VERSION 5.8 ;
BUSBITCHARS "[]" ;
DIVIDERCHAR "/" ;
UNITS
    DATABASE MICRONS 1000 ;
END UNITS

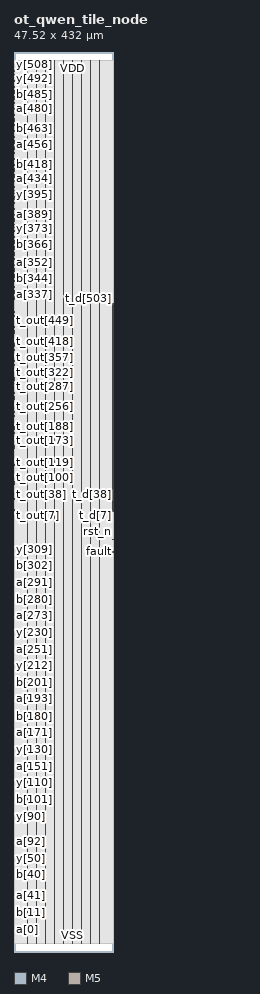
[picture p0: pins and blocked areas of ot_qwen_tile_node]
MACRO ot_qwen_tile_node
  FOREIGN ot_qwen_tile_node 0 0 ;
  CLASS BLOCK ;
  SIZE 47.52 BY 432 ;
  PIN a[0]
    DIRECTION INPUT ;
    USE SIGNAL ;
    PORT
      LAYER M4 ;
        RECT  0 10.896 0.084 10.92 ;
    END
  END a[0]
  PIN a[100]
    DIRECTION INPUT ;
    USE SIGNAL ;
    PORT
      LAYER M4 ;
        RECT  0 66.96 0.084 66.984 ;
    END
  END a[100]
  PIN a[101]
    DIRECTION INPUT ;
    USE SIGNAL ;
    PORT
      LAYER M4 ;
        RECT  0 67.152 0.084 67.176 ;
    END
  END a[101]
  PIN a[102]
    DIRECTION INPUT ;
    USE SIGNAL ;
    PORT
      LAYER M4 ;
        RECT  0 67.344 0.084 67.368 ;
    END
  END a[102]
  PIN a[103]
    DIRECTION INPUT ;
    USE SIGNAL ;
    PORT
      LAYER M4 ;
        RECT  0 67.536 0.084 67.56 ;
    END
  END a[103]
  PIN a[104]
    DIRECTION INPUT ;
    USE SIGNAL ;
    PORT
      LAYER M4 ;
        RECT  0 67.728 0.084 67.752 ;
    END
  END a[104]
  PIN a[105]
    DIRECTION INPUT ;
    USE SIGNAL ;
    PORT
      LAYER M4 ;
        RECT  0 67.92 0.084 67.944 ;
    END
  END a[105]
  PIN a[106]
    DIRECTION INPUT ;
    USE SIGNAL ;
    PORT
      LAYER M4 ;
        RECT  0 68.112 0.084 68.136 ;
    END
  END a[106]
  PIN a[107]
    DIRECTION INPUT ;
    USE SIGNAL ;
    PORT
      LAYER M4 ;
        RECT  0 68.304 0.084 68.328 ;
    END
  END a[107]
  PIN a[108]
    DIRECTION INPUT ;
    USE SIGNAL ;
    PORT
      LAYER M4 ;
        RECT  0 68.496 0.084 68.52 ;
    END
  END a[108]
  PIN a[109]
    DIRECTION INPUT ;
    USE SIGNAL ;
    PORT
      LAYER M4 ;
        RECT  0 68.688 0.084 68.712 ;
    END
  END a[109]
  PIN a[10]
    DIRECTION INPUT ;
    USE SIGNAL ;
    PORT
      LAYER M4 ;
        RECT  0 12.816 0.084 12.84 ;
    END
  END a[10]
  PIN a[110]
    DIRECTION INPUT ;
    USE SIGNAL ;
    PORT
      LAYER M4 ;
        RECT  0 68.88 0.084 68.904 ;
    END
  END a[110]
  PIN a[111]
    DIRECTION INPUT ;
    USE SIGNAL ;
    PORT
      LAYER M4 ;
        RECT  0 69.072 0.084 69.096 ;
    END
  END a[111]
  PIN a[112]
    DIRECTION INPUT ;
    USE SIGNAL ;
    PORT
      LAYER M4 ;
        RECT  0 69.264 0.084 69.288 ;
    END
  END a[112]
  PIN a[113]
    DIRECTION INPUT ;
    USE SIGNAL ;
    PORT
      LAYER M4 ;
        RECT  0 69.456 0.084 69.48 ;
    END
  END a[113]
  PIN a[114]
    DIRECTION INPUT ;
    USE SIGNAL ;
    PORT
      LAYER M4 ;
        RECT  0 69.648 0.084 69.672 ;
    END
  END a[114]
  PIN a[115]
    DIRECTION INPUT ;
    USE SIGNAL ;
    PORT
      LAYER M4 ;
        RECT  0 69.84 0.084 69.864 ;
    END
  END a[115]
  PIN a[116]
    DIRECTION INPUT ;
    USE SIGNAL ;
    PORT
      LAYER M4 ;
        RECT  0 70.032 0.084 70.056 ;
    END
  END a[116]
  PIN a[117]
    DIRECTION INPUT ;
    USE SIGNAL ;
    PORT
      LAYER M4 ;
        RECT  0 70.224 0.084 70.248 ;
    END
  END a[117]
  PIN a[118]
    DIRECTION INPUT ;
    USE SIGNAL ;
    PORT
      LAYER M4 ;
        RECT  0 70.416 0.084 70.44 ;
    END
  END a[118]
  PIN a[119]
    DIRECTION INPUT ;
    USE SIGNAL ;
    PORT
      LAYER M4 ;
        RECT  0 70.608 0.084 70.632 ;
    END
  END a[119]
  PIN a[11]
    DIRECTION INPUT ;
    USE SIGNAL ;
    PORT
      LAYER M4 ;
        RECT  0 13.008 0.084 13.032 ;
    END
  END a[11]
  PIN a[120]
    DIRECTION INPUT ;
    USE SIGNAL ;
    PORT
      LAYER M4 ;
        RECT  0 70.8 0.084 70.824 ;
    END
  END a[120]
  PIN a[121]
    DIRECTION INPUT ;
    USE SIGNAL ;
    PORT
      LAYER M4 ;
        RECT  0 70.992 0.084 71.016 ;
    END
  END a[121]
  PIN a[122]
    DIRECTION INPUT ;
    USE SIGNAL ;
    PORT
      LAYER M4 ;
        RECT  0 71.184 0.084 71.208 ;
    END
  END a[122]
  PIN a[123]
    DIRECTION INPUT ;
    USE SIGNAL ;
    PORT
      LAYER M4 ;
        RECT  0 71.376 0.084 71.4 ;
    END
  END a[123]
  PIN a[124]
    DIRECTION INPUT ;
    USE SIGNAL ;
    PORT
      LAYER M4 ;
        RECT  0 71.568 0.084 71.592 ;
    END
  END a[124]
  PIN a[125]
    DIRECTION INPUT ;
    USE SIGNAL ;
    PORT
      LAYER M4 ;
        RECT  0 71.76 0.084 71.784 ;
    END
  END a[125]
  PIN a[126]
    DIRECTION INPUT ;
    USE SIGNAL ;
    PORT
      LAYER M4 ;
        RECT  0 71.952 0.084 71.976 ;
    END
  END a[126]
  PIN a[127]
    DIRECTION INPUT ;
    USE SIGNAL ;
    PORT
      LAYER M4 ;
        RECT  0 72.144 0.084 72.168 ;
    END
  END a[127]
  PIN a[128]
    DIRECTION INPUT ;
    USE SIGNAL ;
    PORT
      LAYER M4 ;
        RECT  0 84.624 0.084 84.648 ;
    END
  END a[128]
  PIN a[129]
    DIRECTION INPUT ;
    USE SIGNAL ;
    PORT
      LAYER M4 ;
        RECT  0 84.816 0.084 84.84 ;
    END
  END a[129]
  PIN a[12]
    DIRECTION INPUT ;
    USE SIGNAL ;
    PORT
      LAYER M4 ;
        RECT  0 13.2 0.084 13.224 ;
    END
  END a[12]
  PIN a[130]
    DIRECTION INPUT ;
    USE SIGNAL ;
    PORT
      LAYER M4 ;
        RECT  0 85.008 0.084 85.032 ;
    END
  END a[130]
  PIN a[131]
    DIRECTION INPUT ;
    USE SIGNAL ;
    PORT
      LAYER M4 ;
        RECT  0 85.2 0.084 85.224 ;
    END
  END a[131]
  PIN a[132]
    DIRECTION INPUT ;
    USE SIGNAL ;
    PORT
      LAYER M4 ;
        RECT  0 85.392 0.084 85.416 ;
    END
  END a[132]
  PIN a[133]
    DIRECTION INPUT ;
    USE SIGNAL ;
    PORT
      LAYER M4 ;
        RECT  0 85.584 0.084 85.608 ;
    END
  END a[133]
  PIN a[134]
    DIRECTION INPUT ;
    USE SIGNAL ;
    PORT
      LAYER M4 ;
        RECT  0 85.776 0.084 85.8 ;
    END
  END a[134]
  PIN a[135]
    DIRECTION INPUT ;
    USE SIGNAL ;
    PORT
      LAYER M4 ;
        RECT  0 85.968 0.084 85.992 ;
    END
  END a[135]
  PIN a[136]
    DIRECTION INPUT ;
    USE SIGNAL ;
    PORT
      LAYER M4 ;
        RECT  0 86.16 0.084 86.184 ;
    END
  END a[136]
  PIN a[137]
    DIRECTION INPUT ;
    USE SIGNAL ;
    PORT
      LAYER M4 ;
        RECT  0 86.352 0.084 86.376 ;
    END
  END a[137]
  PIN a[138]
    DIRECTION INPUT ;
    USE SIGNAL ;
    PORT
      LAYER M4 ;
        RECT  0 86.544 0.084 86.568 ;
    END
  END a[138]
  PIN a[139]
    DIRECTION INPUT ;
    USE SIGNAL ;
    PORT
      LAYER M4 ;
        RECT  0 86.736 0.084 86.76 ;
    END
  END a[139]
  PIN a[13]
    DIRECTION INPUT ;
    USE SIGNAL ;
    PORT
      LAYER M4 ;
        RECT  0 13.392 0.084 13.416 ;
    END
  END a[13]
  PIN a[140]
    DIRECTION INPUT ;
    USE SIGNAL ;
    PORT
      LAYER M4 ;
        RECT  0 86.928 0.084 86.952 ;
    END
  END a[140]
  PIN a[141]
    DIRECTION INPUT ;
    USE SIGNAL ;
    PORT
      LAYER M4 ;
        RECT  0 87.12 0.084 87.144 ;
    END
  END a[141]
  PIN a[142]
    DIRECTION INPUT ;
    USE SIGNAL ;
    PORT
      LAYER M4 ;
        RECT  0 87.312 0.084 87.336 ;
    END
  END a[142]
  PIN a[143]
    DIRECTION INPUT ;
    USE SIGNAL ;
    PORT
      LAYER M4 ;
        RECT  0 87.504 0.084 87.528 ;
    END
  END a[143]
  PIN a[144]
    DIRECTION INPUT ;
    USE SIGNAL ;
    PORT
      LAYER M4 ;
        RECT  0 87.696 0.084 87.72 ;
    END
  END a[144]
  PIN a[145]
    DIRECTION INPUT ;
    USE SIGNAL ;
    PORT
      LAYER M4 ;
        RECT  0 87.888 0.084 87.912 ;
    END
  END a[145]
  PIN a[146]
    DIRECTION INPUT ;
    USE SIGNAL ;
    PORT
      LAYER M4 ;
        RECT  0 88.08 0.084 88.104 ;
    END
  END a[146]
  PIN a[147]
    DIRECTION INPUT ;
    USE SIGNAL ;
    PORT
      LAYER M4 ;
        RECT  0 88.272 0.084 88.296 ;
    END
  END a[147]
  PIN a[148]
    DIRECTION INPUT ;
    USE SIGNAL ;
    PORT
      LAYER M4 ;
        RECT  0 88.464 0.084 88.488 ;
    END
  END a[148]
  PIN a[149]
    DIRECTION INPUT ;
    USE SIGNAL ;
    PORT
      LAYER M4 ;
        RECT  0 88.656 0.084 88.68 ;
    END
  END a[149]
  PIN a[14]
    DIRECTION INPUT ;
    USE SIGNAL ;
    PORT
      LAYER M4 ;
        RECT  0 13.584 0.084 13.608 ;
    END
  END a[14]
  PIN a[150]
    DIRECTION INPUT ;
    USE SIGNAL ;
    PORT
      LAYER M4 ;
        RECT  0 88.848 0.084 88.872 ;
    END
  END a[150]
  PIN a[151]
    DIRECTION INPUT ;
    USE SIGNAL ;
    PORT
      LAYER M4 ;
        RECT  0 89.04 0.084 89.064 ;
    END
  END a[151]
  PIN a[152]
    DIRECTION INPUT ;
    USE SIGNAL ;
    PORT
      LAYER M4 ;
        RECT  0 89.232 0.084 89.256 ;
    END
  END a[152]
  PIN a[153]
    DIRECTION INPUT ;
    USE SIGNAL ;
    PORT
      LAYER M4 ;
        RECT  0 89.424 0.084 89.448 ;
    END
  END a[153]
  PIN a[154]
    DIRECTION INPUT ;
    USE SIGNAL ;
    PORT
      LAYER M4 ;
        RECT  0 89.616 0.084 89.64 ;
    END
  END a[154]
  PIN a[155]
    DIRECTION INPUT ;
    USE SIGNAL ;
    PORT
      LAYER M4 ;
        RECT  0 89.808 0.084 89.832 ;
    END
  END a[155]
  PIN a[156]
    DIRECTION INPUT ;
    USE SIGNAL ;
    PORT
      LAYER M4 ;
        RECT  0 90 0.084 90.024 ;
    END
  END a[156]
  PIN a[157]
    DIRECTION INPUT ;
    USE SIGNAL ;
    PORT
      LAYER M4 ;
        RECT  0 90.192 0.084 90.216 ;
    END
  END a[157]
  PIN a[158]
    DIRECTION INPUT ;
    USE SIGNAL ;
    PORT
      LAYER M4 ;
        RECT  0 90.384 0.084 90.408 ;
    END
  END a[158]
  PIN a[159]
    DIRECTION INPUT ;
    USE SIGNAL ;
    PORT
      LAYER M4 ;
        RECT  0 90.576 0.084 90.6 ;
    END
  END a[159]
  PIN a[15]
    DIRECTION INPUT ;
    USE SIGNAL ;
    PORT
      LAYER M4 ;
        RECT  0 13.776 0.084 13.8 ;
    END
  END a[15]
  PIN a[160]
    DIRECTION INPUT ;
    USE SIGNAL ;
    PORT
      LAYER M4 ;
        RECT  0 103.056 0.084 103.08 ;
    END
  END a[160]
  PIN a[161]
    DIRECTION INPUT ;
    USE SIGNAL ;
    PORT
      LAYER M4 ;
        RECT  0 103.248 0.084 103.272 ;
    END
  END a[161]
  PIN a[162]
    DIRECTION INPUT ;
    USE SIGNAL ;
    PORT
      LAYER M4 ;
        RECT  0 103.44 0.084 103.464 ;
    END
  END a[162]
  PIN a[163]
    DIRECTION INPUT ;
    USE SIGNAL ;
    PORT
      LAYER M4 ;
        RECT  0 103.632 0.084 103.656 ;
    END
  END a[163]
  PIN a[164]
    DIRECTION INPUT ;
    USE SIGNAL ;
    PORT
      LAYER M4 ;
        RECT  0 103.824 0.084 103.848 ;
    END
  END a[164]
  PIN a[165]
    DIRECTION INPUT ;
    USE SIGNAL ;
    PORT
      LAYER M4 ;
        RECT  0 104.016 0.084 104.04 ;
    END
  END a[165]
  PIN a[166]
    DIRECTION INPUT ;
    USE SIGNAL ;
    PORT
      LAYER M4 ;
        RECT  0 104.208 0.084 104.232 ;
    END
  END a[166]
  PIN a[167]
    DIRECTION INPUT ;
    USE SIGNAL ;
    PORT
      LAYER M4 ;
        RECT  0 104.4 0.084 104.424 ;
    END
  END a[167]
  PIN a[168]
    DIRECTION INPUT ;
    USE SIGNAL ;
    PORT
      LAYER M4 ;
        RECT  0 104.592 0.084 104.616 ;
    END
  END a[168]
  PIN a[169]
    DIRECTION INPUT ;
    USE SIGNAL ;
    PORT
      LAYER M4 ;
        RECT  0 104.784 0.084 104.808 ;
    END
  END a[169]
  PIN a[16]
    DIRECTION INPUT ;
    USE SIGNAL ;
    PORT
      LAYER M4 ;
        RECT  0 13.968 0.084 13.992 ;
    END
  END a[16]
  PIN a[170]
    DIRECTION INPUT ;
    USE SIGNAL ;
    PORT
      LAYER M4 ;
        RECT  0 104.976 0.084 105 ;
    END
  END a[170]
  PIN a[171]
    DIRECTION INPUT ;
    USE SIGNAL ;
    PORT
      LAYER M4 ;
        RECT  0 105.168 0.084 105.192 ;
    END
  END a[171]
  PIN a[172]
    DIRECTION INPUT ;
    USE SIGNAL ;
    PORT
      LAYER M4 ;
        RECT  0 105.36 0.084 105.384 ;
    END
  END a[172]
  PIN a[173]
    DIRECTION INPUT ;
    USE SIGNAL ;
    PORT
      LAYER M4 ;
        RECT  0 105.552 0.084 105.576 ;
    END
  END a[173]
  PIN a[174]
    DIRECTION INPUT ;
    USE SIGNAL ;
    PORT
      LAYER M4 ;
        RECT  0 105.744 0.084 105.768 ;
    END
  END a[174]
  PIN a[175]
    DIRECTION INPUT ;
    USE SIGNAL ;
    PORT
      LAYER M4 ;
        RECT  0 105.936 0.084 105.96 ;
    END
  END a[175]
  PIN a[176]
    DIRECTION INPUT ;
    USE SIGNAL ;
    PORT
      LAYER M4 ;
        RECT  0 106.128 0.084 106.152 ;
    END
  END a[176]
  PIN a[177]
    DIRECTION INPUT ;
    USE SIGNAL ;
    PORT
      LAYER M4 ;
        RECT  0 106.32 0.084 106.344 ;
    END
  END a[177]
  PIN a[178]
    DIRECTION INPUT ;
    USE SIGNAL ;
    PORT
      LAYER M4 ;
        RECT  0 106.512 0.084 106.536 ;
    END
  END a[178]
  PIN a[179]
    DIRECTION INPUT ;
    USE SIGNAL ;
    PORT
      LAYER M4 ;
        RECT  0 106.704 0.084 106.728 ;
    END
  END a[179]
  PIN a[17]
    DIRECTION INPUT ;
    USE SIGNAL ;
    PORT
      LAYER M4 ;
        RECT  0 14.16 0.084 14.184 ;
    END
  END a[17]
  PIN a[180]
    DIRECTION INPUT ;
    USE SIGNAL ;
    PORT
      LAYER M4 ;
        RECT  0 106.896 0.084 106.92 ;
    END
  END a[180]
  PIN a[181]
    DIRECTION INPUT ;
    USE SIGNAL ;
    PORT
      LAYER M4 ;
        RECT  0 107.088 0.084 107.112 ;
    END
  END a[181]
  PIN a[182]
    DIRECTION INPUT ;
    USE SIGNAL ;
    PORT
      LAYER M4 ;
        RECT  0 107.28 0.084 107.304 ;
    END
  END a[182]
  PIN a[183]
    DIRECTION INPUT ;
    USE SIGNAL ;
    PORT
      LAYER M4 ;
        RECT  0 107.472 0.084 107.496 ;
    END
  END a[183]
  PIN a[184]
    DIRECTION INPUT ;
    USE SIGNAL ;
    PORT
      LAYER M4 ;
        RECT  0 107.664 0.084 107.688 ;
    END
  END a[184]
  PIN a[185]
    DIRECTION INPUT ;
    USE SIGNAL ;
    PORT
      LAYER M4 ;
        RECT  0 107.856 0.084 107.88 ;
    END
  END a[185]
  PIN a[186]
    DIRECTION INPUT ;
    USE SIGNAL ;
    PORT
      LAYER M4 ;
        RECT  0 108.048 0.084 108.072 ;
    END
  END a[186]
  PIN a[187]
    DIRECTION INPUT ;
    USE SIGNAL ;
    PORT
      LAYER M4 ;
        RECT  0 108.24 0.084 108.264 ;
    END
  END a[187]
  PIN a[188]
    DIRECTION INPUT ;
    USE SIGNAL ;
    PORT
      LAYER M4 ;
        RECT  0 108.432 0.084 108.456 ;
    END
  END a[188]
  PIN a[189]
    DIRECTION INPUT ;
    USE SIGNAL ;
    PORT
      LAYER M4 ;
        RECT  0 108.624 0.084 108.648 ;
    END
  END a[189]
  PIN a[18]
    DIRECTION INPUT ;
    USE SIGNAL ;
    PORT
      LAYER M4 ;
        RECT  0 14.352 0.084 14.376 ;
    END
  END a[18]
  PIN a[190]
    DIRECTION INPUT ;
    USE SIGNAL ;
    PORT
      LAYER M4 ;
        RECT  0 108.816 0.084 108.84 ;
    END
  END a[190]
  PIN a[191]
    DIRECTION INPUT ;
    USE SIGNAL ;
    PORT
      LAYER M4 ;
        RECT  0 109.008 0.084 109.032 ;
    END
  END a[191]
  PIN a[192]
    DIRECTION INPUT ;
    USE SIGNAL ;
    PORT
      LAYER M4 ;
        RECT  0 121.488 0.084 121.512 ;
    END
  END a[192]
  PIN a[193]
    DIRECTION INPUT ;
    USE SIGNAL ;
    PORT
      LAYER M4 ;
        RECT  0 121.68 0.084 121.704 ;
    END
  END a[193]
  PIN a[194]
    DIRECTION INPUT ;
    USE SIGNAL ;
    PORT
      LAYER M4 ;
        RECT  0 121.872 0.084 121.896 ;
    END
  END a[194]
  PIN a[195]
    DIRECTION INPUT ;
    USE SIGNAL ;
    PORT
      LAYER M4 ;
        RECT  0 122.064 0.084 122.088 ;
    END
  END a[195]
  PIN a[196]
    DIRECTION INPUT ;
    USE SIGNAL ;
    PORT
      LAYER M4 ;
        RECT  0 122.256 0.084 122.28 ;
    END
  END a[196]
  PIN a[197]
    DIRECTION INPUT ;
    USE SIGNAL ;
    PORT
      LAYER M4 ;
        RECT  0 122.448 0.084 122.472 ;
    END
  END a[197]
  PIN a[198]
    DIRECTION INPUT ;
    USE SIGNAL ;
    PORT
      LAYER M4 ;
        RECT  0 122.64 0.084 122.664 ;
    END
  END a[198]
  PIN a[199]
    DIRECTION INPUT ;
    USE SIGNAL ;
    PORT
      LAYER M4 ;
        RECT  0 122.832 0.084 122.856 ;
    END
  END a[199]
  PIN a[19]
    DIRECTION INPUT ;
    USE SIGNAL ;
    PORT
      LAYER M4 ;
        RECT  0 14.544 0.084 14.568 ;
    END
  END a[19]
  PIN a[1]
    DIRECTION INPUT ;
    USE SIGNAL ;
    PORT
      LAYER M4 ;
        RECT  0 11.088 0.084 11.112 ;
    END
  END a[1]
  PIN a[200]
    DIRECTION INPUT ;
    USE SIGNAL ;
    PORT
      LAYER M4 ;
        RECT  0 123.024 0.084 123.048 ;
    END
  END a[200]
  PIN a[201]
    DIRECTION INPUT ;
    USE SIGNAL ;
    PORT
      LAYER M4 ;
        RECT  0 123.216 0.084 123.24 ;
    END
  END a[201]
  PIN a[202]
    DIRECTION INPUT ;
    USE SIGNAL ;
    PORT
      LAYER M4 ;
        RECT  0 123.408 0.084 123.432 ;
    END
  END a[202]
  PIN a[203]
    DIRECTION INPUT ;
    USE SIGNAL ;
    PORT
      LAYER M4 ;
        RECT  0 123.6 0.084 123.624 ;
    END
  END a[203]
  PIN a[204]
    DIRECTION INPUT ;
    USE SIGNAL ;
    PORT
      LAYER M4 ;
        RECT  0 123.792 0.084 123.816 ;
    END
  END a[204]
  PIN a[205]
    DIRECTION INPUT ;
    USE SIGNAL ;
    PORT
      LAYER M4 ;
        RECT  0 123.984 0.084 124.008 ;
    END
  END a[205]
  PIN a[206]
    DIRECTION INPUT ;
    USE SIGNAL ;
    PORT
      LAYER M4 ;
        RECT  0 124.176 0.084 124.2 ;
    END
  END a[206]
  PIN a[207]
    DIRECTION INPUT ;
    USE SIGNAL ;
    PORT
      LAYER M4 ;
        RECT  0 124.368 0.084 124.392 ;
    END
  END a[207]
  PIN a[208]
    DIRECTION INPUT ;
    USE SIGNAL ;
    PORT
      LAYER M4 ;
        RECT  0 124.56 0.084 124.584 ;
    END
  END a[208]
  PIN a[209]
    DIRECTION INPUT ;
    USE SIGNAL ;
    PORT
      LAYER M4 ;
        RECT  0 124.752 0.084 124.776 ;
    END
  END a[209]
  PIN a[20]
    DIRECTION INPUT ;
    USE SIGNAL ;
    PORT
      LAYER M4 ;
        RECT  0 14.736 0.084 14.76 ;
    END
  END a[20]
  PIN a[210]
    DIRECTION INPUT ;
    USE SIGNAL ;
    PORT
      LAYER M4 ;
        RECT  0 124.944 0.084 124.968 ;
    END
  END a[210]
  PIN a[211]
    DIRECTION INPUT ;
    USE SIGNAL ;
    PORT
      LAYER M4 ;
        RECT  0 125.136 0.084 125.16 ;
    END
  END a[211]
  PIN a[212]
    DIRECTION INPUT ;
    USE SIGNAL ;
    PORT
      LAYER M4 ;
        RECT  0 125.328 0.084 125.352 ;
    END
  END a[212]
  PIN a[213]
    DIRECTION INPUT ;
    USE SIGNAL ;
    PORT
      LAYER M4 ;
        RECT  0 125.52 0.084 125.544 ;
    END
  END a[213]
  PIN a[214]
    DIRECTION INPUT ;
    USE SIGNAL ;
    PORT
      LAYER M4 ;
        RECT  0 125.712 0.084 125.736 ;
    END
  END a[214]
  PIN a[215]
    DIRECTION INPUT ;
    USE SIGNAL ;
    PORT
      LAYER M4 ;
        RECT  0 125.904 0.084 125.928 ;
    END
  END a[215]
  PIN a[216]
    DIRECTION INPUT ;
    USE SIGNAL ;
    PORT
      LAYER M4 ;
        RECT  0 126.096 0.084 126.12 ;
    END
  END a[216]
  PIN a[217]
    DIRECTION INPUT ;
    USE SIGNAL ;
    PORT
      LAYER M4 ;
        RECT  0 126.288 0.084 126.312 ;
    END
  END a[217]
  PIN a[218]
    DIRECTION INPUT ;
    USE SIGNAL ;
    PORT
      LAYER M4 ;
        RECT  0 126.48 0.084 126.504 ;
    END
  END a[218]
  PIN a[219]
    DIRECTION INPUT ;
    USE SIGNAL ;
    PORT
      LAYER M4 ;
        RECT  0 126.672 0.084 126.696 ;
    END
  END a[219]
  PIN a[21]
    DIRECTION INPUT ;
    USE SIGNAL ;
    PORT
      LAYER M4 ;
        RECT  0 14.928 0.084 14.952 ;
    END
  END a[21]
  PIN a[220]
    DIRECTION INPUT ;
    USE SIGNAL ;
    PORT
      LAYER M4 ;
        RECT  0 126.864 0.084 126.888 ;
    END
  END a[220]
  PIN a[221]
    DIRECTION INPUT ;
    USE SIGNAL ;
    PORT
      LAYER M4 ;
        RECT  0 127.056 0.084 127.08 ;
    END
  END a[221]
  PIN a[222]
    DIRECTION INPUT ;
    USE SIGNAL ;
    PORT
      LAYER M4 ;
        RECT  0 127.248 0.084 127.272 ;
    END
  END a[222]
  PIN a[223]
    DIRECTION INPUT ;
    USE SIGNAL ;
    PORT
      LAYER M4 ;
        RECT  0 127.44 0.084 127.464 ;
    END
  END a[223]
  PIN a[224]
    DIRECTION INPUT ;
    USE SIGNAL ;
    PORT
      LAYER M4 ;
        RECT  0 139.92 0.084 139.944 ;
    END
  END a[224]
  PIN a[225]
    DIRECTION INPUT ;
    USE SIGNAL ;
    PORT
      LAYER M4 ;
        RECT  0 140.112 0.084 140.136 ;
    END
  END a[225]
  PIN a[226]
    DIRECTION INPUT ;
    USE SIGNAL ;
    PORT
      LAYER M4 ;
        RECT  0 140.304 0.084 140.328 ;
    END
  END a[226]
  PIN a[227]
    DIRECTION INPUT ;
    USE SIGNAL ;
    PORT
      LAYER M4 ;
        RECT  0 140.496 0.084 140.52 ;
    END
  END a[227]
  PIN a[228]
    DIRECTION INPUT ;
    USE SIGNAL ;
    PORT
      LAYER M4 ;
        RECT  0 140.688 0.084 140.712 ;
    END
  END a[228]
  PIN a[229]
    DIRECTION INPUT ;
    USE SIGNAL ;
    PORT
      LAYER M4 ;
        RECT  0 140.88 0.084 140.904 ;
    END
  END a[229]
  PIN a[22]
    DIRECTION INPUT ;
    USE SIGNAL ;
    PORT
      LAYER M4 ;
        RECT  0 15.12 0.084 15.144 ;
    END
  END a[22]
  PIN a[230]
    DIRECTION INPUT ;
    USE SIGNAL ;
    PORT
      LAYER M4 ;
        RECT  0 141.072 0.084 141.096 ;
    END
  END a[230]
  PIN a[231]
    DIRECTION INPUT ;
    USE SIGNAL ;
    PORT
      LAYER M4 ;
        RECT  0 141.264 0.084 141.288 ;
    END
  END a[231]
  PIN a[232]
    DIRECTION INPUT ;
    USE SIGNAL ;
    PORT
      LAYER M4 ;
        RECT  0 141.456 0.084 141.48 ;
    END
  END a[232]
  PIN a[233]
    DIRECTION INPUT ;
    USE SIGNAL ;
    PORT
      LAYER M4 ;
        RECT  0 141.648 0.084 141.672 ;
    END
  END a[233]
  PIN a[234]
    DIRECTION INPUT ;
    USE SIGNAL ;
    PORT
      LAYER M4 ;
        RECT  0 141.84 0.084 141.864 ;
    END
  END a[234]
  PIN a[235]
    DIRECTION INPUT ;
    USE SIGNAL ;
    PORT
      LAYER M4 ;
        RECT  0 142.032 0.084 142.056 ;
    END
  END a[235]
  PIN a[236]
    DIRECTION INPUT ;
    USE SIGNAL ;
    PORT
      LAYER M4 ;
        RECT  0 142.224 0.084 142.248 ;
    END
  END a[236]
  PIN a[237]
    DIRECTION INPUT ;
    USE SIGNAL ;
    PORT
      LAYER M4 ;
        RECT  0 142.416 0.084 142.44 ;
    END
  END a[237]
  PIN a[238]
    DIRECTION INPUT ;
    USE SIGNAL ;
    PORT
      LAYER M4 ;
        RECT  0 142.608 0.084 142.632 ;
    END
  END a[238]
  PIN a[239]
    DIRECTION INPUT ;
    USE SIGNAL ;
    PORT
      LAYER M4 ;
        RECT  0 142.8 0.084 142.824 ;
    END
  END a[239]
  PIN a[23]
    DIRECTION INPUT ;
    USE SIGNAL ;
    PORT
      LAYER M4 ;
        RECT  0 15.312 0.084 15.336 ;
    END
  END a[23]
  PIN a[240]
    DIRECTION INPUT ;
    USE SIGNAL ;
    PORT
      LAYER M4 ;
        RECT  0 142.992 0.084 143.016 ;
    END
  END a[240]
  PIN a[241]
    DIRECTION INPUT ;
    USE SIGNAL ;
    PORT
      LAYER M4 ;
        RECT  0 143.184 0.084 143.208 ;
    END
  END a[241]
  PIN a[242]
    DIRECTION INPUT ;
    USE SIGNAL ;
    PORT
      LAYER M4 ;
        RECT  0 143.376 0.084 143.4 ;
    END
  END a[242]
  PIN a[243]
    DIRECTION INPUT ;
    USE SIGNAL ;
    PORT
      LAYER M4 ;
        RECT  0 143.568 0.084 143.592 ;
    END
  END a[243]
  PIN a[244]
    DIRECTION INPUT ;
    USE SIGNAL ;
    PORT
      LAYER M4 ;
        RECT  0 143.76 0.084 143.784 ;
    END
  END a[244]
  PIN a[245]
    DIRECTION INPUT ;
    USE SIGNAL ;
    PORT
      LAYER M4 ;
        RECT  0 143.952 0.084 143.976 ;
    END
  END a[245]
  PIN a[246]
    DIRECTION INPUT ;
    USE SIGNAL ;
    PORT
      LAYER M4 ;
        RECT  0 144.144 0.084 144.168 ;
    END
  END a[246]
  PIN a[247]
    DIRECTION INPUT ;
    USE SIGNAL ;
    PORT
      LAYER M4 ;
        RECT  0 144.336 0.084 144.36 ;
    END
  END a[247]
  PIN a[248]
    DIRECTION INPUT ;
    USE SIGNAL ;
    PORT
      LAYER M4 ;
        RECT  0 144.528 0.084 144.552 ;
    END
  END a[248]
  PIN a[249]
    DIRECTION INPUT ;
    USE SIGNAL ;
    PORT
      LAYER M4 ;
        RECT  0 144.72 0.084 144.744 ;
    END
  END a[249]
  PIN a[24]
    DIRECTION INPUT ;
    USE SIGNAL ;
    PORT
      LAYER M4 ;
        RECT  0 15.504 0.084 15.528 ;
    END
  END a[24]
  PIN a[250]
    DIRECTION INPUT ;
    USE SIGNAL ;
    PORT
      LAYER M4 ;
        RECT  0 144.912 0.084 144.936 ;
    END
  END a[250]
  PIN a[251]
    DIRECTION INPUT ;
    USE SIGNAL ;
    PORT
      LAYER M4 ;
        RECT  0 145.104 0.084 145.128 ;
    END
  END a[251]
  PIN a[252]
    DIRECTION INPUT ;
    USE SIGNAL ;
    PORT
      LAYER M4 ;
        RECT  0 145.296 0.084 145.32 ;
    END
  END a[252]
  PIN a[253]
    DIRECTION INPUT ;
    USE SIGNAL ;
    PORT
      LAYER M4 ;
        RECT  0 145.488 0.084 145.512 ;
    END
  END a[253]
  PIN a[254]
    DIRECTION INPUT ;
    USE SIGNAL ;
    PORT
      LAYER M4 ;
        RECT  0 145.68 0.084 145.704 ;
    END
  END a[254]
  PIN a[255]
    DIRECTION INPUT ;
    USE SIGNAL ;
    PORT
      LAYER M4 ;
        RECT  0 145.872 0.084 145.896 ;
    END
  END a[255]
  PIN a[256]
    DIRECTION INPUT ;
    USE SIGNAL ;
    PORT
      LAYER M4 ;
        RECT  0 158.352 0.084 158.376 ;
    END
  END a[256]
  PIN a[257]
    DIRECTION INPUT ;
    USE SIGNAL ;
    PORT
      LAYER M4 ;
        RECT  0 158.544 0.084 158.568 ;
    END
  END a[257]
  PIN a[258]
    DIRECTION INPUT ;
    USE SIGNAL ;
    PORT
      LAYER M4 ;
        RECT  0 158.736 0.084 158.76 ;
    END
  END a[258]
  PIN a[259]
    DIRECTION INPUT ;
    USE SIGNAL ;
    PORT
      LAYER M4 ;
        RECT  0 158.928 0.084 158.952 ;
    END
  END a[259]
  PIN a[25]
    DIRECTION INPUT ;
    USE SIGNAL ;
    PORT
      LAYER M4 ;
        RECT  0 15.696 0.084 15.72 ;
    END
  END a[25]
  PIN a[260]
    DIRECTION INPUT ;
    USE SIGNAL ;
    PORT
      LAYER M4 ;
        RECT  0 159.12 0.084 159.144 ;
    END
  END a[260]
  PIN a[261]
    DIRECTION INPUT ;
    USE SIGNAL ;
    PORT
      LAYER M4 ;
        RECT  0 159.312 0.084 159.336 ;
    END
  END a[261]
  PIN a[262]
    DIRECTION INPUT ;
    USE SIGNAL ;
    PORT
      LAYER M4 ;
        RECT  0 159.504 0.084 159.528 ;
    END
  END a[262]
  PIN a[263]
    DIRECTION INPUT ;
    USE SIGNAL ;
    PORT
      LAYER M4 ;
        RECT  0 159.696 0.084 159.72 ;
    END
  END a[263]
  PIN a[264]
    DIRECTION INPUT ;
    USE SIGNAL ;
    PORT
      LAYER M4 ;
        RECT  0 159.888 0.084 159.912 ;
    END
  END a[264]
  PIN a[265]
    DIRECTION INPUT ;
    USE SIGNAL ;
    PORT
      LAYER M4 ;
        RECT  0 160.08 0.084 160.104 ;
    END
  END a[265]
  PIN a[266]
    DIRECTION INPUT ;
    USE SIGNAL ;
    PORT
      LAYER M4 ;
        RECT  0 160.272 0.084 160.296 ;
    END
  END a[266]
  PIN a[267]
    DIRECTION INPUT ;
    USE SIGNAL ;
    PORT
      LAYER M4 ;
        RECT  0 160.464 0.084 160.488 ;
    END
  END a[267]
  PIN a[268]
    DIRECTION INPUT ;
    USE SIGNAL ;
    PORT
      LAYER M4 ;
        RECT  0 160.656 0.084 160.68 ;
    END
  END a[268]
  PIN a[269]
    DIRECTION INPUT ;
    USE SIGNAL ;
    PORT
      LAYER M4 ;
        RECT  0 160.848 0.084 160.872 ;
    END
  END a[269]
  PIN a[26]
    DIRECTION INPUT ;
    USE SIGNAL ;
    PORT
      LAYER M4 ;
        RECT  0 15.888 0.084 15.912 ;
    END
  END a[26]
  PIN a[270]
    DIRECTION INPUT ;
    USE SIGNAL ;
    PORT
      LAYER M4 ;
        RECT  0 161.04 0.084 161.064 ;
    END
  END a[270]
  PIN a[271]
    DIRECTION INPUT ;
    USE SIGNAL ;
    PORT
      LAYER M4 ;
        RECT  0 161.232 0.084 161.256 ;
    END
  END a[271]
  PIN a[272]
    DIRECTION INPUT ;
    USE SIGNAL ;
    PORT
      LAYER M4 ;
        RECT  0 161.424 0.084 161.448 ;
    END
  END a[272]
  PIN a[273]
    DIRECTION INPUT ;
    USE SIGNAL ;
    PORT
      LAYER M4 ;
        RECT  0 161.616 0.084 161.64 ;
    END
  END a[273]
  PIN a[274]
    DIRECTION INPUT ;
    USE SIGNAL ;
    PORT
      LAYER M4 ;
        RECT  0 161.808 0.084 161.832 ;
    END
  END a[274]
  PIN a[275]
    DIRECTION INPUT ;
    USE SIGNAL ;
    PORT
      LAYER M4 ;
        RECT  0 162 0.084 162.024 ;
    END
  END a[275]
  PIN a[276]
    DIRECTION INPUT ;
    USE SIGNAL ;
    PORT
      LAYER M4 ;
        RECT  0 162.192 0.084 162.216 ;
    END
  END a[276]
  PIN a[277]
    DIRECTION INPUT ;
    USE SIGNAL ;
    PORT
      LAYER M4 ;
        RECT  0 162.384 0.084 162.408 ;
    END
  END a[277]
  PIN a[278]
    DIRECTION INPUT ;
    USE SIGNAL ;
    PORT
      LAYER M4 ;
        RECT  0 162.576 0.084 162.6 ;
    END
  END a[278]
  PIN a[279]
    DIRECTION INPUT ;
    USE SIGNAL ;
    PORT
      LAYER M4 ;
        RECT  0 162.768 0.084 162.792 ;
    END
  END a[279]
  PIN a[27]
    DIRECTION INPUT ;
    USE SIGNAL ;
    PORT
      LAYER M4 ;
        RECT  0 16.08 0.084 16.104 ;
    END
  END a[27]
  PIN a[280]
    DIRECTION INPUT ;
    USE SIGNAL ;
    PORT
      LAYER M4 ;
        RECT  0 162.96 0.084 162.984 ;
    END
  END a[280]
  PIN a[281]
    DIRECTION INPUT ;
    USE SIGNAL ;
    PORT
      LAYER M4 ;
        RECT  0 163.152 0.084 163.176 ;
    END
  END a[281]
  PIN a[282]
    DIRECTION INPUT ;
    USE SIGNAL ;
    PORT
      LAYER M4 ;
        RECT  0 163.344 0.084 163.368 ;
    END
  END a[282]
  PIN a[283]
    DIRECTION INPUT ;
    USE SIGNAL ;
    PORT
      LAYER M4 ;
        RECT  0 163.536 0.084 163.56 ;
    END
  END a[283]
  PIN a[284]
    DIRECTION INPUT ;
    USE SIGNAL ;
    PORT
      LAYER M4 ;
        RECT  0 163.728 0.084 163.752 ;
    END
  END a[284]
  PIN a[285]
    DIRECTION INPUT ;
    USE SIGNAL ;
    PORT
      LAYER M4 ;
        RECT  0 163.92 0.084 163.944 ;
    END
  END a[285]
  PIN a[286]
    DIRECTION INPUT ;
    USE SIGNAL ;
    PORT
      LAYER M4 ;
        RECT  0 164.112 0.084 164.136 ;
    END
  END a[286]
  PIN a[287]
    DIRECTION INPUT ;
    USE SIGNAL ;
    PORT
      LAYER M4 ;
        RECT  0 164.304 0.084 164.328 ;
    END
  END a[287]
  PIN a[288]
    DIRECTION INPUT ;
    USE SIGNAL ;
    PORT
      LAYER M4 ;
        RECT  0 176.784 0.084 176.808 ;
    END
  END a[288]
  PIN a[289]
    DIRECTION INPUT ;
    USE SIGNAL ;
    PORT
      LAYER M4 ;
        RECT  0 176.976 0.084 177 ;
    END
  END a[289]
  PIN a[28]
    DIRECTION INPUT ;
    USE SIGNAL ;
    PORT
      LAYER M4 ;
        RECT  0 16.272 0.084 16.296 ;
    END
  END a[28]
  PIN a[290]
    DIRECTION INPUT ;
    USE SIGNAL ;
    PORT
      LAYER M4 ;
        RECT  0 177.168 0.084 177.192 ;
    END
  END a[290]
  PIN a[291]
    DIRECTION INPUT ;
    USE SIGNAL ;
    PORT
      LAYER M4 ;
        RECT  0 177.36 0.084 177.384 ;
    END
  END a[291]
  PIN a[292]
    DIRECTION INPUT ;
    USE SIGNAL ;
    PORT
      LAYER M4 ;
        RECT  0 177.552 0.084 177.576 ;
    END
  END a[292]
  PIN a[293]
    DIRECTION INPUT ;
    USE SIGNAL ;
    PORT
      LAYER M4 ;
        RECT  0 177.744 0.084 177.768 ;
    END
  END a[293]
  PIN a[294]
    DIRECTION INPUT ;
    USE SIGNAL ;
    PORT
      LAYER M4 ;
        RECT  0 177.936 0.084 177.96 ;
    END
  END a[294]
  PIN a[295]
    DIRECTION INPUT ;
    USE SIGNAL ;
    PORT
      LAYER M4 ;
        RECT  0 178.128 0.084 178.152 ;
    END
  END a[295]
  PIN a[296]
    DIRECTION INPUT ;
    USE SIGNAL ;
    PORT
      LAYER M4 ;
        RECT  0 178.32 0.084 178.344 ;
    END
  END a[296]
  PIN a[297]
    DIRECTION INPUT ;
    USE SIGNAL ;
    PORT
      LAYER M4 ;
        RECT  0 178.512 0.084 178.536 ;
    END
  END a[297]
  PIN a[298]
    DIRECTION INPUT ;
    USE SIGNAL ;
    PORT
      LAYER M4 ;
        RECT  0 178.704 0.084 178.728 ;
    END
  END a[298]
  PIN a[299]
    DIRECTION INPUT ;
    USE SIGNAL ;
    PORT
      LAYER M4 ;
        RECT  0 178.896 0.084 178.92 ;
    END
  END a[299]
  PIN a[29]
    DIRECTION INPUT ;
    USE SIGNAL ;
    PORT
      LAYER M4 ;
        RECT  0 16.464 0.084 16.488 ;
    END
  END a[29]
  PIN a[2]
    DIRECTION INPUT ;
    USE SIGNAL ;
    PORT
      LAYER M4 ;
        RECT  0 11.28 0.084 11.304 ;
    END
  END a[2]
  PIN a[300]
    DIRECTION INPUT ;
    USE SIGNAL ;
    PORT
      LAYER M4 ;
        RECT  0 179.088 0.084 179.112 ;
    END
  END a[300]
  PIN a[301]
    DIRECTION INPUT ;
    USE SIGNAL ;
    PORT
      LAYER M4 ;
        RECT  0 179.28 0.084 179.304 ;
    END
  END a[301]
  PIN a[302]
    DIRECTION INPUT ;
    USE SIGNAL ;
    PORT
      LAYER M4 ;
        RECT  0 179.472 0.084 179.496 ;
    END
  END a[302]
  PIN a[303]
    DIRECTION INPUT ;
    USE SIGNAL ;
    PORT
      LAYER M4 ;
        RECT  0 179.664 0.084 179.688 ;
    END
  END a[303]
  PIN a[304]
    DIRECTION INPUT ;
    USE SIGNAL ;
    PORT
      LAYER M4 ;
        RECT  0 179.856 0.084 179.88 ;
    END
  END a[304]
  PIN a[305]
    DIRECTION INPUT ;
    USE SIGNAL ;
    PORT
      LAYER M4 ;
        RECT  0 180.048 0.084 180.072 ;
    END
  END a[305]
  PIN a[306]
    DIRECTION INPUT ;
    USE SIGNAL ;
    PORT
      LAYER M4 ;
        RECT  0 180.24 0.084 180.264 ;
    END
  END a[306]
  PIN a[307]
    DIRECTION INPUT ;
    USE SIGNAL ;
    PORT
      LAYER M4 ;
        RECT  0 180.432 0.084 180.456 ;
    END
  END a[307]
  PIN a[308]
    DIRECTION INPUT ;
    USE SIGNAL ;
    PORT
      LAYER M4 ;
        RECT  0 180.624 0.084 180.648 ;
    END
  END a[308]
  PIN a[309]
    DIRECTION INPUT ;
    USE SIGNAL ;
    PORT
      LAYER M4 ;
        RECT  0 180.816 0.084 180.84 ;
    END
  END a[309]
  PIN a[30]
    DIRECTION INPUT ;
    USE SIGNAL ;
    PORT
      LAYER M4 ;
        RECT  0 16.656 0.084 16.68 ;
    END
  END a[30]
  PIN a[310]
    DIRECTION INPUT ;
    USE SIGNAL ;
    PORT
      LAYER M4 ;
        RECT  0 181.008 0.084 181.032 ;
    END
  END a[310]
  PIN a[311]
    DIRECTION INPUT ;
    USE SIGNAL ;
    PORT
      LAYER M4 ;
        RECT  0 181.2 0.084 181.224 ;
    END
  END a[311]
  PIN a[312]
    DIRECTION INPUT ;
    USE SIGNAL ;
    PORT
      LAYER M4 ;
        RECT  0 181.392 0.084 181.416 ;
    END
  END a[312]
  PIN a[313]
    DIRECTION INPUT ;
    USE SIGNAL ;
    PORT
      LAYER M4 ;
        RECT  0 181.584 0.084 181.608 ;
    END
  END a[313]
  PIN a[314]
    DIRECTION INPUT ;
    USE SIGNAL ;
    PORT
      LAYER M4 ;
        RECT  0 181.776 0.084 181.8 ;
    END
  END a[314]
  PIN a[315]
    DIRECTION INPUT ;
    USE SIGNAL ;
    PORT
      LAYER M4 ;
        RECT  0 181.968 0.084 181.992 ;
    END
  END a[315]
  PIN a[316]
    DIRECTION INPUT ;
    USE SIGNAL ;
    PORT
      LAYER M4 ;
        RECT  0 182.16 0.084 182.184 ;
    END
  END a[316]
  PIN a[317]
    DIRECTION INPUT ;
    USE SIGNAL ;
    PORT
      LAYER M4 ;
        RECT  0 182.352 0.084 182.376 ;
    END
  END a[317]
  PIN a[318]
    DIRECTION INPUT ;
    USE SIGNAL ;
    PORT
      LAYER M4 ;
        RECT  0 182.544 0.084 182.568 ;
    END
  END a[318]
  PIN a[319]
    DIRECTION INPUT ;
    USE SIGNAL ;
    PORT
      LAYER M4 ;
        RECT  0 182.736 0.084 182.76 ;
    END
  END a[319]
  PIN a[31]
    DIRECTION INPUT ;
    USE SIGNAL ;
    PORT
      LAYER M4 ;
        RECT  0 16.848 0.084 16.872 ;
    END
  END a[31]
  PIN a[320]
    DIRECTION INPUT ;
    USE SIGNAL ;
    PORT
      LAYER M4 ;
        RECT  0 312.48 0.084 312.504 ;
    END
  END a[320]
  PIN a[321]
    DIRECTION INPUT ;
    USE SIGNAL ;
    PORT
      LAYER M4 ;
        RECT  0 312.672 0.084 312.696 ;
    END
  END a[321]
  PIN a[322]
    DIRECTION INPUT ;
    USE SIGNAL ;
    PORT
      LAYER M4 ;
        RECT  0 312.864 0.084 312.888 ;
    END
  END a[322]
  PIN a[323]
    DIRECTION INPUT ;
    USE SIGNAL ;
    PORT
      LAYER M4 ;
        RECT  0 313.056 0.084 313.08 ;
    END
  END a[323]
  PIN a[324]
    DIRECTION INPUT ;
    USE SIGNAL ;
    PORT
      LAYER M4 ;
        RECT  0 313.248 0.084 313.272 ;
    END
  END a[324]
  PIN a[325]
    DIRECTION INPUT ;
    USE SIGNAL ;
    PORT
      LAYER M4 ;
        RECT  0 313.44 0.084 313.464 ;
    END
  END a[325]
  PIN a[326]
    DIRECTION INPUT ;
    USE SIGNAL ;
    PORT
      LAYER M4 ;
        RECT  0 313.632 0.084 313.656 ;
    END
  END a[326]
  PIN a[327]
    DIRECTION INPUT ;
    USE SIGNAL ;
    PORT
      LAYER M4 ;
        RECT  0 313.824 0.084 313.848 ;
    END
  END a[327]
  PIN a[328]
    DIRECTION INPUT ;
    USE SIGNAL ;
    PORT
      LAYER M4 ;
        RECT  0 314.016 0.084 314.04 ;
    END
  END a[328]
  PIN a[329]
    DIRECTION INPUT ;
    USE SIGNAL ;
    PORT
      LAYER M4 ;
        RECT  0 314.208 0.084 314.232 ;
    END
  END a[329]
  PIN a[32]
    DIRECTION INPUT ;
    USE SIGNAL ;
    PORT
      LAYER M4 ;
        RECT  0 29.328 0.084 29.352 ;
    END
  END a[32]
  PIN a[330]
    DIRECTION INPUT ;
    USE SIGNAL ;
    PORT
      LAYER M4 ;
        RECT  0 314.4 0.084 314.424 ;
    END
  END a[330]
  PIN a[331]
    DIRECTION INPUT ;
    USE SIGNAL ;
    PORT
      LAYER M4 ;
        RECT  0 314.592 0.084 314.616 ;
    END
  END a[331]
  PIN a[332]
    DIRECTION INPUT ;
    USE SIGNAL ;
    PORT
      LAYER M4 ;
        RECT  0 314.784 0.084 314.808 ;
    END
  END a[332]
  PIN a[333]
    DIRECTION INPUT ;
    USE SIGNAL ;
    PORT
      LAYER M4 ;
        RECT  0 314.976 0.084 315 ;
    END
  END a[333]
  PIN a[334]
    DIRECTION INPUT ;
    USE SIGNAL ;
    PORT
      LAYER M4 ;
        RECT  0 315.168 0.084 315.192 ;
    END
  END a[334]
  PIN a[335]
    DIRECTION INPUT ;
    USE SIGNAL ;
    PORT
      LAYER M4 ;
        RECT  0 315.36 0.084 315.384 ;
    END
  END a[335]
  PIN a[336]
    DIRECTION INPUT ;
    USE SIGNAL ;
    PORT
      LAYER M4 ;
        RECT  0 315.552 0.084 315.576 ;
    END
  END a[336]
  PIN a[337]
    DIRECTION INPUT ;
    USE SIGNAL ;
    PORT
      LAYER M4 ;
        RECT  0 315.744 0.084 315.768 ;
    END
  END a[337]
  PIN a[338]
    DIRECTION INPUT ;
    USE SIGNAL ;
    PORT
      LAYER M4 ;
        RECT  0 315.936 0.084 315.96 ;
    END
  END a[338]
  PIN a[339]
    DIRECTION INPUT ;
    USE SIGNAL ;
    PORT
      LAYER M4 ;
        RECT  0 316.128 0.084 316.152 ;
    END
  END a[339]
  PIN a[33]
    DIRECTION INPUT ;
    USE SIGNAL ;
    PORT
      LAYER M4 ;
        RECT  0 29.52 0.084 29.544 ;
    END
  END a[33]
  PIN a[340]
    DIRECTION INPUT ;
    USE SIGNAL ;
    PORT
      LAYER M4 ;
        RECT  0 316.32 0.084 316.344 ;
    END
  END a[340]
  PIN a[341]
    DIRECTION INPUT ;
    USE SIGNAL ;
    PORT
      LAYER M4 ;
        RECT  0 316.512 0.084 316.536 ;
    END
  END a[341]
  PIN a[342]
    DIRECTION INPUT ;
    USE SIGNAL ;
    PORT
      LAYER M4 ;
        RECT  0 316.704 0.084 316.728 ;
    END
  END a[342]
  PIN a[343]
    DIRECTION INPUT ;
    USE SIGNAL ;
    PORT
      LAYER M4 ;
        RECT  0 316.896 0.084 316.92 ;
    END
  END a[343]
  PIN a[344]
    DIRECTION INPUT ;
    USE SIGNAL ;
    PORT
      LAYER M4 ;
        RECT  0 317.088 0.084 317.112 ;
    END
  END a[344]
  PIN a[345]
    DIRECTION INPUT ;
    USE SIGNAL ;
    PORT
      LAYER M4 ;
        RECT  0 317.28 0.084 317.304 ;
    END
  END a[345]
  PIN a[346]
    DIRECTION INPUT ;
    USE SIGNAL ;
    PORT
      LAYER M4 ;
        RECT  0 317.472 0.084 317.496 ;
    END
  END a[346]
  PIN a[347]
    DIRECTION INPUT ;
    USE SIGNAL ;
    PORT
      LAYER M4 ;
        RECT  0 317.664 0.084 317.688 ;
    END
  END a[347]
  PIN a[348]
    DIRECTION INPUT ;
    USE SIGNAL ;
    PORT
      LAYER M4 ;
        RECT  0 317.856 0.084 317.88 ;
    END
  END a[348]
  PIN a[349]
    DIRECTION INPUT ;
    USE SIGNAL ;
    PORT
      LAYER M4 ;
        RECT  0 318.048 0.084 318.072 ;
    END
  END a[349]
  PIN a[34]
    DIRECTION INPUT ;
    USE SIGNAL ;
    PORT
      LAYER M4 ;
        RECT  0 29.712 0.084 29.736 ;
    END
  END a[34]
  PIN a[350]
    DIRECTION INPUT ;
    USE SIGNAL ;
    PORT
      LAYER M4 ;
        RECT  0 318.24 0.084 318.264 ;
    END
  END a[350]
  PIN a[351]
    DIRECTION INPUT ;
    USE SIGNAL ;
    PORT
      LAYER M4 ;
        RECT  0 318.432 0.084 318.456 ;
    END
  END a[351]
  PIN a[352]
    DIRECTION INPUT ;
    USE SIGNAL ;
    PORT
      LAYER M4 ;
        RECT  0 330.912 0.084 330.936 ;
    END
  END a[352]
  PIN a[353]
    DIRECTION INPUT ;
    USE SIGNAL ;
    PORT
      LAYER M4 ;
        RECT  0 331.104 0.084 331.128 ;
    END
  END a[353]
  PIN a[354]
    DIRECTION INPUT ;
    USE SIGNAL ;
    PORT
      LAYER M4 ;
        RECT  0 331.296 0.084 331.32 ;
    END
  END a[354]
  PIN a[355]
    DIRECTION INPUT ;
    USE SIGNAL ;
    PORT
      LAYER M4 ;
        RECT  0 331.488 0.084 331.512 ;
    END
  END a[355]
  PIN a[356]
    DIRECTION INPUT ;
    USE SIGNAL ;
    PORT
      LAYER M4 ;
        RECT  0 331.68 0.084 331.704 ;
    END
  END a[356]
  PIN a[357]
    DIRECTION INPUT ;
    USE SIGNAL ;
    PORT
      LAYER M4 ;
        RECT  0 331.872 0.084 331.896 ;
    END
  END a[357]
  PIN a[358]
    DIRECTION INPUT ;
    USE SIGNAL ;
    PORT
      LAYER M4 ;
        RECT  0 332.064 0.084 332.088 ;
    END
  END a[358]
  PIN a[359]
    DIRECTION INPUT ;
    USE SIGNAL ;
    PORT
      LAYER M4 ;
        RECT  0 332.256 0.084 332.28 ;
    END
  END a[359]
  PIN a[35]
    DIRECTION INPUT ;
    USE SIGNAL ;
    PORT
      LAYER M4 ;
        RECT  0 29.904 0.084 29.928 ;
    END
  END a[35]
  PIN a[360]
    DIRECTION INPUT ;
    USE SIGNAL ;
    PORT
      LAYER M4 ;
        RECT  0 332.448 0.084 332.472 ;
    END
  END a[360]
  PIN a[361]
    DIRECTION INPUT ;
    USE SIGNAL ;
    PORT
      LAYER M4 ;
        RECT  0 332.64 0.084 332.664 ;
    END
  END a[361]
  PIN a[362]
    DIRECTION INPUT ;
    USE SIGNAL ;
    PORT
      LAYER M4 ;
        RECT  0 332.832 0.084 332.856 ;
    END
  END a[362]
  PIN a[363]
    DIRECTION INPUT ;
    USE SIGNAL ;
    PORT
      LAYER M4 ;
        RECT  0 333.024 0.084 333.048 ;
    END
  END a[363]
  PIN a[364]
    DIRECTION INPUT ;
    USE SIGNAL ;
    PORT
      LAYER M4 ;
        RECT  0 333.216 0.084 333.24 ;
    END
  END a[364]
  PIN a[365]
    DIRECTION INPUT ;
    USE SIGNAL ;
    PORT
      LAYER M4 ;
        RECT  0 333.408 0.084 333.432 ;
    END
  END a[365]
  PIN a[366]
    DIRECTION INPUT ;
    USE SIGNAL ;
    PORT
      LAYER M4 ;
        RECT  0 333.6 0.084 333.624 ;
    END
  END a[366]
  PIN a[367]
    DIRECTION INPUT ;
    USE SIGNAL ;
    PORT
      LAYER M4 ;
        RECT  0 333.792 0.084 333.816 ;
    END
  END a[367]
  PIN a[368]
    DIRECTION INPUT ;
    USE SIGNAL ;
    PORT
      LAYER M4 ;
        RECT  0 333.984 0.084 334.008 ;
    END
  END a[368]
  PIN a[369]
    DIRECTION INPUT ;
    USE SIGNAL ;
    PORT
      LAYER M4 ;
        RECT  0 334.176 0.084 334.2 ;
    END
  END a[369]
  PIN a[36]
    DIRECTION INPUT ;
    USE SIGNAL ;
    PORT
      LAYER M4 ;
        RECT  0 30.096 0.084 30.12 ;
    END
  END a[36]
  PIN a[370]
    DIRECTION INPUT ;
    USE SIGNAL ;
    PORT
      LAYER M4 ;
        RECT  0 334.368 0.084 334.392 ;
    END
  END a[370]
  PIN a[371]
    DIRECTION INPUT ;
    USE SIGNAL ;
    PORT
      LAYER M4 ;
        RECT  0 334.56 0.084 334.584 ;
    END
  END a[371]
  PIN a[372]
    DIRECTION INPUT ;
    USE SIGNAL ;
    PORT
      LAYER M4 ;
        RECT  0 334.752 0.084 334.776 ;
    END
  END a[372]
  PIN a[373]
    DIRECTION INPUT ;
    USE SIGNAL ;
    PORT
      LAYER M4 ;
        RECT  0 334.944 0.084 334.968 ;
    END
  END a[373]
  PIN a[374]
    DIRECTION INPUT ;
    USE SIGNAL ;
    PORT
      LAYER M4 ;
        RECT  0 335.136 0.084 335.16 ;
    END
  END a[374]
  PIN a[375]
    DIRECTION INPUT ;
    USE SIGNAL ;
    PORT
      LAYER M4 ;
        RECT  0 335.328 0.084 335.352 ;
    END
  END a[375]
  PIN a[376]
    DIRECTION INPUT ;
    USE SIGNAL ;
    PORT
      LAYER M4 ;
        RECT  0 335.52 0.084 335.544 ;
    END
  END a[376]
  PIN a[377]
    DIRECTION INPUT ;
    USE SIGNAL ;
    PORT
      LAYER M4 ;
        RECT  0 335.712 0.084 335.736 ;
    END
  END a[377]
  PIN a[378]
    DIRECTION INPUT ;
    USE SIGNAL ;
    PORT
      LAYER M4 ;
        RECT  0 335.904 0.084 335.928 ;
    END
  END a[378]
  PIN a[379]
    DIRECTION INPUT ;
    USE SIGNAL ;
    PORT
      LAYER M4 ;
        RECT  0 336.096 0.084 336.12 ;
    END
  END a[379]
  PIN a[37]
    DIRECTION INPUT ;
    USE SIGNAL ;
    PORT
      LAYER M4 ;
        RECT  0 30.288 0.084 30.312 ;
    END
  END a[37]
  PIN a[380]
    DIRECTION INPUT ;
    USE SIGNAL ;
    PORT
      LAYER M4 ;
        RECT  0 336.288 0.084 336.312 ;
    END
  END a[380]
  PIN a[381]
    DIRECTION INPUT ;
    USE SIGNAL ;
    PORT
      LAYER M4 ;
        RECT  0 336.48 0.084 336.504 ;
    END
  END a[381]
  PIN a[382]
    DIRECTION INPUT ;
    USE SIGNAL ;
    PORT
      LAYER M4 ;
        RECT  0 336.672 0.084 336.696 ;
    END
  END a[382]
  PIN a[383]
    DIRECTION INPUT ;
    USE SIGNAL ;
    PORT
      LAYER M4 ;
        RECT  0 336.864 0.084 336.888 ;
    END
  END a[383]
  PIN a[384]
    DIRECTION INPUT ;
    USE SIGNAL ;
    PORT
      LAYER M4 ;
        RECT  0 349.344 0.084 349.368 ;
    END
  END a[384]
  PIN a[385]
    DIRECTION INPUT ;
    USE SIGNAL ;
    PORT
      LAYER M4 ;
        RECT  0 349.536 0.084 349.56 ;
    END
  END a[385]
  PIN a[386]
    DIRECTION INPUT ;
    USE SIGNAL ;
    PORT
      LAYER M4 ;
        RECT  0 349.728 0.084 349.752 ;
    END
  END a[386]
  PIN a[387]
    DIRECTION INPUT ;
    USE SIGNAL ;
    PORT
      LAYER M4 ;
        RECT  0 349.92 0.084 349.944 ;
    END
  END a[387]
  PIN a[388]
    DIRECTION INPUT ;
    USE SIGNAL ;
    PORT
      LAYER M4 ;
        RECT  0 350.112 0.084 350.136 ;
    END
  END a[388]
  PIN a[389]
    DIRECTION INPUT ;
    USE SIGNAL ;
    PORT
      LAYER M4 ;
        RECT  0 350.304 0.084 350.328 ;
    END
  END a[389]
  PIN a[38]
    DIRECTION INPUT ;
    USE SIGNAL ;
    PORT
      LAYER M4 ;
        RECT  0 30.48 0.084 30.504 ;
    END
  END a[38]
  PIN a[390]
    DIRECTION INPUT ;
    USE SIGNAL ;
    PORT
      LAYER M4 ;
        RECT  0 350.496 0.084 350.52 ;
    END
  END a[390]
  PIN a[391]
    DIRECTION INPUT ;
    USE SIGNAL ;
    PORT
      LAYER M4 ;
        RECT  0 350.688 0.084 350.712 ;
    END
  END a[391]
  PIN a[392]
    DIRECTION INPUT ;
    USE SIGNAL ;
    PORT
      LAYER M4 ;
        RECT  0 350.88 0.084 350.904 ;
    END
  END a[392]
  PIN a[393]
    DIRECTION INPUT ;
    USE SIGNAL ;
    PORT
      LAYER M4 ;
        RECT  0 351.072 0.084 351.096 ;
    END
  END a[393]
  PIN a[394]
    DIRECTION INPUT ;
    USE SIGNAL ;
    PORT
      LAYER M4 ;
        RECT  0 351.264 0.084 351.288 ;
    END
  END a[394]
  PIN a[395]
    DIRECTION INPUT ;
    USE SIGNAL ;
    PORT
      LAYER M4 ;
        RECT  0 351.456 0.084 351.48 ;
    END
  END a[395]
  PIN a[396]
    DIRECTION INPUT ;
    USE SIGNAL ;
    PORT
      LAYER M4 ;
        RECT  0 351.648 0.084 351.672 ;
    END
  END a[396]
  PIN a[397]
    DIRECTION INPUT ;
    USE SIGNAL ;
    PORT
      LAYER M4 ;
        RECT  0 351.84 0.084 351.864 ;
    END
  END a[397]
  PIN a[398]
    DIRECTION INPUT ;
    USE SIGNAL ;
    PORT
      LAYER M4 ;
        RECT  0 352.032 0.084 352.056 ;
    END
  END a[398]
  PIN a[399]
    DIRECTION INPUT ;
    USE SIGNAL ;
    PORT
      LAYER M4 ;
        RECT  0 352.224 0.084 352.248 ;
    END
  END a[399]
  PIN a[39]
    DIRECTION INPUT ;
    USE SIGNAL ;
    PORT
      LAYER M4 ;
        RECT  0 30.672 0.084 30.696 ;
    END
  END a[39]
  PIN a[3]
    DIRECTION INPUT ;
    USE SIGNAL ;
    PORT
      LAYER M4 ;
        RECT  0 11.472 0.084 11.496 ;
    END
  END a[3]
  PIN a[400]
    DIRECTION INPUT ;
    USE SIGNAL ;
    PORT
      LAYER M4 ;
        RECT  0 352.416 0.084 352.44 ;
    END
  END a[400]
  PIN a[401]
    DIRECTION INPUT ;
    USE SIGNAL ;
    PORT
      LAYER M4 ;
        RECT  0 352.608 0.084 352.632 ;
    END
  END a[401]
  PIN a[402]
    DIRECTION INPUT ;
    USE SIGNAL ;
    PORT
      LAYER M4 ;
        RECT  0 352.8 0.084 352.824 ;
    END
  END a[402]
  PIN a[403]
    DIRECTION INPUT ;
    USE SIGNAL ;
    PORT
      LAYER M4 ;
        RECT  0 352.992 0.084 353.016 ;
    END
  END a[403]
  PIN a[404]
    DIRECTION INPUT ;
    USE SIGNAL ;
    PORT
      LAYER M4 ;
        RECT  0 353.184 0.084 353.208 ;
    END
  END a[404]
  PIN a[405]
    DIRECTION INPUT ;
    USE SIGNAL ;
    PORT
      LAYER M4 ;
        RECT  0 353.376 0.084 353.4 ;
    END
  END a[405]
  PIN a[406]
    DIRECTION INPUT ;
    USE SIGNAL ;
    PORT
      LAYER M4 ;
        RECT  0 353.568 0.084 353.592 ;
    END
  END a[406]
  PIN a[407]
    DIRECTION INPUT ;
    USE SIGNAL ;
    PORT
      LAYER M4 ;
        RECT  0 353.76 0.084 353.784 ;
    END
  END a[407]
  PIN a[408]
    DIRECTION INPUT ;
    USE SIGNAL ;
    PORT
      LAYER M4 ;
        RECT  0 353.952 0.084 353.976 ;
    END
  END a[408]
  PIN a[409]
    DIRECTION INPUT ;
    USE SIGNAL ;
    PORT
      LAYER M4 ;
        RECT  0 354.144 0.084 354.168 ;
    END
  END a[409]
  PIN a[40]
    DIRECTION INPUT ;
    USE SIGNAL ;
    PORT
      LAYER M4 ;
        RECT  0 30.864 0.084 30.888 ;
    END
  END a[40]
  PIN a[410]
    DIRECTION INPUT ;
    USE SIGNAL ;
    PORT
      LAYER M4 ;
        RECT  0 354.336 0.084 354.36 ;
    END
  END a[410]
  PIN a[411]
    DIRECTION INPUT ;
    USE SIGNAL ;
    PORT
      LAYER M4 ;
        RECT  0 354.528 0.084 354.552 ;
    END
  END a[411]
  PIN a[412]
    DIRECTION INPUT ;
    USE SIGNAL ;
    PORT
      LAYER M4 ;
        RECT  0 354.72 0.084 354.744 ;
    END
  END a[412]
  PIN a[413]
    DIRECTION INPUT ;
    USE SIGNAL ;
    PORT
      LAYER M4 ;
        RECT  0 354.912 0.084 354.936 ;
    END
  END a[413]
  PIN a[414]
    DIRECTION INPUT ;
    USE SIGNAL ;
    PORT
      LAYER M4 ;
        RECT  0 355.104 0.084 355.128 ;
    END
  END a[414]
  PIN a[415]
    DIRECTION INPUT ;
    USE SIGNAL ;
    PORT
      LAYER M4 ;
        RECT  0 355.296 0.084 355.32 ;
    END
  END a[415]
  PIN a[416]
    DIRECTION INPUT ;
    USE SIGNAL ;
    PORT
      LAYER M4 ;
        RECT  0 367.776 0.084 367.8 ;
    END
  END a[416]
  PIN a[417]
    DIRECTION INPUT ;
    USE SIGNAL ;
    PORT
      LAYER M4 ;
        RECT  0 367.968 0.084 367.992 ;
    END
  END a[417]
  PIN a[418]
    DIRECTION INPUT ;
    USE SIGNAL ;
    PORT
      LAYER M4 ;
        RECT  0 368.16 0.084 368.184 ;
    END
  END a[418]
  PIN a[419]
    DIRECTION INPUT ;
    USE SIGNAL ;
    PORT
      LAYER M4 ;
        RECT  0 368.352 0.084 368.376 ;
    END
  END a[419]
  PIN a[41]
    DIRECTION INPUT ;
    USE SIGNAL ;
    PORT
      LAYER M4 ;
        RECT  0 31.056 0.084 31.08 ;
    END
  END a[41]
  PIN a[420]
    DIRECTION INPUT ;
    USE SIGNAL ;
    PORT
      LAYER M4 ;
        RECT  0 368.544 0.084 368.568 ;
    END
  END a[420]
  PIN a[421]
    DIRECTION INPUT ;
    USE SIGNAL ;
    PORT
      LAYER M4 ;
        RECT  0 368.736 0.084 368.76 ;
    END
  END a[421]
  PIN a[422]
    DIRECTION INPUT ;
    USE SIGNAL ;
    PORT
      LAYER M4 ;
        RECT  0 368.928 0.084 368.952 ;
    END
  END a[422]
  PIN a[423]
    DIRECTION INPUT ;
    USE SIGNAL ;
    PORT
      LAYER M4 ;
        RECT  0 369.12 0.084 369.144 ;
    END
  END a[423]
  PIN a[424]
    DIRECTION INPUT ;
    USE SIGNAL ;
    PORT
      LAYER M4 ;
        RECT  0 369.312 0.084 369.336 ;
    END
  END a[424]
  PIN a[425]
    DIRECTION INPUT ;
    USE SIGNAL ;
    PORT
      LAYER M4 ;
        RECT  0 369.504 0.084 369.528 ;
    END
  END a[425]
  PIN a[426]
    DIRECTION INPUT ;
    USE SIGNAL ;
    PORT
      LAYER M4 ;
        RECT  0 369.696 0.084 369.72 ;
    END
  END a[426]
  PIN a[427]
    DIRECTION INPUT ;
    USE SIGNAL ;
    PORT
      LAYER M4 ;
        RECT  0 369.888 0.084 369.912 ;
    END
  END a[427]
  PIN a[428]
    DIRECTION INPUT ;
    USE SIGNAL ;
    PORT
      LAYER M4 ;
        RECT  0 370.08 0.084 370.104 ;
    END
  END a[428]
  PIN a[429]
    DIRECTION INPUT ;
    USE SIGNAL ;
    PORT
      LAYER M4 ;
        RECT  0 370.272 0.084 370.296 ;
    END
  END a[429]
  PIN a[42]
    DIRECTION INPUT ;
    USE SIGNAL ;
    PORT
      LAYER M4 ;
        RECT  0 31.248 0.084 31.272 ;
    END
  END a[42]
  PIN a[430]
    DIRECTION INPUT ;
    USE SIGNAL ;
    PORT
      LAYER M4 ;
        RECT  0 370.464 0.084 370.488 ;
    END
  END a[430]
  PIN a[431]
    DIRECTION INPUT ;
    USE SIGNAL ;
    PORT
      LAYER M4 ;
        RECT  0 370.656 0.084 370.68 ;
    END
  END a[431]
  PIN a[432]
    DIRECTION INPUT ;
    USE SIGNAL ;
    PORT
      LAYER M4 ;
        RECT  0 370.848 0.084 370.872 ;
    END
  END a[432]
  PIN a[433]
    DIRECTION INPUT ;
    USE SIGNAL ;
    PORT
      LAYER M4 ;
        RECT  0 371.04 0.084 371.064 ;
    END
  END a[433]
  PIN a[434]
    DIRECTION INPUT ;
    USE SIGNAL ;
    PORT
      LAYER M4 ;
        RECT  0 371.232 0.084 371.256 ;
    END
  END a[434]
  PIN a[435]
    DIRECTION INPUT ;
    USE SIGNAL ;
    PORT
      LAYER M4 ;
        RECT  0 371.424 0.084 371.448 ;
    END
  END a[435]
  PIN a[436]
    DIRECTION INPUT ;
    USE SIGNAL ;
    PORT
      LAYER M4 ;
        RECT  0 371.616 0.084 371.64 ;
    END
  END a[436]
  PIN a[437]
    DIRECTION INPUT ;
    USE SIGNAL ;
    PORT
      LAYER M4 ;
        RECT  0 371.808 0.084 371.832 ;
    END
  END a[437]
  PIN a[438]
    DIRECTION INPUT ;
    USE SIGNAL ;
    PORT
      LAYER M4 ;
        RECT  0 372 0.084 372.024 ;
    END
  END a[438]
  PIN a[439]
    DIRECTION INPUT ;
    USE SIGNAL ;
    PORT
      LAYER M4 ;
        RECT  0 372.192 0.084 372.216 ;
    END
  END a[439]
  PIN a[43]
    DIRECTION INPUT ;
    USE SIGNAL ;
    PORT
      LAYER M4 ;
        RECT  0 31.44 0.084 31.464 ;
    END
  END a[43]
  PIN a[440]
    DIRECTION INPUT ;
    USE SIGNAL ;
    PORT
      LAYER M4 ;
        RECT  0 372.384 0.084 372.408 ;
    END
  END a[440]
  PIN a[441]
    DIRECTION INPUT ;
    USE SIGNAL ;
    PORT
      LAYER M4 ;
        RECT  0 372.576 0.084 372.6 ;
    END
  END a[441]
  PIN a[442]
    DIRECTION INPUT ;
    USE SIGNAL ;
    PORT
      LAYER M4 ;
        RECT  0 372.768 0.084 372.792 ;
    END
  END a[442]
  PIN a[443]
    DIRECTION INPUT ;
    USE SIGNAL ;
    PORT
      LAYER M4 ;
        RECT  0 372.96 0.084 372.984 ;
    END
  END a[443]
  PIN a[444]
    DIRECTION INPUT ;
    USE SIGNAL ;
    PORT
      LAYER M4 ;
        RECT  0 373.152 0.084 373.176 ;
    END
  END a[444]
  PIN a[445]
    DIRECTION INPUT ;
    USE SIGNAL ;
    PORT
      LAYER M4 ;
        RECT  0 373.344 0.084 373.368 ;
    END
  END a[445]
  PIN a[446]
    DIRECTION INPUT ;
    USE SIGNAL ;
    PORT
      LAYER M4 ;
        RECT  0 373.536 0.084 373.56 ;
    END
  END a[446]
  PIN a[447]
    DIRECTION INPUT ;
    USE SIGNAL ;
    PORT
      LAYER M4 ;
        RECT  0 373.728 0.084 373.752 ;
    END
  END a[447]
  PIN a[448]
    DIRECTION INPUT ;
    USE SIGNAL ;
    PORT
      LAYER M4 ;
        RECT  0 386.208 0.084 386.232 ;
    END
  END a[448]
  PIN a[449]
    DIRECTION INPUT ;
    USE SIGNAL ;
    PORT
      LAYER M4 ;
        RECT  0 386.4 0.084 386.424 ;
    END
  END a[449]
  PIN a[44]
    DIRECTION INPUT ;
    USE SIGNAL ;
    PORT
      LAYER M4 ;
        RECT  0 31.632 0.084 31.656 ;
    END
  END a[44]
  PIN a[450]
    DIRECTION INPUT ;
    USE SIGNAL ;
    PORT
      LAYER M4 ;
        RECT  0 386.592 0.084 386.616 ;
    END
  END a[450]
  PIN a[451]
    DIRECTION INPUT ;
    USE SIGNAL ;
    PORT
      LAYER M4 ;
        RECT  0 386.784 0.084 386.808 ;
    END
  END a[451]
  PIN a[452]
    DIRECTION INPUT ;
    USE SIGNAL ;
    PORT
      LAYER M4 ;
        RECT  0 386.976 0.084 387 ;
    END
  END a[452]
  PIN a[453]
    DIRECTION INPUT ;
    USE SIGNAL ;
    PORT
      LAYER M4 ;
        RECT  0 387.168 0.084 387.192 ;
    END
  END a[453]
  PIN a[454]
    DIRECTION INPUT ;
    USE SIGNAL ;
    PORT
      LAYER M4 ;
        RECT  0 387.36 0.084 387.384 ;
    END
  END a[454]
  PIN a[455]
    DIRECTION INPUT ;
    USE SIGNAL ;
    PORT
      LAYER M4 ;
        RECT  0 387.552 0.084 387.576 ;
    END
  END a[455]
  PIN a[456]
    DIRECTION INPUT ;
    USE SIGNAL ;
    PORT
      LAYER M4 ;
        RECT  0 387.744 0.084 387.768 ;
    END
  END a[456]
  PIN a[457]
    DIRECTION INPUT ;
    USE SIGNAL ;
    PORT
      LAYER M4 ;
        RECT  0 387.936 0.084 387.96 ;
    END
  END a[457]
  PIN a[458]
    DIRECTION INPUT ;
    USE SIGNAL ;
    PORT
      LAYER M4 ;
        RECT  0 388.128 0.084 388.152 ;
    END
  END a[458]
  PIN a[459]
    DIRECTION INPUT ;
    USE SIGNAL ;
    PORT
      LAYER M4 ;
        RECT  0 388.32 0.084 388.344 ;
    END
  END a[459]
  PIN a[45]
    DIRECTION INPUT ;
    USE SIGNAL ;
    PORT
      LAYER M4 ;
        RECT  0 31.824 0.084 31.848 ;
    END
  END a[45]
  PIN a[460]
    DIRECTION INPUT ;
    USE SIGNAL ;
    PORT
      LAYER M4 ;
        RECT  0 388.512 0.084 388.536 ;
    END
  END a[460]
  PIN a[461]
    DIRECTION INPUT ;
    USE SIGNAL ;
    PORT
      LAYER M4 ;
        RECT  0 388.704 0.084 388.728 ;
    END
  END a[461]
  PIN a[462]
    DIRECTION INPUT ;
    USE SIGNAL ;
    PORT
      LAYER M4 ;
        RECT  0 388.896 0.084 388.92 ;
    END
  END a[462]
  PIN a[463]
    DIRECTION INPUT ;
    USE SIGNAL ;
    PORT
      LAYER M4 ;
        RECT  0 389.088 0.084 389.112 ;
    END
  END a[463]
  PIN a[464]
    DIRECTION INPUT ;
    USE SIGNAL ;
    PORT
      LAYER M4 ;
        RECT  0 389.28 0.084 389.304 ;
    END
  END a[464]
  PIN a[465]
    DIRECTION INPUT ;
    USE SIGNAL ;
    PORT
      LAYER M4 ;
        RECT  0 389.472 0.084 389.496 ;
    END
  END a[465]
  PIN a[466]
    DIRECTION INPUT ;
    USE SIGNAL ;
    PORT
      LAYER M4 ;
        RECT  0 389.664 0.084 389.688 ;
    END
  END a[466]
  PIN a[467]
    DIRECTION INPUT ;
    USE SIGNAL ;
    PORT
      LAYER M4 ;
        RECT  0 389.856 0.084 389.88 ;
    END
  END a[467]
  PIN a[468]
    DIRECTION INPUT ;
    USE SIGNAL ;
    PORT
      LAYER M4 ;
        RECT  0 390.048 0.084 390.072 ;
    END
  END a[468]
  PIN a[469]
    DIRECTION INPUT ;
    USE SIGNAL ;
    PORT
      LAYER M4 ;
        RECT  0 390.24 0.084 390.264 ;
    END
  END a[469]
  PIN a[46]
    DIRECTION INPUT ;
    USE SIGNAL ;
    PORT
      LAYER M4 ;
        RECT  0 32.016 0.084 32.04 ;
    END
  END a[46]
  PIN a[470]
    DIRECTION INPUT ;
    USE SIGNAL ;
    PORT
      LAYER M4 ;
        RECT  0 390.432 0.084 390.456 ;
    END
  END a[470]
  PIN a[471]
    DIRECTION INPUT ;
    USE SIGNAL ;
    PORT
      LAYER M4 ;
        RECT  0 390.624 0.084 390.648 ;
    END
  END a[471]
  PIN a[472]
    DIRECTION INPUT ;
    USE SIGNAL ;
    PORT
      LAYER M4 ;
        RECT  0 390.816 0.084 390.84 ;
    END
  END a[472]
  PIN a[473]
    DIRECTION INPUT ;
    USE SIGNAL ;
    PORT
      LAYER M4 ;
        RECT  0 391.008 0.084 391.032 ;
    END
  END a[473]
  PIN a[474]
    DIRECTION INPUT ;
    USE SIGNAL ;
    PORT
      LAYER M4 ;
        RECT  0 391.2 0.084 391.224 ;
    END
  END a[474]
  PIN a[475]
    DIRECTION INPUT ;
    USE SIGNAL ;
    PORT
      LAYER M4 ;
        RECT  0 391.392 0.084 391.416 ;
    END
  END a[475]
  PIN a[476]
    DIRECTION INPUT ;
    USE SIGNAL ;
    PORT
      LAYER M4 ;
        RECT  0 391.584 0.084 391.608 ;
    END
  END a[476]
  PIN a[477]
    DIRECTION INPUT ;
    USE SIGNAL ;
    PORT
      LAYER M4 ;
        RECT  0 391.776 0.084 391.8 ;
    END
  END a[477]
  PIN a[478]
    DIRECTION INPUT ;
    USE SIGNAL ;
    PORT
      LAYER M4 ;
        RECT  0 391.968 0.084 391.992 ;
    END
  END a[478]
  PIN a[479]
    DIRECTION INPUT ;
    USE SIGNAL ;
    PORT
      LAYER M4 ;
        RECT  0 392.16 0.084 392.184 ;
    END
  END a[479]
  PIN a[47]
    DIRECTION INPUT ;
    USE SIGNAL ;
    PORT
      LAYER M4 ;
        RECT  0 32.208 0.084 32.232 ;
    END
  END a[47]
  PIN a[480]
    DIRECTION INPUT ;
    USE SIGNAL ;
    PORT
      LAYER M4 ;
        RECT  0 404.64 0.084 404.664 ;
    END
  END a[480]
  PIN a[481]
    DIRECTION INPUT ;
    USE SIGNAL ;
    PORT
      LAYER M4 ;
        RECT  0 404.832 0.084 404.856 ;
    END
  END a[481]
  PIN a[482]
    DIRECTION INPUT ;
    USE SIGNAL ;
    PORT
      LAYER M4 ;
        RECT  0 405.024 0.084 405.048 ;
    END
  END a[482]
  PIN a[483]
    DIRECTION INPUT ;
    USE SIGNAL ;
    PORT
      LAYER M4 ;
        RECT  0 405.216 0.084 405.24 ;
    END
  END a[483]
  PIN a[484]
    DIRECTION INPUT ;
    USE SIGNAL ;
    PORT
      LAYER M4 ;
        RECT  0 405.408 0.084 405.432 ;
    END
  END a[484]
  PIN a[485]
    DIRECTION INPUT ;
    USE SIGNAL ;
    PORT
      LAYER M4 ;
        RECT  0 405.6 0.084 405.624 ;
    END
  END a[485]
  PIN a[486]
    DIRECTION INPUT ;
    USE SIGNAL ;
    PORT
      LAYER M4 ;
        RECT  0 405.792 0.084 405.816 ;
    END
  END a[486]
  PIN a[487]
    DIRECTION INPUT ;
    USE SIGNAL ;
    PORT
      LAYER M4 ;
        RECT  0 405.984 0.084 406.008 ;
    END
  END a[487]
  PIN a[488]
    DIRECTION INPUT ;
    USE SIGNAL ;
    PORT
      LAYER M4 ;
        RECT  0 406.176 0.084 406.2 ;
    END
  END a[488]
  PIN a[489]
    DIRECTION INPUT ;
    USE SIGNAL ;
    PORT
      LAYER M4 ;
        RECT  0 406.368 0.084 406.392 ;
    END
  END a[489]
  PIN a[48]
    DIRECTION INPUT ;
    USE SIGNAL ;
    PORT
      LAYER M4 ;
        RECT  0 32.4 0.084 32.424 ;
    END
  END a[48]
  PIN a[490]
    DIRECTION INPUT ;
    USE SIGNAL ;
    PORT
      LAYER M4 ;
        RECT  0 406.56 0.084 406.584 ;
    END
  END a[490]
  PIN a[491]
    DIRECTION INPUT ;
    USE SIGNAL ;
    PORT
      LAYER M4 ;
        RECT  0 406.752 0.084 406.776 ;
    END
  END a[491]
  PIN a[492]
    DIRECTION INPUT ;
    USE SIGNAL ;
    PORT
      LAYER M4 ;
        RECT  0 406.944 0.084 406.968 ;
    END
  END a[492]
  PIN a[493]
    DIRECTION INPUT ;
    USE SIGNAL ;
    PORT
      LAYER M4 ;
        RECT  0 407.136 0.084 407.16 ;
    END
  END a[493]
  PIN a[494]
    DIRECTION INPUT ;
    USE SIGNAL ;
    PORT
      LAYER M4 ;
        RECT  0 407.328 0.084 407.352 ;
    END
  END a[494]
  PIN a[495]
    DIRECTION INPUT ;
    USE SIGNAL ;
    PORT
      LAYER M4 ;
        RECT  0 407.52 0.084 407.544 ;
    END
  END a[495]
  PIN a[496]
    DIRECTION INPUT ;
    USE SIGNAL ;
    PORT
      LAYER M4 ;
        RECT  0 407.712 0.084 407.736 ;
    END
  END a[496]
  PIN a[497]
    DIRECTION INPUT ;
    USE SIGNAL ;
    PORT
      LAYER M4 ;
        RECT  0 407.904 0.084 407.928 ;
    END
  END a[497]
  PIN a[498]
    DIRECTION INPUT ;
    USE SIGNAL ;
    PORT
      LAYER M4 ;
        RECT  0 408.096 0.084 408.12 ;
    END
  END a[498]
  PIN a[499]
    DIRECTION INPUT ;
    USE SIGNAL ;
    PORT
      LAYER M4 ;
        RECT  0 408.288 0.084 408.312 ;
    END
  END a[499]
  PIN a[49]
    DIRECTION INPUT ;
    USE SIGNAL ;
    PORT
      LAYER M4 ;
        RECT  0 32.592 0.084 32.616 ;
    END
  END a[49]
  PIN a[4]
    DIRECTION INPUT ;
    USE SIGNAL ;
    PORT
      LAYER M4 ;
        RECT  0 11.664 0.084 11.688 ;
    END
  END a[4]
  PIN a[500]
    DIRECTION INPUT ;
    USE SIGNAL ;
    PORT
      LAYER M4 ;
        RECT  0 408.48 0.084 408.504 ;
    END
  END a[500]
  PIN a[501]
    DIRECTION INPUT ;
    USE SIGNAL ;
    PORT
      LAYER M4 ;
        RECT  0 408.672 0.084 408.696 ;
    END
  END a[501]
  PIN a[502]
    DIRECTION INPUT ;
    USE SIGNAL ;
    PORT
      LAYER M4 ;
        RECT  0 408.864 0.084 408.888 ;
    END
  END a[502]
  PIN a[503]
    DIRECTION INPUT ;
    USE SIGNAL ;
    PORT
      LAYER M4 ;
        RECT  0 409.056 0.084 409.08 ;
    END
  END a[503]
  PIN a[504]
    DIRECTION INPUT ;
    USE SIGNAL ;
    PORT
      LAYER M4 ;
        RECT  0 409.248 0.084 409.272 ;
    END
  END a[504]
  PIN a[505]
    DIRECTION INPUT ;
    USE SIGNAL ;
    PORT
      LAYER M4 ;
        RECT  0 409.44 0.084 409.464 ;
    END
  END a[505]
  PIN a[506]
    DIRECTION INPUT ;
    USE SIGNAL ;
    PORT
      LAYER M4 ;
        RECT  0 409.632 0.084 409.656 ;
    END
  END a[506]
  PIN a[507]
    DIRECTION INPUT ;
    USE SIGNAL ;
    PORT
      LAYER M4 ;
        RECT  0 409.824 0.084 409.848 ;
    END
  END a[507]
  PIN a[508]
    DIRECTION INPUT ;
    USE SIGNAL ;
    PORT
      LAYER M4 ;
        RECT  0 410.016 0.084 410.04 ;
    END
  END a[508]
  PIN a[509]
    DIRECTION INPUT ;
    USE SIGNAL ;
    PORT
      LAYER M4 ;
        RECT  0 410.208 0.084 410.232 ;
    END
  END a[509]
  PIN a[50]
    DIRECTION INPUT ;
    USE SIGNAL ;
    PORT
      LAYER M4 ;
        RECT  0 32.784 0.084 32.808 ;
    END
  END a[50]
  PIN a[510]
    DIRECTION INPUT ;
    USE SIGNAL ;
    PORT
      LAYER M4 ;
        RECT  0 410.4 0.084 410.424 ;
    END
  END a[510]
  PIN a[511]
    DIRECTION INPUT ;
    USE SIGNAL ;
    PORT
      LAYER M4 ;
        RECT  0 410.592 0.084 410.616 ;
    END
  END a[511]
  PIN a[51]
    DIRECTION INPUT ;
    USE SIGNAL ;
    PORT
      LAYER M4 ;
        RECT  0 32.976 0.084 33 ;
    END
  END a[51]
  PIN a[52]
    DIRECTION INPUT ;
    USE SIGNAL ;
    PORT
      LAYER M4 ;
        RECT  0 33.168 0.084 33.192 ;
    END
  END a[52]
  PIN a[53]
    DIRECTION INPUT ;
    USE SIGNAL ;
    PORT
      LAYER M4 ;
        RECT  0 33.36 0.084 33.384 ;
    END
  END a[53]
  PIN a[54]
    DIRECTION INPUT ;
    USE SIGNAL ;
    PORT
      LAYER M4 ;
        RECT  0 33.552 0.084 33.576 ;
    END
  END a[54]
  PIN a[55]
    DIRECTION INPUT ;
    USE SIGNAL ;
    PORT
      LAYER M4 ;
        RECT  0 33.744 0.084 33.768 ;
    END
  END a[55]
  PIN a[56]
    DIRECTION INPUT ;
    USE SIGNAL ;
    PORT
      LAYER M4 ;
        RECT  0 33.936 0.084 33.96 ;
    END
  END a[56]
  PIN a[57]
    DIRECTION INPUT ;
    USE SIGNAL ;
    PORT
      LAYER M4 ;
        RECT  0 34.128 0.084 34.152 ;
    END
  END a[57]
  PIN a[58]
    DIRECTION INPUT ;
    USE SIGNAL ;
    PORT
      LAYER M4 ;
        RECT  0 34.32 0.084 34.344 ;
    END
  END a[58]
  PIN a[59]
    DIRECTION INPUT ;
    USE SIGNAL ;
    PORT
      LAYER M4 ;
        RECT  0 34.512 0.084 34.536 ;
    END
  END a[59]
  PIN a[5]
    DIRECTION INPUT ;
    USE SIGNAL ;
    PORT
      LAYER M4 ;
        RECT  0 11.856 0.084 11.88 ;
    END
  END a[5]
  PIN a[60]
    DIRECTION INPUT ;
    USE SIGNAL ;
    PORT
      LAYER M4 ;
        RECT  0 34.704 0.084 34.728 ;
    END
  END a[60]
  PIN a[61]
    DIRECTION INPUT ;
    USE SIGNAL ;
    PORT
      LAYER M4 ;
        RECT  0 34.896 0.084 34.92 ;
    END
  END a[61]
  PIN a[62]
    DIRECTION INPUT ;
    USE SIGNAL ;
    PORT
      LAYER M4 ;
        RECT  0 35.088 0.084 35.112 ;
    END
  END a[62]
  PIN a[63]
    DIRECTION INPUT ;
    USE SIGNAL ;
    PORT
      LAYER M4 ;
        RECT  0 35.28 0.084 35.304 ;
    END
  END a[63]
  PIN a[64]
    DIRECTION INPUT ;
    USE SIGNAL ;
    PORT
      LAYER M4 ;
        RECT  0 47.76 0.084 47.784 ;
    END
  END a[64]
  PIN a[65]
    DIRECTION INPUT ;
    USE SIGNAL ;
    PORT
      LAYER M4 ;
        RECT  0 47.952 0.084 47.976 ;
    END
  END a[65]
  PIN a[66]
    DIRECTION INPUT ;
    USE SIGNAL ;
    PORT
      LAYER M4 ;
        RECT  0 48.144 0.084 48.168 ;
    END
  END a[66]
  PIN a[67]
    DIRECTION INPUT ;
    USE SIGNAL ;
    PORT
      LAYER M4 ;
        RECT  0 48.336 0.084 48.36 ;
    END
  END a[67]
  PIN a[68]
    DIRECTION INPUT ;
    USE SIGNAL ;
    PORT
      LAYER M4 ;
        RECT  0 48.528 0.084 48.552 ;
    END
  END a[68]
  PIN a[69]
    DIRECTION INPUT ;
    USE SIGNAL ;
    PORT
      LAYER M4 ;
        RECT  0 48.72 0.084 48.744 ;
    END
  END a[69]
  PIN a[6]
    DIRECTION INPUT ;
    USE SIGNAL ;
    PORT
      LAYER M4 ;
        RECT  0 12.048 0.084 12.072 ;
    END
  END a[6]
  PIN a[70]
    DIRECTION INPUT ;
    USE SIGNAL ;
    PORT
      LAYER M4 ;
        RECT  0 48.912 0.084 48.936 ;
    END
  END a[70]
  PIN a[71]
    DIRECTION INPUT ;
    USE SIGNAL ;
    PORT
      LAYER M4 ;
        RECT  0 49.104 0.084 49.128 ;
    END
  END a[71]
  PIN a[72]
    DIRECTION INPUT ;
    USE SIGNAL ;
    PORT
      LAYER M4 ;
        RECT  0 49.296 0.084 49.32 ;
    END
  END a[72]
  PIN a[73]
    DIRECTION INPUT ;
    USE SIGNAL ;
    PORT
      LAYER M4 ;
        RECT  0 49.488 0.084 49.512 ;
    END
  END a[73]
  PIN a[74]
    DIRECTION INPUT ;
    USE SIGNAL ;
    PORT
      LAYER M4 ;
        RECT  0 49.68 0.084 49.704 ;
    END
  END a[74]
  PIN a[75]
    DIRECTION INPUT ;
    USE SIGNAL ;
    PORT
      LAYER M4 ;
        RECT  0 49.872 0.084 49.896 ;
    END
  END a[75]
  PIN a[76]
    DIRECTION INPUT ;
    USE SIGNAL ;
    PORT
      LAYER M4 ;
        RECT  0 50.064 0.084 50.088 ;
    END
  END a[76]
  PIN a[77]
    DIRECTION INPUT ;
    USE SIGNAL ;
    PORT
      LAYER M4 ;
        RECT  0 50.256 0.084 50.28 ;
    END
  END a[77]
  PIN a[78]
    DIRECTION INPUT ;
    USE SIGNAL ;
    PORT
      LAYER M4 ;
        RECT  0 50.448 0.084 50.472 ;
    END
  END a[78]
  PIN a[79]
    DIRECTION INPUT ;
    USE SIGNAL ;
    PORT
      LAYER M4 ;
        RECT  0 50.64 0.084 50.664 ;
    END
  END a[79]
  PIN a[7]
    DIRECTION INPUT ;
    USE SIGNAL ;
    PORT
      LAYER M4 ;
        RECT  0 12.24 0.084 12.264 ;
    END
  END a[7]
  PIN a[80]
    DIRECTION INPUT ;
    USE SIGNAL ;
    PORT
      LAYER M4 ;
        RECT  0 50.832 0.084 50.856 ;
    END
  END a[80]
  PIN a[81]
    DIRECTION INPUT ;
    USE SIGNAL ;
    PORT
      LAYER M4 ;
        RECT  0 51.024 0.084 51.048 ;
    END
  END a[81]
  PIN a[82]
    DIRECTION INPUT ;
    USE SIGNAL ;
    PORT
      LAYER M4 ;
        RECT  0 51.216 0.084 51.24 ;
    END
  END a[82]
  PIN a[83]
    DIRECTION INPUT ;
    USE SIGNAL ;
    PORT
      LAYER M4 ;
        RECT  0 51.408 0.084 51.432 ;
    END
  END a[83]
  PIN a[84]
    DIRECTION INPUT ;
    USE SIGNAL ;
    PORT
      LAYER M4 ;
        RECT  0 51.6 0.084 51.624 ;
    END
  END a[84]
  PIN a[85]
    DIRECTION INPUT ;
    USE SIGNAL ;
    PORT
      LAYER M4 ;
        RECT  0 51.792 0.084 51.816 ;
    END
  END a[85]
  PIN a[86]
    DIRECTION INPUT ;
    USE SIGNAL ;
    PORT
      LAYER M4 ;
        RECT  0 51.984 0.084 52.008 ;
    END
  END a[86]
  PIN a[87]
    DIRECTION INPUT ;
    USE SIGNAL ;
    PORT
      LAYER M4 ;
        RECT  0 52.176 0.084 52.2 ;
    END
  END a[87]
  PIN a[88]
    DIRECTION INPUT ;
    USE SIGNAL ;
    PORT
      LAYER M4 ;
        RECT  0 52.368 0.084 52.392 ;
    END
  END a[88]
  PIN a[89]
    DIRECTION INPUT ;
    USE SIGNAL ;
    PORT
      LAYER M4 ;
        RECT  0 52.56 0.084 52.584 ;
    END
  END a[89]
  PIN a[8]
    DIRECTION INPUT ;
    USE SIGNAL ;
    PORT
      LAYER M4 ;
        RECT  0 12.432 0.084 12.456 ;
    END
  END a[8]
  PIN a[90]
    DIRECTION INPUT ;
    USE SIGNAL ;
    PORT
      LAYER M4 ;
        RECT  0 52.752 0.084 52.776 ;
    END
  END a[90]
  PIN a[91]
    DIRECTION INPUT ;
    USE SIGNAL ;
    PORT
      LAYER M4 ;
        RECT  0 52.944 0.084 52.968 ;
    END
  END a[91]
  PIN a[92]
    DIRECTION INPUT ;
    USE SIGNAL ;
    PORT
      LAYER M4 ;
        RECT  0 53.136 0.084 53.16 ;
    END
  END a[92]
  PIN a[93]
    DIRECTION INPUT ;
    USE SIGNAL ;
    PORT
      LAYER M4 ;
        RECT  0 53.328 0.084 53.352 ;
    END
  END a[93]
  PIN a[94]
    DIRECTION INPUT ;
    USE SIGNAL ;
    PORT
      LAYER M4 ;
        RECT  0 53.52 0.084 53.544 ;
    END
  END a[94]
  PIN a[95]
    DIRECTION INPUT ;
    USE SIGNAL ;
    PORT
      LAYER M4 ;
        RECT  0 53.712 0.084 53.736 ;
    END
  END a[95]
  PIN a[96]
    DIRECTION INPUT ;
    USE SIGNAL ;
    PORT
      LAYER M4 ;
        RECT  0 66.192 0.084 66.216 ;
    END
  END a[96]
  PIN a[97]
    DIRECTION INPUT ;
    USE SIGNAL ;
    PORT
      LAYER M4 ;
        RECT  0 66.384 0.084 66.408 ;
    END
  END a[97]
  PIN a[98]
    DIRECTION INPUT ;
    USE SIGNAL ;
    PORT
      LAYER M4 ;
        RECT  0 66.576 0.084 66.6 ;
    END
  END a[98]
  PIN a[99]
    DIRECTION INPUT ;
    USE SIGNAL ;
    PORT
      LAYER M4 ;
        RECT  0 66.768 0.084 66.792 ;
    END
  END a[99]
  PIN a[9]
    DIRECTION INPUT ;
    USE SIGNAL ;
    PORT
      LAYER M4 ;
        RECT  0 12.624 0.084 12.648 ;
    END
  END a[9]
  PIN b[0]
    DIRECTION INPUT ;
    USE SIGNAL ;
    PORT
      LAYER M4 ;
        RECT  0 17.04 0.084 17.064 ;
    END
  END b[0]
  PIN b[100]
    DIRECTION INPUT ;
    USE SIGNAL ;
    PORT
      LAYER M4 ;
        RECT  0 73.104 0.084 73.128 ;
    END
  END b[100]
  PIN b[101]
    DIRECTION INPUT ;
    USE SIGNAL ;
    PORT
      LAYER M4 ;
        RECT  0 73.296 0.084 73.32 ;
    END
  END b[101]
  PIN b[102]
    DIRECTION INPUT ;
    USE SIGNAL ;
    PORT
      LAYER M4 ;
        RECT  0 73.488 0.084 73.512 ;
    END
  END b[102]
  PIN b[103]
    DIRECTION INPUT ;
    USE SIGNAL ;
    PORT
      LAYER M4 ;
        RECT  0 73.68 0.084 73.704 ;
    END
  END b[103]
  PIN b[104]
    DIRECTION INPUT ;
    USE SIGNAL ;
    PORT
      LAYER M4 ;
        RECT  0 73.872 0.084 73.896 ;
    END
  END b[104]
  PIN b[105]
    DIRECTION INPUT ;
    USE SIGNAL ;
    PORT
      LAYER M4 ;
        RECT  0 74.064 0.084 74.088 ;
    END
  END b[105]
  PIN b[106]
    DIRECTION INPUT ;
    USE SIGNAL ;
    PORT
      LAYER M4 ;
        RECT  0 74.256 0.084 74.28 ;
    END
  END b[106]
  PIN b[107]
    DIRECTION INPUT ;
    USE SIGNAL ;
    PORT
      LAYER M4 ;
        RECT  0 74.448 0.084 74.472 ;
    END
  END b[107]
  PIN b[108]
    DIRECTION INPUT ;
    USE SIGNAL ;
    PORT
      LAYER M4 ;
        RECT  0 74.64 0.084 74.664 ;
    END
  END b[108]
  PIN b[109]
    DIRECTION INPUT ;
    USE SIGNAL ;
    PORT
      LAYER M4 ;
        RECT  0 74.832 0.084 74.856 ;
    END
  END b[109]
  PIN b[10]
    DIRECTION INPUT ;
    USE SIGNAL ;
    PORT
      LAYER M4 ;
        RECT  0 18.96 0.084 18.984 ;
    END
  END b[10]
  PIN b[110]
    DIRECTION INPUT ;
    USE SIGNAL ;
    PORT
      LAYER M4 ;
        RECT  0 75.024 0.084 75.048 ;
    END
  END b[110]
  PIN b[111]
    DIRECTION INPUT ;
    USE SIGNAL ;
    PORT
      LAYER M4 ;
        RECT  0 75.216 0.084 75.24 ;
    END
  END b[111]
  PIN b[112]
    DIRECTION INPUT ;
    USE SIGNAL ;
    PORT
      LAYER M4 ;
        RECT  0 75.408 0.084 75.432 ;
    END
  END b[112]
  PIN b[113]
    DIRECTION INPUT ;
    USE SIGNAL ;
    PORT
      LAYER M4 ;
        RECT  0 75.6 0.084 75.624 ;
    END
  END b[113]
  PIN b[114]
    DIRECTION INPUT ;
    USE SIGNAL ;
    PORT
      LAYER M4 ;
        RECT  0 75.792 0.084 75.816 ;
    END
  END b[114]
  PIN b[115]
    DIRECTION INPUT ;
    USE SIGNAL ;
    PORT
      LAYER M4 ;
        RECT  0 75.984 0.084 76.008 ;
    END
  END b[115]
  PIN b[116]
    DIRECTION INPUT ;
    USE SIGNAL ;
    PORT
      LAYER M4 ;
        RECT  0 76.176 0.084 76.2 ;
    END
  END b[116]
  PIN b[117]
    DIRECTION INPUT ;
    USE SIGNAL ;
    PORT
      LAYER M4 ;
        RECT  0 76.368 0.084 76.392 ;
    END
  END b[117]
  PIN b[118]
    DIRECTION INPUT ;
    USE SIGNAL ;
    PORT
      LAYER M4 ;
        RECT  0 76.56 0.084 76.584 ;
    END
  END b[118]
  PIN b[119]
    DIRECTION INPUT ;
    USE SIGNAL ;
    PORT
      LAYER M4 ;
        RECT  0 76.752 0.084 76.776 ;
    END
  END b[119]
  PIN b[11]
    DIRECTION INPUT ;
    USE SIGNAL ;
    PORT
      LAYER M4 ;
        RECT  0 19.152 0.084 19.176 ;
    END
  END b[11]
  PIN b[120]
    DIRECTION INPUT ;
    USE SIGNAL ;
    PORT
      LAYER M4 ;
        RECT  0 76.944 0.084 76.968 ;
    END
  END b[120]
  PIN b[121]
    DIRECTION INPUT ;
    USE SIGNAL ;
    PORT
      LAYER M4 ;
        RECT  0 77.136 0.084 77.16 ;
    END
  END b[121]
  PIN b[122]
    DIRECTION INPUT ;
    USE SIGNAL ;
    PORT
      LAYER M4 ;
        RECT  0 77.328 0.084 77.352 ;
    END
  END b[122]
  PIN b[123]
    DIRECTION INPUT ;
    USE SIGNAL ;
    PORT
      LAYER M4 ;
        RECT  0 77.52 0.084 77.544 ;
    END
  END b[123]
  PIN b[124]
    DIRECTION INPUT ;
    USE SIGNAL ;
    PORT
      LAYER M4 ;
        RECT  0 77.712 0.084 77.736 ;
    END
  END b[124]
  PIN b[125]
    DIRECTION INPUT ;
    USE SIGNAL ;
    PORT
      LAYER M4 ;
        RECT  0 77.904 0.084 77.928 ;
    END
  END b[125]
  PIN b[126]
    DIRECTION INPUT ;
    USE SIGNAL ;
    PORT
      LAYER M4 ;
        RECT  0 78.096 0.084 78.12 ;
    END
  END b[126]
  PIN b[127]
    DIRECTION INPUT ;
    USE SIGNAL ;
    PORT
      LAYER M4 ;
        RECT  0 78.288 0.084 78.312 ;
    END
  END b[127]
  PIN b[128]
    DIRECTION INPUT ;
    USE SIGNAL ;
    PORT
      LAYER M4 ;
        RECT  0 90.768 0.084 90.792 ;
    END
  END b[128]
  PIN b[129]
    DIRECTION INPUT ;
    USE SIGNAL ;
    PORT
      LAYER M4 ;
        RECT  0 90.96 0.084 90.984 ;
    END
  END b[129]
  PIN b[12]
    DIRECTION INPUT ;
    USE SIGNAL ;
    PORT
      LAYER M4 ;
        RECT  0 19.344 0.084 19.368 ;
    END
  END b[12]
  PIN b[130]
    DIRECTION INPUT ;
    USE SIGNAL ;
    PORT
      LAYER M4 ;
        RECT  0 91.152 0.084 91.176 ;
    END
  END b[130]
  PIN b[131]
    DIRECTION INPUT ;
    USE SIGNAL ;
    PORT
      LAYER M4 ;
        RECT  0 91.344 0.084 91.368 ;
    END
  END b[131]
  PIN b[132]
    DIRECTION INPUT ;
    USE SIGNAL ;
    PORT
      LAYER M4 ;
        RECT  0 91.536 0.084 91.56 ;
    END
  END b[132]
  PIN b[133]
    DIRECTION INPUT ;
    USE SIGNAL ;
    PORT
      LAYER M4 ;
        RECT  0 91.728 0.084 91.752 ;
    END
  END b[133]
  PIN b[134]
    DIRECTION INPUT ;
    USE SIGNAL ;
    PORT
      LAYER M4 ;
        RECT  0 91.92 0.084 91.944 ;
    END
  END b[134]
  PIN b[135]
    DIRECTION INPUT ;
    USE SIGNAL ;
    PORT
      LAYER M4 ;
        RECT  0 92.112 0.084 92.136 ;
    END
  END b[135]
  PIN b[136]
    DIRECTION INPUT ;
    USE SIGNAL ;
    PORT
      LAYER M4 ;
        RECT  0 92.304 0.084 92.328 ;
    END
  END b[136]
  PIN b[137]
    DIRECTION INPUT ;
    USE SIGNAL ;
    PORT
      LAYER M4 ;
        RECT  0 92.496 0.084 92.52 ;
    END
  END b[137]
  PIN b[138]
    DIRECTION INPUT ;
    USE SIGNAL ;
    PORT
      LAYER M4 ;
        RECT  0 92.688 0.084 92.712 ;
    END
  END b[138]
  PIN b[139]
    DIRECTION INPUT ;
    USE SIGNAL ;
    PORT
      LAYER M4 ;
        RECT  0 92.88 0.084 92.904 ;
    END
  END b[139]
  PIN b[13]
    DIRECTION INPUT ;
    USE SIGNAL ;
    PORT
      LAYER M4 ;
        RECT  0 19.536 0.084 19.56 ;
    END
  END b[13]
  PIN b[140]
    DIRECTION INPUT ;
    USE SIGNAL ;
    PORT
      LAYER M4 ;
        RECT  0 93.072 0.084 93.096 ;
    END
  END b[140]
  PIN b[141]
    DIRECTION INPUT ;
    USE SIGNAL ;
    PORT
      LAYER M4 ;
        RECT  0 93.264 0.084 93.288 ;
    END
  END b[141]
  PIN b[142]
    DIRECTION INPUT ;
    USE SIGNAL ;
    PORT
      LAYER M4 ;
        RECT  0 93.456 0.084 93.48 ;
    END
  END b[142]
  PIN b[143]
    DIRECTION INPUT ;
    USE SIGNAL ;
    PORT
      LAYER M4 ;
        RECT  0 93.648 0.084 93.672 ;
    END
  END b[143]
  PIN b[144]
    DIRECTION INPUT ;
    USE SIGNAL ;
    PORT
      LAYER M4 ;
        RECT  0 93.84 0.084 93.864 ;
    END
  END b[144]
  PIN b[145]
    DIRECTION INPUT ;
    USE SIGNAL ;
    PORT
      LAYER M4 ;
        RECT  0 94.032 0.084 94.056 ;
    END
  END b[145]
  PIN b[146]
    DIRECTION INPUT ;
    USE SIGNAL ;
    PORT
      LAYER M4 ;
        RECT  0 94.224 0.084 94.248 ;
    END
  END b[146]
  PIN b[147]
    DIRECTION INPUT ;
    USE SIGNAL ;
    PORT
      LAYER M4 ;
        RECT  0 94.416 0.084 94.44 ;
    END
  END b[147]
  PIN b[148]
    DIRECTION INPUT ;
    USE SIGNAL ;
    PORT
      LAYER M4 ;
        RECT  0 94.608 0.084 94.632 ;
    END
  END b[148]
  PIN b[149]
    DIRECTION INPUT ;
    USE SIGNAL ;
    PORT
      LAYER M4 ;
        RECT  0 94.8 0.084 94.824 ;
    END
  END b[149]
  PIN b[14]
    DIRECTION INPUT ;
    USE SIGNAL ;
    PORT
      LAYER M4 ;
        RECT  0 19.728 0.084 19.752 ;
    END
  END b[14]
  PIN b[150]
    DIRECTION INPUT ;
    USE SIGNAL ;
    PORT
      LAYER M4 ;
        RECT  0 94.992 0.084 95.016 ;
    END
  END b[150]
  PIN b[151]
    DIRECTION INPUT ;
    USE SIGNAL ;
    PORT
      LAYER M4 ;
        RECT  0 95.184 0.084 95.208 ;
    END
  END b[151]
  PIN b[152]
    DIRECTION INPUT ;
    USE SIGNAL ;
    PORT
      LAYER M4 ;
        RECT  0 95.376 0.084 95.4 ;
    END
  END b[152]
  PIN b[153]
    DIRECTION INPUT ;
    USE SIGNAL ;
    PORT
      LAYER M4 ;
        RECT  0 95.568 0.084 95.592 ;
    END
  END b[153]
  PIN b[154]
    DIRECTION INPUT ;
    USE SIGNAL ;
    PORT
      LAYER M4 ;
        RECT  0 95.76 0.084 95.784 ;
    END
  END b[154]
  PIN b[155]
    DIRECTION INPUT ;
    USE SIGNAL ;
    PORT
      LAYER M4 ;
        RECT  0 95.952 0.084 95.976 ;
    END
  END b[155]
  PIN b[156]
    DIRECTION INPUT ;
    USE SIGNAL ;
    PORT
      LAYER M4 ;
        RECT  0 96.144 0.084 96.168 ;
    END
  END b[156]
  PIN b[157]
    DIRECTION INPUT ;
    USE SIGNAL ;
    PORT
      LAYER M4 ;
        RECT  0 96.336 0.084 96.36 ;
    END
  END b[157]
  PIN b[158]
    DIRECTION INPUT ;
    USE SIGNAL ;
    PORT
      LAYER M4 ;
        RECT  0 96.528 0.084 96.552 ;
    END
  END b[158]
  PIN b[159]
    DIRECTION INPUT ;
    USE SIGNAL ;
    PORT
      LAYER M4 ;
        RECT  0 96.72 0.084 96.744 ;
    END
  END b[159]
  PIN b[15]
    DIRECTION INPUT ;
    USE SIGNAL ;
    PORT
      LAYER M4 ;
        RECT  0 19.92 0.084 19.944 ;
    END
  END b[15]
  PIN b[160]
    DIRECTION INPUT ;
    USE SIGNAL ;
    PORT
      LAYER M4 ;
        RECT  0 109.2 0.084 109.224 ;
    END
  END b[160]
  PIN b[161]
    DIRECTION INPUT ;
    USE SIGNAL ;
    PORT
      LAYER M4 ;
        RECT  0 109.392 0.084 109.416 ;
    END
  END b[161]
  PIN b[162]
    DIRECTION INPUT ;
    USE SIGNAL ;
    PORT
      LAYER M4 ;
        RECT  0 109.584 0.084 109.608 ;
    END
  END b[162]
  PIN b[163]
    DIRECTION INPUT ;
    USE SIGNAL ;
    PORT
      LAYER M4 ;
        RECT  0 109.776 0.084 109.8 ;
    END
  END b[163]
  PIN b[164]
    DIRECTION INPUT ;
    USE SIGNAL ;
    PORT
      LAYER M4 ;
        RECT  0 109.968 0.084 109.992 ;
    END
  END b[164]
  PIN b[165]
    DIRECTION INPUT ;
    USE SIGNAL ;
    PORT
      LAYER M4 ;
        RECT  0 110.16 0.084 110.184 ;
    END
  END b[165]
  PIN b[166]
    DIRECTION INPUT ;
    USE SIGNAL ;
    PORT
      LAYER M4 ;
        RECT  0 110.352 0.084 110.376 ;
    END
  END b[166]
  PIN b[167]
    DIRECTION INPUT ;
    USE SIGNAL ;
    PORT
      LAYER M4 ;
        RECT  0 110.544 0.084 110.568 ;
    END
  END b[167]
  PIN b[168]
    DIRECTION INPUT ;
    USE SIGNAL ;
    PORT
      LAYER M4 ;
        RECT  0 110.736 0.084 110.76 ;
    END
  END b[168]
  PIN b[169]
    DIRECTION INPUT ;
    USE SIGNAL ;
    PORT
      LAYER M4 ;
        RECT  0 110.928 0.084 110.952 ;
    END
  END b[169]
  PIN b[16]
    DIRECTION INPUT ;
    USE SIGNAL ;
    PORT
      LAYER M4 ;
        RECT  0 20.112 0.084 20.136 ;
    END
  END b[16]
  PIN b[170]
    DIRECTION INPUT ;
    USE SIGNAL ;
    PORT
      LAYER M4 ;
        RECT  0 111.12 0.084 111.144 ;
    END
  END b[170]
  PIN b[171]
    DIRECTION INPUT ;
    USE SIGNAL ;
    PORT
      LAYER M4 ;
        RECT  0 111.312 0.084 111.336 ;
    END
  END b[171]
  PIN b[172]
    DIRECTION INPUT ;
    USE SIGNAL ;
    PORT
      LAYER M4 ;
        RECT  0 111.504 0.084 111.528 ;
    END
  END b[172]
  PIN b[173]
    DIRECTION INPUT ;
    USE SIGNAL ;
    PORT
      LAYER M4 ;
        RECT  0 111.696 0.084 111.72 ;
    END
  END b[173]
  PIN b[174]
    DIRECTION INPUT ;
    USE SIGNAL ;
    PORT
      LAYER M4 ;
        RECT  0 111.888 0.084 111.912 ;
    END
  END b[174]
  PIN b[175]
    DIRECTION INPUT ;
    USE SIGNAL ;
    PORT
      LAYER M4 ;
        RECT  0 112.08 0.084 112.104 ;
    END
  END b[175]
  PIN b[176]
    DIRECTION INPUT ;
    USE SIGNAL ;
    PORT
      LAYER M4 ;
        RECT  0 112.272 0.084 112.296 ;
    END
  END b[176]
  PIN b[177]
    DIRECTION INPUT ;
    USE SIGNAL ;
    PORT
      LAYER M4 ;
        RECT  0 112.464 0.084 112.488 ;
    END
  END b[177]
  PIN b[178]
    DIRECTION INPUT ;
    USE SIGNAL ;
    PORT
      LAYER M4 ;
        RECT  0 112.656 0.084 112.68 ;
    END
  END b[178]
  PIN b[179]
    DIRECTION INPUT ;
    USE SIGNAL ;
    PORT
      LAYER M4 ;
        RECT  0 112.848 0.084 112.872 ;
    END
  END b[179]
  PIN b[17]
    DIRECTION INPUT ;
    USE SIGNAL ;
    PORT
      LAYER M4 ;
        RECT  0 20.304 0.084 20.328 ;
    END
  END b[17]
  PIN b[180]
    DIRECTION INPUT ;
    USE SIGNAL ;
    PORT
      LAYER M4 ;
        RECT  0 113.04 0.084 113.064 ;
    END
  END b[180]
  PIN b[181]
    DIRECTION INPUT ;
    USE SIGNAL ;
    PORT
      LAYER M4 ;
        RECT  0 113.232 0.084 113.256 ;
    END
  END b[181]
  PIN b[182]
    DIRECTION INPUT ;
    USE SIGNAL ;
    PORT
      LAYER M4 ;
        RECT  0 113.424 0.084 113.448 ;
    END
  END b[182]
  PIN b[183]
    DIRECTION INPUT ;
    USE SIGNAL ;
    PORT
      LAYER M4 ;
        RECT  0 113.616 0.084 113.64 ;
    END
  END b[183]
  PIN b[184]
    DIRECTION INPUT ;
    USE SIGNAL ;
    PORT
      LAYER M4 ;
        RECT  0 113.808 0.084 113.832 ;
    END
  END b[184]
  PIN b[185]
    DIRECTION INPUT ;
    USE SIGNAL ;
    PORT
      LAYER M4 ;
        RECT  0 114 0.084 114.024 ;
    END
  END b[185]
  PIN b[186]
    DIRECTION INPUT ;
    USE SIGNAL ;
    PORT
      LAYER M4 ;
        RECT  0 114.192 0.084 114.216 ;
    END
  END b[186]
  PIN b[187]
    DIRECTION INPUT ;
    USE SIGNAL ;
    PORT
      LAYER M4 ;
        RECT  0 114.384 0.084 114.408 ;
    END
  END b[187]
  PIN b[188]
    DIRECTION INPUT ;
    USE SIGNAL ;
    PORT
      LAYER M4 ;
        RECT  0 114.576 0.084 114.6 ;
    END
  END b[188]
  PIN b[189]
    DIRECTION INPUT ;
    USE SIGNAL ;
    PORT
      LAYER M4 ;
        RECT  0 114.768 0.084 114.792 ;
    END
  END b[189]
  PIN b[18]
    DIRECTION INPUT ;
    USE SIGNAL ;
    PORT
      LAYER M4 ;
        RECT  0 20.496 0.084 20.52 ;
    END
  END b[18]
  PIN b[190]
    DIRECTION INPUT ;
    USE SIGNAL ;
    PORT
      LAYER M4 ;
        RECT  0 114.96 0.084 114.984 ;
    END
  END b[190]
  PIN b[191]
    DIRECTION INPUT ;
    USE SIGNAL ;
    PORT
      LAYER M4 ;
        RECT  0 115.152 0.084 115.176 ;
    END
  END b[191]
  PIN b[192]
    DIRECTION INPUT ;
    USE SIGNAL ;
    PORT
      LAYER M4 ;
        RECT  0 127.632 0.084 127.656 ;
    END
  END b[192]
  PIN b[193]
    DIRECTION INPUT ;
    USE SIGNAL ;
    PORT
      LAYER M4 ;
        RECT  0 127.824 0.084 127.848 ;
    END
  END b[193]
  PIN b[194]
    DIRECTION INPUT ;
    USE SIGNAL ;
    PORT
      LAYER M4 ;
        RECT  0 128.016 0.084 128.04 ;
    END
  END b[194]
  PIN b[195]
    DIRECTION INPUT ;
    USE SIGNAL ;
    PORT
      LAYER M4 ;
        RECT  0 128.208 0.084 128.232 ;
    END
  END b[195]
  PIN b[196]
    DIRECTION INPUT ;
    USE SIGNAL ;
    PORT
      LAYER M4 ;
        RECT  0 128.4 0.084 128.424 ;
    END
  END b[196]
  PIN b[197]
    DIRECTION INPUT ;
    USE SIGNAL ;
    PORT
      LAYER M4 ;
        RECT  0 128.592 0.084 128.616 ;
    END
  END b[197]
  PIN b[198]
    DIRECTION INPUT ;
    USE SIGNAL ;
    PORT
      LAYER M4 ;
        RECT  0 128.784 0.084 128.808 ;
    END
  END b[198]
  PIN b[199]
    DIRECTION INPUT ;
    USE SIGNAL ;
    PORT
      LAYER M4 ;
        RECT  0 128.976 0.084 129 ;
    END
  END b[199]
  PIN b[19]
    DIRECTION INPUT ;
    USE SIGNAL ;
    PORT
      LAYER M4 ;
        RECT  0 20.688 0.084 20.712 ;
    END
  END b[19]
  PIN b[1]
    DIRECTION INPUT ;
    USE SIGNAL ;
    PORT
      LAYER M4 ;
        RECT  0 17.232 0.084 17.256 ;
    END
  END b[1]
  PIN b[200]
    DIRECTION INPUT ;
    USE SIGNAL ;
    PORT
      LAYER M4 ;
        RECT  0 129.168 0.084 129.192 ;
    END
  END b[200]
  PIN b[201]
    DIRECTION INPUT ;
    USE SIGNAL ;
    PORT
      LAYER M4 ;
        RECT  0 129.36 0.084 129.384 ;
    END
  END b[201]
  PIN b[202]
    DIRECTION INPUT ;
    USE SIGNAL ;
    PORT
      LAYER M4 ;
        RECT  0 129.552 0.084 129.576 ;
    END
  END b[202]
  PIN b[203]
    DIRECTION INPUT ;
    USE SIGNAL ;
    PORT
      LAYER M4 ;
        RECT  0 129.744 0.084 129.768 ;
    END
  END b[203]
  PIN b[204]
    DIRECTION INPUT ;
    USE SIGNAL ;
    PORT
      LAYER M4 ;
        RECT  0 129.936 0.084 129.96 ;
    END
  END b[204]
  PIN b[205]
    DIRECTION INPUT ;
    USE SIGNAL ;
    PORT
      LAYER M4 ;
        RECT  0 130.128 0.084 130.152 ;
    END
  END b[205]
  PIN b[206]
    DIRECTION INPUT ;
    USE SIGNAL ;
    PORT
      LAYER M4 ;
        RECT  0 130.32 0.084 130.344 ;
    END
  END b[206]
  PIN b[207]
    DIRECTION INPUT ;
    USE SIGNAL ;
    PORT
      LAYER M4 ;
        RECT  0 130.512 0.084 130.536 ;
    END
  END b[207]
  PIN b[208]
    DIRECTION INPUT ;
    USE SIGNAL ;
    PORT
      LAYER M4 ;
        RECT  0 130.704 0.084 130.728 ;
    END
  END b[208]
  PIN b[209]
    DIRECTION INPUT ;
    USE SIGNAL ;
    PORT
      LAYER M4 ;
        RECT  0 130.896 0.084 130.92 ;
    END
  END b[209]
  PIN b[20]
    DIRECTION INPUT ;
    USE SIGNAL ;
    PORT
      LAYER M4 ;
        RECT  0 20.88 0.084 20.904 ;
    END
  END b[20]
  PIN b[210]
    DIRECTION INPUT ;
    USE SIGNAL ;
    PORT
      LAYER M4 ;
        RECT  0 131.088 0.084 131.112 ;
    END
  END b[210]
  PIN b[211]
    DIRECTION INPUT ;
    USE SIGNAL ;
    PORT
      LAYER M4 ;
        RECT  0 131.28 0.084 131.304 ;
    END
  END b[211]
  PIN b[212]
    DIRECTION INPUT ;
    USE SIGNAL ;
    PORT
      LAYER M4 ;
        RECT  0 131.472 0.084 131.496 ;
    END
  END b[212]
  PIN b[213]
    DIRECTION INPUT ;
    USE SIGNAL ;
    PORT
      LAYER M4 ;
        RECT  0 131.664 0.084 131.688 ;
    END
  END b[213]
  PIN b[214]
    DIRECTION INPUT ;
    USE SIGNAL ;
    PORT
      LAYER M4 ;
        RECT  0 131.856 0.084 131.88 ;
    END
  END b[214]
  PIN b[215]
    DIRECTION INPUT ;
    USE SIGNAL ;
    PORT
      LAYER M4 ;
        RECT  0 132.048 0.084 132.072 ;
    END
  END b[215]
  PIN b[216]
    DIRECTION INPUT ;
    USE SIGNAL ;
    PORT
      LAYER M4 ;
        RECT  0 132.24 0.084 132.264 ;
    END
  END b[216]
  PIN b[217]
    DIRECTION INPUT ;
    USE SIGNAL ;
    PORT
      LAYER M4 ;
        RECT  0 132.432 0.084 132.456 ;
    END
  END b[217]
  PIN b[218]
    DIRECTION INPUT ;
    USE SIGNAL ;
    PORT
      LAYER M4 ;
        RECT  0 132.624 0.084 132.648 ;
    END
  END b[218]
  PIN b[219]
    DIRECTION INPUT ;
    USE SIGNAL ;
    PORT
      LAYER M4 ;
        RECT  0 132.816 0.084 132.84 ;
    END
  END b[219]
  PIN b[21]
    DIRECTION INPUT ;
    USE SIGNAL ;
    PORT
      LAYER M4 ;
        RECT  0 21.072 0.084 21.096 ;
    END
  END b[21]
  PIN b[220]
    DIRECTION INPUT ;
    USE SIGNAL ;
    PORT
      LAYER M4 ;
        RECT  0 133.008 0.084 133.032 ;
    END
  END b[220]
  PIN b[221]
    DIRECTION INPUT ;
    USE SIGNAL ;
    PORT
      LAYER M4 ;
        RECT  0 133.2 0.084 133.224 ;
    END
  END b[221]
  PIN b[222]
    DIRECTION INPUT ;
    USE SIGNAL ;
    PORT
      LAYER M4 ;
        RECT  0 133.392 0.084 133.416 ;
    END
  END b[222]
  PIN b[223]
    DIRECTION INPUT ;
    USE SIGNAL ;
    PORT
      LAYER M4 ;
        RECT  0 133.584 0.084 133.608 ;
    END
  END b[223]
  PIN b[224]
    DIRECTION INPUT ;
    USE SIGNAL ;
    PORT
      LAYER M4 ;
        RECT  0 146.064 0.084 146.088 ;
    END
  END b[224]
  PIN b[225]
    DIRECTION INPUT ;
    USE SIGNAL ;
    PORT
      LAYER M4 ;
        RECT  0 146.256 0.084 146.28 ;
    END
  END b[225]
  PIN b[226]
    DIRECTION INPUT ;
    USE SIGNAL ;
    PORT
      LAYER M4 ;
        RECT  0 146.448 0.084 146.472 ;
    END
  END b[226]
  PIN b[227]
    DIRECTION INPUT ;
    USE SIGNAL ;
    PORT
      LAYER M4 ;
        RECT  0 146.64 0.084 146.664 ;
    END
  END b[227]
  PIN b[228]
    DIRECTION INPUT ;
    USE SIGNAL ;
    PORT
      LAYER M4 ;
        RECT  0 146.832 0.084 146.856 ;
    END
  END b[228]
  PIN b[229]
    DIRECTION INPUT ;
    USE SIGNAL ;
    PORT
      LAYER M4 ;
        RECT  0 147.024 0.084 147.048 ;
    END
  END b[229]
  PIN b[22]
    DIRECTION INPUT ;
    USE SIGNAL ;
    PORT
      LAYER M4 ;
        RECT  0 21.264 0.084 21.288 ;
    END
  END b[22]
  PIN b[230]
    DIRECTION INPUT ;
    USE SIGNAL ;
    PORT
      LAYER M4 ;
        RECT  0 147.216 0.084 147.24 ;
    END
  END b[230]
  PIN b[231]
    DIRECTION INPUT ;
    USE SIGNAL ;
    PORT
      LAYER M4 ;
        RECT  0 147.408 0.084 147.432 ;
    END
  END b[231]
  PIN b[232]
    DIRECTION INPUT ;
    USE SIGNAL ;
    PORT
      LAYER M4 ;
        RECT  0 147.6 0.084 147.624 ;
    END
  END b[232]
  PIN b[233]
    DIRECTION INPUT ;
    USE SIGNAL ;
    PORT
      LAYER M4 ;
        RECT  0 147.792 0.084 147.816 ;
    END
  END b[233]
  PIN b[234]
    DIRECTION INPUT ;
    USE SIGNAL ;
    PORT
      LAYER M4 ;
        RECT  0 147.984 0.084 148.008 ;
    END
  END b[234]
  PIN b[235]
    DIRECTION INPUT ;
    USE SIGNAL ;
    PORT
      LAYER M4 ;
        RECT  0 148.176 0.084 148.2 ;
    END
  END b[235]
  PIN b[236]
    DIRECTION INPUT ;
    USE SIGNAL ;
    PORT
      LAYER M4 ;
        RECT  0 148.368 0.084 148.392 ;
    END
  END b[236]
  PIN b[237]
    DIRECTION INPUT ;
    USE SIGNAL ;
    PORT
      LAYER M4 ;
        RECT  0 148.56 0.084 148.584 ;
    END
  END b[237]
  PIN b[238]
    DIRECTION INPUT ;
    USE SIGNAL ;
    PORT
      LAYER M4 ;
        RECT  0 148.752 0.084 148.776 ;
    END
  END b[238]
  PIN b[239]
    DIRECTION INPUT ;
    USE SIGNAL ;
    PORT
      LAYER M4 ;
        RECT  0 148.944 0.084 148.968 ;
    END
  END b[239]
  PIN b[23]
    DIRECTION INPUT ;
    USE SIGNAL ;
    PORT
      LAYER M4 ;
        RECT  0 21.456 0.084 21.48 ;
    END
  END b[23]
  PIN b[240]
    DIRECTION INPUT ;
    USE SIGNAL ;
    PORT
      LAYER M4 ;
        RECT  0 149.136 0.084 149.16 ;
    END
  END b[240]
  PIN b[241]
    DIRECTION INPUT ;
    USE SIGNAL ;
    PORT
      LAYER M4 ;
        RECT  0 149.328 0.084 149.352 ;
    END
  END b[241]
  PIN b[242]
    DIRECTION INPUT ;
    USE SIGNAL ;
    PORT
      LAYER M4 ;
        RECT  0 149.52 0.084 149.544 ;
    END
  END b[242]
  PIN b[243]
    DIRECTION INPUT ;
    USE SIGNAL ;
    PORT
      LAYER M4 ;
        RECT  0 149.712 0.084 149.736 ;
    END
  END b[243]
  PIN b[244]
    DIRECTION INPUT ;
    USE SIGNAL ;
    PORT
      LAYER M4 ;
        RECT  0 149.904 0.084 149.928 ;
    END
  END b[244]
  PIN b[245]
    DIRECTION INPUT ;
    USE SIGNAL ;
    PORT
      LAYER M4 ;
        RECT  0 150.096 0.084 150.12 ;
    END
  END b[245]
  PIN b[246]
    DIRECTION INPUT ;
    USE SIGNAL ;
    PORT
      LAYER M4 ;
        RECT  0 150.288 0.084 150.312 ;
    END
  END b[246]
  PIN b[247]
    DIRECTION INPUT ;
    USE SIGNAL ;
    PORT
      LAYER M4 ;
        RECT  0 150.48 0.084 150.504 ;
    END
  END b[247]
  PIN b[248]
    DIRECTION INPUT ;
    USE SIGNAL ;
    PORT
      LAYER M4 ;
        RECT  0 150.672 0.084 150.696 ;
    END
  END b[248]
  PIN b[249]
    DIRECTION INPUT ;
    USE SIGNAL ;
    PORT
      LAYER M4 ;
        RECT  0 150.864 0.084 150.888 ;
    END
  END b[249]
  PIN b[24]
    DIRECTION INPUT ;
    USE SIGNAL ;
    PORT
      LAYER M4 ;
        RECT  0 21.648 0.084 21.672 ;
    END
  END b[24]
  PIN b[250]
    DIRECTION INPUT ;
    USE SIGNAL ;
    PORT
      LAYER M4 ;
        RECT  0 151.056 0.084 151.08 ;
    END
  END b[250]
  PIN b[251]
    DIRECTION INPUT ;
    USE SIGNAL ;
    PORT
      LAYER M4 ;
        RECT  0 151.248 0.084 151.272 ;
    END
  END b[251]
  PIN b[252]
    DIRECTION INPUT ;
    USE SIGNAL ;
    PORT
      LAYER M4 ;
        RECT  0 151.44 0.084 151.464 ;
    END
  END b[252]
  PIN b[253]
    DIRECTION INPUT ;
    USE SIGNAL ;
    PORT
      LAYER M4 ;
        RECT  0 151.632 0.084 151.656 ;
    END
  END b[253]
  PIN b[254]
    DIRECTION INPUT ;
    USE SIGNAL ;
    PORT
      LAYER M4 ;
        RECT  0 151.824 0.084 151.848 ;
    END
  END b[254]
  PIN b[255]
    DIRECTION INPUT ;
    USE SIGNAL ;
    PORT
      LAYER M4 ;
        RECT  0 152.016 0.084 152.04 ;
    END
  END b[255]
  PIN b[256]
    DIRECTION INPUT ;
    USE SIGNAL ;
    PORT
      LAYER M4 ;
        RECT  0 164.496 0.084 164.52 ;
    END
  END b[256]
  PIN b[257]
    DIRECTION INPUT ;
    USE SIGNAL ;
    PORT
      LAYER M4 ;
        RECT  0 164.688 0.084 164.712 ;
    END
  END b[257]
  PIN b[258]
    DIRECTION INPUT ;
    USE SIGNAL ;
    PORT
      LAYER M4 ;
        RECT  0 164.88 0.084 164.904 ;
    END
  END b[258]
  PIN b[259]
    DIRECTION INPUT ;
    USE SIGNAL ;
    PORT
      LAYER M4 ;
        RECT  0 165.072 0.084 165.096 ;
    END
  END b[259]
  PIN b[25]
    DIRECTION INPUT ;
    USE SIGNAL ;
    PORT
      LAYER M4 ;
        RECT  0 21.84 0.084 21.864 ;
    END
  END b[25]
  PIN b[260]
    DIRECTION INPUT ;
    USE SIGNAL ;
    PORT
      LAYER M4 ;
        RECT  0 165.264 0.084 165.288 ;
    END
  END b[260]
  PIN b[261]
    DIRECTION INPUT ;
    USE SIGNAL ;
    PORT
      LAYER M4 ;
        RECT  0 165.456 0.084 165.48 ;
    END
  END b[261]
  PIN b[262]
    DIRECTION INPUT ;
    USE SIGNAL ;
    PORT
      LAYER M4 ;
        RECT  0 165.648 0.084 165.672 ;
    END
  END b[262]
  PIN b[263]
    DIRECTION INPUT ;
    USE SIGNAL ;
    PORT
      LAYER M4 ;
        RECT  0 165.84 0.084 165.864 ;
    END
  END b[263]
  PIN b[264]
    DIRECTION INPUT ;
    USE SIGNAL ;
    PORT
      LAYER M4 ;
        RECT  0 166.032 0.084 166.056 ;
    END
  END b[264]
  PIN b[265]
    DIRECTION INPUT ;
    USE SIGNAL ;
    PORT
      LAYER M4 ;
        RECT  0 166.224 0.084 166.248 ;
    END
  END b[265]
  PIN b[266]
    DIRECTION INPUT ;
    USE SIGNAL ;
    PORT
      LAYER M4 ;
        RECT  0 166.416 0.084 166.44 ;
    END
  END b[266]
  PIN b[267]
    DIRECTION INPUT ;
    USE SIGNAL ;
    PORT
      LAYER M4 ;
        RECT  0 166.608 0.084 166.632 ;
    END
  END b[267]
  PIN b[268]
    DIRECTION INPUT ;
    USE SIGNAL ;
    PORT
      LAYER M4 ;
        RECT  0 166.8 0.084 166.824 ;
    END
  END b[268]
  PIN b[269]
    DIRECTION INPUT ;
    USE SIGNAL ;
    PORT
      LAYER M4 ;
        RECT  0 166.992 0.084 167.016 ;
    END
  END b[269]
  PIN b[26]
    DIRECTION INPUT ;
    USE SIGNAL ;
    PORT
      LAYER M4 ;
        RECT  0 22.032 0.084 22.056 ;
    END
  END b[26]
  PIN b[270]
    DIRECTION INPUT ;
    USE SIGNAL ;
    PORT
      LAYER M4 ;
        RECT  0 167.184 0.084 167.208 ;
    END
  END b[270]
  PIN b[271]
    DIRECTION INPUT ;
    USE SIGNAL ;
    PORT
      LAYER M4 ;
        RECT  0 167.376 0.084 167.4 ;
    END
  END b[271]
  PIN b[272]
    DIRECTION INPUT ;
    USE SIGNAL ;
    PORT
      LAYER M4 ;
        RECT  0 167.568 0.084 167.592 ;
    END
  END b[272]
  PIN b[273]
    DIRECTION INPUT ;
    USE SIGNAL ;
    PORT
      LAYER M4 ;
        RECT  0 167.76 0.084 167.784 ;
    END
  END b[273]
  PIN b[274]
    DIRECTION INPUT ;
    USE SIGNAL ;
    PORT
      LAYER M4 ;
        RECT  0 167.952 0.084 167.976 ;
    END
  END b[274]
  PIN b[275]
    DIRECTION INPUT ;
    USE SIGNAL ;
    PORT
      LAYER M4 ;
        RECT  0 168.144 0.084 168.168 ;
    END
  END b[275]
  PIN b[276]
    DIRECTION INPUT ;
    USE SIGNAL ;
    PORT
      LAYER M4 ;
        RECT  0 168.336 0.084 168.36 ;
    END
  END b[276]
  PIN b[277]
    DIRECTION INPUT ;
    USE SIGNAL ;
    PORT
      LAYER M4 ;
        RECT  0 168.528 0.084 168.552 ;
    END
  END b[277]
  PIN b[278]
    DIRECTION INPUT ;
    USE SIGNAL ;
    PORT
      LAYER M4 ;
        RECT  0 168.72 0.084 168.744 ;
    END
  END b[278]
  PIN b[279]
    DIRECTION INPUT ;
    USE SIGNAL ;
    PORT
      LAYER M4 ;
        RECT  0 168.912 0.084 168.936 ;
    END
  END b[279]
  PIN b[27]
    DIRECTION INPUT ;
    USE SIGNAL ;
    PORT
      LAYER M4 ;
        RECT  0 22.224 0.084 22.248 ;
    END
  END b[27]
  PIN b[280]
    DIRECTION INPUT ;
    USE SIGNAL ;
    PORT
      LAYER M4 ;
        RECT  0 169.104 0.084 169.128 ;
    END
  END b[280]
  PIN b[281]
    DIRECTION INPUT ;
    USE SIGNAL ;
    PORT
      LAYER M4 ;
        RECT  0 169.296 0.084 169.32 ;
    END
  END b[281]
  PIN b[282]
    DIRECTION INPUT ;
    USE SIGNAL ;
    PORT
      LAYER M4 ;
        RECT  0 169.488 0.084 169.512 ;
    END
  END b[282]
  PIN b[283]
    DIRECTION INPUT ;
    USE SIGNAL ;
    PORT
      LAYER M4 ;
        RECT  0 169.68 0.084 169.704 ;
    END
  END b[283]
  PIN b[284]
    DIRECTION INPUT ;
    USE SIGNAL ;
    PORT
      LAYER M4 ;
        RECT  0 169.872 0.084 169.896 ;
    END
  END b[284]
  PIN b[285]
    DIRECTION INPUT ;
    USE SIGNAL ;
    PORT
      LAYER M4 ;
        RECT  0 170.064 0.084 170.088 ;
    END
  END b[285]
  PIN b[286]
    DIRECTION INPUT ;
    USE SIGNAL ;
    PORT
      LAYER M4 ;
        RECT  0 170.256 0.084 170.28 ;
    END
  END b[286]
  PIN b[287]
    DIRECTION INPUT ;
    USE SIGNAL ;
    PORT
      LAYER M4 ;
        RECT  0 170.448 0.084 170.472 ;
    END
  END b[287]
  PIN b[288]
    DIRECTION INPUT ;
    USE SIGNAL ;
    PORT
      LAYER M4 ;
        RECT  0 182.928 0.084 182.952 ;
    END
  END b[288]
  PIN b[289]
    DIRECTION INPUT ;
    USE SIGNAL ;
    PORT
      LAYER M4 ;
        RECT  0 183.12 0.084 183.144 ;
    END
  END b[289]
  PIN b[28]
    DIRECTION INPUT ;
    USE SIGNAL ;
    PORT
      LAYER M4 ;
        RECT  0 22.416 0.084 22.44 ;
    END
  END b[28]
  PIN b[290]
    DIRECTION INPUT ;
    USE SIGNAL ;
    PORT
      LAYER M4 ;
        RECT  0 183.312 0.084 183.336 ;
    END
  END b[290]
  PIN b[291]
    DIRECTION INPUT ;
    USE SIGNAL ;
    PORT
      LAYER M4 ;
        RECT  0 183.504 0.084 183.528 ;
    END
  END b[291]
  PIN b[292]
    DIRECTION INPUT ;
    USE SIGNAL ;
    PORT
      LAYER M4 ;
        RECT  0 183.696 0.084 183.72 ;
    END
  END b[292]
  PIN b[293]
    DIRECTION INPUT ;
    USE SIGNAL ;
    PORT
      LAYER M4 ;
        RECT  0 183.888 0.084 183.912 ;
    END
  END b[293]
  PIN b[294]
    DIRECTION INPUT ;
    USE SIGNAL ;
    PORT
      LAYER M4 ;
        RECT  0 184.08 0.084 184.104 ;
    END
  END b[294]
  PIN b[295]
    DIRECTION INPUT ;
    USE SIGNAL ;
    PORT
      LAYER M4 ;
        RECT  0 184.272 0.084 184.296 ;
    END
  END b[295]
  PIN b[296]
    DIRECTION INPUT ;
    USE SIGNAL ;
    PORT
      LAYER M4 ;
        RECT  0 184.464 0.084 184.488 ;
    END
  END b[296]
  PIN b[297]
    DIRECTION INPUT ;
    USE SIGNAL ;
    PORT
      LAYER M4 ;
        RECT  0 184.656 0.084 184.68 ;
    END
  END b[297]
  PIN b[298]
    DIRECTION INPUT ;
    USE SIGNAL ;
    PORT
      LAYER M4 ;
        RECT  0 184.848 0.084 184.872 ;
    END
  END b[298]
  PIN b[299]
    DIRECTION INPUT ;
    USE SIGNAL ;
    PORT
      LAYER M4 ;
        RECT  0 185.04 0.084 185.064 ;
    END
  END b[299]
  PIN b[29]
    DIRECTION INPUT ;
    USE SIGNAL ;
    PORT
      LAYER M4 ;
        RECT  0 22.608 0.084 22.632 ;
    END
  END b[29]
  PIN b[2]
    DIRECTION INPUT ;
    USE SIGNAL ;
    PORT
      LAYER M4 ;
        RECT  0 17.424 0.084 17.448 ;
    END
  END b[2]
  PIN b[300]
    DIRECTION INPUT ;
    USE SIGNAL ;
    PORT
      LAYER M4 ;
        RECT  0 185.232 0.084 185.256 ;
    END
  END b[300]
  PIN b[301]
    DIRECTION INPUT ;
    USE SIGNAL ;
    PORT
      LAYER M4 ;
        RECT  0 185.424 0.084 185.448 ;
    END
  END b[301]
  PIN b[302]
    DIRECTION INPUT ;
    USE SIGNAL ;
    PORT
      LAYER M4 ;
        RECT  0 185.616 0.084 185.64 ;
    END
  END b[302]
  PIN b[303]
    DIRECTION INPUT ;
    USE SIGNAL ;
    PORT
      LAYER M4 ;
        RECT  0 185.808 0.084 185.832 ;
    END
  END b[303]
  PIN b[304]
    DIRECTION INPUT ;
    USE SIGNAL ;
    PORT
      LAYER M4 ;
        RECT  0 186 0.084 186.024 ;
    END
  END b[304]
  PIN b[305]
    DIRECTION INPUT ;
    USE SIGNAL ;
    PORT
      LAYER M4 ;
        RECT  0 186.192 0.084 186.216 ;
    END
  END b[305]
  PIN b[306]
    DIRECTION INPUT ;
    USE SIGNAL ;
    PORT
      LAYER M4 ;
        RECT  0 186.384 0.084 186.408 ;
    END
  END b[306]
  PIN b[307]
    DIRECTION INPUT ;
    USE SIGNAL ;
    PORT
      LAYER M4 ;
        RECT  0 186.576 0.084 186.6 ;
    END
  END b[307]
  PIN b[308]
    DIRECTION INPUT ;
    USE SIGNAL ;
    PORT
      LAYER M4 ;
        RECT  0 186.768 0.084 186.792 ;
    END
  END b[308]
  PIN b[309]
    DIRECTION INPUT ;
    USE SIGNAL ;
    PORT
      LAYER M4 ;
        RECT  0 186.96 0.084 186.984 ;
    END
  END b[309]
  PIN b[30]
    DIRECTION INPUT ;
    USE SIGNAL ;
    PORT
      LAYER M4 ;
        RECT  0 22.8 0.084 22.824 ;
    END
  END b[30]
  PIN b[310]
    DIRECTION INPUT ;
    USE SIGNAL ;
    PORT
      LAYER M4 ;
        RECT  0 187.152 0.084 187.176 ;
    END
  END b[310]
  PIN b[311]
    DIRECTION INPUT ;
    USE SIGNAL ;
    PORT
      LAYER M4 ;
        RECT  0 187.344 0.084 187.368 ;
    END
  END b[311]
  PIN b[312]
    DIRECTION INPUT ;
    USE SIGNAL ;
    PORT
      LAYER M4 ;
        RECT  0 187.536 0.084 187.56 ;
    END
  END b[312]
  PIN b[313]
    DIRECTION INPUT ;
    USE SIGNAL ;
    PORT
      LAYER M4 ;
        RECT  0 187.728 0.084 187.752 ;
    END
  END b[313]
  PIN b[314]
    DIRECTION INPUT ;
    USE SIGNAL ;
    PORT
      LAYER M4 ;
        RECT  0 187.92 0.084 187.944 ;
    END
  END b[314]
  PIN b[315]
    DIRECTION INPUT ;
    USE SIGNAL ;
    PORT
      LAYER M4 ;
        RECT  0 188.112 0.084 188.136 ;
    END
  END b[315]
  PIN b[316]
    DIRECTION INPUT ;
    USE SIGNAL ;
    PORT
      LAYER M4 ;
        RECT  0 188.304 0.084 188.328 ;
    END
  END b[316]
  PIN b[317]
    DIRECTION INPUT ;
    USE SIGNAL ;
    PORT
      LAYER M4 ;
        RECT  0 188.496 0.084 188.52 ;
    END
  END b[317]
  PIN b[318]
    DIRECTION INPUT ;
    USE SIGNAL ;
    PORT
      LAYER M4 ;
        RECT  0 188.688 0.084 188.712 ;
    END
  END b[318]
  PIN b[319]
    DIRECTION INPUT ;
    USE SIGNAL ;
    PORT
      LAYER M4 ;
        RECT  0 188.88 0.084 188.904 ;
    END
  END b[319]
  PIN b[31]
    DIRECTION INPUT ;
    USE SIGNAL ;
    PORT
      LAYER M4 ;
        RECT  0 22.992 0.084 23.016 ;
    END
  END b[31]
  PIN b[320]
    DIRECTION INPUT ;
    USE SIGNAL ;
    PORT
      LAYER M4 ;
        RECT  0 318.624 0.084 318.648 ;
    END
  END b[320]
  PIN b[321]
    DIRECTION INPUT ;
    USE SIGNAL ;
    PORT
      LAYER M4 ;
        RECT  0 318.816 0.084 318.84 ;
    END
  END b[321]
  PIN b[322]
    DIRECTION INPUT ;
    USE SIGNAL ;
    PORT
      LAYER M4 ;
        RECT  0 319.008 0.084 319.032 ;
    END
  END b[322]
  PIN b[323]
    DIRECTION INPUT ;
    USE SIGNAL ;
    PORT
      LAYER M4 ;
        RECT  0 319.2 0.084 319.224 ;
    END
  END b[323]
  PIN b[324]
    DIRECTION INPUT ;
    USE SIGNAL ;
    PORT
      LAYER M4 ;
        RECT  0 319.392 0.084 319.416 ;
    END
  END b[324]
  PIN b[325]
    DIRECTION INPUT ;
    USE SIGNAL ;
    PORT
      LAYER M4 ;
        RECT  0 319.584 0.084 319.608 ;
    END
  END b[325]
  PIN b[326]
    DIRECTION INPUT ;
    USE SIGNAL ;
    PORT
      LAYER M4 ;
        RECT  0 319.776 0.084 319.8 ;
    END
  END b[326]
  PIN b[327]
    DIRECTION INPUT ;
    USE SIGNAL ;
    PORT
      LAYER M4 ;
        RECT  0 319.968 0.084 319.992 ;
    END
  END b[327]
  PIN b[328]
    DIRECTION INPUT ;
    USE SIGNAL ;
    PORT
      LAYER M4 ;
        RECT  0 320.16 0.084 320.184 ;
    END
  END b[328]
  PIN b[329]
    DIRECTION INPUT ;
    USE SIGNAL ;
    PORT
      LAYER M4 ;
        RECT  0 320.352 0.084 320.376 ;
    END
  END b[329]
  PIN b[32]
    DIRECTION INPUT ;
    USE SIGNAL ;
    PORT
      LAYER M4 ;
        RECT  0 35.472 0.084 35.496 ;
    END
  END b[32]
  PIN b[330]
    DIRECTION INPUT ;
    USE SIGNAL ;
    PORT
      LAYER M4 ;
        RECT  0 320.544 0.084 320.568 ;
    END
  END b[330]
  PIN b[331]
    DIRECTION INPUT ;
    USE SIGNAL ;
    PORT
      LAYER M4 ;
        RECT  0 320.736 0.084 320.76 ;
    END
  END b[331]
  PIN b[332]
    DIRECTION INPUT ;
    USE SIGNAL ;
    PORT
      LAYER M4 ;
        RECT  0 320.928 0.084 320.952 ;
    END
  END b[332]
  PIN b[333]
    DIRECTION INPUT ;
    USE SIGNAL ;
    PORT
      LAYER M4 ;
        RECT  0 321.12 0.084 321.144 ;
    END
  END b[333]
  PIN b[334]
    DIRECTION INPUT ;
    USE SIGNAL ;
    PORT
      LAYER M4 ;
        RECT  0 321.312 0.084 321.336 ;
    END
  END b[334]
  PIN b[335]
    DIRECTION INPUT ;
    USE SIGNAL ;
    PORT
      LAYER M4 ;
        RECT  0 321.504 0.084 321.528 ;
    END
  END b[335]
  PIN b[336]
    DIRECTION INPUT ;
    USE SIGNAL ;
    PORT
      LAYER M4 ;
        RECT  0 321.696 0.084 321.72 ;
    END
  END b[336]
  PIN b[337]
    DIRECTION INPUT ;
    USE SIGNAL ;
    PORT
      LAYER M4 ;
        RECT  0 321.888 0.084 321.912 ;
    END
  END b[337]
  PIN b[338]
    DIRECTION INPUT ;
    USE SIGNAL ;
    PORT
      LAYER M4 ;
        RECT  0 322.08 0.084 322.104 ;
    END
  END b[338]
  PIN b[339]
    DIRECTION INPUT ;
    USE SIGNAL ;
    PORT
      LAYER M4 ;
        RECT  0 322.272 0.084 322.296 ;
    END
  END b[339]
  PIN b[33]
    DIRECTION INPUT ;
    USE SIGNAL ;
    PORT
      LAYER M4 ;
        RECT  0 35.664 0.084 35.688 ;
    END
  END b[33]
  PIN b[340]
    DIRECTION INPUT ;
    USE SIGNAL ;
    PORT
      LAYER M4 ;
        RECT  0 322.464 0.084 322.488 ;
    END
  END b[340]
  PIN b[341]
    DIRECTION INPUT ;
    USE SIGNAL ;
    PORT
      LAYER M4 ;
        RECT  0 322.656 0.084 322.68 ;
    END
  END b[341]
  PIN b[342]
    DIRECTION INPUT ;
    USE SIGNAL ;
    PORT
      LAYER M4 ;
        RECT  0 322.848 0.084 322.872 ;
    END
  END b[342]
  PIN b[343]
    DIRECTION INPUT ;
    USE SIGNAL ;
    PORT
      LAYER M4 ;
        RECT  0 323.04 0.084 323.064 ;
    END
  END b[343]
  PIN b[344]
    DIRECTION INPUT ;
    USE SIGNAL ;
    PORT
      LAYER M4 ;
        RECT  0 323.232 0.084 323.256 ;
    END
  END b[344]
  PIN b[345]
    DIRECTION INPUT ;
    USE SIGNAL ;
    PORT
      LAYER M4 ;
        RECT  0 323.424 0.084 323.448 ;
    END
  END b[345]
  PIN b[346]
    DIRECTION INPUT ;
    USE SIGNAL ;
    PORT
      LAYER M4 ;
        RECT  0 323.616 0.084 323.64 ;
    END
  END b[346]
  PIN b[347]
    DIRECTION INPUT ;
    USE SIGNAL ;
    PORT
      LAYER M4 ;
        RECT  0 323.808 0.084 323.832 ;
    END
  END b[347]
  PIN b[348]
    DIRECTION INPUT ;
    USE SIGNAL ;
    PORT
      LAYER M4 ;
        RECT  0 324 0.084 324.024 ;
    END
  END b[348]
  PIN b[349]
    DIRECTION INPUT ;
    USE SIGNAL ;
    PORT
      LAYER M4 ;
        RECT  0 324.192 0.084 324.216 ;
    END
  END b[349]
  PIN b[34]
    DIRECTION INPUT ;
    USE SIGNAL ;
    PORT
      LAYER M4 ;
        RECT  0 35.856 0.084 35.88 ;
    END
  END b[34]
  PIN b[350]
    DIRECTION INPUT ;
    USE SIGNAL ;
    PORT
      LAYER M4 ;
        RECT  0 324.384 0.084 324.408 ;
    END
  END b[350]
  PIN b[351]
    DIRECTION INPUT ;
    USE SIGNAL ;
    PORT
      LAYER M4 ;
        RECT  0 324.576 0.084 324.6 ;
    END
  END b[351]
  PIN b[352]
    DIRECTION INPUT ;
    USE SIGNAL ;
    PORT
      LAYER M4 ;
        RECT  0 337.056 0.084 337.08 ;
    END
  END b[352]
  PIN b[353]
    DIRECTION INPUT ;
    USE SIGNAL ;
    PORT
      LAYER M4 ;
        RECT  0 337.248 0.084 337.272 ;
    END
  END b[353]
  PIN b[354]
    DIRECTION INPUT ;
    USE SIGNAL ;
    PORT
      LAYER M4 ;
        RECT  0 337.44 0.084 337.464 ;
    END
  END b[354]
  PIN b[355]
    DIRECTION INPUT ;
    USE SIGNAL ;
    PORT
      LAYER M4 ;
        RECT  0 337.632 0.084 337.656 ;
    END
  END b[355]
  PIN b[356]
    DIRECTION INPUT ;
    USE SIGNAL ;
    PORT
      LAYER M4 ;
        RECT  0 337.824 0.084 337.848 ;
    END
  END b[356]
  PIN b[357]
    DIRECTION INPUT ;
    USE SIGNAL ;
    PORT
      LAYER M4 ;
        RECT  0 338.016 0.084 338.04 ;
    END
  END b[357]
  PIN b[358]
    DIRECTION INPUT ;
    USE SIGNAL ;
    PORT
      LAYER M4 ;
        RECT  0 338.208 0.084 338.232 ;
    END
  END b[358]
  PIN b[359]
    DIRECTION INPUT ;
    USE SIGNAL ;
    PORT
      LAYER M4 ;
        RECT  0 338.4 0.084 338.424 ;
    END
  END b[359]
  PIN b[35]
    DIRECTION INPUT ;
    USE SIGNAL ;
    PORT
      LAYER M4 ;
        RECT  0 36.048 0.084 36.072 ;
    END
  END b[35]
  PIN b[360]
    DIRECTION INPUT ;
    USE SIGNAL ;
    PORT
      LAYER M4 ;
        RECT  0 338.592 0.084 338.616 ;
    END
  END b[360]
  PIN b[361]
    DIRECTION INPUT ;
    USE SIGNAL ;
    PORT
      LAYER M4 ;
        RECT  0 338.784 0.084 338.808 ;
    END
  END b[361]
  PIN b[362]
    DIRECTION INPUT ;
    USE SIGNAL ;
    PORT
      LAYER M4 ;
        RECT  0 338.976 0.084 339 ;
    END
  END b[362]
  PIN b[363]
    DIRECTION INPUT ;
    USE SIGNAL ;
    PORT
      LAYER M4 ;
        RECT  0 339.168 0.084 339.192 ;
    END
  END b[363]
  PIN b[364]
    DIRECTION INPUT ;
    USE SIGNAL ;
    PORT
      LAYER M4 ;
        RECT  0 339.36 0.084 339.384 ;
    END
  END b[364]
  PIN b[365]
    DIRECTION INPUT ;
    USE SIGNAL ;
    PORT
      LAYER M4 ;
        RECT  0 339.552 0.084 339.576 ;
    END
  END b[365]
  PIN b[366]
    DIRECTION INPUT ;
    USE SIGNAL ;
    PORT
      LAYER M4 ;
        RECT  0 339.744 0.084 339.768 ;
    END
  END b[366]
  PIN b[367]
    DIRECTION INPUT ;
    USE SIGNAL ;
    PORT
      LAYER M4 ;
        RECT  0 339.936 0.084 339.96 ;
    END
  END b[367]
  PIN b[368]
    DIRECTION INPUT ;
    USE SIGNAL ;
    PORT
      LAYER M4 ;
        RECT  0 340.128 0.084 340.152 ;
    END
  END b[368]
  PIN b[369]
    DIRECTION INPUT ;
    USE SIGNAL ;
    PORT
      LAYER M4 ;
        RECT  0 340.32 0.084 340.344 ;
    END
  END b[369]
  PIN b[36]
    DIRECTION INPUT ;
    USE SIGNAL ;
    PORT
      LAYER M4 ;
        RECT  0 36.24 0.084 36.264 ;
    END
  END b[36]
  PIN b[370]
    DIRECTION INPUT ;
    USE SIGNAL ;
    PORT
      LAYER M4 ;
        RECT  0 340.512 0.084 340.536 ;
    END
  END b[370]
  PIN b[371]
    DIRECTION INPUT ;
    USE SIGNAL ;
    PORT
      LAYER M4 ;
        RECT  0 340.704 0.084 340.728 ;
    END
  END b[371]
  PIN b[372]
    DIRECTION INPUT ;
    USE SIGNAL ;
    PORT
      LAYER M4 ;
        RECT  0 340.896 0.084 340.92 ;
    END
  END b[372]
  PIN b[373]
    DIRECTION INPUT ;
    USE SIGNAL ;
    PORT
      LAYER M4 ;
        RECT  0 341.088 0.084 341.112 ;
    END
  END b[373]
  PIN b[374]
    DIRECTION INPUT ;
    USE SIGNAL ;
    PORT
      LAYER M4 ;
        RECT  0 341.28 0.084 341.304 ;
    END
  END b[374]
  PIN b[375]
    DIRECTION INPUT ;
    USE SIGNAL ;
    PORT
      LAYER M4 ;
        RECT  0 341.472 0.084 341.496 ;
    END
  END b[375]
  PIN b[376]
    DIRECTION INPUT ;
    USE SIGNAL ;
    PORT
      LAYER M4 ;
        RECT  0 341.664 0.084 341.688 ;
    END
  END b[376]
  PIN b[377]
    DIRECTION INPUT ;
    USE SIGNAL ;
    PORT
      LAYER M4 ;
        RECT  0 341.856 0.084 341.88 ;
    END
  END b[377]
  PIN b[378]
    DIRECTION INPUT ;
    USE SIGNAL ;
    PORT
      LAYER M4 ;
        RECT  0 342.048 0.084 342.072 ;
    END
  END b[378]
  PIN b[379]
    DIRECTION INPUT ;
    USE SIGNAL ;
    PORT
      LAYER M4 ;
        RECT  0 342.24 0.084 342.264 ;
    END
  END b[379]
  PIN b[37]
    DIRECTION INPUT ;
    USE SIGNAL ;
    PORT
      LAYER M4 ;
        RECT  0 36.432 0.084 36.456 ;
    END
  END b[37]
  PIN b[380]
    DIRECTION INPUT ;
    USE SIGNAL ;
    PORT
      LAYER M4 ;
        RECT  0 342.432 0.084 342.456 ;
    END
  END b[380]
  PIN b[381]
    DIRECTION INPUT ;
    USE SIGNAL ;
    PORT
      LAYER M4 ;
        RECT  0 342.624 0.084 342.648 ;
    END
  END b[381]
  PIN b[382]
    DIRECTION INPUT ;
    USE SIGNAL ;
    PORT
      LAYER M4 ;
        RECT  0 342.816 0.084 342.84 ;
    END
  END b[382]
  PIN b[383]
    DIRECTION INPUT ;
    USE SIGNAL ;
    PORT
      LAYER M4 ;
        RECT  0 343.008 0.084 343.032 ;
    END
  END b[383]
  PIN b[384]
    DIRECTION INPUT ;
    USE SIGNAL ;
    PORT
      LAYER M4 ;
        RECT  0 355.488 0.084 355.512 ;
    END
  END b[384]
  PIN b[385]
    DIRECTION INPUT ;
    USE SIGNAL ;
    PORT
      LAYER M4 ;
        RECT  0 355.68 0.084 355.704 ;
    END
  END b[385]
  PIN b[386]
    DIRECTION INPUT ;
    USE SIGNAL ;
    PORT
      LAYER M4 ;
        RECT  0 355.872 0.084 355.896 ;
    END
  END b[386]
  PIN b[387]
    DIRECTION INPUT ;
    USE SIGNAL ;
    PORT
      LAYER M4 ;
        RECT  0 356.064 0.084 356.088 ;
    END
  END b[387]
  PIN b[388]
    DIRECTION INPUT ;
    USE SIGNAL ;
    PORT
      LAYER M4 ;
        RECT  0 356.256 0.084 356.28 ;
    END
  END b[388]
  PIN b[389]
    DIRECTION INPUT ;
    USE SIGNAL ;
    PORT
      LAYER M4 ;
        RECT  0 356.448 0.084 356.472 ;
    END
  END b[389]
  PIN b[38]
    DIRECTION INPUT ;
    USE SIGNAL ;
    PORT
      LAYER M4 ;
        RECT  0 36.624 0.084 36.648 ;
    END
  END b[38]
  PIN b[390]
    DIRECTION INPUT ;
    USE SIGNAL ;
    PORT
      LAYER M4 ;
        RECT  0 356.64 0.084 356.664 ;
    END
  END b[390]
  PIN b[391]
    DIRECTION INPUT ;
    USE SIGNAL ;
    PORT
      LAYER M4 ;
        RECT  0 356.832 0.084 356.856 ;
    END
  END b[391]
  PIN b[392]
    DIRECTION INPUT ;
    USE SIGNAL ;
    PORT
      LAYER M4 ;
        RECT  0 357.024 0.084 357.048 ;
    END
  END b[392]
  PIN b[393]
    DIRECTION INPUT ;
    USE SIGNAL ;
    PORT
      LAYER M4 ;
        RECT  0 357.216 0.084 357.24 ;
    END
  END b[393]
  PIN b[394]
    DIRECTION INPUT ;
    USE SIGNAL ;
    PORT
      LAYER M4 ;
        RECT  0 357.408 0.084 357.432 ;
    END
  END b[394]
  PIN b[395]
    DIRECTION INPUT ;
    USE SIGNAL ;
    PORT
      LAYER M4 ;
        RECT  0 357.6 0.084 357.624 ;
    END
  END b[395]
  PIN b[396]
    DIRECTION INPUT ;
    USE SIGNAL ;
    PORT
      LAYER M4 ;
        RECT  0 357.792 0.084 357.816 ;
    END
  END b[396]
  PIN b[397]
    DIRECTION INPUT ;
    USE SIGNAL ;
    PORT
      LAYER M4 ;
        RECT  0 357.984 0.084 358.008 ;
    END
  END b[397]
  PIN b[398]
    DIRECTION INPUT ;
    USE SIGNAL ;
    PORT
      LAYER M4 ;
        RECT  0 358.176 0.084 358.2 ;
    END
  END b[398]
  PIN b[399]
    DIRECTION INPUT ;
    USE SIGNAL ;
    PORT
      LAYER M4 ;
        RECT  0 358.368 0.084 358.392 ;
    END
  END b[399]
  PIN b[39]
    DIRECTION INPUT ;
    USE SIGNAL ;
    PORT
      LAYER M4 ;
        RECT  0 36.816 0.084 36.84 ;
    END
  END b[39]
  PIN b[3]
    DIRECTION INPUT ;
    USE SIGNAL ;
    PORT
      LAYER M4 ;
        RECT  0 17.616 0.084 17.64 ;
    END
  END b[3]
  PIN b[400]
    DIRECTION INPUT ;
    USE SIGNAL ;
    PORT
      LAYER M4 ;
        RECT  0 358.56 0.084 358.584 ;
    END
  END b[400]
  PIN b[401]
    DIRECTION INPUT ;
    USE SIGNAL ;
    PORT
      LAYER M4 ;
        RECT  0 358.752 0.084 358.776 ;
    END
  END b[401]
  PIN b[402]
    DIRECTION INPUT ;
    USE SIGNAL ;
    PORT
      LAYER M4 ;
        RECT  0 358.944 0.084 358.968 ;
    END
  END b[402]
  PIN b[403]
    DIRECTION INPUT ;
    USE SIGNAL ;
    PORT
      LAYER M4 ;
        RECT  0 359.136 0.084 359.16 ;
    END
  END b[403]
  PIN b[404]
    DIRECTION INPUT ;
    USE SIGNAL ;
    PORT
      LAYER M4 ;
        RECT  0 359.328 0.084 359.352 ;
    END
  END b[404]
  PIN b[405]
    DIRECTION INPUT ;
    USE SIGNAL ;
    PORT
      LAYER M4 ;
        RECT  0 359.52 0.084 359.544 ;
    END
  END b[405]
  PIN b[406]
    DIRECTION INPUT ;
    USE SIGNAL ;
    PORT
      LAYER M4 ;
        RECT  0 359.712 0.084 359.736 ;
    END
  END b[406]
  PIN b[407]
    DIRECTION INPUT ;
    USE SIGNAL ;
    PORT
      LAYER M4 ;
        RECT  0 359.904 0.084 359.928 ;
    END
  END b[407]
  PIN b[408]
    DIRECTION INPUT ;
    USE SIGNAL ;
    PORT
      LAYER M4 ;
        RECT  0 360.096 0.084 360.12 ;
    END
  END b[408]
  PIN b[409]
    DIRECTION INPUT ;
    USE SIGNAL ;
    PORT
      LAYER M4 ;
        RECT  0 360.288 0.084 360.312 ;
    END
  END b[409]
  PIN b[40]
    DIRECTION INPUT ;
    USE SIGNAL ;
    PORT
      LAYER M4 ;
        RECT  0 37.008 0.084 37.032 ;
    END
  END b[40]
  PIN b[410]
    DIRECTION INPUT ;
    USE SIGNAL ;
    PORT
      LAYER M4 ;
        RECT  0 360.48 0.084 360.504 ;
    END
  END b[410]
  PIN b[411]
    DIRECTION INPUT ;
    USE SIGNAL ;
    PORT
      LAYER M4 ;
        RECT  0 360.672 0.084 360.696 ;
    END
  END b[411]
  PIN b[412]
    DIRECTION INPUT ;
    USE SIGNAL ;
    PORT
      LAYER M4 ;
        RECT  0 360.864 0.084 360.888 ;
    END
  END b[412]
  PIN b[413]
    DIRECTION INPUT ;
    USE SIGNAL ;
    PORT
      LAYER M4 ;
        RECT  0 361.056 0.084 361.08 ;
    END
  END b[413]
  PIN b[414]
    DIRECTION INPUT ;
    USE SIGNAL ;
    PORT
      LAYER M4 ;
        RECT  0 361.248 0.084 361.272 ;
    END
  END b[414]
  PIN b[415]
    DIRECTION INPUT ;
    USE SIGNAL ;
    PORT
      LAYER M4 ;
        RECT  0 361.44 0.084 361.464 ;
    END
  END b[415]
  PIN b[416]
    DIRECTION INPUT ;
    USE SIGNAL ;
    PORT
      LAYER M4 ;
        RECT  0 373.92 0.084 373.944 ;
    END
  END b[416]
  PIN b[417]
    DIRECTION INPUT ;
    USE SIGNAL ;
    PORT
      LAYER M4 ;
        RECT  0 374.112 0.084 374.136 ;
    END
  END b[417]
  PIN b[418]
    DIRECTION INPUT ;
    USE SIGNAL ;
    PORT
      LAYER M4 ;
        RECT  0 374.304 0.084 374.328 ;
    END
  END b[418]
  PIN b[419]
    DIRECTION INPUT ;
    USE SIGNAL ;
    PORT
      LAYER M4 ;
        RECT  0 374.496 0.084 374.52 ;
    END
  END b[419]
  PIN b[41]
    DIRECTION INPUT ;
    USE SIGNAL ;
    PORT
      LAYER M4 ;
        RECT  0 37.2 0.084 37.224 ;
    END
  END b[41]
  PIN b[420]
    DIRECTION INPUT ;
    USE SIGNAL ;
    PORT
      LAYER M4 ;
        RECT  0 374.688 0.084 374.712 ;
    END
  END b[420]
  PIN b[421]
    DIRECTION INPUT ;
    USE SIGNAL ;
    PORT
      LAYER M4 ;
        RECT  0 374.88 0.084 374.904 ;
    END
  END b[421]
  PIN b[422]
    DIRECTION INPUT ;
    USE SIGNAL ;
    PORT
      LAYER M4 ;
        RECT  0 375.072 0.084 375.096 ;
    END
  END b[422]
  PIN b[423]
    DIRECTION INPUT ;
    USE SIGNAL ;
    PORT
      LAYER M4 ;
        RECT  0 375.264 0.084 375.288 ;
    END
  END b[423]
  PIN b[424]
    DIRECTION INPUT ;
    USE SIGNAL ;
    PORT
      LAYER M4 ;
        RECT  0 375.456 0.084 375.48 ;
    END
  END b[424]
  PIN b[425]
    DIRECTION INPUT ;
    USE SIGNAL ;
    PORT
      LAYER M4 ;
        RECT  0 375.648 0.084 375.672 ;
    END
  END b[425]
  PIN b[426]
    DIRECTION INPUT ;
    USE SIGNAL ;
    PORT
      LAYER M4 ;
        RECT  0 375.84 0.084 375.864 ;
    END
  END b[426]
  PIN b[427]
    DIRECTION INPUT ;
    USE SIGNAL ;
    PORT
      LAYER M4 ;
        RECT  0 376.032 0.084 376.056 ;
    END
  END b[427]
  PIN b[428]
    DIRECTION INPUT ;
    USE SIGNAL ;
    PORT
      LAYER M4 ;
        RECT  0 376.224 0.084 376.248 ;
    END
  END b[428]
  PIN b[429]
    DIRECTION INPUT ;
    USE SIGNAL ;
    PORT
      LAYER M4 ;
        RECT  0 376.416 0.084 376.44 ;
    END
  END b[429]
  PIN b[42]
    DIRECTION INPUT ;
    USE SIGNAL ;
    PORT
      LAYER M4 ;
        RECT  0 37.392 0.084 37.416 ;
    END
  END b[42]
  PIN b[430]
    DIRECTION INPUT ;
    USE SIGNAL ;
    PORT
      LAYER M4 ;
        RECT  0 376.608 0.084 376.632 ;
    END
  END b[430]
  PIN b[431]
    DIRECTION INPUT ;
    USE SIGNAL ;
    PORT
      LAYER M4 ;
        RECT  0 376.8 0.084 376.824 ;
    END
  END b[431]
  PIN b[432]
    DIRECTION INPUT ;
    USE SIGNAL ;
    PORT
      LAYER M4 ;
        RECT  0 376.992 0.084 377.016 ;
    END
  END b[432]
  PIN b[433]
    DIRECTION INPUT ;
    USE SIGNAL ;
    PORT
      LAYER M4 ;
        RECT  0 377.184 0.084 377.208 ;
    END
  END b[433]
  PIN b[434]
    DIRECTION INPUT ;
    USE SIGNAL ;
    PORT
      LAYER M4 ;
        RECT  0 377.376 0.084 377.4 ;
    END
  END b[434]
  PIN b[435]
    DIRECTION INPUT ;
    USE SIGNAL ;
    PORT
      LAYER M4 ;
        RECT  0 377.568 0.084 377.592 ;
    END
  END b[435]
  PIN b[436]
    DIRECTION INPUT ;
    USE SIGNAL ;
    PORT
      LAYER M4 ;
        RECT  0 377.76 0.084 377.784 ;
    END
  END b[436]
  PIN b[437]
    DIRECTION INPUT ;
    USE SIGNAL ;
    PORT
      LAYER M4 ;
        RECT  0 377.952 0.084 377.976 ;
    END
  END b[437]
  PIN b[438]
    DIRECTION INPUT ;
    USE SIGNAL ;
    PORT
      LAYER M4 ;
        RECT  0 378.144 0.084 378.168 ;
    END
  END b[438]
  PIN b[439]
    DIRECTION INPUT ;
    USE SIGNAL ;
    PORT
      LAYER M4 ;
        RECT  0 378.336 0.084 378.36 ;
    END
  END b[439]
  PIN b[43]
    DIRECTION INPUT ;
    USE SIGNAL ;
    PORT
      LAYER M4 ;
        RECT  0 37.584 0.084 37.608 ;
    END
  END b[43]
  PIN b[440]
    DIRECTION INPUT ;
    USE SIGNAL ;
    PORT
      LAYER M4 ;
        RECT  0 378.528 0.084 378.552 ;
    END
  END b[440]
  PIN b[441]
    DIRECTION INPUT ;
    USE SIGNAL ;
    PORT
      LAYER M4 ;
        RECT  0 378.72 0.084 378.744 ;
    END
  END b[441]
  PIN b[442]
    DIRECTION INPUT ;
    USE SIGNAL ;
    PORT
      LAYER M4 ;
        RECT  0 378.912 0.084 378.936 ;
    END
  END b[442]
  PIN b[443]
    DIRECTION INPUT ;
    USE SIGNAL ;
    PORT
      LAYER M4 ;
        RECT  0 379.104 0.084 379.128 ;
    END
  END b[443]
  PIN b[444]
    DIRECTION INPUT ;
    USE SIGNAL ;
    PORT
      LAYER M4 ;
        RECT  0 379.296 0.084 379.32 ;
    END
  END b[444]
  PIN b[445]
    DIRECTION INPUT ;
    USE SIGNAL ;
    PORT
      LAYER M4 ;
        RECT  0 379.488 0.084 379.512 ;
    END
  END b[445]
  PIN b[446]
    DIRECTION INPUT ;
    USE SIGNAL ;
    PORT
      LAYER M4 ;
        RECT  0 379.68 0.084 379.704 ;
    END
  END b[446]
  PIN b[447]
    DIRECTION INPUT ;
    USE SIGNAL ;
    PORT
      LAYER M4 ;
        RECT  0 379.872 0.084 379.896 ;
    END
  END b[447]
  PIN b[448]
    DIRECTION INPUT ;
    USE SIGNAL ;
    PORT
      LAYER M4 ;
        RECT  0 392.352 0.084 392.376 ;
    END
  END b[448]
  PIN b[449]
    DIRECTION INPUT ;
    USE SIGNAL ;
    PORT
      LAYER M4 ;
        RECT  0 392.544 0.084 392.568 ;
    END
  END b[449]
  PIN b[44]
    DIRECTION INPUT ;
    USE SIGNAL ;
    PORT
      LAYER M4 ;
        RECT  0 37.776 0.084 37.8 ;
    END
  END b[44]
  PIN b[450]
    DIRECTION INPUT ;
    USE SIGNAL ;
    PORT
      LAYER M4 ;
        RECT  0 392.736 0.084 392.76 ;
    END
  END b[450]
  PIN b[451]
    DIRECTION INPUT ;
    USE SIGNAL ;
    PORT
      LAYER M4 ;
        RECT  0 392.928 0.084 392.952 ;
    END
  END b[451]
  PIN b[452]
    DIRECTION INPUT ;
    USE SIGNAL ;
    PORT
      LAYER M4 ;
        RECT  0 393.12 0.084 393.144 ;
    END
  END b[452]
  PIN b[453]
    DIRECTION INPUT ;
    USE SIGNAL ;
    PORT
      LAYER M4 ;
        RECT  0 393.312 0.084 393.336 ;
    END
  END b[453]
  PIN b[454]
    DIRECTION INPUT ;
    USE SIGNAL ;
    PORT
      LAYER M4 ;
        RECT  0 393.504 0.084 393.528 ;
    END
  END b[454]
  PIN b[455]
    DIRECTION INPUT ;
    USE SIGNAL ;
    PORT
      LAYER M4 ;
        RECT  0 393.696 0.084 393.72 ;
    END
  END b[455]
  PIN b[456]
    DIRECTION INPUT ;
    USE SIGNAL ;
    PORT
      LAYER M4 ;
        RECT  0 393.888 0.084 393.912 ;
    END
  END b[456]
  PIN b[457]
    DIRECTION INPUT ;
    USE SIGNAL ;
    PORT
      LAYER M4 ;
        RECT  0 394.08 0.084 394.104 ;
    END
  END b[457]
  PIN b[458]
    DIRECTION INPUT ;
    USE SIGNAL ;
    PORT
      LAYER M4 ;
        RECT  0 394.272 0.084 394.296 ;
    END
  END b[458]
  PIN b[459]
    DIRECTION INPUT ;
    USE SIGNAL ;
    PORT
      LAYER M4 ;
        RECT  0 394.464 0.084 394.488 ;
    END
  END b[459]
  PIN b[45]
    DIRECTION INPUT ;
    USE SIGNAL ;
    PORT
      LAYER M4 ;
        RECT  0 37.968 0.084 37.992 ;
    END
  END b[45]
  PIN b[460]
    DIRECTION INPUT ;
    USE SIGNAL ;
    PORT
      LAYER M4 ;
        RECT  0 394.656 0.084 394.68 ;
    END
  END b[460]
  PIN b[461]
    DIRECTION INPUT ;
    USE SIGNAL ;
    PORT
      LAYER M4 ;
        RECT  0 394.848 0.084 394.872 ;
    END
  END b[461]
  PIN b[462]
    DIRECTION INPUT ;
    USE SIGNAL ;
    PORT
      LAYER M4 ;
        RECT  0 395.04 0.084 395.064 ;
    END
  END b[462]
  PIN b[463]
    DIRECTION INPUT ;
    USE SIGNAL ;
    PORT
      LAYER M4 ;
        RECT  0 395.232 0.084 395.256 ;
    END
  END b[463]
  PIN b[464]
    DIRECTION INPUT ;
    USE SIGNAL ;
    PORT
      LAYER M4 ;
        RECT  0 395.424 0.084 395.448 ;
    END
  END b[464]
  PIN b[465]
    DIRECTION INPUT ;
    USE SIGNAL ;
    PORT
      LAYER M4 ;
        RECT  0 395.616 0.084 395.64 ;
    END
  END b[465]
  PIN b[466]
    DIRECTION INPUT ;
    USE SIGNAL ;
    PORT
      LAYER M4 ;
        RECT  0 395.808 0.084 395.832 ;
    END
  END b[466]
  PIN b[467]
    DIRECTION INPUT ;
    USE SIGNAL ;
    PORT
      LAYER M4 ;
        RECT  0 396 0.084 396.024 ;
    END
  END b[467]
  PIN b[468]
    DIRECTION INPUT ;
    USE SIGNAL ;
    PORT
      LAYER M4 ;
        RECT  0 396.192 0.084 396.216 ;
    END
  END b[468]
  PIN b[469]
    DIRECTION INPUT ;
    USE SIGNAL ;
    PORT
      LAYER M4 ;
        RECT  0 396.384 0.084 396.408 ;
    END
  END b[469]
  PIN b[46]
    DIRECTION INPUT ;
    USE SIGNAL ;
    PORT
      LAYER M4 ;
        RECT  0 38.16 0.084 38.184 ;
    END
  END b[46]
  PIN b[470]
    DIRECTION INPUT ;
    USE SIGNAL ;
    PORT
      LAYER M4 ;
        RECT  0 396.576 0.084 396.6 ;
    END
  END b[470]
  PIN b[471]
    DIRECTION INPUT ;
    USE SIGNAL ;
    PORT
      LAYER M4 ;
        RECT  0 396.768 0.084 396.792 ;
    END
  END b[471]
  PIN b[472]
    DIRECTION INPUT ;
    USE SIGNAL ;
    PORT
      LAYER M4 ;
        RECT  0 396.96 0.084 396.984 ;
    END
  END b[472]
  PIN b[473]
    DIRECTION INPUT ;
    USE SIGNAL ;
    PORT
      LAYER M4 ;
        RECT  0 397.152 0.084 397.176 ;
    END
  END b[473]
  PIN b[474]
    DIRECTION INPUT ;
    USE SIGNAL ;
    PORT
      LAYER M4 ;
        RECT  0 397.344 0.084 397.368 ;
    END
  END b[474]
  PIN b[475]
    DIRECTION INPUT ;
    USE SIGNAL ;
    PORT
      LAYER M4 ;
        RECT  0 397.536 0.084 397.56 ;
    END
  END b[475]
  PIN b[476]
    DIRECTION INPUT ;
    USE SIGNAL ;
    PORT
      LAYER M4 ;
        RECT  0 397.728 0.084 397.752 ;
    END
  END b[476]
  PIN b[477]
    DIRECTION INPUT ;
    USE SIGNAL ;
    PORT
      LAYER M4 ;
        RECT  0 397.92 0.084 397.944 ;
    END
  END b[477]
  PIN b[478]
    DIRECTION INPUT ;
    USE SIGNAL ;
    PORT
      LAYER M4 ;
        RECT  0 398.112 0.084 398.136 ;
    END
  END b[478]
  PIN b[479]
    DIRECTION INPUT ;
    USE SIGNAL ;
    PORT
      LAYER M4 ;
        RECT  0 398.304 0.084 398.328 ;
    END
  END b[479]
  PIN b[47]
    DIRECTION INPUT ;
    USE SIGNAL ;
    PORT
      LAYER M4 ;
        RECT  0 38.352 0.084 38.376 ;
    END
  END b[47]
  PIN b[480]
    DIRECTION INPUT ;
    USE SIGNAL ;
    PORT
      LAYER M4 ;
        RECT  0 410.784 0.084 410.808 ;
    END
  END b[480]
  PIN b[481]
    DIRECTION INPUT ;
    USE SIGNAL ;
    PORT
      LAYER M4 ;
        RECT  0 410.976 0.084 411 ;
    END
  END b[481]
  PIN b[482]
    DIRECTION INPUT ;
    USE SIGNAL ;
    PORT
      LAYER M4 ;
        RECT  0 411.168 0.084 411.192 ;
    END
  END b[482]
  PIN b[483]
    DIRECTION INPUT ;
    USE SIGNAL ;
    PORT
      LAYER M4 ;
        RECT  0 411.36 0.084 411.384 ;
    END
  END b[483]
  PIN b[484]
    DIRECTION INPUT ;
    USE SIGNAL ;
    PORT
      LAYER M4 ;
        RECT  0 411.552 0.084 411.576 ;
    END
  END b[484]
  PIN b[485]
    DIRECTION INPUT ;
    USE SIGNAL ;
    PORT
      LAYER M4 ;
        RECT  0 411.744 0.084 411.768 ;
    END
  END b[485]
  PIN b[486]
    DIRECTION INPUT ;
    USE SIGNAL ;
    PORT
      LAYER M4 ;
        RECT  0 411.936 0.084 411.96 ;
    END
  END b[486]
  PIN b[487]
    DIRECTION INPUT ;
    USE SIGNAL ;
    PORT
      LAYER M4 ;
        RECT  0 412.128 0.084 412.152 ;
    END
  END b[487]
  PIN b[488]
    DIRECTION INPUT ;
    USE SIGNAL ;
    PORT
      LAYER M4 ;
        RECT  0 412.32 0.084 412.344 ;
    END
  END b[488]
  PIN b[489]
    DIRECTION INPUT ;
    USE SIGNAL ;
    PORT
      LAYER M4 ;
        RECT  0 412.512 0.084 412.536 ;
    END
  END b[489]
  PIN b[48]
    DIRECTION INPUT ;
    USE SIGNAL ;
    PORT
      LAYER M4 ;
        RECT  0 38.544 0.084 38.568 ;
    END
  END b[48]
  PIN b[490]
    DIRECTION INPUT ;
    USE SIGNAL ;
    PORT
      LAYER M4 ;
        RECT  0 412.704 0.084 412.728 ;
    END
  END b[490]
  PIN b[491]
    DIRECTION INPUT ;
    USE SIGNAL ;
    PORT
      LAYER M4 ;
        RECT  0 412.896 0.084 412.92 ;
    END
  END b[491]
  PIN b[492]
    DIRECTION INPUT ;
    USE SIGNAL ;
    PORT
      LAYER M4 ;
        RECT  0 413.088 0.084 413.112 ;
    END
  END b[492]
  PIN b[493]
    DIRECTION INPUT ;
    USE SIGNAL ;
    PORT
      LAYER M4 ;
        RECT  0 413.28 0.084 413.304 ;
    END
  END b[493]
  PIN b[494]
    DIRECTION INPUT ;
    USE SIGNAL ;
    PORT
      LAYER M4 ;
        RECT  0 413.472 0.084 413.496 ;
    END
  END b[494]
  PIN b[495]
    DIRECTION INPUT ;
    USE SIGNAL ;
    PORT
      LAYER M4 ;
        RECT  0 413.664 0.084 413.688 ;
    END
  END b[495]
  PIN b[496]
    DIRECTION INPUT ;
    USE SIGNAL ;
    PORT
      LAYER M4 ;
        RECT  0 413.856 0.084 413.88 ;
    END
  END b[496]
  PIN b[497]
    DIRECTION INPUT ;
    USE SIGNAL ;
    PORT
      LAYER M4 ;
        RECT  0 414.048 0.084 414.072 ;
    END
  END b[497]
  PIN b[498]
    DIRECTION INPUT ;
    USE SIGNAL ;
    PORT
      LAYER M4 ;
        RECT  0 414.24 0.084 414.264 ;
    END
  END b[498]
  PIN b[499]
    DIRECTION INPUT ;
    USE SIGNAL ;
    PORT
      LAYER M4 ;
        RECT  0 414.432 0.084 414.456 ;
    END
  END b[499]
  PIN b[49]
    DIRECTION INPUT ;
    USE SIGNAL ;
    PORT
      LAYER M4 ;
        RECT  0 38.736 0.084 38.76 ;
    END
  END b[49]
  PIN b[4]
    DIRECTION INPUT ;
    USE SIGNAL ;
    PORT
      LAYER M4 ;
        RECT  0 17.808 0.084 17.832 ;
    END
  END b[4]
  PIN b[500]
    DIRECTION INPUT ;
    USE SIGNAL ;
    PORT
      LAYER M4 ;
        RECT  0 414.624 0.084 414.648 ;
    END
  END b[500]
  PIN b[501]
    DIRECTION INPUT ;
    USE SIGNAL ;
    PORT
      LAYER M4 ;
        RECT  0 414.816 0.084 414.84 ;
    END
  END b[501]
  PIN b[502]
    DIRECTION INPUT ;
    USE SIGNAL ;
    PORT
      LAYER M4 ;
        RECT  0 415.008 0.084 415.032 ;
    END
  END b[502]
  PIN b[503]
    DIRECTION INPUT ;
    USE SIGNAL ;
    PORT
      LAYER M4 ;
        RECT  0 415.2 0.084 415.224 ;
    END
  END b[503]
  PIN b[504]
    DIRECTION INPUT ;
    USE SIGNAL ;
    PORT
      LAYER M4 ;
        RECT  0 415.392 0.084 415.416 ;
    END
  END b[504]
  PIN b[505]
    DIRECTION INPUT ;
    USE SIGNAL ;
    PORT
      LAYER M4 ;
        RECT  0 415.584 0.084 415.608 ;
    END
  END b[505]
  PIN b[506]
    DIRECTION INPUT ;
    USE SIGNAL ;
    PORT
      LAYER M4 ;
        RECT  0 415.776 0.084 415.8 ;
    END
  END b[506]
  PIN b[507]
    DIRECTION INPUT ;
    USE SIGNAL ;
    PORT
      LAYER M4 ;
        RECT  0 415.968 0.084 415.992 ;
    END
  END b[507]
  PIN b[508]
    DIRECTION INPUT ;
    USE SIGNAL ;
    PORT
      LAYER M4 ;
        RECT  0 416.16 0.084 416.184 ;
    END
  END b[508]
  PIN b[509]
    DIRECTION INPUT ;
    USE SIGNAL ;
    PORT
      LAYER M4 ;
        RECT  0 416.352 0.084 416.376 ;
    END
  END b[509]
  PIN b[50]
    DIRECTION INPUT ;
    USE SIGNAL ;
    PORT
      LAYER M4 ;
        RECT  0 38.928 0.084 38.952 ;
    END
  END b[50]
  PIN b[510]
    DIRECTION INPUT ;
    USE SIGNAL ;
    PORT
      LAYER M4 ;
        RECT  0 416.544 0.084 416.568 ;
    END
  END b[510]
  PIN b[511]
    DIRECTION INPUT ;
    USE SIGNAL ;
    PORT
      LAYER M4 ;
        RECT  0 416.736 0.084 416.76 ;
    END
  END b[511]
  PIN b[51]
    DIRECTION INPUT ;
    USE SIGNAL ;
    PORT
      LAYER M4 ;
        RECT  0 39.12 0.084 39.144 ;
    END
  END b[51]
  PIN b[52]
    DIRECTION INPUT ;
    USE SIGNAL ;
    PORT
      LAYER M4 ;
        RECT  0 39.312 0.084 39.336 ;
    END
  END b[52]
  PIN b[53]
    DIRECTION INPUT ;
    USE SIGNAL ;
    PORT
      LAYER M4 ;
        RECT  0 39.504 0.084 39.528 ;
    END
  END b[53]
  PIN b[54]
    DIRECTION INPUT ;
    USE SIGNAL ;
    PORT
      LAYER M4 ;
        RECT  0 39.696 0.084 39.72 ;
    END
  END b[54]
  PIN b[55]
    DIRECTION INPUT ;
    USE SIGNAL ;
    PORT
      LAYER M4 ;
        RECT  0 39.888 0.084 39.912 ;
    END
  END b[55]
  PIN b[56]
    DIRECTION INPUT ;
    USE SIGNAL ;
    PORT
      LAYER M4 ;
        RECT  0 40.08 0.084 40.104 ;
    END
  END b[56]
  PIN b[57]
    DIRECTION INPUT ;
    USE SIGNAL ;
    PORT
      LAYER M4 ;
        RECT  0 40.272 0.084 40.296 ;
    END
  END b[57]
  PIN b[58]
    DIRECTION INPUT ;
    USE SIGNAL ;
    PORT
      LAYER M4 ;
        RECT  0 40.464 0.084 40.488 ;
    END
  END b[58]
  PIN b[59]
    DIRECTION INPUT ;
    USE SIGNAL ;
    PORT
      LAYER M4 ;
        RECT  0 40.656 0.084 40.68 ;
    END
  END b[59]
  PIN b[5]
    DIRECTION INPUT ;
    USE SIGNAL ;
    PORT
      LAYER M4 ;
        RECT  0 18 0.084 18.024 ;
    END
  END b[5]
  PIN b[60]
    DIRECTION INPUT ;
    USE SIGNAL ;
    PORT
      LAYER M4 ;
        RECT  0 40.848 0.084 40.872 ;
    END
  END b[60]
  PIN b[61]
    DIRECTION INPUT ;
    USE SIGNAL ;
    PORT
      LAYER M4 ;
        RECT  0 41.04 0.084 41.064 ;
    END
  END b[61]
  PIN b[62]
    DIRECTION INPUT ;
    USE SIGNAL ;
    PORT
      LAYER M4 ;
        RECT  0 41.232 0.084 41.256 ;
    END
  END b[62]
  PIN b[63]
    DIRECTION INPUT ;
    USE SIGNAL ;
    PORT
      LAYER M4 ;
        RECT  0 41.424 0.084 41.448 ;
    END
  END b[63]
  PIN b[64]
    DIRECTION INPUT ;
    USE SIGNAL ;
    PORT
      LAYER M4 ;
        RECT  0 53.904 0.084 53.928 ;
    END
  END b[64]
  PIN b[65]
    DIRECTION INPUT ;
    USE SIGNAL ;
    PORT
      LAYER M4 ;
        RECT  0 54.096 0.084 54.12 ;
    END
  END b[65]
  PIN b[66]
    DIRECTION INPUT ;
    USE SIGNAL ;
    PORT
      LAYER M4 ;
        RECT  0 54.288 0.084 54.312 ;
    END
  END b[66]
  PIN b[67]
    DIRECTION INPUT ;
    USE SIGNAL ;
    PORT
      LAYER M4 ;
        RECT  0 54.48 0.084 54.504 ;
    END
  END b[67]
  PIN b[68]
    DIRECTION INPUT ;
    USE SIGNAL ;
    PORT
      LAYER M4 ;
        RECT  0 54.672 0.084 54.696 ;
    END
  END b[68]
  PIN b[69]
    DIRECTION INPUT ;
    USE SIGNAL ;
    PORT
      LAYER M4 ;
        RECT  0 54.864 0.084 54.888 ;
    END
  END b[69]
  PIN b[6]
    DIRECTION INPUT ;
    USE SIGNAL ;
    PORT
      LAYER M4 ;
        RECT  0 18.192 0.084 18.216 ;
    END
  END b[6]
  PIN b[70]
    DIRECTION INPUT ;
    USE SIGNAL ;
    PORT
      LAYER M4 ;
        RECT  0 55.056 0.084 55.08 ;
    END
  END b[70]
  PIN b[71]
    DIRECTION INPUT ;
    USE SIGNAL ;
    PORT
      LAYER M4 ;
        RECT  0 55.248 0.084 55.272 ;
    END
  END b[71]
  PIN b[72]
    DIRECTION INPUT ;
    USE SIGNAL ;
    PORT
      LAYER M4 ;
        RECT  0 55.44 0.084 55.464 ;
    END
  END b[72]
  PIN b[73]
    DIRECTION INPUT ;
    USE SIGNAL ;
    PORT
      LAYER M4 ;
        RECT  0 55.632 0.084 55.656 ;
    END
  END b[73]
  PIN b[74]
    DIRECTION INPUT ;
    USE SIGNAL ;
    PORT
      LAYER M4 ;
        RECT  0 55.824 0.084 55.848 ;
    END
  END b[74]
  PIN b[75]
    DIRECTION INPUT ;
    USE SIGNAL ;
    PORT
      LAYER M4 ;
        RECT  0 56.016 0.084 56.04 ;
    END
  END b[75]
  PIN b[76]
    DIRECTION INPUT ;
    USE SIGNAL ;
    PORT
      LAYER M4 ;
        RECT  0 56.208 0.084 56.232 ;
    END
  END b[76]
  PIN b[77]
    DIRECTION INPUT ;
    USE SIGNAL ;
    PORT
      LAYER M4 ;
        RECT  0 56.4 0.084 56.424 ;
    END
  END b[77]
  PIN b[78]
    DIRECTION INPUT ;
    USE SIGNAL ;
    PORT
      LAYER M4 ;
        RECT  0 56.592 0.084 56.616 ;
    END
  END b[78]
  PIN b[79]
    DIRECTION INPUT ;
    USE SIGNAL ;
    PORT
      LAYER M4 ;
        RECT  0 56.784 0.084 56.808 ;
    END
  END b[79]
  PIN b[7]
    DIRECTION INPUT ;
    USE SIGNAL ;
    PORT
      LAYER M4 ;
        RECT  0 18.384 0.084 18.408 ;
    END
  END b[7]
  PIN b[80]
    DIRECTION INPUT ;
    USE SIGNAL ;
    PORT
      LAYER M4 ;
        RECT  0 56.976 0.084 57 ;
    END
  END b[80]
  PIN b[81]
    DIRECTION INPUT ;
    USE SIGNAL ;
    PORT
      LAYER M4 ;
        RECT  0 57.168 0.084 57.192 ;
    END
  END b[81]
  PIN b[82]
    DIRECTION INPUT ;
    USE SIGNAL ;
    PORT
      LAYER M4 ;
        RECT  0 57.36 0.084 57.384 ;
    END
  END b[82]
  PIN b[83]
    DIRECTION INPUT ;
    USE SIGNAL ;
    PORT
      LAYER M4 ;
        RECT  0 57.552 0.084 57.576 ;
    END
  END b[83]
  PIN b[84]
    DIRECTION INPUT ;
    USE SIGNAL ;
    PORT
      LAYER M4 ;
        RECT  0 57.744 0.084 57.768 ;
    END
  END b[84]
  PIN b[85]
    DIRECTION INPUT ;
    USE SIGNAL ;
    PORT
      LAYER M4 ;
        RECT  0 57.936 0.084 57.96 ;
    END
  END b[85]
  PIN b[86]
    DIRECTION INPUT ;
    USE SIGNAL ;
    PORT
      LAYER M4 ;
        RECT  0 58.128 0.084 58.152 ;
    END
  END b[86]
  PIN b[87]
    DIRECTION INPUT ;
    USE SIGNAL ;
    PORT
      LAYER M4 ;
        RECT  0 58.32 0.084 58.344 ;
    END
  END b[87]
  PIN b[88]
    DIRECTION INPUT ;
    USE SIGNAL ;
    PORT
      LAYER M4 ;
        RECT  0 58.512 0.084 58.536 ;
    END
  END b[88]
  PIN b[89]
    DIRECTION INPUT ;
    USE SIGNAL ;
    PORT
      LAYER M4 ;
        RECT  0 58.704 0.084 58.728 ;
    END
  END b[89]
  PIN b[8]
    DIRECTION INPUT ;
    USE SIGNAL ;
    PORT
      LAYER M4 ;
        RECT  0 18.576 0.084 18.6 ;
    END
  END b[8]
  PIN b[90]
    DIRECTION INPUT ;
    USE SIGNAL ;
    PORT
      LAYER M4 ;
        RECT  0 58.896 0.084 58.92 ;
    END
  END b[90]
  PIN b[91]
    DIRECTION INPUT ;
    USE SIGNAL ;
    PORT
      LAYER M4 ;
        RECT  0 59.088 0.084 59.112 ;
    END
  END b[91]
  PIN b[92]
    DIRECTION INPUT ;
    USE SIGNAL ;
    PORT
      LAYER M4 ;
        RECT  0 59.28 0.084 59.304 ;
    END
  END b[92]
  PIN b[93]
    DIRECTION INPUT ;
    USE SIGNAL ;
    PORT
      LAYER M4 ;
        RECT  0 59.472 0.084 59.496 ;
    END
  END b[93]
  PIN b[94]
    DIRECTION INPUT ;
    USE SIGNAL ;
    PORT
      LAYER M4 ;
        RECT  0 59.664 0.084 59.688 ;
    END
  END b[94]
  PIN b[95]
    DIRECTION INPUT ;
    USE SIGNAL ;
    PORT
      LAYER M4 ;
        RECT  0 59.856 0.084 59.88 ;
    END
  END b[95]
  PIN b[96]
    DIRECTION INPUT ;
    USE SIGNAL ;
    PORT
      LAYER M4 ;
        RECT  0 72.336 0.084 72.36 ;
    END
  END b[96]
  PIN b[97]
    DIRECTION INPUT ;
    USE SIGNAL ;
    PORT
      LAYER M4 ;
        RECT  0 72.528 0.084 72.552 ;
    END
  END b[97]
  PIN b[98]
    DIRECTION INPUT ;
    USE SIGNAL ;
    PORT
      LAYER M4 ;
        RECT  0 72.72 0.084 72.744 ;
    END
  END b[98]
  PIN b[99]
    DIRECTION INPUT ;
    USE SIGNAL ;
    PORT
      LAYER M4 ;
        RECT  0 72.912 0.084 72.936 ;
    END
  END b[99]
  PIN b[9]
    DIRECTION INPUT ;
    USE SIGNAL ;
    PORT
      LAYER M4 ;
        RECT  0 18.768 0.084 18.792 ;
    END
  END b[9]
  PIN clk
    DIRECTION INPUT ;
    USE SIGNAL ;
    PORT
      LAYER M5 ;
        RECT  23.748 215.76 23.796 216.24 ;
    END
  END clk
  PIN fault
    DIRECTION OUTPUT ;
    USE SIGNAL ;
    PORT
      LAYER M4 ;
        RECT  47.436 192 47.52 192.024 ;
    END
  END fault
  PIN rst_n
    DIRECTION INPUT ;
    USE SIGNAL ;
    PORT
      LAYER M4 ;
        RECT  47.436 198 47.52 198.024 ;
    END
  END rst_n
  PIN t_d[0]
    DIRECTION INPUT ;
    USE SIGNAL ;
    PORT
      LAYER M4 ;
        RECT  47.436 211.968 47.52 211.992 ;
    END
  END t_d[0]
  PIN t_d[100]
    DIRECTION INPUT ;
    USE SIGNAL ;
    PORT
      LAYER M4 ;
        RECT  47.436 231.408 47.52 231.432 ;
    END
  END t_d[100]
  PIN t_d[101]
    DIRECTION INPUT ;
    USE SIGNAL ;
    PORT
      LAYER M4 ;
        RECT  47.436 231.6 47.52 231.624 ;
    END
  END t_d[101]
  PIN t_d[102]
    DIRECTION INPUT ;
    USE SIGNAL ;
    PORT
      LAYER M4 ;
        RECT  47.436 231.792 47.52 231.816 ;
    END
  END t_d[102]
  PIN t_d[103]
    DIRECTION INPUT ;
    USE SIGNAL ;
    PORT
      LAYER M4 ;
        RECT  47.436 231.984 47.52 232.008 ;
    END
  END t_d[103]
  PIN t_d[104]
    DIRECTION INPUT ;
    USE SIGNAL ;
    PORT
      LAYER M4 ;
        RECT  47.436 232.176 47.52 232.2 ;
    END
  END t_d[104]
  PIN t_d[105]
    DIRECTION INPUT ;
    USE SIGNAL ;
    PORT
      LAYER M4 ;
        RECT  47.436 232.368 47.52 232.392 ;
    END
  END t_d[105]
  PIN t_d[106]
    DIRECTION INPUT ;
    USE SIGNAL ;
    PORT
      LAYER M4 ;
        RECT  47.436 232.608 47.52 232.632 ;
    END
  END t_d[106]
  PIN t_d[107]
    DIRECTION INPUT ;
    USE SIGNAL ;
    PORT
      LAYER M4 ;
        RECT  47.436 232.8 47.52 232.824 ;
    END
  END t_d[107]
  PIN t_d[108]
    DIRECTION INPUT ;
    USE SIGNAL ;
    PORT
      LAYER M4 ;
        RECT  47.436 232.992 47.52 233.016 ;
    END
  END t_d[108]
  PIN t_d[109]
    DIRECTION INPUT ;
    USE SIGNAL ;
    PORT
      LAYER M4 ;
        RECT  47.436 233.184 47.52 233.208 ;
    END
  END t_d[109]
  PIN t_d[10]
    DIRECTION INPUT ;
    USE SIGNAL ;
    PORT
      LAYER M4 ;
        RECT  47.436 213.936 47.52 213.96 ;
    END
  END t_d[10]
  PIN t_d[110]
    DIRECTION INPUT ;
    USE SIGNAL ;
    PORT
      LAYER M4 ;
        RECT  47.436 233.376 47.52 233.4 ;
    END
  END t_d[110]
  PIN t_d[111]
    DIRECTION INPUT ;
    USE SIGNAL ;
    PORT
      LAYER M4 ;
        RECT  47.436 233.568 47.52 233.592 ;
    END
  END t_d[111]
  PIN t_d[112]
    DIRECTION INPUT ;
    USE SIGNAL ;
    PORT
      LAYER M4 ;
        RECT  47.436 233.76 47.52 233.784 ;
    END
  END t_d[112]
  PIN t_d[113]
    DIRECTION INPUT ;
    USE SIGNAL ;
    PORT
      LAYER M4 ;
        RECT  47.436 233.952 47.52 233.976 ;
    END
  END t_d[113]
  PIN t_d[114]
    DIRECTION INPUT ;
    USE SIGNAL ;
    PORT
      LAYER M4 ;
        RECT  47.436 234.144 47.52 234.168 ;
    END
  END t_d[114]
  PIN t_d[115]
    DIRECTION INPUT ;
    USE SIGNAL ;
    PORT
      LAYER M4 ;
        RECT  47.436 234.336 47.52 234.36 ;
    END
  END t_d[115]
  PIN t_d[116]
    DIRECTION INPUT ;
    USE SIGNAL ;
    PORT
      LAYER M4 ;
        RECT  47.436 234.528 47.52 234.552 ;
    END
  END t_d[116]
  PIN t_d[117]
    DIRECTION INPUT ;
    USE SIGNAL ;
    PORT
      LAYER M4 ;
        RECT  47.436 234.72 47.52 234.744 ;
    END
  END t_d[117]
  PIN t_d[118]
    DIRECTION INPUT ;
    USE SIGNAL ;
    PORT
      LAYER M4 ;
        RECT  47.436 234.912 47.52 234.936 ;
    END
  END t_d[118]
  PIN t_d[119]
    DIRECTION INPUT ;
    USE SIGNAL ;
    PORT
      LAYER M4 ;
        RECT  47.436 235.104 47.52 235.128 ;
    END
  END t_d[119]
  PIN t_d[11]
    DIRECTION INPUT ;
    USE SIGNAL ;
    PORT
      LAYER M4 ;
        RECT  47.436 214.128 47.52 214.152 ;
    END
  END t_d[11]
  PIN t_d[120]
    DIRECTION INPUT ;
    USE SIGNAL ;
    PORT
      LAYER M4 ;
        RECT  47.436 235.296 47.52 235.32 ;
    END
  END t_d[120]
  PIN t_d[121]
    DIRECTION INPUT ;
    USE SIGNAL ;
    PORT
      LAYER M4 ;
        RECT  47.436 235.488 47.52 235.512 ;
    END
  END t_d[121]
  PIN t_d[122]
    DIRECTION INPUT ;
    USE SIGNAL ;
    PORT
      LAYER M4 ;
        RECT  47.436 235.68 47.52 235.704 ;
    END
  END t_d[122]
  PIN t_d[123]
    DIRECTION INPUT ;
    USE SIGNAL ;
    PORT
      LAYER M4 ;
        RECT  47.436 235.872 47.52 235.896 ;
    END
  END t_d[123]
  PIN t_d[124]
    DIRECTION INPUT ;
    USE SIGNAL ;
    PORT
      LAYER M4 ;
        RECT  47.436 236.064 47.52 236.088 ;
    END
  END t_d[124]
  PIN t_d[125]
    DIRECTION INPUT ;
    USE SIGNAL ;
    PORT
      LAYER M4 ;
        RECT  47.436 236.256 47.52 236.28 ;
    END
  END t_d[125]
  PIN t_d[126]
    DIRECTION INPUT ;
    USE SIGNAL ;
    PORT
      LAYER M4 ;
        RECT  47.436 236.448 47.52 236.472 ;
    END
  END t_d[126]
  PIN t_d[127]
    DIRECTION INPUT ;
    USE SIGNAL ;
    PORT
      LAYER M4 ;
        RECT  47.436 236.688 47.52 236.712 ;
    END
  END t_d[127]
  PIN t_d[128]
    DIRECTION INPUT ;
    USE SIGNAL ;
    PORT
      LAYER M4 ;
        RECT  47.436 236.88 47.52 236.904 ;
    END
  END t_d[128]
  PIN t_d[129]
    DIRECTION INPUT ;
    USE SIGNAL ;
    PORT
      LAYER M4 ;
        RECT  47.436 237.072 47.52 237.096 ;
    END
  END t_d[129]
  PIN t_d[12]
    DIRECTION INPUT ;
    USE SIGNAL ;
    PORT
      LAYER M4 ;
        RECT  47.436 214.32 47.52 214.344 ;
    END
  END t_d[12]
  PIN t_d[130]
    DIRECTION INPUT ;
    USE SIGNAL ;
    PORT
      LAYER M4 ;
        RECT  47.436 237.264 47.52 237.288 ;
    END
  END t_d[130]
  PIN t_d[131]
    DIRECTION INPUT ;
    USE SIGNAL ;
    PORT
      LAYER M4 ;
        RECT  47.436 237.456 47.52 237.48 ;
    END
  END t_d[131]
  PIN t_d[132]
    DIRECTION INPUT ;
    USE SIGNAL ;
    PORT
      LAYER M4 ;
        RECT  47.436 237.648 47.52 237.672 ;
    END
  END t_d[132]
  PIN t_d[133]
    DIRECTION INPUT ;
    USE SIGNAL ;
    PORT
      LAYER M4 ;
        RECT  47.436 237.84 47.52 237.864 ;
    END
  END t_d[133]
  PIN t_d[134]
    DIRECTION INPUT ;
    USE SIGNAL ;
    PORT
      LAYER M4 ;
        RECT  47.436 238.032 47.52 238.056 ;
    END
  END t_d[134]
  PIN t_d[135]
    DIRECTION INPUT ;
    USE SIGNAL ;
    PORT
      LAYER M4 ;
        RECT  47.436 238.224 47.52 238.248 ;
    END
  END t_d[135]
  PIN t_d[136]
    DIRECTION INPUT ;
    USE SIGNAL ;
    PORT
      LAYER M4 ;
        RECT  47.436 238.416 47.52 238.44 ;
    END
  END t_d[136]
  PIN t_d[137]
    DIRECTION INPUT ;
    USE SIGNAL ;
    PORT
      LAYER M4 ;
        RECT  47.436 238.608 47.52 238.632 ;
    END
  END t_d[137]
  PIN t_d[138]
    DIRECTION INPUT ;
    USE SIGNAL ;
    PORT
      LAYER M4 ;
        RECT  47.436 238.8 47.52 238.824 ;
    END
  END t_d[138]
  PIN t_d[139]
    DIRECTION INPUT ;
    USE SIGNAL ;
    PORT
      LAYER M4 ;
        RECT  47.436 238.992 47.52 239.016 ;
    END
  END t_d[139]
  PIN t_d[13]
    DIRECTION INPUT ;
    USE SIGNAL ;
    PORT
      LAYER M4 ;
        RECT  47.436 214.512 47.52 214.536 ;
    END
  END t_d[13]
  PIN t_d[140]
    DIRECTION INPUT ;
    USE SIGNAL ;
    PORT
      LAYER M4 ;
        RECT  47.436 239.184 47.52 239.208 ;
    END
  END t_d[140]
  PIN t_d[141]
    DIRECTION INPUT ;
    USE SIGNAL ;
    PORT
      LAYER M4 ;
        RECT  47.436 239.376 47.52 239.4 ;
    END
  END t_d[141]
  PIN t_d[142]
    DIRECTION INPUT ;
    USE SIGNAL ;
    PORT
      LAYER M4 ;
        RECT  47.436 239.568 47.52 239.592 ;
    END
  END t_d[142]
  PIN t_d[143]
    DIRECTION INPUT ;
    USE SIGNAL ;
    PORT
      LAYER M4 ;
        RECT  47.436 239.76 47.52 239.784 ;
    END
  END t_d[143]
  PIN t_d[144]
    DIRECTION INPUT ;
    USE SIGNAL ;
    PORT
      LAYER M4 ;
        RECT  47.436 239.952 47.52 239.976 ;
    END
  END t_d[144]
  PIN t_d[145]
    DIRECTION INPUT ;
    USE SIGNAL ;
    PORT
      LAYER M4 ;
        RECT  47.436 240.144 47.52 240.168 ;
    END
  END t_d[145]
  PIN t_d[146]
    DIRECTION INPUT ;
    USE SIGNAL ;
    PORT
      LAYER M4 ;
        RECT  47.436 240.336 47.52 240.36 ;
    END
  END t_d[146]
  PIN t_d[147]
    DIRECTION INPUT ;
    USE SIGNAL ;
    PORT
      LAYER M4 ;
        RECT  47.436 240.576 47.52 240.6 ;
    END
  END t_d[147]
  PIN t_d[148]
    DIRECTION INPUT ;
    USE SIGNAL ;
    PORT
      LAYER M4 ;
        RECT  47.436 240.768 47.52 240.792 ;
    END
  END t_d[148]
  PIN t_d[149]
    DIRECTION INPUT ;
    USE SIGNAL ;
    PORT
      LAYER M4 ;
        RECT  47.436 240.96 47.52 240.984 ;
    END
  END t_d[149]
  PIN t_d[14]
    DIRECTION INPUT ;
    USE SIGNAL ;
    PORT
      LAYER M4 ;
        RECT  47.436 214.704 47.52 214.728 ;
    END
  END t_d[14]
  PIN t_d[150]
    DIRECTION INPUT ;
    USE SIGNAL ;
    PORT
      LAYER M4 ;
        RECT  47.436 241.152 47.52 241.176 ;
    END
  END t_d[150]
  PIN t_d[151]
    DIRECTION INPUT ;
    USE SIGNAL ;
    PORT
      LAYER M4 ;
        RECT  47.436 241.344 47.52 241.368 ;
    END
  END t_d[151]
  PIN t_d[152]
    DIRECTION INPUT ;
    USE SIGNAL ;
    PORT
      LAYER M4 ;
        RECT  47.436 241.536 47.52 241.56 ;
    END
  END t_d[152]
  PIN t_d[153]
    DIRECTION INPUT ;
    USE SIGNAL ;
    PORT
      LAYER M4 ;
        RECT  47.436 241.728 47.52 241.752 ;
    END
  END t_d[153]
  PIN t_d[154]
    DIRECTION INPUT ;
    USE SIGNAL ;
    PORT
      LAYER M4 ;
        RECT  47.436 241.92 47.52 241.944 ;
    END
  END t_d[154]
  PIN t_d[155]
    DIRECTION INPUT ;
    USE SIGNAL ;
    PORT
      LAYER M4 ;
        RECT  47.436 242.112 47.52 242.136 ;
    END
  END t_d[155]
  PIN t_d[156]
    DIRECTION INPUT ;
    USE SIGNAL ;
    PORT
      LAYER M4 ;
        RECT  47.436 242.304 47.52 242.328 ;
    END
  END t_d[156]
  PIN t_d[157]
    DIRECTION INPUT ;
    USE SIGNAL ;
    PORT
      LAYER M4 ;
        RECT  47.436 242.496 47.52 242.52 ;
    END
  END t_d[157]
  PIN t_d[158]
    DIRECTION INPUT ;
    USE SIGNAL ;
    PORT
      LAYER M4 ;
        RECT  47.436 242.688 47.52 242.712 ;
    END
  END t_d[158]
  PIN t_d[159]
    DIRECTION INPUT ;
    USE SIGNAL ;
    PORT
      LAYER M4 ;
        RECT  47.436 242.88 47.52 242.904 ;
    END
  END t_d[159]
  PIN t_d[15]
    DIRECTION INPUT ;
    USE SIGNAL ;
    PORT
      LAYER M4 ;
        RECT  47.436 214.896 47.52 214.92 ;
    END
  END t_d[15]
  PIN t_d[160]
    DIRECTION INPUT ;
    USE SIGNAL ;
    PORT
      LAYER M4 ;
        RECT  47.436 243.072 47.52 243.096 ;
    END
  END t_d[160]
  PIN t_d[161]
    DIRECTION INPUT ;
    USE SIGNAL ;
    PORT
      LAYER M4 ;
        RECT  47.436 243.264 47.52 243.288 ;
    END
  END t_d[161]
  PIN t_d[162]
    DIRECTION INPUT ;
    USE SIGNAL ;
    PORT
      LAYER M4 ;
        RECT  47.436 243.456 47.52 243.48 ;
    END
  END t_d[162]
  PIN t_d[163]
    DIRECTION INPUT ;
    USE SIGNAL ;
    PORT
      LAYER M4 ;
        RECT  47.436 243.648 47.52 243.672 ;
    END
  END t_d[163]
  PIN t_d[164]
    DIRECTION INPUT ;
    USE SIGNAL ;
    PORT
      LAYER M4 ;
        RECT  47.436 243.84 47.52 243.864 ;
    END
  END t_d[164]
  PIN t_d[165]
    DIRECTION INPUT ;
    USE SIGNAL ;
    PORT
      LAYER M4 ;
        RECT  47.436 244.032 47.52 244.056 ;
    END
  END t_d[165]
  PIN t_d[166]
    DIRECTION INPUT ;
    USE SIGNAL ;
    PORT
      LAYER M4 ;
        RECT  47.436 244.224 47.52 244.248 ;
    END
  END t_d[166]
  PIN t_d[167]
    DIRECTION INPUT ;
    USE SIGNAL ;
    PORT
      LAYER M4 ;
        RECT  47.436 244.416 47.52 244.44 ;
    END
  END t_d[167]
  PIN t_d[168]
    DIRECTION INPUT ;
    USE SIGNAL ;
    PORT
      LAYER M4 ;
        RECT  47.436 244.656 47.52 244.68 ;
    END
  END t_d[168]
  PIN t_d[169]
    DIRECTION INPUT ;
    USE SIGNAL ;
    PORT
      LAYER M4 ;
        RECT  47.436 244.848 47.52 244.872 ;
    END
  END t_d[169]
  PIN t_d[16]
    DIRECTION INPUT ;
    USE SIGNAL ;
    PORT
      LAYER M4 ;
        RECT  47.436 215.088 47.52 215.112 ;
    END
  END t_d[16]
  PIN t_d[170]
    DIRECTION INPUT ;
    USE SIGNAL ;
    PORT
      LAYER M4 ;
        RECT  47.436 245.04 47.52 245.064 ;
    END
  END t_d[170]
  PIN t_d[171]
    DIRECTION INPUT ;
    USE SIGNAL ;
    PORT
      LAYER M4 ;
        RECT  47.436 245.232 47.52 245.256 ;
    END
  END t_d[171]
  PIN t_d[172]
    DIRECTION INPUT ;
    USE SIGNAL ;
    PORT
      LAYER M4 ;
        RECT  47.436 245.424 47.52 245.448 ;
    END
  END t_d[172]
  PIN t_d[173]
    DIRECTION INPUT ;
    USE SIGNAL ;
    PORT
      LAYER M4 ;
        RECT  47.436 245.616 47.52 245.64 ;
    END
  END t_d[173]
  PIN t_d[174]
    DIRECTION INPUT ;
    USE SIGNAL ;
    PORT
      LAYER M4 ;
        RECT  47.436 245.808 47.52 245.832 ;
    END
  END t_d[174]
  PIN t_d[175]
    DIRECTION INPUT ;
    USE SIGNAL ;
    PORT
      LAYER M4 ;
        RECT  47.436 246 47.52 246.024 ;
    END
  END t_d[175]
  PIN t_d[176]
    DIRECTION INPUT ;
    USE SIGNAL ;
    PORT
      LAYER M4 ;
        RECT  47.436 246.192 47.52 246.216 ;
    END
  END t_d[176]
  PIN t_d[177]
    DIRECTION INPUT ;
    USE SIGNAL ;
    PORT
      LAYER M4 ;
        RECT  47.436 246.384 47.52 246.408 ;
    END
  END t_d[177]
  PIN t_d[178]
    DIRECTION INPUT ;
    USE SIGNAL ;
    PORT
      LAYER M4 ;
        RECT  47.436 246.576 47.52 246.6 ;
    END
  END t_d[178]
  PIN t_d[179]
    DIRECTION INPUT ;
    USE SIGNAL ;
    PORT
      LAYER M4 ;
        RECT  47.436 246.768 47.52 246.792 ;
    END
  END t_d[179]
  PIN t_d[17]
    DIRECTION INPUT ;
    USE SIGNAL ;
    PORT
      LAYER M4 ;
        RECT  47.436 215.28 47.52 215.304 ;
    END
  END t_d[17]
  PIN t_d[180]
    DIRECTION INPUT ;
    USE SIGNAL ;
    PORT
      LAYER M4 ;
        RECT  47.436 246.96 47.52 246.984 ;
    END
  END t_d[180]
  PIN t_d[181]
    DIRECTION INPUT ;
    USE SIGNAL ;
    PORT
      LAYER M4 ;
        RECT  47.436 247.152 47.52 247.176 ;
    END
  END t_d[181]
  PIN t_d[182]
    DIRECTION INPUT ;
    USE SIGNAL ;
    PORT
      LAYER M4 ;
        RECT  47.436 247.344 47.52 247.368 ;
    END
  END t_d[182]
  PIN t_d[183]
    DIRECTION INPUT ;
    USE SIGNAL ;
    PORT
      LAYER M4 ;
        RECT  47.436 247.536 47.52 247.56 ;
    END
  END t_d[183]
  PIN t_d[184]
    DIRECTION INPUT ;
    USE SIGNAL ;
    PORT
      LAYER M4 ;
        RECT  47.436 247.728 47.52 247.752 ;
    END
  END t_d[184]
  PIN t_d[185]
    DIRECTION INPUT ;
    USE SIGNAL ;
    PORT
      LAYER M4 ;
        RECT  47.436 247.92 47.52 247.944 ;
    END
  END t_d[185]
  PIN t_d[186]
    DIRECTION INPUT ;
    USE SIGNAL ;
    PORT
      LAYER M4 ;
        RECT  47.436 248.112 47.52 248.136 ;
    END
  END t_d[186]
  PIN t_d[187]
    DIRECTION INPUT ;
    USE SIGNAL ;
    PORT
      LAYER M4 ;
        RECT  47.436 248.304 47.52 248.328 ;
    END
  END t_d[187]
  PIN t_d[188]
    DIRECTION INPUT ;
    USE SIGNAL ;
    PORT
      LAYER M4 ;
        RECT  47.436 248.544 47.52 248.568 ;
    END
  END t_d[188]
  PIN t_d[189]
    DIRECTION INPUT ;
    USE SIGNAL ;
    PORT
      LAYER M4 ;
        RECT  47.436 248.736 47.52 248.76 ;
    END
  END t_d[189]
  PIN t_d[18]
    DIRECTION INPUT ;
    USE SIGNAL ;
    PORT
      LAYER M4 ;
        RECT  47.436 215.472 47.52 215.496 ;
    END
  END t_d[18]
  PIN t_d[190]
    DIRECTION INPUT ;
    USE SIGNAL ;
    PORT
      LAYER M4 ;
        RECT  47.436 248.928 47.52 248.952 ;
    END
  END t_d[190]
  PIN t_d[191]
    DIRECTION INPUT ;
    USE SIGNAL ;
    PORT
      LAYER M4 ;
        RECT  47.436 249.12 47.52 249.144 ;
    END
  END t_d[191]
  PIN t_d[192]
    DIRECTION INPUT ;
    USE SIGNAL ;
    PORT
      LAYER M4 ;
        RECT  47.436 249.312 47.52 249.336 ;
    END
  END t_d[192]
  PIN t_d[193]
    DIRECTION INPUT ;
    USE SIGNAL ;
    PORT
      LAYER M4 ;
        RECT  47.436 249.504 47.52 249.528 ;
    END
  END t_d[193]
  PIN t_d[194]
    DIRECTION INPUT ;
    USE SIGNAL ;
    PORT
      LAYER M4 ;
        RECT  47.436 249.696 47.52 249.72 ;
    END
  END t_d[194]
  PIN t_d[195]
    DIRECTION INPUT ;
    USE SIGNAL ;
    PORT
      LAYER M4 ;
        RECT  47.436 249.888 47.52 249.912 ;
    END
  END t_d[195]
  PIN t_d[196]
    DIRECTION INPUT ;
    USE SIGNAL ;
    PORT
      LAYER M4 ;
        RECT  47.436 250.08 47.52 250.104 ;
    END
  END t_d[196]
  PIN t_d[197]
    DIRECTION INPUT ;
    USE SIGNAL ;
    PORT
      LAYER M4 ;
        RECT  47.436 250.272 47.52 250.296 ;
    END
  END t_d[197]
  PIN t_d[198]
    DIRECTION INPUT ;
    USE SIGNAL ;
    PORT
      LAYER M4 ;
        RECT  47.436 250.464 47.52 250.488 ;
    END
  END t_d[198]
  PIN t_d[199]
    DIRECTION INPUT ;
    USE SIGNAL ;
    PORT
      LAYER M4 ;
        RECT  47.436 250.656 47.52 250.68 ;
    END
  END t_d[199]
  PIN t_d[19]
    DIRECTION INPUT ;
    USE SIGNAL ;
    PORT
      LAYER M4 ;
        RECT  47.436 215.664 47.52 215.688 ;
    END
  END t_d[19]
  PIN t_d[1]
    DIRECTION INPUT ;
    USE SIGNAL ;
    PORT
      LAYER M4 ;
        RECT  47.436 212.16 47.52 212.184 ;
    END
  END t_d[1]
  PIN t_d[200]
    DIRECTION INPUT ;
    USE SIGNAL ;
    PORT
      LAYER M4 ;
        RECT  47.436 250.848 47.52 250.872 ;
    END
  END t_d[200]
  PIN t_d[201]
    DIRECTION INPUT ;
    USE SIGNAL ;
    PORT
      LAYER M4 ;
        RECT  47.436 251.04 47.52 251.064 ;
    END
  END t_d[201]
  PIN t_d[202]
    DIRECTION INPUT ;
    USE SIGNAL ;
    PORT
      LAYER M4 ;
        RECT  47.436 251.232 47.52 251.256 ;
    END
  END t_d[202]
  PIN t_d[203]
    DIRECTION INPUT ;
    USE SIGNAL ;
    PORT
      LAYER M4 ;
        RECT  47.436 251.424 47.52 251.448 ;
    END
  END t_d[203]
  PIN t_d[204]
    DIRECTION INPUT ;
    USE SIGNAL ;
    PORT
      LAYER M4 ;
        RECT  47.436 251.616 47.52 251.64 ;
    END
  END t_d[204]
  PIN t_d[205]
    DIRECTION INPUT ;
    USE SIGNAL ;
    PORT
      LAYER M4 ;
        RECT  47.436 251.808 47.52 251.832 ;
    END
  END t_d[205]
  PIN t_d[206]
    DIRECTION INPUT ;
    USE SIGNAL ;
    PORT
      LAYER M4 ;
        RECT  47.436 252 47.52 252.024 ;
    END
  END t_d[206]
  PIN t_d[207]
    DIRECTION INPUT ;
    USE SIGNAL ;
    PORT
      LAYER M4 ;
        RECT  47.436 252.192 47.52 252.216 ;
    END
  END t_d[207]
  PIN t_d[208]
    DIRECTION INPUT ;
    USE SIGNAL ;
    PORT
      LAYER M4 ;
        RECT  47.436 252.384 47.52 252.408 ;
    END
  END t_d[208]
  PIN t_d[209]
    DIRECTION INPUT ;
    USE SIGNAL ;
    PORT
      LAYER M4 ;
        RECT  47.436 252.624 47.52 252.648 ;
    END
  END t_d[209]
  PIN t_d[20]
    DIRECTION INPUT ;
    USE SIGNAL ;
    PORT
      LAYER M4 ;
        RECT  47.436 215.856 47.52 215.88 ;
    END
  END t_d[20]
  PIN t_d[210]
    DIRECTION INPUT ;
    USE SIGNAL ;
    PORT
      LAYER M4 ;
        RECT  47.436 252.816 47.52 252.84 ;
    END
  END t_d[210]
  PIN t_d[211]
    DIRECTION INPUT ;
    USE SIGNAL ;
    PORT
      LAYER M4 ;
        RECT  47.436 253.008 47.52 253.032 ;
    END
  END t_d[211]
  PIN t_d[212]
    DIRECTION INPUT ;
    USE SIGNAL ;
    PORT
      LAYER M4 ;
        RECT  47.436 253.2 47.52 253.224 ;
    END
  END t_d[212]
  PIN t_d[213]
    DIRECTION INPUT ;
    USE SIGNAL ;
    PORT
      LAYER M4 ;
        RECT  47.436 253.392 47.52 253.416 ;
    END
  END t_d[213]
  PIN t_d[214]
    DIRECTION INPUT ;
    USE SIGNAL ;
    PORT
      LAYER M4 ;
        RECT  47.436 253.584 47.52 253.608 ;
    END
  END t_d[214]
  PIN t_d[215]
    DIRECTION INPUT ;
    USE SIGNAL ;
    PORT
      LAYER M4 ;
        RECT  47.436 253.776 47.52 253.8 ;
    END
  END t_d[215]
  PIN t_d[216]
    DIRECTION INPUT ;
    USE SIGNAL ;
    PORT
      LAYER M4 ;
        RECT  47.436 253.968 47.52 253.992 ;
    END
  END t_d[216]
  PIN t_d[217]
    DIRECTION INPUT ;
    USE SIGNAL ;
    PORT
      LAYER M4 ;
        RECT  47.436 254.16 47.52 254.184 ;
    END
  END t_d[217]
  PIN t_d[218]
    DIRECTION INPUT ;
    USE SIGNAL ;
    PORT
      LAYER M4 ;
        RECT  47.436 254.352 47.52 254.376 ;
    END
  END t_d[218]
  PIN t_d[219]
    DIRECTION INPUT ;
    USE SIGNAL ;
    PORT
      LAYER M4 ;
        RECT  47.436 254.544 47.52 254.568 ;
    END
  END t_d[219]
  PIN t_d[21]
    DIRECTION INPUT ;
    USE SIGNAL ;
    PORT
      LAYER M4 ;
        RECT  47.436 216.048 47.52 216.072 ;
    END
  END t_d[21]
  PIN t_d[220]
    DIRECTION INPUT ;
    USE SIGNAL ;
    PORT
      LAYER M4 ;
        RECT  47.436 254.736 47.52 254.76 ;
    END
  END t_d[220]
  PIN t_d[221]
    DIRECTION INPUT ;
    USE SIGNAL ;
    PORT
      LAYER M4 ;
        RECT  47.436 254.928 47.52 254.952 ;
    END
  END t_d[221]
  PIN t_d[222]
    DIRECTION INPUT ;
    USE SIGNAL ;
    PORT
      LAYER M4 ;
        RECT  47.436 255.12 47.52 255.144 ;
    END
  END t_d[222]
  PIN t_d[223]
    DIRECTION INPUT ;
    USE SIGNAL ;
    PORT
      LAYER M4 ;
        RECT  47.436 255.312 47.52 255.336 ;
    END
  END t_d[223]
  PIN t_d[224]
    DIRECTION INPUT ;
    USE SIGNAL ;
    PORT
      LAYER M4 ;
        RECT  47.436 255.504 47.52 255.528 ;
    END
  END t_d[224]
  PIN t_d[225]
    DIRECTION INPUT ;
    USE SIGNAL ;
    PORT
      LAYER M4 ;
        RECT  47.436 255.696 47.52 255.72 ;
    END
  END t_d[225]
  PIN t_d[226]
    DIRECTION INPUT ;
    USE SIGNAL ;
    PORT
      LAYER M4 ;
        RECT  47.436 255.888 47.52 255.912 ;
    END
  END t_d[226]
  PIN t_d[227]
    DIRECTION INPUT ;
    USE SIGNAL ;
    PORT
      LAYER M4 ;
        RECT  47.436 256.08 47.52 256.104 ;
    END
  END t_d[227]
  PIN t_d[228]
    DIRECTION INPUT ;
    USE SIGNAL ;
    PORT
      LAYER M4 ;
        RECT  47.436 256.272 47.52 256.296 ;
    END
  END t_d[228]
  PIN t_d[229]
    DIRECTION INPUT ;
    USE SIGNAL ;
    PORT
      LAYER M4 ;
        RECT  47.436 256.512 47.52 256.536 ;
    END
  END t_d[229]
  PIN t_d[22]
    DIRECTION INPUT ;
    USE SIGNAL ;
    PORT
      LAYER M4 ;
        RECT  47.436 216.24 47.52 216.264 ;
    END
  END t_d[22]
  PIN t_d[230]
    DIRECTION INPUT ;
    USE SIGNAL ;
    PORT
      LAYER M4 ;
        RECT  47.436 256.704 47.52 256.728 ;
    END
  END t_d[230]
  PIN t_d[231]
    DIRECTION INPUT ;
    USE SIGNAL ;
    PORT
      LAYER M4 ;
        RECT  47.436 256.896 47.52 256.92 ;
    END
  END t_d[231]
  PIN t_d[232]
    DIRECTION INPUT ;
    USE SIGNAL ;
    PORT
      LAYER M4 ;
        RECT  47.436 257.088 47.52 257.112 ;
    END
  END t_d[232]
  PIN t_d[233]
    DIRECTION INPUT ;
    USE SIGNAL ;
    PORT
      LAYER M4 ;
        RECT  47.436 257.28 47.52 257.304 ;
    END
  END t_d[233]
  PIN t_d[234]
    DIRECTION INPUT ;
    USE SIGNAL ;
    PORT
      LAYER M4 ;
        RECT  47.436 257.472 47.52 257.496 ;
    END
  END t_d[234]
  PIN t_d[235]
    DIRECTION INPUT ;
    USE SIGNAL ;
    PORT
      LAYER M4 ;
        RECT  47.436 257.664 47.52 257.688 ;
    END
  END t_d[235]
  PIN t_d[236]
    DIRECTION INPUT ;
    USE SIGNAL ;
    PORT
      LAYER M4 ;
        RECT  47.436 257.856 47.52 257.88 ;
    END
  END t_d[236]
  PIN t_d[237]
    DIRECTION INPUT ;
    USE SIGNAL ;
    PORT
      LAYER M4 ;
        RECT  47.436 258.048 47.52 258.072 ;
    END
  END t_d[237]
  PIN t_d[238]
    DIRECTION INPUT ;
    USE SIGNAL ;
    PORT
      LAYER M4 ;
        RECT  47.436 258.24 47.52 258.264 ;
    END
  END t_d[238]
  PIN t_d[239]
    DIRECTION INPUT ;
    USE SIGNAL ;
    PORT
      LAYER M4 ;
        RECT  47.436 258.432 47.52 258.456 ;
    END
  END t_d[239]
  PIN t_d[23]
    DIRECTION INPUT ;
    USE SIGNAL ;
    PORT
      LAYER M4 ;
        RECT  47.436 216.432 47.52 216.456 ;
    END
  END t_d[23]
  PIN t_d[240]
    DIRECTION INPUT ;
    USE SIGNAL ;
    PORT
      LAYER M4 ;
        RECT  47.436 258.624 47.52 258.648 ;
    END
  END t_d[240]
  PIN t_d[241]
    DIRECTION INPUT ;
    USE SIGNAL ;
    PORT
      LAYER M4 ;
        RECT  47.436 258.816 47.52 258.84 ;
    END
  END t_d[241]
  PIN t_d[242]
    DIRECTION INPUT ;
    USE SIGNAL ;
    PORT
      LAYER M4 ;
        RECT  47.436 259.008 47.52 259.032 ;
    END
  END t_d[242]
  PIN t_d[243]
    DIRECTION INPUT ;
    USE SIGNAL ;
    PORT
      LAYER M4 ;
        RECT  47.436 259.2 47.52 259.224 ;
    END
  END t_d[243]
  PIN t_d[244]
    DIRECTION INPUT ;
    USE SIGNAL ;
    PORT
      LAYER M4 ;
        RECT  47.436 259.392 47.52 259.416 ;
    END
  END t_d[244]
  PIN t_d[245]
    DIRECTION INPUT ;
    USE SIGNAL ;
    PORT
      LAYER M4 ;
        RECT  47.436 259.584 47.52 259.608 ;
    END
  END t_d[245]
  PIN t_d[246]
    DIRECTION INPUT ;
    USE SIGNAL ;
    PORT
      LAYER M4 ;
        RECT  47.436 259.776 47.52 259.8 ;
    END
  END t_d[246]
  PIN t_d[247]
    DIRECTION INPUT ;
    USE SIGNAL ;
    PORT
      LAYER M4 ;
        RECT  47.436 259.968 47.52 259.992 ;
    END
  END t_d[247]
  PIN t_d[248]
    DIRECTION INPUT ;
    USE SIGNAL ;
    PORT
      LAYER M4 ;
        RECT  47.436 260.16 47.52 260.184 ;
    END
  END t_d[248]
  PIN t_d[249]
    DIRECTION INPUT ;
    USE SIGNAL ;
    PORT
      LAYER M4 ;
        RECT  47.436 260.352 47.52 260.376 ;
    END
  END t_d[249]
  PIN t_d[24]
    DIRECTION INPUT ;
    USE SIGNAL ;
    PORT
      LAYER M4 ;
        RECT  47.436 216.672 47.52 216.696 ;
    END
  END t_d[24]
  PIN t_d[250]
    DIRECTION INPUT ;
    USE SIGNAL ;
    PORT
      LAYER M4 ;
        RECT  47.436 260.592 47.52 260.616 ;
    END
  END t_d[250]
  PIN t_d[251]
    DIRECTION INPUT ;
    USE SIGNAL ;
    PORT
      LAYER M4 ;
        RECT  47.436 260.784 47.52 260.808 ;
    END
  END t_d[251]
  PIN t_d[252]
    DIRECTION INPUT ;
    USE SIGNAL ;
    PORT
      LAYER M4 ;
        RECT  47.436 260.976 47.52 261 ;
    END
  END t_d[252]
  PIN t_d[253]
    DIRECTION INPUT ;
    USE SIGNAL ;
    PORT
      LAYER M4 ;
        RECT  47.436 261.168 47.52 261.192 ;
    END
  END t_d[253]
  PIN t_d[254]
    DIRECTION INPUT ;
    USE SIGNAL ;
    PORT
      LAYER M4 ;
        RECT  47.436 261.36 47.52 261.384 ;
    END
  END t_d[254]
  PIN t_d[255]
    DIRECTION INPUT ;
    USE SIGNAL ;
    PORT
      LAYER M4 ;
        RECT  47.436 261.552 47.52 261.576 ;
    END
  END t_d[255]
  PIN t_d[256]
    DIRECTION INPUT ;
    USE SIGNAL ;
    PORT
      LAYER M4 ;
        RECT  47.436 261.744 47.52 261.768 ;
    END
  END t_d[256]
  PIN t_d[257]
    DIRECTION INPUT ;
    USE SIGNAL ;
    PORT
      LAYER M4 ;
        RECT  47.436 261.936 47.52 261.96 ;
    END
  END t_d[257]
  PIN t_d[258]
    DIRECTION INPUT ;
    USE SIGNAL ;
    PORT
      LAYER M4 ;
        RECT  47.436 262.128 47.52 262.152 ;
    END
  END t_d[258]
  PIN t_d[259]
    DIRECTION INPUT ;
    USE SIGNAL ;
    PORT
      LAYER M4 ;
        RECT  47.436 262.32 47.52 262.344 ;
    END
  END t_d[259]
  PIN t_d[25]
    DIRECTION INPUT ;
    USE SIGNAL ;
    PORT
      LAYER M4 ;
        RECT  47.436 216.864 47.52 216.888 ;
    END
  END t_d[25]
  PIN t_d[260]
    DIRECTION INPUT ;
    USE SIGNAL ;
    PORT
      LAYER M4 ;
        RECT  47.436 262.512 47.52 262.536 ;
    END
  END t_d[260]
  PIN t_d[261]
    DIRECTION INPUT ;
    USE SIGNAL ;
    PORT
      LAYER M4 ;
        RECT  47.436 262.704 47.52 262.728 ;
    END
  END t_d[261]
  PIN t_d[262]
    DIRECTION INPUT ;
    USE SIGNAL ;
    PORT
      LAYER M4 ;
        RECT  47.436 262.896 47.52 262.92 ;
    END
  END t_d[262]
  PIN t_d[263]
    DIRECTION INPUT ;
    USE SIGNAL ;
    PORT
      LAYER M4 ;
        RECT  47.436 263.088 47.52 263.112 ;
    END
  END t_d[263]
  PIN t_d[264]
    DIRECTION INPUT ;
    USE SIGNAL ;
    PORT
      LAYER M4 ;
        RECT  47.436 263.28 47.52 263.304 ;
    END
  END t_d[264]
  PIN t_d[265]
    DIRECTION INPUT ;
    USE SIGNAL ;
    PORT
      LAYER M4 ;
        RECT  47.436 263.472 47.52 263.496 ;
    END
  END t_d[265]
  PIN t_d[266]
    DIRECTION INPUT ;
    USE SIGNAL ;
    PORT
      LAYER M4 ;
        RECT  47.436 263.664 47.52 263.688 ;
    END
  END t_d[266]
  PIN t_d[267]
    DIRECTION INPUT ;
    USE SIGNAL ;
    PORT
      LAYER M4 ;
        RECT  47.436 263.856 47.52 263.88 ;
    END
  END t_d[267]
  PIN t_d[268]
    DIRECTION INPUT ;
    USE SIGNAL ;
    PORT
      LAYER M4 ;
        RECT  47.436 264.048 47.52 264.072 ;
    END
  END t_d[268]
  PIN t_d[269]
    DIRECTION INPUT ;
    USE SIGNAL ;
    PORT
      LAYER M4 ;
        RECT  47.436 264.24 47.52 264.264 ;
    END
  END t_d[269]
  PIN t_d[26]
    DIRECTION INPUT ;
    USE SIGNAL ;
    PORT
      LAYER M4 ;
        RECT  47.436 217.056 47.52 217.08 ;
    END
  END t_d[26]
  PIN t_d[270]
    DIRECTION INPUT ;
    USE SIGNAL ;
    PORT
      LAYER M4 ;
        RECT  47.436 264.48 47.52 264.504 ;
    END
  END t_d[270]
  PIN t_d[271]
    DIRECTION INPUT ;
    USE SIGNAL ;
    PORT
      LAYER M4 ;
        RECT  47.436 264.672 47.52 264.696 ;
    END
  END t_d[271]
  PIN t_d[272]
    DIRECTION INPUT ;
    USE SIGNAL ;
    PORT
      LAYER M4 ;
        RECT  47.436 264.864 47.52 264.888 ;
    END
  END t_d[272]
  PIN t_d[273]
    DIRECTION INPUT ;
    USE SIGNAL ;
    PORT
      LAYER M4 ;
        RECT  47.436 265.056 47.52 265.08 ;
    END
  END t_d[273]
  PIN t_d[274]
    DIRECTION INPUT ;
    USE SIGNAL ;
    PORT
      LAYER M4 ;
        RECT  47.436 265.248 47.52 265.272 ;
    END
  END t_d[274]
  PIN t_d[275]
    DIRECTION INPUT ;
    USE SIGNAL ;
    PORT
      LAYER M4 ;
        RECT  47.436 265.44 47.52 265.464 ;
    END
  END t_d[275]
  PIN t_d[276]
    DIRECTION INPUT ;
    USE SIGNAL ;
    PORT
      LAYER M4 ;
        RECT  47.436 265.632 47.52 265.656 ;
    END
  END t_d[276]
  PIN t_d[277]
    DIRECTION INPUT ;
    USE SIGNAL ;
    PORT
      LAYER M4 ;
        RECT  47.436 265.824 47.52 265.848 ;
    END
  END t_d[277]
  PIN t_d[278]
    DIRECTION INPUT ;
    USE SIGNAL ;
    PORT
      LAYER M4 ;
        RECT  47.436 266.016 47.52 266.04 ;
    END
  END t_d[278]
  PIN t_d[279]
    DIRECTION INPUT ;
    USE SIGNAL ;
    PORT
      LAYER M4 ;
        RECT  47.436 266.208 47.52 266.232 ;
    END
  END t_d[279]
  PIN t_d[27]
    DIRECTION INPUT ;
    USE SIGNAL ;
    PORT
      LAYER M4 ;
        RECT  47.436 217.248 47.52 217.272 ;
    END
  END t_d[27]
  PIN t_d[280]
    DIRECTION INPUT ;
    USE SIGNAL ;
    PORT
      LAYER M4 ;
        RECT  47.436 266.4 47.52 266.424 ;
    END
  END t_d[280]
  PIN t_d[281]
    DIRECTION INPUT ;
    USE SIGNAL ;
    PORT
      LAYER M4 ;
        RECT  47.436 266.592 47.52 266.616 ;
    END
  END t_d[281]
  PIN t_d[282]
    DIRECTION INPUT ;
    USE SIGNAL ;
    PORT
      LAYER M4 ;
        RECT  47.436 266.784 47.52 266.808 ;
    END
  END t_d[282]
  PIN t_d[283]
    DIRECTION INPUT ;
    USE SIGNAL ;
    PORT
      LAYER M4 ;
        RECT  47.436 266.976 47.52 267 ;
    END
  END t_d[283]
  PIN t_d[284]
    DIRECTION INPUT ;
    USE SIGNAL ;
    PORT
      LAYER M4 ;
        RECT  47.436 267.168 47.52 267.192 ;
    END
  END t_d[284]
  PIN t_d[285]
    DIRECTION INPUT ;
    USE SIGNAL ;
    PORT
      LAYER M4 ;
        RECT  47.436 267.36 47.52 267.384 ;
    END
  END t_d[285]
  PIN t_d[286]
    DIRECTION INPUT ;
    USE SIGNAL ;
    PORT
      LAYER M4 ;
        RECT  47.436 267.552 47.52 267.576 ;
    END
  END t_d[286]
  PIN t_d[287]
    DIRECTION INPUT ;
    USE SIGNAL ;
    PORT
      LAYER M4 ;
        RECT  47.436 267.744 47.52 267.768 ;
    END
  END t_d[287]
  PIN t_d[288]
    DIRECTION INPUT ;
    USE SIGNAL ;
    PORT
      LAYER M4 ;
        RECT  47.436 267.936 47.52 267.96 ;
    END
  END t_d[288]
  PIN t_d[289]
    DIRECTION INPUT ;
    USE SIGNAL ;
    PORT
      LAYER M4 ;
        RECT  47.436 268.128 47.52 268.152 ;
    END
  END t_d[289]
  PIN t_d[28]
    DIRECTION INPUT ;
    USE SIGNAL ;
    PORT
      LAYER M4 ;
        RECT  47.436 217.44 47.52 217.464 ;
    END
  END t_d[28]
  PIN t_d[290]
    DIRECTION INPUT ;
    USE SIGNAL ;
    PORT
      LAYER M4 ;
        RECT  47.436 268.32 47.52 268.344 ;
    END
  END t_d[290]
  PIN t_d[291]
    DIRECTION INPUT ;
    USE SIGNAL ;
    PORT
      LAYER M4 ;
        RECT  47.436 268.56 47.52 268.584 ;
    END
  END t_d[291]
  PIN t_d[292]
    DIRECTION INPUT ;
    USE SIGNAL ;
    PORT
      LAYER M4 ;
        RECT  47.436 268.752 47.52 268.776 ;
    END
  END t_d[292]
  PIN t_d[293]
    DIRECTION INPUT ;
    USE SIGNAL ;
    PORT
      LAYER M4 ;
        RECT  47.436 268.944 47.52 268.968 ;
    END
  END t_d[293]
  PIN t_d[294]
    DIRECTION INPUT ;
    USE SIGNAL ;
    PORT
      LAYER M4 ;
        RECT  47.436 269.136 47.52 269.16 ;
    END
  END t_d[294]
  PIN t_d[295]
    DIRECTION INPUT ;
    USE SIGNAL ;
    PORT
      LAYER M4 ;
        RECT  47.436 269.328 47.52 269.352 ;
    END
  END t_d[295]
  PIN t_d[296]
    DIRECTION INPUT ;
    USE SIGNAL ;
    PORT
      LAYER M4 ;
        RECT  47.436 269.52 47.52 269.544 ;
    END
  END t_d[296]
  PIN t_d[297]
    DIRECTION INPUT ;
    USE SIGNAL ;
    PORT
      LAYER M4 ;
        RECT  47.436 269.712 47.52 269.736 ;
    END
  END t_d[297]
  PIN t_d[298]
    DIRECTION INPUT ;
    USE SIGNAL ;
    PORT
      LAYER M4 ;
        RECT  47.436 269.904 47.52 269.928 ;
    END
  END t_d[298]
  PIN t_d[299]
    DIRECTION INPUT ;
    USE SIGNAL ;
    PORT
      LAYER M4 ;
        RECT  47.436 270.096 47.52 270.12 ;
    END
  END t_d[299]
  PIN t_d[29]
    DIRECTION INPUT ;
    USE SIGNAL ;
    PORT
      LAYER M4 ;
        RECT  47.436 217.632 47.52 217.656 ;
    END
  END t_d[29]
  PIN t_d[2]
    DIRECTION INPUT ;
    USE SIGNAL ;
    PORT
      LAYER M4 ;
        RECT  47.436 212.352 47.52 212.376 ;
    END
  END t_d[2]
  PIN t_d[300]
    DIRECTION INPUT ;
    USE SIGNAL ;
    PORT
      LAYER M4 ;
        RECT  47.436 270.288 47.52 270.312 ;
    END
  END t_d[300]
  PIN t_d[301]
    DIRECTION INPUT ;
    USE SIGNAL ;
    PORT
      LAYER M4 ;
        RECT  47.436 270.48 47.52 270.504 ;
    END
  END t_d[301]
  PIN t_d[302]
    DIRECTION INPUT ;
    USE SIGNAL ;
    PORT
      LAYER M4 ;
        RECT  47.436 270.672 47.52 270.696 ;
    END
  END t_d[302]
  PIN t_d[303]
    DIRECTION INPUT ;
    USE SIGNAL ;
    PORT
      LAYER M4 ;
        RECT  47.436 270.864 47.52 270.888 ;
    END
  END t_d[303]
  PIN t_d[304]
    DIRECTION INPUT ;
    USE SIGNAL ;
    PORT
      LAYER M4 ;
        RECT  47.436 271.056 47.52 271.08 ;
    END
  END t_d[304]
  PIN t_d[305]
    DIRECTION INPUT ;
    USE SIGNAL ;
    PORT
      LAYER M4 ;
        RECT  47.436 271.248 47.52 271.272 ;
    END
  END t_d[305]
  PIN t_d[306]
    DIRECTION INPUT ;
    USE SIGNAL ;
    PORT
      LAYER M4 ;
        RECT  47.436 271.44 47.52 271.464 ;
    END
  END t_d[306]
  PIN t_d[307]
    DIRECTION INPUT ;
    USE SIGNAL ;
    PORT
      LAYER M4 ;
        RECT  47.436 271.632 47.52 271.656 ;
    END
  END t_d[307]
  PIN t_d[308]
    DIRECTION INPUT ;
    USE SIGNAL ;
    PORT
      LAYER M4 ;
        RECT  47.436 271.824 47.52 271.848 ;
    END
  END t_d[308]
  PIN t_d[309]
    DIRECTION INPUT ;
    USE SIGNAL ;
    PORT
      LAYER M4 ;
        RECT  47.436 272.016 47.52 272.04 ;
    END
  END t_d[309]
  PIN t_d[30]
    DIRECTION INPUT ;
    USE SIGNAL ;
    PORT
      LAYER M4 ;
        RECT  47.436 217.824 47.52 217.848 ;
    END
  END t_d[30]
  PIN t_d[310]
    DIRECTION INPUT ;
    USE SIGNAL ;
    PORT
      LAYER M4 ;
        RECT  47.436 272.208 47.52 272.232 ;
    END
  END t_d[310]
  PIN t_d[311]
    DIRECTION INPUT ;
    USE SIGNAL ;
    PORT
      LAYER M4 ;
        RECT  47.436 272.448 47.52 272.472 ;
    END
  END t_d[311]
  PIN t_d[312]
    DIRECTION INPUT ;
    USE SIGNAL ;
    PORT
      LAYER M4 ;
        RECT  47.436 272.64 47.52 272.664 ;
    END
  END t_d[312]
  PIN t_d[313]
    DIRECTION INPUT ;
    USE SIGNAL ;
    PORT
      LAYER M4 ;
        RECT  47.436 272.832 47.52 272.856 ;
    END
  END t_d[313]
  PIN t_d[314]
    DIRECTION INPUT ;
    USE SIGNAL ;
    PORT
      LAYER M4 ;
        RECT  47.436 273.024 47.52 273.048 ;
    END
  END t_d[314]
  PIN t_d[315]
    DIRECTION INPUT ;
    USE SIGNAL ;
    PORT
      LAYER M4 ;
        RECT  47.436 273.216 47.52 273.24 ;
    END
  END t_d[315]
  PIN t_d[316]
    DIRECTION INPUT ;
    USE SIGNAL ;
    PORT
      LAYER M4 ;
        RECT  47.436 273.408 47.52 273.432 ;
    END
  END t_d[316]
  PIN t_d[317]
    DIRECTION INPUT ;
    USE SIGNAL ;
    PORT
      LAYER M4 ;
        RECT  47.436 273.6 47.52 273.624 ;
    END
  END t_d[317]
  PIN t_d[318]
    DIRECTION INPUT ;
    USE SIGNAL ;
    PORT
      LAYER M4 ;
        RECT  47.436 273.792 47.52 273.816 ;
    END
  END t_d[318]
  PIN t_d[319]
    DIRECTION INPUT ;
    USE SIGNAL ;
    PORT
      LAYER M4 ;
        RECT  47.436 273.984 47.52 274.008 ;
    END
  END t_d[319]
  PIN t_d[31]
    DIRECTION INPUT ;
    USE SIGNAL ;
    PORT
      LAYER M4 ;
        RECT  47.436 218.016 47.52 218.04 ;
    END
  END t_d[31]
  PIN t_d[320]
    DIRECTION INPUT ;
    USE SIGNAL ;
    PORT
      LAYER M4 ;
        RECT  47.436 274.176 47.52 274.2 ;
    END
  END t_d[320]
  PIN t_d[321]
    DIRECTION INPUT ;
    USE SIGNAL ;
    PORT
      LAYER M4 ;
        RECT  47.436 274.368 47.52 274.392 ;
    END
  END t_d[321]
  PIN t_d[322]
    DIRECTION INPUT ;
    USE SIGNAL ;
    PORT
      LAYER M4 ;
        RECT  47.436 274.56 47.52 274.584 ;
    END
  END t_d[322]
  PIN t_d[323]
    DIRECTION INPUT ;
    USE SIGNAL ;
    PORT
      LAYER M4 ;
        RECT  47.436 274.752 47.52 274.776 ;
    END
  END t_d[323]
  PIN t_d[324]
    DIRECTION INPUT ;
    USE SIGNAL ;
    PORT
      LAYER M4 ;
        RECT  47.436 274.944 47.52 274.968 ;
    END
  END t_d[324]
  PIN t_d[325]
    DIRECTION INPUT ;
    USE SIGNAL ;
    PORT
      LAYER M4 ;
        RECT  47.436 275.136 47.52 275.16 ;
    END
  END t_d[325]
  PIN t_d[326]
    DIRECTION INPUT ;
    USE SIGNAL ;
    PORT
      LAYER M4 ;
        RECT  47.436 275.328 47.52 275.352 ;
    END
  END t_d[326]
  PIN t_d[327]
    DIRECTION INPUT ;
    USE SIGNAL ;
    PORT
      LAYER M4 ;
        RECT  47.436 275.52 47.52 275.544 ;
    END
  END t_d[327]
  PIN t_d[328]
    DIRECTION INPUT ;
    USE SIGNAL ;
    PORT
      LAYER M4 ;
        RECT  47.436 275.712 47.52 275.736 ;
    END
  END t_d[328]
  PIN t_d[329]
    DIRECTION INPUT ;
    USE SIGNAL ;
    PORT
      LAYER M4 ;
        RECT  47.436 275.904 47.52 275.928 ;
    END
  END t_d[329]
  PIN t_d[32]
    DIRECTION INPUT ;
    USE SIGNAL ;
    PORT
      LAYER M4 ;
        RECT  47.436 218.208 47.52 218.232 ;
    END
  END t_d[32]
  PIN t_d[330]
    DIRECTION INPUT ;
    USE SIGNAL ;
    PORT
      LAYER M4 ;
        RECT  47.436 276.096 47.52 276.12 ;
    END
  END t_d[330]
  PIN t_d[331]
    DIRECTION INPUT ;
    USE SIGNAL ;
    PORT
      LAYER M4 ;
        RECT  47.436 276.288 47.52 276.312 ;
    END
  END t_d[331]
  PIN t_d[332]
    DIRECTION INPUT ;
    USE SIGNAL ;
    PORT
      LAYER M4 ;
        RECT  47.436 276.528 47.52 276.552 ;
    END
  END t_d[332]
  PIN t_d[333]
    DIRECTION INPUT ;
    USE SIGNAL ;
    PORT
      LAYER M4 ;
        RECT  47.436 276.72 47.52 276.744 ;
    END
  END t_d[333]
  PIN t_d[334]
    DIRECTION INPUT ;
    USE SIGNAL ;
    PORT
      LAYER M4 ;
        RECT  47.436 276.912 47.52 276.936 ;
    END
  END t_d[334]
  PIN t_d[335]
    DIRECTION INPUT ;
    USE SIGNAL ;
    PORT
      LAYER M4 ;
        RECT  47.436 277.104 47.52 277.128 ;
    END
  END t_d[335]
  PIN t_d[336]
    DIRECTION INPUT ;
    USE SIGNAL ;
    PORT
      LAYER M4 ;
        RECT  47.436 277.296 47.52 277.32 ;
    END
  END t_d[336]
  PIN t_d[337]
    DIRECTION INPUT ;
    USE SIGNAL ;
    PORT
      LAYER M4 ;
        RECT  47.436 277.488 47.52 277.512 ;
    END
  END t_d[337]
  PIN t_d[338]
    DIRECTION INPUT ;
    USE SIGNAL ;
    PORT
      LAYER M4 ;
        RECT  47.436 277.68 47.52 277.704 ;
    END
  END t_d[338]
  PIN t_d[339]
    DIRECTION INPUT ;
    USE SIGNAL ;
    PORT
      LAYER M4 ;
        RECT  47.436 277.872 47.52 277.896 ;
    END
  END t_d[339]
  PIN t_d[33]
    DIRECTION INPUT ;
    USE SIGNAL ;
    PORT
      LAYER M4 ;
        RECT  47.436 218.4 47.52 218.424 ;
    END
  END t_d[33]
  PIN t_d[340]
    DIRECTION INPUT ;
    USE SIGNAL ;
    PORT
      LAYER M4 ;
        RECT  47.436 278.064 47.52 278.088 ;
    END
  END t_d[340]
  PIN t_d[341]
    DIRECTION INPUT ;
    USE SIGNAL ;
    PORT
      LAYER M4 ;
        RECT  47.436 278.256 47.52 278.28 ;
    END
  END t_d[341]
  PIN t_d[342]
    DIRECTION INPUT ;
    USE SIGNAL ;
    PORT
      LAYER M4 ;
        RECT  47.436 278.448 47.52 278.472 ;
    END
  END t_d[342]
  PIN t_d[343]
    DIRECTION INPUT ;
    USE SIGNAL ;
    PORT
      LAYER M4 ;
        RECT  47.436 278.64 47.52 278.664 ;
    END
  END t_d[343]
  PIN t_d[344]
    DIRECTION INPUT ;
    USE SIGNAL ;
    PORT
      LAYER M4 ;
        RECT  47.436 278.832 47.52 278.856 ;
    END
  END t_d[344]
  PIN t_d[345]
    DIRECTION INPUT ;
    USE SIGNAL ;
    PORT
      LAYER M4 ;
        RECT  47.436 279.024 47.52 279.048 ;
    END
  END t_d[345]
  PIN t_d[346]
    DIRECTION INPUT ;
    USE SIGNAL ;
    PORT
      LAYER M4 ;
        RECT  47.436 279.216 47.52 279.24 ;
    END
  END t_d[346]
  PIN t_d[347]
    DIRECTION INPUT ;
    USE SIGNAL ;
    PORT
      LAYER M4 ;
        RECT  47.436 279.408 47.52 279.432 ;
    END
  END t_d[347]
  PIN t_d[348]
    DIRECTION INPUT ;
    USE SIGNAL ;
    PORT
      LAYER M4 ;
        RECT  47.436 279.6 47.52 279.624 ;
    END
  END t_d[348]
  PIN t_d[349]
    DIRECTION INPUT ;
    USE SIGNAL ;
    PORT
      LAYER M4 ;
        RECT  47.436 279.792 47.52 279.816 ;
    END
  END t_d[349]
  PIN t_d[34]
    DIRECTION INPUT ;
    USE SIGNAL ;
    PORT
      LAYER M4 ;
        RECT  47.436 218.592 47.52 218.616 ;
    END
  END t_d[34]
  PIN t_d[350]
    DIRECTION INPUT ;
    USE SIGNAL ;
    PORT
      LAYER M4 ;
        RECT  47.436 279.984 47.52 280.008 ;
    END
  END t_d[350]
  PIN t_d[351]
    DIRECTION INPUT ;
    USE SIGNAL ;
    PORT
      LAYER M4 ;
        RECT  47.436 280.176 47.52 280.2 ;
    END
  END t_d[351]
  PIN t_d[352]
    DIRECTION INPUT ;
    USE SIGNAL ;
    PORT
      LAYER M4 ;
        RECT  47.436 280.368 47.52 280.392 ;
    END
  END t_d[352]
  PIN t_d[353]
    DIRECTION INPUT ;
    USE SIGNAL ;
    PORT
      LAYER M4 ;
        RECT  47.436 280.608 47.52 280.632 ;
    END
  END t_d[353]
  PIN t_d[354]
    DIRECTION INPUT ;
    USE SIGNAL ;
    PORT
      LAYER M4 ;
        RECT  47.436 280.8 47.52 280.824 ;
    END
  END t_d[354]
  PIN t_d[355]
    DIRECTION INPUT ;
    USE SIGNAL ;
    PORT
      LAYER M4 ;
        RECT  47.436 280.992 47.52 281.016 ;
    END
  END t_d[355]
  PIN t_d[356]
    DIRECTION INPUT ;
    USE SIGNAL ;
    PORT
      LAYER M4 ;
        RECT  47.436 281.184 47.52 281.208 ;
    END
  END t_d[356]
  PIN t_d[357]
    DIRECTION INPUT ;
    USE SIGNAL ;
    PORT
      LAYER M4 ;
        RECT  47.436 281.376 47.52 281.4 ;
    END
  END t_d[357]
  PIN t_d[358]
    DIRECTION INPUT ;
    USE SIGNAL ;
    PORT
      LAYER M4 ;
        RECT  47.436 281.568 47.52 281.592 ;
    END
  END t_d[358]
  PIN t_d[359]
    DIRECTION INPUT ;
    USE SIGNAL ;
    PORT
      LAYER M4 ;
        RECT  47.436 281.76 47.52 281.784 ;
    END
  END t_d[359]
  PIN t_d[35]
    DIRECTION INPUT ;
    USE SIGNAL ;
    PORT
      LAYER M4 ;
        RECT  47.436 218.784 47.52 218.808 ;
    END
  END t_d[35]
  PIN t_d[360]
    DIRECTION INPUT ;
    USE SIGNAL ;
    PORT
      LAYER M4 ;
        RECT  47.436 281.952 47.52 281.976 ;
    END
  END t_d[360]
  PIN t_d[361]
    DIRECTION INPUT ;
    USE SIGNAL ;
    PORT
      LAYER M4 ;
        RECT  47.436 282.144 47.52 282.168 ;
    END
  END t_d[361]
  PIN t_d[362]
    DIRECTION INPUT ;
    USE SIGNAL ;
    PORT
      LAYER M4 ;
        RECT  47.436 282.336 47.52 282.36 ;
    END
  END t_d[362]
  PIN t_d[363]
    DIRECTION INPUT ;
    USE SIGNAL ;
    PORT
      LAYER M4 ;
        RECT  47.436 282.528 47.52 282.552 ;
    END
  END t_d[363]
  PIN t_d[364]
    DIRECTION INPUT ;
    USE SIGNAL ;
    PORT
      LAYER M4 ;
        RECT  47.436 282.72 47.52 282.744 ;
    END
  END t_d[364]
  PIN t_d[365]
    DIRECTION INPUT ;
    USE SIGNAL ;
    PORT
      LAYER M4 ;
        RECT  47.436 282.912 47.52 282.936 ;
    END
  END t_d[365]
  PIN t_d[366]
    DIRECTION INPUT ;
    USE SIGNAL ;
    PORT
      LAYER M4 ;
        RECT  47.436 283.104 47.52 283.128 ;
    END
  END t_d[366]
  PIN t_d[367]
    DIRECTION INPUT ;
    USE SIGNAL ;
    PORT
      LAYER M4 ;
        RECT  47.436 283.296 47.52 283.32 ;
    END
  END t_d[367]
  PIN t_d[368]
    DIRECTION INPUT ;
    USE SIGNAL ;
    PORT
      LAYER M4 ;
        RECT  47.436 283.488 47.52 283.512 ;
    END
  END t_d[368]
  PIN t_d[369]
    DIRECTION INPUT ;
    USE SIGNAL ;
    PORT
      LAYER M4 ;
        RECT  47.436 283.68 47.52 283.704 ;
    END
  END t_d[369]
  PIN t_d[36]
    DIRECTION INPUT ;
    USE SIGNAL ;
    PORT
      LAYER M4 ;
        RECT  47.436 218.976 47.52 219 ;
    END
  END t_d[36]
  PIN t_d[370]
    DIRECTION INPUT ;
    USE SIGNAL ;
    PORT
      LAYER M4 ;
        RECT  47.436 283.872 47.52 283.896 ;
    END
  END t_d[370]
  PIN t_d[371]
    DIRECTION INPUT ;
    USE SIGNAL ;
    PORT
      LAYER M4 ;
        RECT  47.436 284.064 47.52 284.088 ;
    END
  END t_d[371]
  PIN t_d[372]
    DIRECTION INPUT ;
    USE SIGNAL ;
    PORT
      LAYER M4 ;
        RECT  47.436 284.256 47.52 284.28 ;
    END
  END t_d[372]
  PIN t_d[373]
    DIRECTION INPUT ;
    USE SIGNAL ;
    PORT
      LAYER M4 ;
        RECT  47.436 284.496 47.52 284.52 ;
    END
  END t_d[373]
  PIN t_d[374]
    DIRECTION INPUT ;
    USE SIGNAL ;
    PORT
      LAYER M4 ;
        RECT  47.436 284.688 47.52 284.712 ;
    END
  END t_d[374]
  PIN t_d[375]
    DIRECTION INPUT ;
    USE SIGNAL ;
    PORT
      LAYER M4 ;
        RECT  47.436 284.88 47.52 284.904 ;
    END
  END t_d[375]
  PIN t_d[376]
    DIRECTION INPUT ;
    USE SIGNAL ;
    PORT
      LAYER M4 ;
        RECT  47.436 285.072 47.52 285.096 ;
    END
  END t_d[376]
  PIN t_d[377]
    DIRECTION INPUT ;
    USE SIGNAL ;
    PORT
      LAYER M4 ;
        RECT  47.436 285.264 47.52 285.288 ;
    END
  END t_d[377]
  PIN t_d[378]
    DIRECTION INPUT ;
    USE SIGNAL ;
    PORT
      LAYER M4 ;
        RECT  47.436 285.456 47.52 285.48 ;
    END
  END t_d[378]
  PIN t_d[379]
    DIRECTION INPUT ;
    USE SIGNAL ;
    PORT
      LAYER M4 ;
        RECT  47.436 285.648 47.52 285.672 ;
    END
  END t_d[379]
  PIN t_d[37]
    DIRECTION INPUT ;
    USE SIGNAL ;
    PORT
      LAYER M4 ;
        RECT  47.436 219.168 47.52 219.192 ;
    END
  END t_d[37]
  PIN t_d[380]
    DIRECTION INPUT ;
    USE SIGNAL ;
    PORT
      LAYER M4 ;
        RECT  47.436 285.84 47.52 285.864 ;
    END
  END t_d[380]
  PIN t_d[381]
    DIRECTION INPUT ;
    USE SIGNAL ;
    PORT
      LAYER M4 ;
        RECT  47.436 286.032 47.52 286.056 ;
    END
  END t_d[381]
  PIN t_d[382]
    DIRECTION INPUT ;
    USE SIGNAL ;
    PORT
      LAYER M4 ;
        RECT  47.436 286.224 47.52 286.248 ;
    END
  END t_d[382]
  PIN t_d[383]
    DIRECTION INPUT ;
    USE SIGNAL ;
    PORT
      LAYER M4 ;
        RECT  47.436 286.416 47.52 286.44 ;
    END
  END t_d[383]
  PIN t_d[384]
    DIRECTION INPUT ;
    USE SIGNAL ;
    PORT
      LAYER M4 ;
        RECT  47.436 286.608 47.52 286.632 ;
    END
  END t_d[384]
  PIN t_d[385]
    DIRECTION INPUT ;
    USE SIGNAL ;
    PORT
      LAYER M4 ;
        RECT  47.436 286.8 47.52 286.824 ;
    END
  END t_d[385]
  PIN t_d[386]
    DIRECTION INPUT ;
    USE SIGNAL ;
    PORT
      LAYER M4 ;
        RECT  47.436 286.992 47.52 287.016 ;
    END
  END t_d[386]
  PIN t_d[387]
    DIRECTION INPUT ;
    USE SIGNAL ;
    PORT
      LAYER M4 ;
        RECT  47.436 287.184 47.52 287.208 ;
    END
  END t_d[387]
  PIN t_d[388]
    DIRECTION INPUT ;
    USE SIGNAL ;
    PORT
      LAYER M4 ;
        RECT  47.436 287.376 47.52 287.4 ;
    END
  END t_d[388]
  PIN t_d[389]
    DIRECTION INPUT ;
    USE SIGNAL ;
    PORT
      LAYER M4 ;
        RECT  47.436 287.568 47.52 287.592 ;
    END
  END t_d[389]
  PIN t_d[38]
    DIRECTION INPUT ;
    USE SIGNAL ;
    PORT
      LAYER M4 ;
        RECT  47.436 219.36 47.52 219.384 ;
    END
  END t_d[38]
  PIN t_d[390]
    DIRECTION INPUT ;
    USE SIGNAL ;
    PORT
      LAYER M4 ;
        RECT  47.436 287.76 47.52 287.784 ;
    END
  END t_d[390]
  PIN t_d[391]
    DIRECTION INPUT ;
    USE SIGNAL ;
    PORT
      LAYER M4 ;
        RECT  47.436 287.952 47.52 287.976 ;
    END
  END t_d[391]
  PIN t_d[392]
    DIRECTION INPUT ;
    USE SIGNAL ;
    PORT
      LAYER M4 ;
        RECT  47.436 288.144 47.52 288.168 ;
    END
  END t_d[392]
  PIN t_d[393]
    DIRECTION INPUT ;
    USE SIGNAL ;
    PORT
      LAYER M4 ;
        RECT  47.436 288.336 47.52 288.36 ;
    END
  END t_d[393]
  PIN t_d[394]
    DIRECTION INPUT ;
    USE SIGNAL ;
    PORT
      LAYER M4 ;
        RECT  47.436 288.576 47.52 288.6 ;
    END
  END t_d[394]
  PIN t_d[395]
    DIRECTION INPUT ;
    USE SIGNAL ;
    PORT
      LAYER M4 ;
        RECT  47.436 288.768 47.52 288.792 ;
    END
  END t_d[395]
  PIN t_d[396]
    DIRECTION INPUT ;
    USE SIGNAL ;
    PORT
      LAYER M4 ;
        RECT  47.436 288.96 47.52 288.984 ;
    END
  END t_d[396]
  PIN t_d[397]
    DIRECTION INPUT ;
    USE SIGNAL ;
    PORT
      LAYER M4 ;
        RECT  47.436 289.152 47.52 289.176 ;
    END
  END t_d[397]
  PIN t_d[398]
    DIRECTION INPUT ;
    USE SIGNAL ;
    PORT
      LAYER M4 ;
        RECT  47.436 289.344 47.52 289.368 ;
    END
  END t_d[398]
  PIN t_d[399]
    DIRECTION INPUT ;
    USE SIGNAL ;
    PORT
      LAYER M4 ;
        RECT  47.436 289.536 47.52 289.56 ;
    END
  END t_d[399]
  PIN t_d[39]
    DIRECTION INPUT ;
    USE SIGNAL ;
    PORT
      LAYER M4 ;
        RECT  47.436 219.552 47.52 219.576 ;
    END
  END t_d[39]
  PIN t_d[3]
    DIRECTION INPUT ;
    USE SIGNAL ;
    PORT
      LAYER M4 ;
        RECT  47.436 212.592 47.52 212.616 ;
    END
  END t_d[3]
  PIN t_d[400]
    DIRECTION INPUT ;
    USE SIGNAL ;
    PORT
      LAYER M4 ;
        RECT  47.436 289.728 47.52 289.752 ;
    END
  END t_d[400]
  PIN t_d[401]
    DIRECTION INPUT ;
    USE SIGNAL ;
    PORT
      LAYER M4 ;
        RECT  47.436 289.92 47.52 289.944 ;
    END
  END t_d[401]
  PIN t_d[402]
    DIRECTION INPUT ;
    USE SIGNAL ;
    PORT
      LAYER M4 ;
        RECT  47.436 290.112 47.52 290.136 ;
    END
  END t_d[402]
  PIN t_d[403]
    DIRECTION INPUT ;
    USE SIGNAL ;
    PORT
      LAYER M4 ;
        RECT  47.436 290.304 47.52 290.328 ;
    END
  END t_d[403]
  PIN t_d[404]
    DIRECTION INPUT ;
    USE SIGNAL ;
    PORT
      LAYER M4 ;
        RECT  47.436 290.496 47.52 290.52 ;
    END
  END t_d[404]
  PIN t_d[405]
    DIRECTION INPUT ;
    USE SIGNAL ;
    PORT
      LAYER M4 ;
        RECT  47.436 290.688 47.52 290.712 ;
    END
  END t_d[405]
  PIN t_d[406]
    DIRECTION INPUT ;
    USE SIGNAL ;
    PORT
      LAYER M4 ;
        RECT  47.436 290.88 47.52 290.904 ;
    END
  END t_d[406]
  PIN t_d[407]
    DIRECTION INPUT ;
    USE SIGNAL ;
    PORT
      LAYER M4 ;
        RECT  47.436 291.072 47.52 291.096 ;
    END
  END t_d[407]
  PIN t_d[408]
    DIRECTION INPUT ;
    USE SIGNAL ;
    PORT
      LAYER M4 ;
        RECT  47.436 291.264 47.52 291.288 ;
    END
  END t_d[408]
  PIN t_d[409]
    DIRECTION INPUT ;
    USE SIGNAL ;
    PORT
      LAYER M4 ;
        RECT  47.436 291.456 47.52 291.48 ;
    END
  END t_d[409]
  PIN t_d[40]
    DIRECTION INPUT ;
    USE SIGNAL ;
    PORT
      LAYER M4 ;
        RECT  47.436 219.744 47.52 219.768 ;
    END
  END t_d[40]
  PIN t_d[410]
    DIRECTION INPUT ;
    USE SIGNAL ;
    PORT
      LAYER M4 ;
        RECT  47.436 291.648 47.52 291.672 ;
    END
  END t_d[410]
  PIN t_d[411]
    DIRECTION INPUT ;
    USE SIGNAL ;
    PORT
      LAYER M4 ;
        RECT  47.436 291.84 47.52 291.864 ;
    END
  END t_d[411]
  PIN t_d[412]
    DIRECTION INPUT ;
    USE SIGNAL ;
    PORT
      LAYER M4 ;
        RECT  47.436 292.032 47.52 292.056 ;
    END
  END t_d[412]
  PIN t_d[413]
    DIRECTION INPUT ;
    USE SIGNAL ;
    PORT
      LAYER M4 ;
        RECT  47.436 292.224 47.52 292.248 ;
    END
  END t_d[413]
  PIN t_d[414]
    DIRECTION INPUT ;
    USE SIGNAL ;
    PORT
      LAYER M4 ;
        RECT  47.436 292.464 47.52 292.488 ;
    END
  END t_d[414]
  PIN t_d[415]
    DIRECTION INPUT ;
    USE SIGNAL ;
    PORT
      LAYER M4 ;
        RECT  47.436 292.656 47.52 292.68 ;
    END
  END t_d[415]
  PIN t_d[416]
    DIRECTION INPUT ;
    USE SIGNAL ;
    PORT
      LAYER M4 ;
        RECT  47.436 292.848 47.52 292.872 ;
    END
  END t_d[416]
  PIN t_d[417]
    DIRECTION INPUT ;
    USE SIGNAL ;
    PORT
      LAYER M4 ;
        RECT  47.436 293.04 47.52 293.064 ;
    END
  END t_d[417]
  PIN t_d[418]
    DIRECTION INPUT ;
    USE SIGNAL ;
    PORT
      LAYER M4 ;
        RECT  47.436 293.232 47.52 293.256 ;
    END
  END t_d[418]
  PIN t_d[419]
    DIRECTION INPUT ;
    USE SIGNAL ;
    PORT
      LAYER M4 ;
        RECT  47.436 293.424 47.52 293.448 ;
    END
  END t_d[419]
  PIN t_d[41]
    DIRECTION INPUT ;
    USE SIGNAL ;
    PORT
      LAYER M4 ;
        RECT  47.436 219.936 47.52 219.96 ;
    END
  END t_d[41]
  PIN t_d[420]
    DIRECTION INPUT ;
    USE SIGNAL ;
    PORT
      LAYER M4 ;
        RECT  47.436 293.616 47.52 293.64 ;
    END
  END t_d[420]
  PIN t_d[421]
    DIRECTION INPUT ;
    USE SIGNAL ;
    PORT
      LAYER M4 ;
        RECT  47.436 293.808 47.52 293.832 ;
    END
  END t_d[421]
  PIN t_d[422]
    DIRECTION INPUT ;
    USE SIGNAL ;
    PORT
      LAYER M4 ;
        RECT  47.436 294 47.52 294.024 ;
    END
  END t_d[422]
  PIN t_d[423]
    DIRECTION INPUT ;
    USE SIGNAL ;
    PORT
      LAYER M4 ;
        RECT  47.436 294.192 47.52 294.216 ;
    END
  END t_d[423]
  PIN t_d[424]
    DIRECTION INPUT ;
    USE SIGNAL ;
    PORT
      LAYER M4 ;
        RECT  47.436 294.384 47.52 294.408 ;
    END
  END t_d[424]
  PIN t_d[425]
    DIRECTION INPUT ;
    USE SIGNAL ;
    PORT
      LAYER M4 ;
        RECT  47.436 294.576 47.52 294.6 ;
    END
  END t_d[425]
  PIN t_d[426]
    DIRECTION INPUT ;
    USE SIGNAL ;
    PORT
      LAYER M4 ;
        RECT  47.436 294.768 47.52 294.792 ;
    END
  END t_d[426]
  PIN t_d[427]
    DIRECTION INPUT ;
    USE SIGNAL ;
    PORT
      LAYER M4 ;
        RECT  47.436 294.96 47.52 294.984 ;
    END
  END t_d[427]
  PIN t_d[428]
    DIRECTION INPUT ;
    USE SIGNAL ;
    PORT
      LAYER M4 ;
        RECT  47.436 295.152 47.52 295.176 ;
    END
  END t_d[428]
  PIN t_d[429]
    DIRECTION INPUT ;
    USE SIGNAL ;
    PORT
      LAYER M4 ;
        RECT  47.436 295.344 47.52 295.368 ;
    END
  END t_d[429]
  PIN t_d[42]
    DIRECTION INPUT ;
    USE SIGNAL ;
    PORT
      LAYER M4 ;
        RECT  47.436 220.128 47.52 220.152 ;
    END
  END t_d[42]
  PIN t_d[430]
    DIRECTION INPUT ;
    USE SIGNAL ;
    PORT
      LAYER M4 ;
        RECT  47.436 295.536 47.52 295.56 ;
    END
  END t_d[430]
  PIN t_d[431]
    DIRECTION INPUT ;
    USE SIGNAL ;
    PORT
      LAYER M4 ;
        RECT  47.436 295.728 47.52 295.752 ;
    END
  END t_d[431]
  PIN t_d[432]
    DIRECTION INPUT ;
    USE SIGNAL ;
    PORT
      LAYER M4 ;
        RECT  47.436 295.92 47.52 295.944 ;
    END
  END t_d[432]
  PIN t_d[433]
    DIRECTION INPUT ;
    USE SIGNAL ;
    PORT
      LAYER M4 ;
        RECT  47.436 296.112 47.52 296.136 ;
    END
  END t_d[433]
  PIN t_d[434]
    DIRECTION INPUT ;
    USE SIGNAL ;
    PORT
      LAYER M4 ;
        RECT  47.436 296.304 47.52 296.328 ;
    END
  END t_d[434]
  PIN t_d[435]
    DIRECTION INPUT ;
    USE SIGNAL ;
    PORT
      LAYER M4 ;
        RECT  47.436 296.544 47.52 296.568 ;
    END
  END t_d[435]
  PIN t_d[436]
    DIRECTION INPUT ;
    USE SIGNAL ;
    PORT
      LAYER M4 ;
        RECT  47.436 296.736 47.52 296.76 ;
    END
  END t_d[436]
  PIN t_d[437]
    DIRECTION INPUT ;
    USE SIGNAL ;
    PORT
      LAYER M4 ;
        RECT  47.436 296.928 47.52 296.952 ;
    END
  END t_d[437]
  PIN t_d[438]
    DIRECTION INPUT ;
    USE SIGNAL ;
    PORT
      LAYER M4 ;
        RECT  47.436 297.12 47.52 297.144 ;
    END
  END t_d[438]
  PIN t_d[439]
    DIRECTION INPUT ;
    USE SIGNAL ;
    PORT
      LAYER M4 ;
        RECT  47.436 297.312 47.52 297.336 ;
    END
  END t_d[439]
  PIN t_d[43]
    DIRECTION INPUT ;
    USE SIGNAL ;
    PORT
      LAYER M4 ;
        RECT  47.436 220.32 47.52 220.344 ;
    END
  END t_d[43]
  PIN t_d[440]
    DIRECTION INPUT ;
    USE SIGNAL ;
    PORT
      LAYER M4 ;
        RECT  47.436 297.504 47.52 297.528 ;
    END
  END t_d[440]
  PIN t_d[441]
    DIRECTION INPUT ;
    USE SIGNAL ;
    PORT
      LAYER M4 ;
        RECT  47.436 297.696 47.52 297.72 ;
    END
  END t_d[441]
  PIN t_d[442]
    DIRECTION INPUT ;
    USE SIGNAL ;
    PORT
      LAYER M4 ;
        RECT  47.436 297.888 47.52 297.912 ;
    END
  END t_d[442]
  PIN t_d[443]
    DIRECTION INPUT ;
    USE SIGNAL ;
    PORT
      LAYER M4 ;
        RECT  47.436 298.08 47.52 298.104 ;
    END
  END t_d[443]
  PIN t_d[444]
    DIRECTION INPUT ;
    USE SIGNAL ;
    PORT
      LAYER M4 ;
        RECT  47.436 298.272 47.52 298.296 ;
    END
  END t_d[444]
  PIN t_d[445]
    DIRECTION INPUT ;
    USE SIGNAL ;
    PORT
      LAYER M4 ;
        RECT  47.436 298.464 47.52 298.488 ;
    END
  END t_d[445]
  PIN t_d[446]
    DIRECTION INPUT ;
    USE SIGNAL ;
    PORT
      LAYER M4 ;
        RECT  47.436 298.656 47.52 298.68 ;
    END
  END t_d[446]
  PIN t_d[447]
    DIRECTION INPUT ;
    USE SIGNAL ;
    PORT
      LAYER M4 ;
        RECT  47.436 298.848 47.52 298.872 ;
    END
  END t_d[447]
  PIN t_d[448]
    DIRECTION INPUT ;
    USE SIGNAL ;
    PORT
      LAYER M4 ;
        RECT  47.436 299.04 47.52 299.064 ;
    END
  END t_d[448]
  PIN t_d[449]
    DIRECTION INPUT ;
    USE SIGNAL ;
    PORT
      LAYER M4 ;
        RECT  47.436 299.232 47.52 299.256 ;
    END
  END t_d[449]
  PIN t_d[44]
    DIRECTION INPUT ;
    USE SIGNAL ;
    PORT
      LAYER M4 ;
        RECT  47.436 220.56 47.52 220.584 ;
    END
  END t_d[44]
  PIN t_d[450]
    DIRECTION INPUT ;
    USE SIGNAL ;
    PORT
      LAYER M4 ;
        RECT  47.436 299.424 47.52 299.448 ;
    END
  END t_d[450]
  PIN t_d[451]
    DIRECTION INPUT ;
    USE SIGNAL ;
    PORT
      LAYER M4 ;
        RECT  47.436 299.616 47.52 299.64 ;
    END
  END t_d[451]
  PIN t_d[452]
    DIRECTION INPUT ;
    USE SIGNAL ;
    PORT
      LAYER M4 ;
        RECT  47.436 299.808 47.52 299.832 ;
    END
  END t_d[452]
  PIN t_d[453]
    DIRECTION INPUT ;
    USE SIGNAL ;
    PORT
      LAYER M4 ;
        RECT  47.436 300 47.52 300.024 ;
    END
  END t_d[453]
  PIN t_d[454]
    DIRECTION INPUT ;
    USE SIGNAL ;
    PORT
      LAYER M4 ;
        RECT  47.436 300.192 47.52 300.216 ;
    END
  END t_d[454]
  PIN t_d[455]
    DIRECTION INPUT ;
    USE SIGNAL ;
    PORT
      LAYER M4 ;
        RECT  47.436 300.432 47.52 300.456 ;
    END
  END t_d[455]
  PIN t_d[456]
    DIRECTION INPUT ;
    USE SIGNAL ;
    PORT
      LAYER M4 ;
        RECT  47.436 300.624 47.52 300.648 ;
    END
  END t_d[456]
  PIN t_d[457]
    DIRECTION INPUT ;
    USE SIGNAL ;
    PORT
      LAYER M4 ;
        RECT  47.436 300.816 47.52 300.84 ;
    END
  END t_d[457]
  PIN t_d[458]
    DIRECTION INPUT ;
    USE SIGNAL ;
    PORT
      LAYER M4 ;
        RECT  47.436 301.008 47.52 301.032 ;
    END
  END t_d[458]
  PIN t_d[459]
    DIRECTION INPUT ;
    USE SIGNAL ;
    PORT
      LAYER M4 ;
        RECT  47.436 301.2 47.52 301.224 ;
    END
  END t_d[459]
  PIN t_d[45]
    DIRECTION INPUT ;
    USE SIGNAL ;
    PORT
      LAYER M4 ;
        RECT  47.436 220.752 47.52 220.776 ;
    END
  END t_d[45]
  PIN t_d[460]
    DIRECTION INPUT ;
    USE SIGNAL ;
    PORT
      LAYER M4 ;
        RECT  47.436 301.392 47.52 301.416 ;
    END
  END t_d[460]
  PIN t_d[461]
    DIRECTION INPUT ;
    USE SIGNAL ;
    PORT
      LAYER M4 ;
        RECT  47.436 301.584 47.52 301.608 ;
    END
  END t_d[461]
  PIN t_d[462]
    DIRECTION INPUT ;
    USE SIGNAL ;
    PORT
      LAYER M4 ;
        RECT  47.436 301.776 47.52 301.8 ;
    END
  END t_d[462]
  PIN t_d[463]
    DIRECTION INPUT ;
    USE SIGNAL ;
    PORT
      LAYER M4 ;
        RECT  47.436 301.968 47.52 301.992 ;
    END
  END t_d[463]
  PIN t_d[464]
    DIRECTION INPUT ;
    USE SIGNAL ;
    PORT
      LAYER M4 ;
        RECT  47.436 302.16 47.52 302.184 ;
    END
  END t_d[464]
  PIN t_d[465]
    DIRECTION INPUT ;
    USE SIGNAL ;
    PORT
      LAYER M4 ;
        RECT  47.436 302.352 47.52 302.376 ;
    END
  END t_d[465]
  PIN t_d[466]
    DIRECTION INPUT ;
    USE SIGNAL ;
    PORT
      LAYER M4 ;
        RECT  47.436 302.544 47.52 302.568 ;
    END
  END t_d[466]
  PIN t_d[467]
    DIRECTION INPUT ;
    USE SIGNAL ;
    PORT
      LAYER M4 ;
        RECT  47.436 302.736 47.52 302.76 ;
    END
  END t_d[467]
  PIN t_d[468]
    DIRECTION INPUT ;
    USE SIGNAL ;
    PORT
      LAYER M4 ;
        RECT  47.436 302.928 47.52 302.952 ;
    END
  END t_d[468]
  PIN t_d[469]
    DIRECTION INPUT ;
    USE SIGNAL ;
    PORT
      LAYER M4 ;
        RECT  47.436 303.12 47.52 303.144 ;
    END
  END t_d[469]
  PIN t_d[46]
    DIRECTION INPUT ;
    USE SIGNAL ;
    PORT
      LAYER M4 ;
        RECT  47.436 220.944 47.52 220.968 ;
    END
  END t_d[46]
  PIN t_d[470]
    DIRECTION INPUT ;
    USE SIGNAL ;
    PORT
      LAYER M4 ;
        RECT  47.436 303.312 47.52 303.336 ;
    END
  END t_d[470]
  PIN t_d[471]
    DIRECTION INPUT ;
    USE SIGNAL ;
    PORT
      LAYER M4 ;
        RECT  47.436 303.504 47.52 303.528 ;
    END
  END t_d[471]
  PIN t_d[472]
    DIRECTION INPUT ;
    USE SIGNAL ;
    PORT
      LAYER M4 ;
        RECT  47.436 303.696 47.52 303.72 ;
    END
  END t_d[472]
  PIN t_d[473]
    DIRECTION INPUT ;
    USE SIGNAL ;
    PORT
      LAYER M4 ;
        RECT  47.436 303.888 47.52 303.912 ;
    END
  END t_d[473]
  PIN t_d[474]
    DIRECTION INPUT ;
    USE SIGNAL ;
    PORT
      LAYER M4 ;
        RECT  47.436 304.08 47.52 304.104 ;
    END
  END t_d[474]
  PIN t_d[475]
    DIRECTION INPUT ;
    USE SIGNAL ;
    PORT
      LAYER M4 ;
        RECT  47.436 304.272 47.52 304.296 ;
    END
  END t_d[475]
  PIN t_d[476]
    DIRECTION INPUT ;
    USE SIGNAL ;
    PORT
      LAYER M4 ;
        RECT  47.436 304.512 47.52 304.536 ;
    END
  END t_d[476]
  PIN t_d[477]
    DIRECTION INPUT ;
    USE SIGNAL ;
    PORT
      LAYER M4 ;
        RECT  47.436 304.704 47.52 304.728 ;
    END
  END t_d[477]
  PIN t_d[478]
    DIRECTION INPUT ;
    USE SIGNAL ;
    PORT
      LAYER M4 ;
        RECT  47.436 304.896 47.52 304.92 ;
    END
  END t_d[478]
  PIN t_d[479]
    DIRECTION INPUT ;
    USE SIGNAL ;
    PORT
      LAYER M4 ;
        RECT  47.436 305.088 47.52 305.112 ;
    END
  END t_d[479]
  PIN t_d[47]
    DIRECTION INPUT ;
    USE SIGNAL ;
    PORT
      LAYER M4 ;
        RECT  47.436 221.136 47.52 221.16 ;
    END
  END t_d[47]
  PIN t_d[480]
    DIRECTION INPUT ;
    USE SIGNAL ;
    PORT
      LAYER M4 ;
        RECT  47.436 305.28 47.52 305.304 ;
    END
  END t_d[480]
  PIN t_d[481]
    DIRECTION INPUT ;
    USE SIGNAL ;
    PORT
      LAYER M4 ;
        RECT  47.436 305.472 47.52 305.496 ;
    END
  END t_d[481]
  PIN t_d[482]
    DIRECTION INPUT ;
    USE SIGNAL ;
    PORT
      LAYER M4 ;
        RECT  47.436 305.664 47.52 305.688 ;
    END
  END t_d[482]
  PIN t_d[483]
    DIRECTION INPUT ;
    USE SIGNAL ;
    PORT
      LAYER M4 ;
        RECT  47.436 305.856 47.52 305.88 ;
    END
  END t_d[483]
  PIN t_d[484]
    DIRECTION INPUT ;
    USE SIGNAL ;
    PORT
      LAYER M4 ;
        RECT  47.436 306.048 47.52 306.072 ;
    END
  END t_d[484]
  PIN t_d[485]
    DIRECTION INPUT ;
    USE SIGNAL ;
    PORT
      LAYER M4 ;
        RECT  47.436 306.24 47.52 306.264 ;
    END
  END t_d[485]
  PIN t_d[486]
    DIRECTION INPUT ;
    USE SIGNAL ;
    PORT
      LAYER M4 ;
        RECT  47.436 306.432 47.52 306.456 ;
    END
  END t_d[486]
  PIN t_d[487]
    DIRECTION INPUT ;
    USE SIGNAL ;
    PORT
      LAYER M4 ;
        RECT  47.436 306.624 47.52 306.648 ;
    END
  END t_d[487]
  PIN t_d[488]
    DIRECTION INPUT ;
    USE SIGNAL ;
    PORT
      LAYER M4 ;
        RECT  47.436 306.816 47.52 306.84 ;
    END
  END t_d[488]
  PIN t_d[489]
    DIRECTION INPUT ;
    USE SIGNAL ;
    PORT
      LAYER M4 ;
        RECT  47.436 307.008 47.52 307.032 ;
    END
  END t_d[489]
  PIN t_d[48]
    DIRECTION INPUT ;
    USE SIGNAL ;
    PORT
      LAYER M4 ;
        RECT  47.436 221.328 47.52 221.352 ;
    END
  END t_d[48]
  PIN t_d[490]
    DIRECTION INPUT ;
    USE SIGNAL ;
    PORT
      LAYER M4 ;
        RECT  47.436 307.2 47.52 307.224 ;
    END
  END t_d[490]
  PIN t_d[491]
    DIRECTION INPUT ;
    USE SIGNAL ;
    PORT
      LAYER M4 ;
        RECT  47.436 307.392 47.52 307.416 ;
    END
  END t_d[491]
  PIN t_d[492]
    DIRECTION INPUT ;
    USE SIGNAL ;
    PORT
      LAYER M4 ;
        RECT  47.436 307.584 47.52 307.608 ;
    END
  END t_d[492]
  PIN t_d[493]
    DIRECTION INPUT ;
    USE SIGNAL ;
    PORT
      LAYER M4 ;
        RECT  47.436 307.776 47.52 307.8 ;
    END
  END t_d[493]
  PIN t_d[494]
    DIRECTION INPUT ;
    USE SIGNAL ;
    PORT
      LAYER M4 ;
        RECT  47.436 307.968 47.52 307.992 ;
    END
  END t_d[494]
  PIN t_d[495]
    DIRECTION INPUT ;
    USE SIGNAL ;
    PORT
      LAYER M4 ;
        RECT  47.436 308.16 47.52 308.184 ;
    END
  END t_d[495]
  PIN t_d[496]
    DIRECTION INPUT ;
    USE SIGNAL ;
    PORT
      LAYER M4 ;
        RECT  47.436 308.4 47.52 308.424 ;
    END
  END t_d[496]
  PIN t_d[497]
    DIRECTION INPUT ;
    USE SIGNAL ;
    PORT
      LAYER M4 ;
        RECT  47.436 308.592 47.52 308.616 ;
    END
  END t_d[497]
  PIN t_d[498]
    DIRECTION INPUT ;
    USE SIGNAL ;
    PORT
      LAYER M4 ;
        RECT  47.436 308.784 47.52 308.808 ;
    END
  END t_d[498]
  PIN t_d[499]
    DIRECTION INPUT ;
    USE SIGNAL ;
    PORT
      LAYER M4 ;
        RECT  47.436 308.976 47.52 309 ;
    END
  END t_d[499]
  PIN t_d[49]
    DIRECTION INPUT ;
    USE SIGNAL ;
    PORT
      LAYER M4 ;
        RECT  47.436 221.52 47.52 221.544 ;
    END
  END t_d[49]
  PIN t_d[4]
    DIRECTION INPUT ;
    USE SIGNAL ;
    PORT
      LAYER M4 ;
        RECT  47.436 212.784 47.52 212.808 ;
    END
  END t_d[4]
  PIN t_d[500]
    DIRECTION INPUT ;
    USE SIGNAL ;
    PORT
      LAYER M4 ;
        RECT  47.436 309.168 47.52 309.192 ;
    END
  END t_d[500]
  PIN t_d[501]
    DIRECTION INPUT ;
    USE SIGNAL ;
    PORT
      LAYER M4 ;
        RECT  47.436 309.36 47.52 309.384 ;
    END
  END t_d[501]
  PIN t_d[502]
    DIRECTION INPUT ;
    USE SIGNAL ;
    PORT
      LAYER M4 ;
        RECT  47.436 309.552 47.52 309.576 ;
    END
  END t_d[502]
  PIN t_d[503]
    DIRECTION INPUT ;
    USE SIGNAL ;
    PORT
      LAYER M4 ;
        RECT  47.436 309.744 47.52 309.768 ;
    END
  END t_d[503]
  PIN t_d[504]
    DIRECTION INPUT ;
    USE SIGNAL ;
    PORT
      LAYER M4 ;
        RECT  47.436 309.936 47.52 309.96 ;
    END
  END t_d[504]
  PIN t_d[505]
    DIRECTION INPUT ;
    USE SIGNAL ;
    PORT
      LAYER M4 ;
        RECT  47.436 310.128 47.52 310.152 ;
    END
  END t_d[505]
  PIN t_d[506]
    DIRECTION INPUT ;
    USE SIGNAL ;
    PORT
      LAYER M4 ;
        RECT  47.436 310.32 47.52 310.344 ;
    END
  END t_d[506]
  PIN t_d[507]
    DIRECTION INPUT ;
    USE SIGNAL ;
    PORT
      LAYER M4 ;
        RECT  47.436 310.512 47.52 310.536 ;
    END
  END t_d[507]
  PIN t_d[508]
    DIRECTION INPUT ;
    USE SIGNAL ;
    PORT
      LAYER M4 ;
        RECT  47.436 310.704 47.52 310.728 ;
    END
  END t_d[508]
  PIN t_d[509]
    DIRECTION INPUT ;
    USE SIGNAL ;
    PORT
      LAYER M4 ;
        RECT  47.436 310.896 47.52 310.92 ;
    END
  END t_d[509]
  PIN t_d[50]
    DIRECTION INPUT ;
    USE SIGNAL ;
    PORT
      LAYER M4 ;
        RECT  47.436 221.712 47.52 221.736 ;
    END
  END t_d[50]
  PIN t_d[510]
    DIRECTION INPUT ;
    USE SIGNAL ;
    PORT
      LAYER M4 ;
        RECT  47.436 311.088 47.52 311.112 ;
    END
  END t_d[510]
  PIN t_d[511]
    DIRECTION INPUT ;
    USE SIGNAL ;
    PORT
      LAYER M4 ;
        RECT  47.436 311.28 47.52 311.304 ;
    END
  END t_d[511]
  PIN t_d[51]
    DIRECTION INPUT ;
    USE SIGNAL ;
    PORT
      LAYER M4 ;
        RECT  47.436 221.904 47.52 221.928 ;
    END
  END t_d[51]
  PIN t_d[52]
    DIRECTION INPUT ;
    USE SIGNAL ;
    PORT
      LAYER M4 ;
        RECT  47.436 222.096 47.52 222.12 ;
    END
  END t_d[52]
  PIN t_d[53]
    DIRECTION INPUT ;
    USE SIGNAL ;
    PORT
      LAYER M4 ;
        RECT  47.436 222.288 47.52 222.312 ;
    END
  END t_d[53]
  PIN t_d[54]
    DIRECTION INPUT ;
    USE SIGNAL ;
    PORT
      LAYER M4 ;
        RECT  47.436 222.48 47.52 222.504 ;
    END
  END t_d[54]
  PIN t_d[55]
    DIRECTION INPUT ;
    USE SIGNAL ;
    PORT
      LAYER M4 ;
        RECT  47.436 222.672 47.52 222.696 ;
    END
  END t_d[55]
  PIN t_d[56]
    DIRECTION INPUT ;
    USE SIGNAL ;
    PORT
      LAYER M4 ;
        RECT  47.436 222.864 47.52 222.888 ;
    END
  END t_d[56]
  PIN t_d[57]
    DIRECTION INPUT ;
    USE SIGNAL ;
    PORT
      LAYER M4 ;
        RECT  47.436 223.056 47.52 223.08 ;
    END
  END t_d[57]
  PIN t_d[58]
    DIRECTION INPUT ;
    USE SIGNAL ;
    PORT
      LAYER M4 ;
        RECT  47.436 223.248 47.52 223.272 ;
    END
  END t_d[58]
  PIN t_d[59]
    DIRECTION INPUT ;
    USE SIGNAL ;
    PORT
      LAYER M4 ;
        RECT  47.436 223.44 47.52 223.464 ;
    END
  END t_d[59]
  PIN t_d[5]
    DIRECTION INPUT ;
    USE SIGNAL ;
    PORT
      LAYER M4 ;
        RECT  47.436 212.976 47.52 213 ;
    END
  END t_d[5]
  PIN t_d[60]
    DIRECTION INPUT ;
    USE SIGNAL ;
    PORT
      LAYER M4 ;
        RECT  47.436 223.632 47.52 223.656 ;
    END
  END t_d[60]
  PIN t_d[61]
    DIRECTION INPUT ;
    USE SIGNAL ;
    PORT
      LAYER M4 ;
        RECT  47.436 223.824 47.52 223.848 ;
    END
  END t_d[61]
  PIN t_d[62]
    DIRECTION INPUT ;
    USE SIGNAL ;
    PORT
      LAYER M4 ;
        RECT  47.436 224.016 47.52 224.04 ;
    END
  END t_d[62]
  PIN t_d[63]
    DIRECTION INPUT ;
    USE SIGNAL ;
    PORT
      LAYER M4 ;
        RECT  47.436 224.208 47.52 224.232 ;
    END
  END t_d[63]
  PIN t_d[64]
    DIRECTION INPUT ;
    USE SIGNAL ;
    PORT
      LAYER M4 ;
        RECT  47.436 224.4 47.52 224.424 ;
    END
  END t_d[64]
  PIN t_d[65]
    DIRECTION INPUT ;
    USE SIGNAL ;
    PORT
      LAYER M4 ;
        RECT  47.436 224.64 47.52 224.664 ;
    END
  END t_d[65]
  PIN t_d[66]
    DIRECTION INPUT ;
    USE SIGNAL ;
    PORT
      LAYER M4 ;
        RECT  47.436 224.832 47.52 224.856 ;
    END
  END t_d[66]
  PIN t_d[67]
    DIRECTION INPUT ;
    USE SIGNAL ;
    PORT
      LAYER M4 ;
        RECT  47.436 225.024 47.52 225.048 ;
    END
  END t_d[67]
  PIN t_d[68]
    DIRECTION INPUT ;
    USE SIGNAL ;
    PORT
      LAYER M4 ;
        RECT  47.436 225.216 47.52 225.24 ;
    END
  END t_d[68]
  PIN t_d[69]
    DIRECTION INPUT ;
    USE SIGNAL ;
    PORT
      LAYER M4 ;
        RECT  47.436 225.408 47.52 225.432 ;
    END
  END t_d[69]
  PIN t_d[6]
    DIRECTION INPUT ;
    USE SIGNAL ;
    PORT
      LAYER M4 ;
        RECT  47.436 213.168 47.52 213.192 ;
    END
  END t_d[6]
  PIN t_d[70]
    DIRECTION INPUT ;
    USE SIGNAL ;
    PORT
      LAYER M4 ;
        RECT  47.436 225.6 47.52 225.624 ;
    END
  END t_d[70]
  PIN t_d[71]
    DIRECTION INPUT ;
    USE SIGNAL ;
    PORT
      LAYER M4 ;
        RECT  47.436 225.792 47.52 225.816 ;
    END
  END t_d[71]
  PIN t_d[72]
    DIRECTION INPUT ;
    USE SIGNAL ;
    PORT
      LAYER M4 ;
        RECT  47.436 225.984 47.52 226.008 ;
    END
  END t_d[72]
  PIN t_d[73]
    DIRECTION INPUT ;
    USE SIGNAL ;
    PORT
      LAYER M4 ;
        RECT  47.436 226.176 47.52 226.2 ;
    END
  END t_d[73]
  PIN t_d[74]
    DIRECTION INPUT ;
    USE SIGNAL ;
    PORT
      LAYER M4 ;
        RECT  47.436 226.368 47.52 226.392 ;
    END
  END t_d[74]
  PIN t_d[75]
    DIRECTION INPUT ;
    USE SIGNAL ;
    PORT
      LAYER M4 ;
        RECT  47.436 226.56 47.52 226.584 ;
    END
  END t_d[75]
  PIN t_d[76]
    DIRECTION INPUT ;
    USE SIGNAL ;
    PORT
      LAYER M4 ;
        RECT  47.436 226.752 47.52 226.776 ;
    END
  END t_d[76]
  PIN t_d[77]
    DIRECTION INPUT ;
    USE SIGNAL ;
    PORT
      LAYER M4 ;
        RECT  47.436 226.944 47.52 226.968 ;
    END
  END t_d[77]
  PIN t_d[78]
    DIRECTION INPUT ;
    USE SIGNAL ;
    PORT
      LAYER M4 ;
        RECT  47.436 227.136 47.52 227.16 ;
    END
  END t_d[78]
  PIN t_d[79]
    DIRECTION INPUT ;
    USE SIGNAL ;
    PORT
      LAYER M4 ;
        RECT  47.436 227.328 47.52 227.352 ;
    END
  END t_d[79]
  PIN t_d[7]
    DIRECTION INPUT ;
    USE SIGNAL ;
    PORT
      LAYER M4 ;
        RECT  47.436 213.36 47.52 213.384 ;
    END
  END t_d[7]
  PIN t_d[80]
    DIRECTION INPUT ;
    USE SIGNAL ;
    PORT
      LAYER M4 ;
        RECT  47.436 227.52 47.52 227.544 ;
    END
  END t_d[80]
  PIN t_d[81]
    DIRECTION INPUT ;
    USE SIGNAL ;
    PORT
      LAYER M4 ;
        RECT  47.436 227.712 47.52 227.736 ;
    END
  END t_d[81]
  PIN t_d[82]
    DIRECTION INPUT ;
    USE SIGNAL ;
    PORT
      LAYER M4 ;
        RECT  47.436 227.904 47.52 227.928 ;
    END
  END t_d[82]
  PIN t_d[83]
    DIRECTION INPUT ;
    USE SIGNAL ;
    PORT
      LAYER M4 ;
        RECT  47.436 228.096 47.52 228.12 ;
    END
  END t_d[83]
  PIN t_d[84]
    DIRECTION INPUT ;
    USE SIGNAL ;
    PORT
      LAYER M4 ;
        RECT  47.436 228.288 47.52 228.312 ;
    END
  END t_d[84]
  PIN t_d[85]
    DIRECTION INPUT ;
    USE SIGNAL ;
    PORT
      LAYER M4 ;
        RECT  47.436 228.528 47.52 228.552 ;
    END
  END t_d[85]
  PIN t_d[86]
    DIRECTION INPUT ;
    USE SIGNAL ;
    PORT
      LAYER M4 ;
        RECT  47.436 228.72 47.52 228.744 ;
    END
  END t_d[86]
  PIN t_d[87]
    DIRECTION INPUT ;
    USE SIGNAL ;
    PORT
      LAYER M4 ;
        RECT  47.436 228.912 47.52 228.936 ;
    END
  END t_d[87]
  PIN t_d[88]
    DIRECTION INPUT ;
    USE SIGNAL ;
    PORT
      LAYER M4 ;
        RECT  47.436 229.104 47.52 229.128 ;
    END
  END t_d[88]
  PIN t_d[89]
    DIRECTION INPUT ;
    USE SIGNAL ;
    PORT
      LAYER M4 ;
        RECT  47.436 229.296 47.52 229.32 ;
    END
  END t_d[89]
  PIN t_d[8]
    DIRECTION INPUT ;
    USE SIGNAL ;
    PORT
      LAYER M4 ;
        RECT  47.436 213.552 47.52 213.576 ;
    END
  END t_d[8]
  PIN t_d[90]
    DIRECTION INPUT ;
    USE SIGNAL ;
    PORT
      LAYER M4 ;
        RECT  47.436 229.488 47.52 229.512 ;
    END
  END t_d[90]
  PIN t_d[91]
    DIRECTION INPUT ;
    USE SIGNAL ;
    PORT
      LAYER M4 ;
        RECT  47.436 229.68 47.52 229.704 ;
    END
  END t_d[91]
  PIN t_d[92]
    DIRECTION INPUT ;
    USE SIGNAL ;
    PORT
      LAYER M4 ;
        RECT  47.436 229.872 47.52 229.896 ;
    END
  END t_d[92]
  PIN t_d[93]
    DIRECTION INPUT ;
    USE SIGNAL ;
    PORT
      LAYER M4 ;
        RECT  47.436 230.064 47.52 230.088 ;
    END
  END t_d[93]
  PIN t_d[94]
    DIRECTION INPUT ;
    USE SIGNAL ;
    PORT
      LAYER M4 ;
        RECT  47.436 230.256 47.52 230.28 ;
    END
  END t_d[94]
  PIN t_d[95]
    DIRECTION INPUT ;
    USE SIGNAL ;
    PORT
      LAYER M4 ;
        RECT  47.436 230.448 47.52 230.472 ;
    END
  END t_d[95]
  PIN t_d[96]
    DIRECTION INPUT ;
    USE SIGNAL ;
    PORT
      LAYER M4 ;
        RECT  47.436 230.64 47.52 230.664 ;
    END
  END t_d[96]
  PIN t_d[97]
    DIRECTION INPUT ;
    USE SIGNAL ;
    PORT
      LAYER M4 ;
        RECT  47.436 230.832 47.52 230.856 ;
    END
  END t_d[97]
  PIN t_d[98]
    DIRECTION INPUT ;
    USE SIGNAL ;
    PORT
      LAYER M4 ;
        RECT  47.436 231.024 47.52 231.048 ;
    END
  END t_d[98]
  PIN t_d[99]
    DIRECTION INPUT ;
    USE SIGNAL ;
    PORT
      LAYER M4 ;
        RECT  47.436 231.216 47.52 231.24 ;
    END
  END t_d[99]
  PIN t_d[9]
    DIRECTION INPUT ;
    USE SIGNAL ;
    PORT
      LAYER M4 ;
        RECT  47.436 213.744 47.52 213.768 ;
    END
  END t_d[9]
  PIN t_out[0]
    DIRECTION OUTPUT ;
    USE SIGNAL ;
    PORT
      LAYER M4 ;
        RECT  0 211.968 0.084 211.992 ;
    END
  END t_out[0]
  PIN t_out[100]
    DIRECTION OUTPUT ;
    USE SIGNAL ;
    PORT
      LAYER M4 ;
        RECT  0 231.408 0.084 231.432 ;
    END
  END t_out[100]
  PIN t_out[101]
    DIRECTION OUTPUT ;
    USE SIGNAL ;
    PORT
      LAYER M4 ;
        RECT  0 231.6 0.084 231.624 ;
    END
  END t_out[101]
  PIN t_out[102]
    DIRECTION OUTPUT ;
    USE SIGNAL ;
    PORT
      LAYER M4 ;
        RECT  0 231.792 0.084 231.816 ;
    END
  END t_out[102]
  PIN t_out[103]
    DIRECTION OUTPUT ;
    USE SIGNAL ;
    PORT
      LAYER M4 ;
        RECT  0 231.984 0.084 232.008 ;
    END
  END t_out[103]
  PIN t_out[104]
    DIRECTION OUTPUT ;
    USE SIGNAL ;
    PORT
      LAYER M4 ;
        RECT  0 232.176 0.084 232.2 ;
    END
  END t_out[104]
  PIN t_out[105]
    DIRECTION OUTPUT ;
    USE SIGNAL ;
    PORT
      LAYER M4 ;
        RECT  0 232.368 0.084 232.392 ;
    END
  END t_out[105]
  PIN t_out[106]
    DIRECTION OUTPUT ;
    USE SIGNAL ;
    PORT
      LAYER M4 ;
        RECT  0 232.608 0.084 232.632 ;
    END
  END t_out[106]
  PIN t_out[107]
    DIRECTION OUTPUT ;
    USE SIGNAL ;
    PORT
      LAYER M4 ;
        RECT  0 232.8 0.084 232.824 ;
    END
  END t_out[107]
  PIN t_out[108]
    DIRECTION OUTPUT ;
    USE SIGNAL ;
    PORT
      LAYER M4 ;
        RECT  0 232.992 0.084 233.016 ;
    END
  END t_out[108]
  PIN t_out[109]
    DIRECTION OUTPUT ;
    USE SIGNAL ;
    PORT
      LAYER M4 ;
        RECT  0 233.184 0.084 233.208 ;
    END
  END t_out[109]
  PIN t_out[10]
    DIRECTION OUTPUT ;
    USE SIGNAL ;
    PORT
      LAYER M4 ;
        RECT  0 213.936 0.084 213.96 ;
    END
  END t_out[10]
  PIN t_out[110]
    DIRECTION OUTPUT ;
    USE SIGNAL ;
    PORT
      LAYER M4 ;
        RECT  0 233.376 0.084 233.4 ;
    END
  END t_out[110]
  PIN t_out[111]
    DIRECTION OUTPUT ;
    USE SIGNAL ;
    PORT
      LAYER M4 ;
        RECT  0 233.568 0.084 233.592 ;
    END
  END t_out[111]
  PIN t_out[112]
    DIRECTION OUTPUT ;
    USE SIGNAL ;
    PORT
      LAYER M4 ;
        RECT  0 233.76 0.084 233.784 ;
    END
  END t_out[112]
  PIN t_out[113]
    DIRECTION OUTPUT ;
    USE SIGNAL ;
    PORT
      LAYER M4 ;
        RECT  0 233.952 0.084 233.976 ;
    END
  END t_out[113]
  PIN t_out[114]
    DIRECTION OUTPUT ;
    USE SIGNAL ;
    PORT
      LAYER M4 ;
        RECT  0 234.144 0.084 234.168 ;
    END
  END t_out[114]
  PIN t_out[115]
    DIRECTION OUTPUT ;
    USE SIGNAL ;
    PORT
      LAYER M4 ;
        RECT  0 234.336 0.084 234.36 ;
    END
  END t_out[115]
  PIN t_out[116]
    DIRECTION OUTPUT ;
    USE SIGNAL ;
    PORT
      LAYER M4 ;
        RECT  0 234.528 0.084 234.552 ;
    END
  END t_out[116]
  PIN t_out[117]
    DIRECTION OUTPUT ;
    USE SIGNAL ;
    PORT
      LAYER M4 ;
        RECT  0 234.72 0.084 234.744 ;
    END
  END t_out[117]
  PIN t_out[118]
    DIRECTION OUTPUT ;
    USE SIGNAL ;
    PORT
      LAYER M4 ;
        RECT  0 234.912 0.084 234.936 ;
    END
  END t_out[118]
  PIN t_out[119]
    DIRECTION OUTPUT ;
    USE SIGNAL ;
    PORT
      LAYER M4 ;
        RECT  0 235.104 0.084 235.128 ;
    END
  END t_out[119]
  PIN t_out[11]
    DIRECTION OUTPUT ;
    USE SIGNAL ;
    PORT
      LAYER M4 ;
        RECT  0 214.128 0.084 214.152 ;
    END
  END t_out[11]
  PIN t_out[120]
    DIRECTION OUTPUT ;
    USE SIGNAL ;
    PORT
      LAYER M4 ;
        RECT  0 235.296 0.084 235.32 ;
    END
  END t_out[120]
  PIN t_out[121]
    DIRECTION OUTPUT ;
    USE SIGNAL ;
    PORT
      LAYER M4 ;
        RECT  0 235.488 0.084 235.512 ;
    END
  END t_out[121]
  PIN t_out[122]
    DIRECTION OUTPUT ;
    USE SIGNAL ;
    PORT
      LAYER M4 ;
        RECT  0 235.68 0.084 235.704 ;
    END
  END t_out[122]
  PIN t_out[123]
    DIRECTION OUTPUT ;
    USE SIGNAL ;
    PORT
      LAYER M4 ;
        RECT  0 235.872 0.084 235.896 ;
    END
  END t_out[123]
  PIN t_out[124]
    DIRECTION OUTPUT ;
    USE SIGNAL ;
    PORT
      LAYER M4 ;
        RECT  0 236.064 0.084 236.088 ;
    END
  END t_out[124]
  PIN t_out[125]
    DIRECTION OUTPUT ;
    USE SIGNAL ;
    PORT
      LAYER M4 ;
        RECT  0 236.256 0.084 236.28 ;
    END
  END t_out[125]
  PIN t_out[126]
    DIRECTION OUTPUT ;
    USE SIGNAL ;
    PORT
      LAYER M4 ;
        RECT  0 236.448 0.084 236.472 ;
    END
  END t_out[126]
  PIN t_out[127]
    DIRECTION OUTPUT ;
    USE SIGNAL ;
    PORT
      LAYER M4 ;
        RECT  0 236.688 0.084 236.712 ;
    END
  END t_out[127]
  PIN t_out[128]
    DIRECTION OUTPUT ;
    USE SIGNAL ;
    PORT
      LAYER M4 ;
        RECT  0 236.88 0.084 236.904 ;
    END
  END t_out[128]
  PIN t_out[129]
    DIRECTION OUTPUT ;
    USE SIGNAL ;
    PORT
      LAYER M4 ;
        RECT  0 237.072 0.084 237.096 ;
    END
  END t_out[129]
  PIN t_out[12]
    DIRECTION OUTPUT ;
    USE SIGNAL ;
    PORT
      LAYER M4 ;
        RECT  0 214.32 0.084 214.344 ;
    END
  END t_out[12]
  PIN t_out[130]
    DIRECTION OUTPUT ;
    USE SIGNAL ;
    PORT
      LAYER M4 ;
        RECT  0 237.264 0.084 237.288 ;
    END
  END t_out[130]
  PIN t_out[131]
    DIRECTION OUTPUT ;
    USE SIGNAL ;
    PORT
      LAYER M4 ;
        RECT  0 237.456 0.084 237.48 ;
    END
  END t_out[131]
  PIN t_out[132]
    DIRECTION OUTPUT ;
    USE SIGNAL ;
    PORT
      LAYER M4 ;
        RECT  0 237.648 0.084 237.672 ;
    END
  END t_out[132]
  PIN t_out[133]
    DIRECTION OUTPUT ;
    USE SIGNAL ;
    PORT
      LAYER M4 ;
        RECT  0 237.84 0.084 237.864 ;
    END
  END t_out[133]
  PIN t_out[134]
    DIRECTION OUTPUT ;
    USE SIGNAL ;
    PORT
      LAYER M4 ;
        RECT  0 238.032 0.084 238.056 ;
    END
  END t_out[134]
  PIN t_out[135]
    DIRECTION OUTPUT ;
    USE SIGNAL ;
    PORT
      LAYER M4 ;
        RECT  0 238.224 0.084 238.248 ;
    END
  END t_out[135]
  PIN t_out[136]
    DIRECTION OUTPUT ;
    USE SIGNAL ;
    PORT
      LAYER M4 ;
        RECT  0 238.416 0.084 238.44 ;
    END
  END t_out[136]
  PIN t_out[137]
    DIRECTION OUTPUT ;
    USE SIGNAL ;
    PORT
      LAYER M4 ;
        RECT  0 238.608 0.084 238.632 ;
    END
  END t_out[137]
  PIN t_out[138]
    DIRECTION OUTPUT ;
    USE SIGNAL ;
    PORT
      LAYER M4 ;
        RECT  0 238.8 0.084 238.824 ;
    END
  END t_out[138]
  PIN t_out[139]
    DIRECTION OUTPUT ;
    USE SIGNAL ;
    PORT
      LAYER M4 ;
        RECT  0 238.992 0.084 239.016 ;
    END
  END t_out[139]
  PIN t_out[13]
    DIRECTION OUTPUT ;
    USE SIGNAL ;
    PORT
      LAYER M4 ;
        RECT  0 214.512 0.084 214.536 ;
    END
  END t_out[13]
  PIN t_out[140]
    DIRECTION OUTPUT ;
    USE SIGNAL ;
    PORT
      LAYER M4 ;
        RECT  0 239.184 0.084 239.208 ;
    END
  END t_out[140]
  PIN t_out[141]
    DIRECTION OUTPUT ;
    USE SIGNAL ;
    PORT
      LAYER M4 ;
        RECT  0 239.376 0.084 239.4 ;
    END
  END t_out[141]
  PIN t_out[142]
    DIRECTION OUTPUT ;
    USE SIGNAL ;
    PORT
      LAYER M4 ;
        RECT  0 239.568 0.084 239.592 ;
    END
  END t_out[142]
  PIN t_out[143]
    DIRECTION OUTPUT ;
    USE SIGNAL ;
    PORT
      LAYER M4 ;
        RECT  0 239.76 0.084 239.784 ;
    END
  END t_out[143]
  PIN t_out[144]
    DIRECTION OUTPUT ;
    USE SIGNAL ;
    PORT
      LAYER M4 ;
        RECT  0 239.952 0.084 239.976 ;
    END
  END t_out[144]
  PIN t_out[145]
    DIRECTION OUTPUT ;
    USE SIGNAL ;
    PORT
      LAYER M4 ;
        RECT  0 240.144 0.084 240.168 ;
    END
  END t_out[145]
  PIN t_out[146]
    DIRECTION OUTPUT ;
    USE SIGNAL ;
    PORT
      LAYER M4 ;
        RECT  0 240.336 0.084 240.36 ;
    END
  END t_out[146]
  PIN t_out[147]
    DIRECTION OUTPUT ;
    USE SIGNAL ;
    PORT
      LAYER M4 ;
        RECT  0 240.576 0.084 240.6 ;
    END
  END t_out[147]
  PIN t_out[148]
    DIRECTION OUTPUT ;
    USE SIGNAL ;
    PORT
      LAYER M4 ;
        RECT  0 240.768 0.084 240.792 ;
    END
  END t_out[148]
  PIN t_out[149]
    DIRECTION OUTPUT ;
    USE SIGNAL ;
    PORT
      LAYER M4 ;
        RECT  0 240.96 0.084 240.984 ;
    END
  END t_out[149]
  PIN t_out[14]
    DIRECTION OUTPUT ;
    USE SIGNAL ;
    PORT
      LAYER M4 ;
        RECT  0 214.704 0.084 214.728 ;
    END
  END t_out[14]
  PIN t_out[150]
    DIRECTION OUTPUT ;
    USE SIGNAL ;
    PORT
      LAYER M4 ;
        RECT  0 241.152 0.084 241.176 ;
    END
  END t_out[150]
  PIN t_out[151]
    DIRECTION OUTPUT ;
    USE SIGNAL ;
    PORT
      LAYER M4 ;
        RECT  0 241.344 0.084 241.368 ;
    END
  END t_out[151]
  PIN t_out[152]
    DIRECTION OUTPUT ;
    USE SIGNAL ;
    PORT
      LAYER M4 ;
        RECT  0 241.536 0.084 241.56 ;
    END
  END t_out[152]
  PIN t_out[153]
    DIRECTION OUTPUT ;
    USE SIGNAL ;
    PORT
      LAYER M4 ;
        RECT  0 241.728 0.084 241.752 ;
    END
  END t_out[153]
  PIN t_out[154]
    DIRECTION OUTPUT ;
    USE SIGNAL ;
    PORT
      LAYER M4 ;
        RECT  0 241.92 0.084 241.944 ;
    END
  END t_out[154]
  PIN t_out[155]
    DIRECTION OUTPUT ;
    USE SIGNAL ;
    PORT
      LAYER M4 ;
        RECT  0 242.112 0.084 242.136 ;
    END
  END t_out[155]
  PIN t_out[156]
    DIRECTION OUTPUT ;
    USE SIGNAL ;
    PORT
      LAYER M4 ;
        RECT  0 242.304 0.084 242.328 ;
    END
  END t_out[156]
  PIN t_out[157]
    DIRECTION OUTPUT ;
    USE SIGNAL ;
    PORT
      LAYER M4 ;
        RECT  0 242.496 0.084 242.52 ;
    END
  END t_out[157]
  PIN t_out[158]
    DIRECTION OUTPUT ;
    USE SIGNAL ;
    PORT
      LAYER M4 ;
        RECT  0 242.688 0.084 242.712 ;
    END
  END t_out[158]
  PIN t_out[159]
    DIRECTION OUTPUT ;
    USE SIGNAL ;
    PORT
      LAYER M4 ;
        RECT  0 242.88 0.084 242.904 ;
    END
  END t_out[159]
  PIN t_out[15]
    DIRECTION OUTPUT ;
    USE SIGNAL ;
    PORT
      LAYER M4 ;
        RECT  0 214.896 0.084 214.92 ;
    END
  END t_out[15]
  PIN t_out[160]
    DIRECTION OUTPUT ;
    USE SIGNAL ;
    PORT
      LAYER M4 ;
        RECT  0 243.072 0.084 243.096 ;
    END
  END t_out[160]
  PIN t_out[161]
    DIRECTION OUTPUT ;
    USE SIGNAL ;
    PORT
      LAYER M4 ;
        RECT  0 243.264 0.084 243.288 ;
    END
  END t_out[161]
  PIN t_out[162]
    DIRECTION OUTPUT ;
    USE SIGNAL ;
    PORT
      LAYER M4 ;
        RECT  0 243.456 0.084 243.48 ;
    END
  END t_out[162]
  PIN t_out[163]
    DIRECTION OUTPUT ;
    USE SIGNAL ;
    PORT
      LAYER M4 ;
        RECT  0 243.648 0.084 243.672 ;
    END
  END t_out[163]
  PIN t_out[164]
    DIRECTION OUTPUT ;
    USE SIGNAL ;
    PORT
      LAYER M4 ;
        RECT  0 243.84 0.084 243.864 ;
    END
  END t_out[164]
  PIN t_out[165]
    DIRECTION OUTPUT ;
    USE SIGNAL ;
    PORT
      LAYER M4 ;
        RECT  0 244.032 0.084 244.056 ;
    END
  END t_out[165]
  PIN t_out[166]
    DIRECTION OUTPUT ;
    USE SIGNAL ;
    PORT
      LAYER M4 ;
        RECT  0 244.224 0.084 244.248 ;
    END
  END t_out[166]
  PIN t_out[167]
    DIRECTION OUTPUT ;
    USE SIGNAL ;
    PORT
      LAYER M4 ;
        RECT  0 244.416 0.084 244.44 ;
    END
  END t_out[167]
  PIN t_out[168]
    DIRECTION OUTPUT ;
    USE SIGNAL ;
    PORT
      LAYER M4 ;
        RECT  0 244.656 0.084 244.68 ;
    END
  END t_out[168]
  PIN t_out[169]
    DIRECTION OUTPUT ;
    USE SIGNAL ;
    PORT
      LAYER M4 ;
        RECT  0 244.848 0.084 244.872 ;
    END
  END t_out[169]
  PIN t_out[16]
    DIRECTION OUTPUT ;
    USE SIGNAL ;
    PORT
      LAYER M4 ;
        RECT  0 215.088 0.084 215.112 ;
    END
  END t_out[16]
  PIN t_out[170]
    DIRECTION OUTPUT ;
    USE SIGNAL ;
    PORT
      LAYER M4 ;
        RECT  0 245.04 0.084 245.064 ;
    END
  END t_out[170]
  PIN t_out[171]
    DIRECTION OUTPUT ;
    USE SIGNAL ;
    PORT
      LAYER M4 ;
        RECT  0 245.232 0.084 245.256 ;
    END
  END t_out[171]
  PIN t_out[172]
    DIRECTION OUTPUT ;
    USE SIGNAL ;
    PORT
      LAYER M4 ;
        RECT  0 245.424 0.084 245.448 ;
    END
  END t_out[172]
  PIN t_out[173]
    DIRECTION OUTPUT ;
    USE SIGNAL ;
    PORT
      LAYER M4 ;
        RECT  0 245.616 0.084 245.64 ;
    END
  END t_out[173]
  PIN t_out[174]
    DIRECTION OUTPUT ;
    USE SIGNAL ;
    PORT
      LAYER M4 ;
        RECT  0 245.808 0.084 245.832 ;
    END
  END t_out[174]
  PIN t_out[175]
    DIRECTION OUTPUT ;
    USE SIGNAL ;
    PORT
      LAYER M4 ;
        RECT  0 246 0.084 246.024 ;
    END
  END t_out[175]
  PIN t_out[176]
    DIRECTION OUTPUT ;
    USE SIGNAL ;
    PORT
      LAYER M4 ;
        RECT  0 246.192 0.084 246.216 ;
    END
  END t_out[176]
  PIN t_out[177]
    DIRECTION OUTPUT ;
    USE SIGNAL ;
    PORT
      LAYER M4 ;
        RECT  0 246.384 0.084 246.408 ;
    END
  END t_out[177]
  PIN t_out[178]
    DIRECTION OUTPUT ;
    USE SIGNAL ;
    PORT
      LAYER M4 ;
        RECT  0 246.576 0.084 246.6 ;
    END
  END t_out[178]
  PIN t_out[179]
    DIRECTION OUTPUT ;
    USE SIGNAL ;
    PORT
      LAYER M4 ;
        RECT  0 246.768 0.084 246.792 ;
    END
  END t_out[179]
  PIN t_out[17]
    DIRECTION OUTPUT ;
    USE SIGNAL ;
    PORT
      LAYER M4 ;
        RECT  0 215.28 0.084 215.304 ;
    END
  END t_out[17]
  PIN t_out[180]
    DIRECTION OUTPUT ;
    USE SIGNAL ;
    PORT
      LAYER M4 ;
        RECT  0 246.96 0.084 246.984 ;
    END
  END t_out[180]
  PIN t_out[181]
    DIRECTION OUTPUT ;
    USE SIGNAL ;
    PORT
      LAYER M4 ;
        RECT  0 247.152 0.084 247.176 ;
    END
  END t_out[181]
  PIN t_out[182]
    DIRECTION OUTPUT ;
    USE SIGNAL ;
    PORT
      LAYER M4 ;
        RECT  0 247.344 0.084 247.368 ;
    END
  END t_out[182]
  PIN t_out[183]
    DIRECTION OUTPUT ;
    USE SIGNAL ;
    PORT
      LAYER M4 ;
        RECT  0 247.536 0.084 247.56 ;
    END
  END t_out[183]
  PIN t_out[184]
    DIRECTION OUTPUT ;
    USE SIGNAL ;
    PORT
      LAYER M4 ;
        RECT  0 247.728 0.084 247.752 ;
    END
  END t_out[184]
  PIN t_out[185]
    DIRECTION OUTPUT ;
    USE SIGNAL ;
    PORT
      LAYER M4 ;
        RECT  0 247.92 0.084 247.944 ;
    END
  END t_out[185]
  PIN t_out[186]
    DIRECTION OUTPUT ;
    USE SIGNAL ;
    PORT
      LAYER M4 ;
        RECT  0 248.112 0.084 248.136 ;
    END
  END t_out[186]
  PIN t_out[187]
    DIRECTION OUTPUT ;
    USE SIGNAL ;
    PORT
      LAYER M4 ;
        RECT  0 248.304 0.084 248.328 ;
    END
  END t_out[187]
  PIN t_out[188]
    DIRECTION OUTPUT ;
    USE SIGNAL ;
    PORT
      LAYER M4 ;
        RECT  0 248.544 0.084 248.568 ;
    END
  END t_out[188]
  PIN t_out[189]
    DIRECTION OUTPUT ;
    USE SIGNAL ;
    PORT
      LAYER M4 ;
        RECT  0 248.736 0.084 248.76 ;
    END
  END t_out[189]
  PIN t_out[18]
    DIRECTION OUTPUT ;
    USE SIGNAL ;
    PORT
      LAYER M4 ;
        RECT  0 215.472 0.084 215.496 ;
    END
  END t_out[18]
  PIN t_out[190]
    DIRECTION OUTPUT ;
    USE SIGNAL ;
    PORT
      LAYER M4 ;
        RECT  0 248.928 0.084 248.952 ;
    END
  END t_out[190]
  PIN t_out[191]
    DIRECTION OUTPUT ;
    USE SIGNAL ;
    PORT
      LAYER M4 ;
        RECT  0 249.12 0.084 249.144 ;
    END
  END t_out[191]
  PIN t_out[192]
    DIRECTION OUTPUT ;
    USE SIGNAL ;
    PORT
      LAYER M4 ;
        RECT  0 249.312 0.084 249.336 ;
    END
  END t_out[192]
  PIN t_out[193]
    DIRECTION OUTPUT ;
    USE SIGNAL ;
    PORT
      LAYER M4 ;
        RECT  0 249.504 0.084 249.528 ;
    END
  END t_out[193]
  PIN t_out[194]
    DIRECTION OUTPUT ;
    USE SIGNAL ;
    PORT
      LAYER M4 ;
        RECT  0 249.696 0.084 249.72 ;
    END
  END t_out[194]
  PIN t_out[195]
    DIRECTION OUTPUT ;
    USE SIGNAL ;
    PORT
      LAYER M4 ;
        RECT  0 249.888 0.084 249.912 ;
    END
  END t_out[195]
  PIN t_out[196]
    DIRECTION OUTPUT ;
    USE SIGNAL ;
    PORT
      LAYER M4 ;
        RECT  0 250.08 0.084 250.104 ;
    END
  END t_out[196]
  PIN t_out[197]
    DIRECTION OUTPUT ;
    USE SIGNAL ;
    PORT
      LAYER M4 ;
        RECT  0 250.272 0.084 250.296 ;
    END
  END t_out[197]
  PIN t_out[198]
    DIRECTION OUTPUT ;
    USE SIGNAL ;
    PORT
      LAYER M4 ;
        RECT  0 250.464 0.084 250.488 ;
    END
  END t_out[198]
  PIN t_out[199]
    DIRECTION OUTPUT ;
    USE SIGNAL ;
    PORT
      LAYER M4 ;
        RECT  0 250.656 0.084 250.68 ;
    END
  END t_out[199]
  PIN t_out[19]
    DIRECTION OUTPUT ;
    USE SIGNAL ;
    PORT
      LAYER M4 ;
        RECT  0 215.664 0.084 215.688 ;
    END
  END t_out[19]
  PIN t_out[1]
    DIRECTION OUTPUT ;
    USE SIGNAL ;
    PORT
      LAYER M4 ;
        RECT  0 212.16 0.084 212.184 ;
    END
  END t_out[1]
  PIN t_out[200]
    DIRECTION OUTPUT ;
    USE SIGNAL ;
    PORT
      LAYER M4 ;
        RECT  0 250.848 0.084 250.872 ;
    END
  END t_out[200]
  PIN t_out[201]
    DIRECTION OUTPUT ;
    USE SIGNAL ;
    PORT
      LAYER M4 ;
        RECT  0 251.04 0.084 251.064 ;
    END
  END t_out[201]
  PIN t_out[202]
    DIRECTION OUTPUT ;
    USE SIGNAL ;
    PORT
      LAYER M4 ;
        RECT  0 251.232 0.084 251.256 ;
    END
  END t_out[202]
  PIN t_out[203]
    DIRECTION OUTPUT ;
    USE SIGNAL ;
    PORT
      LAYER M4 ;
        RECT  0 251.424 0.084 251.448 ;
    END
  END t_out[203]
  PIN t_out[204]
    DIRECTION OUTPUT ;
    USE SIGNAL ;
    PORT
      LAYER M4 ;
        RECT  0 251.616 0.084 251.64 ;
    END
  END t_out[204]
  PIN t_out[205]
    DIRECTION OUTPUT ;
    USE SIGNAL ;
    PORT
      LAYER M4 ;
        RECT  0 251.808 0.084 251.832 ;
    END
  END t_out[205]
  PIN t_out[206]
    DIRECTION OUTPUT ;
    USE SIGNAL ;
    PORT
      LAYER M4 ;
        RECT  0 252 0.084 252.024 ;
    END
  END t_out[206]
  PIN t_out[207]
    DIRECTION OUTPUT ;
    USE SIGNAL ;
    PORT
      LAYER M4 ;
        RECT  0 252.192 0.084 252.216 ;
    END
  END t_out[207]
  PIN t_out[208]
    DIRECTION OUTPUT ;
    USE SIGNAL ;
    PORT
      LAYER M4 ;
        RECT  0 252.384 0.084 252.408 ;
    END
  END t_out[208]
  PIN t_out[209]
    DIRECTION OUTPUT ;
    USE SIGNAL ;
    PORT
      LAYER M4 ;
        RECT  0 252.624 0.084 252.648 ;
    END
  END t_out[209]
  PIN t_out[20]
    DIRECTION OUTPUT ;
    USE SIGNAL ;
    PORT
      LAYER M4 ;
        RECT  0 215.856 0.084 215.88 ;
    END
  END t_out[20]
  PIN t_out[210]
    DIRECTION OUTPUT ;
    USE SIGNAL ;
    PORT
      LAYER M4 ;
        RECT  0 252.816 0.084 252.84 ;
    END
  END t_out[210]
  PIN t_out[211]
    DIRECTION OUTPUT ;
    USE SIGNAL ;
    PORT
      LAYER M4 ;
        RECT  0 253.008 0.084 253.032 ;
    END
  END t_out[211]
  PIN t_out[212]
    DIRECTION OUTPUT ;
    USE SIGNAL ;
    PORT
      LAYER M4 ;
        RECT  0 253.2 0.084 253.224 ;
    END
  END t_out[212]
  PIN t_out[213]
    DIRECTION OUTPUT ;
    USE SIGNAL ;
    PORT
      LAYER M4 ;
        RECT  0 253.392 0.084 253.416 ;
    END
  END t_out[213]
  PIN t_out[214]
    DIRECTION OUTPUT ;
    USE SIGNAL ;
    PORT
      LAYER M4 ;
        RECT  0 253.584 0.084 253.608 ;
    END
  END t_out[214]
  PIN t_out[215]
    DIRECTION OUTPUT ;
    USE SIGNAL ;
    PORT
      LAYER M4 ;
        RECT  0 253.776 0.084 253.8 ;
    END
  END t_out[215]
  PIN t_out[216]
    DIRECTION OUTPUT ;
    USE SIGNAL ;
    PORT
      LAYER M4 ;
        RECT  0 253.968 0.084 253.992 ;
    END
  END t_out[216]
  PIN t_out[217]
    DIRECTION OUTPUT ;
    USE SIGNAL ;
    PORT
      LAYER M4 ;
        RECT  0 254.16 0.084 254.184 ;
    END
  END t_out[217]
  PIN t_out[218]
    DIRECTION OUTPUT ;
    USE SIGNAL ;
    PORT
      LAYER M4 ;
        RECT  0 254.352 0.084 254.376 ;
    END
  END t_out[218]
  PIN t_out[219]
    DIRECTION OUTPUT ;
    USE SIGNAL ;
    PORT
      LAYER M4 ;
        RECT  0 254.544 0.084 254.568 ;
    END
  END t_out[219]
  PIN t_out[21]
    DIRECTION OUTPUT ;
    USE SIGNAL ;
    PORT
      LAYER M4 ;
        RECT  0 216.048 0.084 216.072 ;
    END
  END t_out[21]
  PIN t_out[220]
    DIRECTION OUTPUT ;
    USE SIGNAL ;
    PORT
      LAYER M4 ;
        RECT  0 254.736 0.084 254.76 ;
    END
  END t_out[220]
  PIN t_out[221]
    DIRECTION OUTPUT ;
    USE SIGNAL ;
    PORT
      LAYER M4 ;
        RECT  0 254.928 0.084 254.952 ;
    END
  END t_out[221]
  PIN t_out[222]
    DIRECTION OUTPUT ;
    USE SIGNAL ;
    PORT
      LAYER M4 ;
        RECT  0 255.12 0.084 255.144 ;
    END
  END t_out[222]
  PIN t_out[223]
    DIRECTION OUTPUT ;
    USE SIGNAL ;
    PORT
      LAYER M4 ;
        RECT  0 255.312 0.084 255.336 ;
    END
  END t_out[223]
  PIN t_out[224]
    DIRECTION OUTPUT ;
    USE SIGNAL ;
    PORT
      LAYER M4 ;
        RECT  0 255.504 0.084 255.528 ;
    END
  END t_out[224]
  PIN t_out[225]
    DIRECTION OUTPUT ;
    USE SIGNAL ;
    PORT
      LAYER M4 ;
        RECT  0 255.696 0.084 255.72 ;
    END
  END t_out[225]
  PIN t_out[226]
    DIRECTION OUTPUT ;
    USE SIGNAL ;
    PORT
      LAYER M4 ;
        RECT  0 255.888 0.084 255.912 ;
    END
  END t_out[226]
  PIN t_out[227]
    DIRECTION OUTPUT ;
    USE SIGNAL ;
    PORT
      LAYER M4 ;
        RECT  0 256.08 0.084 256.104 ;
    END
  END t_out[227]
  PIN t_out[228]
    DIRECTION OUTPUT ;
    USE SIGNAL ;
    PORT
      LAYER M4 ;
        RECT  0 256.272 0.084 256.296 ;
    END
  END t_out[228]
  PIN t_out[229]
    DIRECTION OUTPUT ;
    USE SIGNAL ;
    PORT
      LAYER M4 ;
        RECT  0 256.512 0.084 256.536 ;
    END
  END t_out[229]
  PIN t_out[22]
    DIRECTION OUTPUT ;
    USE SIGNAL ;
    PORT
      LAYER M4 ;
        RECT  0 216.24 0.084 216.264 ;
    END
  END t_out[22]
  PIN t_out[230]
    DIRECTION OUTPUT ;
    USE SIGNAL ;
    PORT
      LAYER M4 ;
        RECT  0 256.704 0.084 256.728 ;
    END
  END t_out[230]
  PIN t_out[231]
    DIRECTION OUTPUT ;
    USE SIGNAL ;
    PORT
      LAYER M4 ;
        RECT  0 256.896 0.084 256.92 ;
    END
  END t_out[231]
  PIN t_out[232]
    DIRECTION OUTPUT ;
    USE SIGNAL ;
    PORT
      LAYER M4 ;
        RECT  0 257.088 0.084 257.112 ;
    END
  END t_out[232]
  PIN t_out[233]
    DIRECTION OUTPUT ;
    USE SIGNAL ;
    PORT
      LAYER M4 ;
        RECT  0 257.28 0.084 257.304 ;
    END
  END t_out[233]
  PIN t_out[234]
    DIRECTION OUTPUT ;
    USE SIGNAL ;
    PORT
      LAYER M4 ;
        RECT  0 257.472 0.084 257.496 ;
    END
  END t_out[234]
  PIN t_out[235]
    DIRECTION OUTPUT ;
    USE SIGNAL ;
    PORT
      LAYER M4 ;
        RECT  0 257.664 0.084 257.688 ;
    END
  END t_out[235]
  PIN t_out[236]
    DIRECTION OUTPUT ;
    USE SIGNAL ;
    PORT
      LAYER M4 ;
        RECT  0 257.856 0.084 257.88 ;
    END
  END t_out[236]
  PIN t_out[237]
    DIRECTION OUTPUT ;
    USE SIGNAL ;
    PORT
      LAYER M4 ;
        RECT  0 258.048 0.084 258.072 ;
    END
  END t_out[237]
  PIN t_out[238]
    DIRECTION OUTPUT ;
    USE SIGNAL ;
    PORT
      LAYER M4 ;
        RECT  0 258.24 0.084 258.264 ;
    END
  END t_out[238]
  PIN t_out[239]
    DIRECTION OUTPUT ;
    USE SIGNAL ;
    PORT
      LAYER M4 ;
        RECT  0 258.432 0.084 258.456 ;
    END
  END t_out[239]
  PIN t_out[23]
    DIRECTION OUTPUT ;
    USE SIGNAL ;
    PORT
      LAYER M4 ;
        RECT  0 216.432 0.084 216.456 ;
    END
  END t_out[23]
  PIN t_out[240]
    DIRECTION OUTPUT ;
    USE SIGNAL ;
    PORT
      LAYER M4 ;
        RECT  0 258.624 0.084 258.648 ;
    END
  END t_out[240]
  PIN t_out[241]
    DIRECTION OUTPUT ;
    USE SIGNAL ;
    PORT
      LAYER M4 ;
        RECT  0 258.816 0.084 258.84 ;
    END
  END t_out[241]
  PIN t_out[242]
    DIRECTION OUTPUT ;
    USE SIGNAL ;
    PORT
      LAYER M4 ;
        RECT  0 259.008 0.084 259.032 ;
    END
  END t_out[242]
  PIN t_out[243]
    DIRECTION OUTPUT ;
    USE SIGNAL ;
    PORT
      LAYER M4 ;
        RECT  0 259.2 0.084 259.224 ;
    END
  END t_out[243]
  PIN t_out[244]
    DIRECTION OUTPUT ;
    USE SIGNAL ;
    PORT
      LAYER M4 ;
        RECT  0 259.392 0.084 259.416 ;
    END
  END t_out[244]
  PIN t_out[245]
    DIRECTION OUTPUT ;
    USE SIGNAL ;
    PORT
      LAYER M4 ;
        RECT  0 259.584 0.084 259.608 ;
    END
  END t_out[245]
  PIN t_out[246]
    DIRECTION OUTPUT ;
    USE SIGNAL ;
    PORT
      LAYER M4 ;
        RECT  0 259.776 0.084 259.8 ;
    END
  END t_out[246]
  PIN t_out[247]
    DIRECTION OUTPUT ;
    USE SIGNAL ;
    PORT
      LAYER M4 ;
        RECT  0 259.968 0.084 259.992 ;
    END
  END t_out[247]
  PIN t_out[248]
    DIRECTION OUTPUT ;
    USE SIGNAL ;
    PORT
      LAYER M4 ;
        RECT  0 260.16 0.084 260.184 ;
    END
  END t_out[248]
  PIN t_out[249]
    DIRECTION OUTPUT ;
    USE SIGNAL ;
    PORT
      LAYER M4 ;
        RECT  0 260.352 0.084 260.376 ;
    END
  END t_out[249]
  PIN t_out[24]
    DIRECTION OUTPUT ;
    USE SIGNAL ;
    PORT
      LAYER M4 ;
        RECT  0 216.672 0.084 216.696 ;
    END
  END t_out[24]
  PIN t_out[250]
    DIRECTION OUTPUT ;
    USE SIGNAL ;
    PORT
      LAYER M4 ;
        RECT  0 260.592 0.084 260.616 ;
    END
  END t_out[250]
  PIN t_out[251]
    DIRECTION OUTPUT ;
    USE SIGNAL ;
    PORT
      LAYER M4 ;
        RECT  0 260.784 0.084 260.808 ;
    END
  END t_out[251]
  PIN t_out[252]
    DIRECTION OUTPUT ;
    USE SIGNAL ;
    PORT
      LAYER M4 ;
        RECT  0 260.976 0.084 261 ;
    END
  END t_out[252]
  PIN t_out[253]
    DIRECTION OUTPUT ;
    USE SIGNAL ;
    PORT
      LAYER M4 ;
        RECT  0 261.168 0.084 261.192 ;
    END
  END t_out[253]
  PIN t_out[254]
    DIRECTION OUTPUT ;
    USE SIGNAL ;
    PORT
      LAYER M4 ;
        RECT  0 261.36 0.084 261.384 ;
    END
  END t_out[254]
  PIN t_out[255]
    DIRECTION OUTPUT ;
    USE SIGNAL ;
    PORT
      LAYER M4 ;
        RECT  0 261.552 0.084 261.576 ;
    END
  END t_out[255]
  PIN t_out[256]
    DIRECTION OUTPUT ;
    USE SIGNAL ;
    PORT
      LAYER M4 ;
        RECT  0 261.744 0.084 261.768 ;
    END
  END t_out[256]
  PIN t_out[257]
    DIRECTION OUTPUT ;
    USE SIGNAL ;
    PORT
      LAYER M4 ;
        RECT  0 261.936 0.084 261.96 ;
    END
  END t_out[257]
  PIN t_out[258]
    DIRECTION OUTPUT ;
    USE SIGNAL ;
    PORT
      LAYER M4 ;
        RECT  0 262.128 0.084 262.152 ;
    END
  END t_out[258]
  PIN t_out[259]
    DIRECTION OUTPUT ;
    USE SIGNAL ;
    PORT
      LAYER M4 ;
        RECT  0 262.32 0.084 262.344 ;
    END
  END t_out[259]
  PIN t_out[25]
    DIRECTION OUTPUT ;
    USE SIGNAL ;
    PORT
      LAYER M4 ;
        RECT  0 216.864 0.084 216.888 ;
    END
  END t_out[25]
  PIN t_out[260]
    DIRECTION OUTPUT ;
    USE SIGNAL ;
    PORT
      LAYER M4 ;
        RECT  0 262.512 0.084 262.536 ;
    END
  END t_out[260]
  PIN t_out[261]
    DIRECTION OUTPUT ;
    USE SIGNAL ;
    PORT
      LAYER M4 ;
        RECT  0 262.704 0.084 262.728 ;
    END
  END t_out[261]
  PIN t_out[262]
    DIRECTION OUTPUT ;
    USE SIGNAL ;
    PORT
      LAYER M4 ;
        RECT  0 262.896 0.084 262.92 ;
    END
  END t_out[262]
  PIN t_out[263]
    DIRECTION OUTPUT ;
    USE SIGNAL ;
    PORT
      LAYER M4 ;
        RECT  0 263.088 0.084 263.112 ;
    END
  END t_out[263]
  PIN t_out[264]
    DIRECTION OUTPUT ;
    USE SIGNAL ;
    PORT
      LAYER M4 ;
        RECT  0 263.28 0.084 263.304 ;
    END
  END t_out[264]
  PIN t_out[265]
    DIRECTION OUTPUT ;
    USE SIGNAL ;
    PORT
      LAYER M4 ;
        RECT  0 263.472 0.084 263.496 ;
    END
  END t_out[265]
  PIN t_out[266]
    DIRECTION OUTPUT ;
    USE SIGNAL ;
    PORT
      LAYER M4 ;
        RECT  0 263.664 0.084 263.688 ;
    END
  END t_out[266]
  PIN t_out[267]
    DIRECTION OUTPUT ;
    USE SIGNAL ;
    PORT
      LAYER M4 ;
        RECT  0 263.856 0.084 263.88 ;
    END
  END t_out[267]
  PIN t_out[268]
    DIRECTION OUTPUT ;
    USE SIGNAL ;
    PORT
      LAYER M4 ;
        RECT  0 264.048 0.084 264.072 ;
    END
  END t_out[268]
  PIN t_out[269]
    DIRECTION OUTPUT ;
    USE SIGNAL ;
    PORT
      LAYER M4 ;
        RECT  0 264.24 0.084 264.264 ;
    END
  END t_out[269]
  PIN t_out[26]
    DIRECTION OUTPUT ;
    USE SIGNAL ;
    PORT
      LAYER M4 ;
        RECT  0 217.056 0.084 217.08 ;
    END
  END t_out[26]
  PIN t_out[270]
    DIRECTION OUTPUT ;
    USE SIGNAL ;
    PORT
      LAYER M4 ;
        RECT  0 264.48 0.084 264.504 ;
    END
  END t_out[270]
  PIN t_out[271]
    DIRECTION OUTPUT ;
    USE SIGNAL ;
    PORT
      LAYER M4 ;
        RECT  0 264.672 0.084 264.696 ;
    END
  END t_out[271]
  PIN t_out[272]
    DIRECTION OUTPUT ;
    USE SIGNAL ;
    PORT
      LAYER M4 ;
        RECT  0 264.864 0.084 264.888 ;
    END
  END t_out[272]
  PIN t_out[273]
    DIRECTION OUTPUT ;
    USE SIGNAL ;
    PORT
      LAYER M4 ;
        RECT  0 265.056 0.084 265.08 ;
    END
  END t_out[273]
  PIN t_out[274]
    DIRECTION OUTPUT ;
    USE SIGNAL ;
    PORT
      LAYER M4 ;
        RECT  0 265.248 0.084 265.272 ;
    END
  END t_out[274]
  PIN t_out[275]
    DIRECTION OUTPUT ;
    USE SIGNAL ;
    PORT
      LAYER M4 ;
        RECT  0 265.44 0.084 265.464 ;
    END
  END t_out[275]
  PIN t_out[276]
    DIRECTION OUTPUT ;
    USE SIGNAL ;
    PORT
      LAYER M4 ;
        RECT  0 265.632 0.084 265.656 ;
    END
  END t_out[276]
  PIN t_out[277]
    DIRECTION OUTPUT ;
    USE SIGNAL ;
    PORT
      LAYER M4 ;
        RECT  0 265.824 0.084 265.848 ;
    END
  END t_out[277]
  PIN t_out[278]
    DIRECTION OUTPUT ;
    USE SIGNAL ;
    PORT
      LAYER M4 ;
        RECT  0 266.016 0.084 266.04 ;
    END
  END t_out[278]
  PIN t_out[279]
    DIRECTION OUTPUT ;
    USE SIGNAL ;
    PORT
      LAYER M4 ;
        RECT  0 266.208 0.084 266.232 ;
    END
  END t_out[279]
  PIN t_out[27]
    DIRECTION OUTPUT ;
    USE SIGNAL ;
    PORT
      LAYER M4 ;
        RECT  0 217.248 0.084 217.272 ;
    END
  END t_out[27]
  PIN t_out[280]
    DIRECTION OUTPUT ;
    USE SIGNAL ;
    PORT
      LAYER M4 ;
        RECT  0 266.4 0.084 266.424 ;
    END
  END t_out[280]
  PIN t_out[281]
    DIRECTION OUTPUT ;
    USE SIGNAL ;
    PORT
      LAYER M4 ;
        RECT  0 266.592 0.084 266.616 ;
    END
  END t_out[281]
  PIN t_out[282]
    DIRECTION OUTPUT ;
    USE SIGNAL ;
    PORT
      LAYER M4 ;
        RECT  0 266.784 0.084 266.808 ;
    END
  END t_out[282]
  PIN t_out[283]
    DIRECTION OUTPUT ;
    USE SIGNAL ;
    PORT
      LAYER M4 ;
        RECT  0 266.976 0.084 267 ;
    END
  END t_out[283]
  PIN t_out[284]
    DIRECTION OUTPUT ;
    USE SIGNAL ;
    PORT
      LAYER M4 ;
        RECT  0 267.168 0.084 267.192 ;
    END
  END t_out[284]
  PIN t_out[285]
    DIRECTION OUTPUT ;
    USE SIGNAL ;
    PORT
      LAYER M4 ;
        RECT  0 267.36 0.084 267.384 ;
    END
  END t_out[285]
  PIN t_out[286]
    DIRECTION OUTPUT ;
    USE SIGNAL ;
    PORT
      LAYER M4 ;
        RECT  0 267.552 0.084 267.576 ;
    END
  END t_out[286]
  PIN t_out[287]
    DIRECTION OUTPUT ;
    USE SIGNAL ;
    PORT
      LAYER M4 ;
        RECT  0 267.744 0.084 267.768 ;
    END
  END t_out[287]
  PIN t_out[288]
    DIRECTION OUTPUT ;
    USE SIGNAL ;
    PORT
      LAYER M4 ;
        RECT  0 267.936 0.084 267.96 ;
    END
  END t_out[288]
  PIN t_out[289]
    DIRECTION OUTPUT ;
    USE SIGNAL ;
    PORT
      LAYER M4 ;
        RECT  0 268.128 0.084 268.152 ;
    END
  END t_out[289]
  PIN t_out[28]
    DIRECTION OUTPUT ;
    USE SIGNAL ;
    PORT
      LAYER M4 ;
        RECT  0 217.44 0.084 217.464 ;
    END
  END t_out[28]
  PIN t_out[290]
    DIRECTION OUTPUT ;
    USE SIGNAL ;
    PORT
      LAYER M4 ;
        RECT  0 268.32 0.084 268.344 ;
    END
  END t_out[290]
  PIN t_out[291]
    DIRECTION OUTPUT ;
    USE SIGNAL ;
    PORT
      LAYER M4 ;
        RECT  0 268.56 0.084 268.584 ;
    END
  END t_out[291]
  PIN t_out[292]
    DIRECTION OUTPUT ;
    USE SIGNAL ;
    PORT
      LAYER M4 ;
        RECT  0 268.752 0.084 268.776 ;
    END
  END t_out[292]
  PIN t_out[293]
    DIRECTION OUTPUT ;
    USE SIGNAL ;
    PORT
      LAYER M4 ;
        RECT  0 268.944 0.084 268.968 ;
    END
  END t_out[293]
  PIN t_out[294]
    DIRECTION OUTPUT ;
    USE SIGNAL ;
    PORT
      LAYER M4 ;
        RECT  0 269.136 0.084 269.16 ;
    END
  END t_out[294]
  PIN t_out[295]
    DIRECTION OUTPUT ;
    USE SIGNAL ;
    PORT
      LAYER M4 ;
        RECT  0 269.328 0.084 269.352 ;
    END
  END t_out[295]
  PIN t_out[296]
    DIRECTION OUTPUT ;
    USE SIGNAL ;
    PORT
      LAYER M4 ;
        RECT  0 269.52 0.084 269.544 ;
    END
  END t_out[296]
  PIN t_out[297]
    DIRECTION OUTPUT ;
    USE SIGNAL ;
    PORT
      LAYER M4 ;
        RECT  0 269.712 0.084 269.736 ;
    END
  END t_out[297]
  PIN t_out[298]
    DIRECTION OUTPUT ;
    USE SIGNAL ;
    PORT
      LAYER M4 ;
        RECT  0 269.904 0.084 269.928 ;
    END
  END t_out[298]
  PIN t_out[299]
    DIRECTION OUTPUT ;
    USE SIGNAL ;
    PORT
      LAYER M4 ;
        RECT  0 270.096 0.084 270.12 ;
    END
  END t_out[299]
  PIN t_out[29]
    DIRECTION OUTPUT ;
    USE SIGNAL ;
    PORT
      LAYER M4 ;
        RECT  0 217.632 0.084 217.656 ;
    END
  END t_out[29]
  PIN t_out[2]
    DIRECTION OUTPUT ;
    USE SIGNAL ;
    PORT
      LAYER M4 ;
        RECT  0 212.352 0.084 212.376 ;
    END
  END t_out[2]
  PIN t_out[300]
    DIRECTION OUTPUT ;
    USE SIGNAL ;
    PORT
      LAYER M4 ;
        RECT  0 270.288 0.084 270.312 ;
    END
  END t_out[300]
  PIN t_out[301]
    DIRECTION OUTPUT ;
    USE SIGNAL ;
    PORT
      LAYER M4 ;
        RECT  0 270.48 0.084 270.504 ;
    END
  END t_out[301]
  PIN t_out[302]
    DIRECTION OUTPUT ;
    USE SIGNAL ;
    PORT
      LAYER M4 ;
        RECT  0 270.672 0.084 270.696 ;
    END
  END t_out[302]
  PIN t_out[303]
    DIRECTION OUTPUT ;
    USE SIGNAL ;
    PORT
      LAYER M4 ;
        RECT  0 270.864 0.084 270.888 ;
    END
  END t_out[303]
  PIN t_out[304]
    DIRECTION OUTPUT ;
    USE SIGNAL ;
    PORT
      LAYER M4 ;
        RECT  0 271.056 0.084 271.08 ;
    END
  END t_out[304]
  PIN t_out[305]
    DIRECTION OUTPUT ;
    USE SIGNAL ;
    PORT
      LAYER M4 ;
        RECT  0 271.248 0.084 271.272 ;
    END
  END t_out[305]
  PIN t_out[306]
    DIRECTION OUTPUT ;
    USE SIGNAL ;
    PORT
      LAYER M4 ;
        RECT  0 271.44 0.084 271.464 ;
    END
  END t_out[306]
  PIN t_out[307]
    DIRECTION OUTPUT ;
    USE SIGNAL ;
    PORT
      LAYER M4 ;
        RECT  0 271.632 0.084 271.656 ;
    END
  END t_out[307]
  PIN t_out[308]
    DIRECTION OUTPUT ;
    USE SIGNAL ;
    PORT
      LAYER M4 ;
        RECT  0 271.824 0.084 271.848 ;
    END
  END t_out[308]
  PIN t_out[309]
    DIRECTION OUTPUT ;
    USE SIGNAL ;
    PORT
      LAYER M4 ;
        RECT  0 272.016 0.084 272.04 ;
    END
  END t_out[309]
  PIN t_out[30]
    DIRECTION OUTPUT ;
    USE SIGNAL ;
    PORT
      LAYER M4 ;
        RECT  0 217.824 0.084 217.848 ;
    END
  END t_out[30]
  PIN t_out[310]
    DIRECTION OUTPUT ;
    USE SIGNAL ;
    PORT
      LAYER M4 ;
        RECT  0 272.208 0.084 272.232 ;
    END
  END t_out[310]
  PIN t_out[311]
    DIRECTION OUTPUT ;
    USE SIGNAL ;
    PORT
      LAYER M4 ;
        RECT  0 272.448 0.084 272.472 ;
    END
  END t_out[311]
  PIN t_out[312]
    DIRECTION OUTPUT ;
    USE SIGNAL ;
    PORT
      LAYER M4 ;
        RECT  0 272.64 0.084 272.664 ;
    END
  END t_out[312]
  PIN t_out[313]
    DIRECTION OUTPUT ;
    USE SIGNAL ;
    PORT
      LAYER M4 ;
        RECT  0 272.832 0.084 272.856 ;
    END
  END t_out[313]
  PIN t_out[314]
    DIRECTION OUTPUT ;
    USE SIGNAL ;
    PORT
      LAYER M4 ;
        RECT  0 273.024 0.084 273.048 ;
    END
  END t_out[314]
  PIN t_out[315]
    DIRECTION OUTPUT ;
    USE SIGNAL ;
    PORT
      LAYER M4 ;
        RECT  0 273.216 0.084 273.24 ;
    END
  END t_out[315]
  PIN t_out[316]
    DIRECTION OUTPUT ;
    USE SIGNAL ;
    PORT
      LAYER M4 ;
        RECT  0 273.408 0.084 273.432 ;
    END
  END t_out[316]
  PIN t_out[317]
    DIRECTION OUTPUT ;
    USE SIGNAL ;
    PORT
      LAYER M4 ;
        RECT  0 273.6 0.084 273.624 ;
    END
  END t_out[317]
  PIN t_out[318]
    DIRECTION OUTPUT ;
    USE SIGNAL ;
    PORT
      LAYER M4 ;
        RECT  0 273.792 0.084 273.816 ;
    END
  END t_out[318]
  PIN t_out[319]
    DIRECTION OUTPUT ;
    USE SIGNAL ;
    PORT
      LAYER M4 ;
        RECT  0 273.984 0.084 274.008 ;
    END
  END t_out[319]
  PIN t_out[31]
    DIRECTION OUTPUT ;
    USE SIGNAL ;
    PORT
      LAYER M4 ;
        RECT  0 218.016 0.084 218.04 ;
    END
  END t_out[31]
  PIN t_out[320]
    DIRECTION OUTPUT ;
    USE SIGNAL ;
    PORT
      LAYER M4 ;
        RECT  0 274.176 0.084 274.2 ;
    END
  END t_out[320]
  PIN t_out[321]
    DIRECTION OUTPUT ;
    USE SIGNAL ;
    PORT
      LAYER M4 ;
        RECT  0 274.368 0.084 274.392 ;
    END
  END t_out[321]
  PIN t_out[322]
    DIRECTION OUTPUT ;
    USE SIGNAL ;
    PORT
      LAYER M4 ;
        RECT  0 274.56 0.084 274.584 ;
    END
  END t_out[322]
  PIN t_out[323]
    DIRECTION OUTPUT ;
    USE SIGNAL ;
    PORT
      LAYER M4 ;
        RECT  0 274.752 0.084 274.776 ;
    END
  END t_out[323]
  PIN t_out[324]
    DIRECTION OUTPUT ;
    USE SIGNAL ;
    PORT
      LAYER M4 ;
        RECT  0 274.944 0.084 274.968 ;
    END
  END t_out[324]
  PIN t_out[325]
    DIRECTION OUTPUT ;
    USE SIGNAL ;
    PORT
      LAYER M4 ;
        RECT  0 275.136 0.084 275.16 ;
    END
  END t_out[325]
  PIN t_out[326]
    DIRECTION OUTPUT ;
    USE SIGNAL ;
    PORT
      LAYER M4 ;
        RECT  0 275.328 0.084 275.352 ;
    END
  END t_out[326]
  PIN t_out[327]
    DIRECTION OUTPUT ;
    USE SIGNAL ;
    PORT
      LAYER M4 ;
        RECT  0 275.52 0.084 275.544 ;
    END
  END t_out[327]
  PIN t_out[328]
    DIRECTION OUTPUT ;
    USE SIGNAL ;
    PORT
      LAYER M4 ;
        RECT  0 275.712 0.084 275.736 ;
    END
  END t_out[328]
  PIN t_out[329]
    DIRECTION OUTPUT ;
    USE SIGNAL ;
    PORT
      LAYER M4 ;
        RECT  0 275.904 0.084 275.928 ;
    END
  END t_out[329]
  PIN t_out[32]
    DIRECTION OUTPUT ;
    USE SIGNAL ;
    PORT
      LAYER M4 ;
        RECT  0 218.208 0.084 218.232 ;
    END
  END t_out[32]
  PIN t_out[330]
    DIRECTION OUTPUT ;
    USE SIGNAL ;
    PORT
      LAYER M4 ;
        RECT  0 276.096 0.084 276.12 ;
    END
  END t_out[330]
  PIN t_out[331]
    DIRECTION OUTPUT ;
    USE SIGNAL ;
    PORT
      LAYER M4 ;
        RECT  0 276.288 0.084 276.312 ;
    END
  END t_out[331]
  PIN t_out[332]
    DIRECTION OUTPUT ;
    USE SIGNAL ;
    PORT
      LAYER M4 ;
        RECT  0 276.528 0.084 276.552 ;
    END
  END t_out[332]
  PIN t_out[333]
    DIRECTION OUTPUT ;
    USE SIGNAL ;
    PORT
      LAYER M4 ;
        RECT  0 276.72 0.084 276.744 ;
    END
  END t_out[333]
  PIN t_out[334]
    DIRECTION OUTPUT ;
    USE SIGNAL ;
    PORT
      LAYER M4 ;
        RECT  0 276.912 0.084 276.936 ;
    END
  END t_out[334]
  PIN t_out[335]
    DIRECTION OUTPUT ;
    USE SIGNAL ;
    PORT
      LAYER M4 ;
        RECT  0 277.104 0.084 277.128 ;
    END
  END t_out[335]
  PIN t_out[336]
    DIRECTION OUTPUT ;
    USE SIGNAL ;
    PORT
      LAYER M4 ;
        RECT  0 277.296 0.084 277.32 ;
    END
  END t_out[336]
  PIN t_out[337]
    DIRECTION OUTPUT ;
    USE SIGNAL ;
    PORT
      LAYER M4 ;
        RECT  0 277.488 0.084 277.512 ;
    END
  END t_out[337]
  PIN t_out[338]
    DIRECTION OUTPUT ;
    USE SIGNAL ;
    PORT
      LAYER M4 ;
        RECT  0 277.68 0.084 277.704 ;
    END
  END t_out[338]
  PIN t_out[339]
    DIRECTION OUTPUT ;
    USE SIGNAL ;
    PORT
      LAYER M4 ;
        RECT  0 277.872 0.084 277.896 ;
    END
  END t_out[339]
  PIN t_out[33]
    DIRECTION OUTPUT ;
    USE SIGNAL ;
    PORT
      LAYER M4 ;
        RECT  0 218.4 0.084 218.424 ;
    END
  END t_out[33]
  PIN t_out[340]
    DIRECTION OUTPUT ;
    USE SIGNAL ;
    PORT
      LAYER M4 ;
        RECT  0 278.064 0.084 278.088 ;
    END
  END t_out[340]
  PIN t_out[341]
    DIRECTION OUTPUT ;
    USE SIGNAL ;
    PORT
      LAYER M4 ;
        RECT  0 278.256 0.084 278.28 ;
    END
  END t_out[341]
  PIN t_out[342]
    DIRECTION OUTPUT ;
    USE SIGNAL ;
    PORT
      LAYER M4 ;
        RECT  0 278.448 0.084 278.472 ;
    END
  END t_out[342]
  PIN t_out[343]
    DIRECTION OUTPUT ;
    USE SIGNAL ;
    PORT
      LAYER M4 ;
        RECT  0 278.64 0.084 278.664 ;
    END
  END t_out[343]
  PIN t_out[344]
    DIRECTION OUTPUT ;
    USE SIGNAL ;
    PORT
      LAYER M4 ;
        RECT  0 278.832 0.084 278.856 ;
    END
  END t_out[344]
  PIN t_out[345]
    DIRECTION OUTPUT ;
    USE SIGNAL ;
    PORT
      LAYER M4 ;
        RECT  0 279.024 0.084 279.048 ;
    END
  END t_out[345]
  PIN t_out[346]
    DIRECTION OUTPUT ;
    USE SIGNAL ;
    PORT
      LAYER M4 ;
        RECT  0 279.216 0.084 279.24 ;
    END
  END t_out[346]
  PIN t_out[347]
    DIRECTION OUTPUT ;
    USE SIGNAL ;
    PORT
      LAYER M4 ;
        RECT  0 279.408 0.084 279.432 ;
    END
  END t_out[347]
  PIN t_out[348]
    DIRECTION OUTPUT ;
    USE SIGNAL ;
    PORT
      LAYER M4 ;
        RECT  0 279.6 0.084 279.624 ;
    END
  END t_out[348]
  PIN t_out[349]
    DIRECTION OUTPUT ;
    USE SIGNAL ;
    PORT
      LAYER M4 ;
        RECT  0 279.792 0.084 279.816 ;
    END
  END t_out[349]
  PIN t_out[34]
    DIRECTION OUTPUT ;
    USE SIGNAL ;
    PORT
      LAYER M4 ;
        RECT  0 218.592 0.084 218.616 ;
    END
  END t_out[34]
  PIN t_out[350]
    DIRECTION OUTPUT ;
    USE SIGNAL ;
    PORT
      LAYER M4 ;
        RECT  0 279.984 0.084 280.008 ;
    END
  END t_out[350]
  PIN t_out[351]
    DIRECTION OUTPUT ;
    USE SIGNAL ;
    PORT
      LAYER M4 ;
        RECT  0 280.176 0.084 280.2 ;
    END
  END t_out[351]
  PIN t_out[352]
    DIRECTION OUTPUT ;
    USE SIGNAL ;
    PORT
      LAYER M4 ;
        RECT  0 280.368 0.084 280.392 ;
    END
  END t_out[352]
  PIN t_out[353]
    DIRECTION OUTPUT ;
    USE SIGNAL ;
    PORT
      LAYER M4 ;
        RECT  0 280.608 0.084 280.632 ;
    END
  END t_out[353]
  PIN t_out[354]
    DIRECTION OUTPUT ;
    USE SIGNAL ;
    PORT
      LAYER M4 ;
        RECT  0 280.8 0.084 280.824 ;
    END
  END t_out[354]
  PIN t_out[355]
    DIRECTION OUTPUT ;
    USE SIGNAL ;
    PORT
      LAYER M4 ;
        RECT  0 280.992 0.084 281.016 ;
    END
  END t_out[355]
  PIN t_out[356]
    DIRECTION OUTPUT ;
    USE SIGNAL ;
    PORT
      LAYER M4 ;
        RECT  0 281.184 0.084 281.208 ;
    END
  END t_out[356]
  PIN t_out[357]
    DIRECTION OUTPUT ;
    USE SIGNAL ;
    PORT
      LAYER M4 ;
        RECT  0 281.376 0.084 281.4 ;
    END
  END t_out[357]
  PIN t_out[358]
    DIRECTION OUTPUT ;
    USE SIGNAL ;
    PORT
      LAYER M4 ;
        RECT  0 281.568 0.084 281.592 ;
    END
  END t_out[358]
  PIN t_out[359]
    DIRECTION OUTPUT ;
    USE SIGNAL ;
    PORT
      LAYER M4 ;
        RECT  0 281.76 0.084 281.784 ;
    END
  END t_out[359]
  PIN t_out[35]
    DIRECTION OUTPUT ;
    USE SIGNAL ;
    PORT
      LAYER M4 ;
        RECT  0 218.784 0.084 218.808 ;
    END
  END t_out[35]
  PIN t_out[360]
    DIRECTION OUTPUT ;
    USE SIGNAL ;
    PORT
      LAYER M4 ;
        RECT  0 281.952 0.084 281.976 ;
    END
  END t_out[360]
  PIN t_out[361]
    DIRECTION OUTPUT ;
    USE SIGNAL ;
    PORT
      LAYER M4 ;
        RECT  0 282.144 0.084 282.168 ;
    END
  END t_out[361]
  PIN t_out[362]
    DIRECTION OUTPUT ;
    USE SIGNAL ;
    PORT
      LAYER M4 ;
        RECT  0 282.336 0.084 282.36 ;
    END
  END t_out[362]
  PIN t_out[363]
    DIRECTION OUTPUT ;
    USE SIGNAL ;
    PORT
      LAYER M4 ;
        RECT  0 282.528 0.084 282.552 ;
    END
  END t_out[363]
  PIN t_out[364]
    DIRECTION OUTPUT ;
    USE SIGNAL ;
    PORT
      LAYER M4 ;
        RECT  0 282.72 0.084 282.744 ;
    END
  END t_out[364]
  PIN t_out[365]
    DIRECTION OUTPUT ;
    USE SIGNAL ;
    PORT
      LAYER M4 ;
        RECT  0 282.912 0.084 282.936 ;
    END
  END t_out[365]
  PIN t_out[366]
    DIRECTION OUTPUT ;
    USE SIGNAL ;
    PORT
      LAYER M4 ;
        RECT  0 283.104 0.084 283.128 ;
    END
  END t_out[366]
  PIN t_out[367]
    DIRECTION OUTPUT ;
    USE SIGNAL ;
    PORT
      LAYER M4 ;
        RECT  0 283.296 0.084 283.32 ;
    END
  END t_out[367]
  PIN t_out[368]
    DIRECTION OUTPUT ;
    USE SIGNAL ;
    PORT
      LAYER M4 ;
        RECT  0 283.488 0.084 283.512 ;
    END
  END t_out[368]
  PIN t_out[369]
    DIRECTION OUTPUT ;
    USE SIGNAL ;
    PORT
      LAYER M4 ;
        RECT  0 283.68 0.084 283.704 ;
    END
  END t_out[369]
  PIN t_out[36]
    DIRECTION OUTPUT ;
    USE SIGNAL ;
    PORT
      LAYER M4 ;
        RECT  0 218.976 0.084 219 ;
    END
  END t_out[36]
  PIN t_out[370]
    DIRECTION OUTPUT ;
    USE SIGNAL ;
    PORT
      LAYER M4 ;
        RECT  0 283.872 0.084 283.896 ;
    END
  END t_out[370]
  PIN t_out[371]
    DIRECTION OUTPUT ;
    USE SIGNAL ;
    PORT
      LAYER M4 ;
        RECT  0 284.064 0.084 284.088 ;
    END
  END t_out[371]
  PIN t_out[372]
    DIRECTION OUTPUT ;
    USE SIGNAL ;
    PORT
      LAYER M4 ;
        RECT  0 284.256 0.084 284.28 ;
    END
  END t_out[372]
  PIN t_out[373]
    DIRECTION OUTPUT ;
    USE SIGNAL ;
    PORT
      LAYER M4 ;
        RECT  0 284.496 0.084 284.52 ;
    END
  END t_out[373]
  PIN t_out[374]
    DIRECTION OUTPUT ;
    USE SIGNAL ;
    PORT
      LAYER M4 ;
        RECT  0 284.688 0.084 284.712 ;
    END
  END t_out[374]
  PIN t_out[375]
    DIRECTION OUTPUT ;
    USE SIGNAL ;
    PORT
      LAYER M4 ;
        RECT  0 284.88 0.084 284.904 ;
    END
  END t_out[375]
  PIN t_out[376]
    DIRECTION OUTPUT ;
    USE SIGNAL ;
    PORT
      LAYER M4 ;
        RECT  0 285.072 0.084 285.096 ;
    END
  END t_out[376]
  PIN t_out[377]
    DIRECTION OUTPUT ;
    USE SIGNAL ;
    PORT
      LAYER M4 ;
        RECT  0 285.264 0.084 285.288 ;
    END
  END t_out[377]
  PIN t_out[378]
    DIRECTION OUTPUT ;
    USE SIGNAL ;
    PORT
      LAYER M4 ;
        RECT  0 285.456 0.084 285.48 ;
    END
  END t_out[378]
  PIN t_out[379]
    DIRECTION OUTPUT ;
    USE SIGNAL ;
    PORT
      LAYER M4 ;
        RECT  0 285.648 0.084 285.672 ;
    END
  END t_out[379]
  PIN t_out[37]
    DIRECTION OUTPUT ;
    USE SIGNAL ;
    PORT
      LAYER M4 ;
        RECT  0 219.168 0.084 219.192 ;
    END
  END t_out[37]
  PIN t_out[380]
    DIRECTION OUTPUT ;
    USE SIGNAL ;
    PORT
      LAYER M4 ;
        RECT  0 285.84 0.084 285.864 ;
    END
  END t_out[380]
  PIN t_out[381]
    DIRECTION OUTPUT ;
    USE SIGNAL ;
    PORT
      LAYER M4 ;
        RECT  0 286.032 0.084 286.056 ;
    END
  END t_out[381]
  PIN t_out[382]
    DIRECTION OUTPUT ;
    USE SIGNAL ;
    PORT
      LAYER M4 ;
        RECT  0 286.224 0.084 286.248 ;
    END
  END t_out[382]
  PIN t_out[383]
    DIRECTION OUTPUT ;
    USE SIGNAL ;
    PORT
      LAYER M4 ;
        RECT  0 286.416 0.084 286.44 ;
    END
  END t_out[383]
  PIN t_out[384]
    DIRECTION OUTPUT ;
    USE SIGNAL ;
    PORT
      LAYER M4 ;
        RECT  0 286.608 0.084 286.632 ;
    END
  END t_out[384]
  PIN t_out[385]
    DIRECTION OUTPUT ;
    USE SIGNAL ;
    PORT
      LAYER M4 ;
        RECT  0 286.8 0.084 286.824 ;
    END
  END t_out[385]
  PIN t_out[386]
    DIRECTION OUTPUT ;
    USE SIGNAL ;
    PORT
      LAYER M4 ;
        RECT  0 286.992 0.084 287.016 ;
    END
  END t_out[386]
  PIN t_out[387]
    DIRECTION OUTPUT ;
    USE SIGNAL ;
    PORT
      LAYER M4 ;
        RECT  0 287.184 0.084 287.208 ;
    END
  END t_out[387]
  PIN t_out[388]
    DIRECTION OUTPUT ;
    USE SIGNAL ;
    PORT
      LAYER M4 ;
        RECT  0 287.376 0.084 287.4 ;
    END
  END t_out[388]
  PIN t_out[389]
    DIRECTION OUTPUT ;
    USE SIGNAL ;
    PORT
      LAYER M4 ;
        RECT  0 287.568 0.084 287.592 ;
    END
  END t_out[389]
  PIN t_out[38]
    DIRECTION OUTPUT ;
    USE SIGNAL ;
    PORT
      LAYER M4 ;
        RECT  0 219.36 0.084 219.384 ;
    END
  END t_out[38]
  PIN t_out[390]
    DIRECTION OUTPUT ;
    USE SIGNAL ;
    PORT
      LAYER M4 ;
        RECT  0 287.76 0.084 287.784 ;
    END
  END t_out[390]
  PIN t_out[391]
    DIRECTION OUTPUT ;
    USE SIGNAL ;
    PORT
      LAYER M4 ;
        RECT  0 287.952 0.084 287.976 ;
    END
  END t_out[391]
  PIN t_out[392]
    DIRECTION OUTPUT ;
    USE SIGNAL ;
    PORT
      LAYER M4 ;
        RECT  0 288.144 0.084 288.168 ;
    END
  END t_out[392]
  PIN t_out[393]
    DIRECTION OUTPUT ;
    USE SIGNAL ;
    PORT
      LAYER M4 ;
        RECT  0 288.336 0.084 288.36 ;
    END
  END t_out[393]
  PIN t_out[394]
    DIRECTION OUTPUT ;
    USE SIGNAL ;
    PORT
      LAYER M4 ;
        RECT  0 288.576 0.084 288.6 ;
    END
  END t_out[394]
  PIN t_out[395]
    DIRECTION OUTPUT ;
    USE SIGNAL ;
    PORT
      LAYER M4 ;
        RECT  0 288.768 0.084 288.792 ;
    END
  END t_out[395]
  PIN t_out[396]
    DIRECTION OUTPUT ;
    USE SIGNAL ;
    PORT
      LAYER M4 ;
        RECT  0 288.96 0.084 288.984 ;
    END
  END t_out[396]
  PIN t_out[397]
    DIRECTION OUTPUT ;
    USE SIGNAL ;
    PORT
      LAYER M4 ;
        RECT  0 289.152 0.084 289.176 ;
    END
  END t_out[397]
  PIN t_out[398]
    DIRECTION OUTPUT ;
    USE SIGNAL ;
    PORT
      LAYER M4 ;
        RECT  0 289.344 0.084 289.368 ;
    END
  END t_out[398]
  PIN t_out[399]
    DIRECTION OUTPUT ;
    USE SIGNAL ;
    PORT
      LAYER M4 ;
        RECT  0 289.536 0.084 289.56 ;
    END
  END t_out[399]
  PIN t_out[39]
    DIRECTION OUTPUT ;
    USE SIGNAL ;
    PORT
      LAYER M4 ;
        RECT  0 219.552 0.084 219.576 ;
    END
  END t_out[39]
  PIN t_out[3]
    DIRECTION OUTPUT ;
    USE SIGNAL ;
    PORT
      LAYER M4 ;
        RECT  0 212.592 0.084 212.616 ;
    END
  END t_out[3]
  PIN t_out[400]
    DIRECTION OUTPUT ;
    USE SIGNAL ;
    PORT
      LAYER M4 ;
        RECT  0 289.728 0.084 289.752 ;
    END
  END t_out[400]
  PIN t_out[401]
    DIRECTION OUTPUT ;
    USE SIGNAL ;
    PORT
      LAYER M4 ;
        RECT  0 289.92 0.084 289.944 ;
    END
  END t_out[401]
  PIN t_out[402]
    DIRECTION OUTPUT ;
    USE SIGNAL ;
    PORT
      LAYER M4 ;
        RECT  0 290.112 0.084 290.136 ;
    END
  END t_out[402]
  PIN t_out[403]
    DIRECTION OUTPUT ;
    USE SIGNAL ;
    PORT
      LAYER M4 ;
        RECT  0 290.304 0.084 290.328 ;
    END
  END t_out[403]
  PIN t_out[404]
    DIRECTION OUTPUT ;
    USE SIGNAL ;
    PORT
      LAYER M4 ;
        RECT  0 290.496 0.084 290.52 ;
    END
  END t_out[404]
  PIN t_out[405]
    DIRECTION OUTPUT ;
    USE SIGNAL ;
    PORT
      LAYER M4 ;
        RECT  0 290.688 0.084 290.712 ;
    END
  END t_out[405]
  PIN t_out[406]
    DIRECTION OUTPUT ;
    USE SIGNAL ;
    PORT
      LAYER M4 ;
        RECT  0 290.88 0.084 290.904 ;
    END
  END t_out[406]
  PIN t_out[407]
    DIRECTION OUTPUT ;
    USE SIGNAL ;
    PORT
      LAYER M4 ;
        RECT  0 291.072 0.084 291.096 ;
    END
  END t_out[407]
  PIN t_out[408]
    DIRECTION OUTPUT ;
    USE SIGNAL ;
    PORT
      LAYER M4 ;
        RECT  0 291.264 0.084 291.288 ;
    END
  END t_out[408]
  PIN t_out[409]
    DIRECTION OUTPUT ;
    USE SIGNAL ;
    PORT
      LAYER M4 ;
        RECT  0 291.456 0.084 291.48 ;
    END
  END t_out[409]
  PIN t_out[40]
    DIRECTION OUTPUT ;
    USE SIGNAL ;
    PORT
      LAYER M4 ;
        RECT  0 219.744 0.084 219.768 ;
    END
  END t_out[40]
  PIN t_out[410]
    DIRECTION OUTPUT ;
    USE SIGNAL ;
    PORT
      LAYER M4 ;
        RECT  0 291.648 0.084 291.672 ;
    END
  END t_out[410]
  PIN t_out[411]
    DIRECTION OUTPUT ;
    USE SIGNAL ;
    PORT
      LAYER M4 ;
        RECT  0 291.84 0.084 291.864 ;
    END
  END t_out[411]
  PIN t_out[412]
    DIRECTION OUTPUT ;
    USE SIGNAL ;
    PORT
      LAYER M4 ;
        RECT  0 292.032 0.084 292.056 ;
    END
  END t_out[412]
  PIN t_out[413]
    DIRECTION OUTPUT ;
    USE SIGNAL ;
    PORT
      LAYER M4 ;
        RECT  0 292.224 0.084 292.248 ;
    END
  END t_out[413]
  PIN t_out[414]
    DIRECTION OUTPUT ;
    USE SIGNAL ;
    PORT
      LAYER M4 ;
        RECT  0 292.464 0.084 292.488 ;
    END
  END t_out[414]
  PIN t_out[415]
    DIRECTION OUTPUT ;
    USE SIGNAL ;
    PORT
      LAYER M4 ;
        RECT  0 292.656 0.084 292.68 ;
    END
  END t_out[415]
  PIN t_out[416]
    DIRECTION OUTPUT ;
    USE SIGNAL ;
    PORT
      LAYER M4 ;
        RECT  0 292.848 0.084 292.872 ;
    END
  END t_out[416]
  PIN t_out[417]
    DIRECTION OUTPUT ;
    USE SIGNAL ;
    PORT
      LAYER M4 ;
        RECT  0 293.04 0.084 293.064 ;
    END
  END t_out[417]
  PIN t_out[418]
    DIRECTION OUTPUT ;
    USE SIGNAL ;
    PORT
      LAYER M4 ;
        RECT  0 293.232 0.084 293.256 ;
    END
  END t_out[418]
  PIN t_out[419]
    DIRECTION OUTPUT ;
    USE SIGNAL ;
    PORT
      LAYER M4 ;
        RECT  0 293.424 0.084 293.448 ;
    END
  END t_out[419]
  PIN t_out[41]
    DIRECTION OUTPUT ;
    USE SIGNAL ;
    PORT
      LAYER M4 ;
        RECT  0 219.936 0.084 219.96 ;
    END
  END t_out[41]
  PIN t_out[420]
    DIRECTION OUTPUT ;
    USE SIGNAL ;
    PORT
      LAYER M4 ;
        RECT  0 293.616 0.084 293.64 ;
    END
  END t_out[420]
  PIN t_out[421]
    DIRECTION OUTPUT ;
    USE SIGNAL ;
    PORT
      LAYER M4 ;
        RECT  0 293.808 0.084 293.832 ;
    END
  END t_out[421]
  PIN t_out[422]
    DIRECTION OUTPUT ;
    USE SIGNAL ;
    PORT
      LAYER M4 ;
        RECT  0 294 0.084 294.024 ;
    END
  END t_out[422]
  PIN t_out[423]
    DIRECTION OUTPUT ;
    USE SIGNAL ;
    PORT
      LAYER M4 ;
        RECT  0 294.192 0.084 294.216 ;
    END
  END t_out[423]
  PIN t_out[424]
    DIRECTION OUTPUT ;
    USE SIGNAL ;
    PORT
      LAYER M4 ;
        RECT  0 294.384 0.084 294.408 ;
    END
  END t_out[424]
  PIN t_out[425]
    DIRECTION OUTPUT ;
    USE SIGNAL ;
    PORT
      LAYER M4 ;
        RECT  0 294.576 0.084 294.6 ;
    END
  END t_out[425]
  PIN t_out[426]
    DIRECTION OUTPUT ;
    USE SIGNAL ;
    PORT
      LAYER M4 ;
        RECT  0 294.768 0.084 294.792 ;
    END
  END t_out[426]
  PIN t_out[427]
    DIRECTION OUTPUT ;
    USE SIGNAL ;
    PORT
      LAYER M4 ;
        RECT  0 294.96 0.084 294.984 ;
    END
  END t_out[427]
  PIN t_out[428]
    DIRECTION OUTPUT ;
    USE SIGNAL ;
    PORT
      LAYER M4 ;
        RECT  0 295.152 0.084 295.176 ;
    END
  END t_out[428]
  PIN t_out[429]
    DIRECTION OUTPUT ;
    USE SIGNAL ;
    PORT
      LAYER M4 ;
        RECT  0 295.344 0.084 295.368 ;
    END
  END t_out[429]
  PIN t_out[42]
    DIRECTION OUTPUT ;
    USE SIGNAL ;
    PORT
      LAYER M4 ;
        RECT  0 220.128 0.084 220.152 ;
    END
  END t_out[42]
  PIN t_out[430]
    DIRECTION OUTPUT ;
    USE SIGNAL ;
    PORT
      LAYER M4 ;
        RECT  0 295.536 0.084 295.56 ;
    END
  END t_out[430]
  PIN t_out[431]
    DIRECTION OUTPUT ;
    USE SIGNAL ;
    PORT
      LAYER M4 ;
        RECT  0 295.728 0.084 295.752 ;
    END
  END t_out[431]
  PIN t_out[432]
    DIRECTION OUTPUT ;
    USE SIGNAL ;
    PORT
      LAYER M4 ;
        RECT  0 295.92 0.084 295.944 ;
    END
  END t_out[432]
  PIN t_out[433]
    DIRECTION OUTPUT ;
    USE SIGNAL ;
    PORT
      LAYER M4 ;
        RECT  0 296.112 0.084 296.136 ;
    END
  END t_out[433]
  PIN t_out[434]
    DIRECTION OUTPUT ;
    USE SIGNAL ;
    PORT
      LAYER M4 ;
        RECT  0 296.304 0.084 296.328 ;
    END
  END t_out[434]
  PIN t_out[435]
    DIRECTION OUTPUT ;
    USE SIGNAL ;
    PORT
      LAYER M4 ;
        RECT  0 296.544 0.084 296.568 ;
    END
  END t_out[435]
  PIN t_out[436]
    DIRECTION OUTPUT ;
    USE SIGNAL ;
    PORT
      LAYER M4 ;
        RECT  0 296.736 0.084 296.76 ;
    END
  END t_out[436]
  PIN t_out[437]
    DIRECTION OUTPUT ;
    USE SIGNAL ;
    PORT
      LAYER M4 ;
        RECT  0 296.928 0.084 296.952 ;
    END
  END t_out[437]
  PIN t_out[438]
    DIRECTION OUTPUT ;
    USE SIGNAL ;
    PORT
      LAYER M4 ;
        RECT  0 297.12 0.084 297.144 ;
    END
  END t_out[438]
  PIN t_out[439]
    DIRECTION OUTPUT ;
    USE SIGNAL ;
    PORT
      LAYER M4 ;
        RECT  0 297.312 0.084 297.336 ;
    END
  END t_out[439]
  PIN t_out[43]
    DIRECTION OUTPUT ;
    USE SIGNAL ;
    PORT
      LAYER M4 ;
        RECT  0 220.32 0.084 220.344 ;
    END
  END t_out[43]
  PIN t_out[440]
    DIRECTION OUTPUT ;
    USE SIGNAL ;
    PORT
      LAYER M4 ;
        RECT  0 297.504 0.084 297.528 ;
    END
  END t_out[440]
  PIN t_out[441]
    DIRECTION OUTPUT ;
    USE SIGNAL ;
    PORT
      LAYER M4 ;
        RECT  0 297.696 0.084 297.72 ;
    END
  END t_out[441]
  PIN t_out[442]
    DIRECTION OUTPUT ;
    USE SIGNAL ;
    PORT
      LAYER M4 ;
        RECT  0 297.888 0.084 297.912 ;
    END
  END t_out[442]
  PIN t_out[443]
    DIRECTION OUTPUT ;
    USE SIGNAL ;
    PORT
      LAYER M4 ;
        RECT  0 298.08 0.084 298.104 ;
    END
  END t_out[443]
  PIN t_out[444]
    DIRECTION OUTPUT ;
    USE SIGNAL ;
    PORT
      LAYER M4 ;
        RECT  0 298.272 0.084 298.296 ;
    END
  END t_out[444]
  PIN t_out[445]
    DIRECTION OUTPUT ;
    USE SIGNAL ;
    PORT
      LAYER M4 ;
        RECT  0 298.464 0.084 298.488 ;
    END
  END t_out[445]
  PIN t_out[446]
    DIRECTION OUTPUT ;
    USE SIGNAL ;
    PORT
      LAYER M4 ;
        RECT  0 298.656 0.084 298.68 ;
    END
  END t_out[446]
  PIN t_out[447]
    DIRECTION OUTPUT ;
    USE SIGNAL ;
    PORT
      LAYER M4 ;
        RECT  0 298.848 0.084 298.872 ;
    END
  END t_out[447]
  PIN t_out[448]
    DIRECTION OUTPUT ;
    USE SIGNAL ;
    PORT
      LAYER M4 ;
        RECT  0 299.04 0.084 299.064 ;
    END
  END t_out[448]
  PIN t_out[449]
    DIRECTION OUTPUT ;
    USE SIGNAL ;
    PORT
      LAYER M4 ;
        RECT  0 299.232 0.084 299.256 ;
    END
  END t_out[449]
  PIN t_out[44]
    DIRECTION OUTPUT ;
    USE SIGNAL ;
    PORT
      LAYER M4 ;
        RECT  0 220.56 0.084 220.584 ;
    END
  END t_out[44]
  PIN t_out[450]
    DIRECTION OUTPUT ;
    USE SIGNAL ;
    PORT
      LAYER M4 ;
        RECT  0 299.424 0.084 299.448 ;
    END
  END t_out[450]
  PIN t_out[451]
    DIRECTION OUTPUT ;
    USE SIGNAL ;
    PORT
      LAYER M4 ;
        RECT  0 299.616 0.084 299.64 ;
    END
  END t_out[451]
  PIN t_out[452]
    DIRECTION OUTPUT ;
    USE SIGNAL ;
    PORT
      LAYER M4 ;
        RECT  0 299.808 0.084 299.832 ;
    END
  END t_out[452]
  PIN t_out[453]
    DIRECTION OUTPUT ;
    USE SIGNAL ;
    PORT
      LAYER M4 ;
        RECT  0 300 0.084 300.024 ;
    END
  END t_out[453]
  PIN t_out[454]
    DIRECTION OUTPUT ;
    USE SIGNAL ;
    PORT
      LAYER M4 ;
        RECT  0 300.192 0.084 300.216 ;
    END
  END t_out[454]
  PIN t_out[455]
    DIRECTION OUTPUT ;
    USE SIGNAL ;
    PORT
      LAYER M4 ;
        RECT  0 300.432 0.084 300.456 ;
    END
  END t_out[455]
  PIN t_out[456]
    DIRECTION OUTPUT ;
    USE SIGNAL ;
    PORT
      LAYER M4 ;
        RECT  0 300.624 0.084 300.648 ;
    END
  END t_out[456]
  PIN t_out[457]
    DIRECTION OUTPUT ;
    USE SIGNAL ;
    PORT
      LAYER M4 ;
        RECT  0 300.816 0.084 300.84 ;
    END
  END t_out[457]
  PIN t_out[458]
    DIRECTION OUTPUT ;
    USE SIGNAL ;
    PORT
      LAYER M4 ;
        RECT  0 301.008 0.084 301.032 ;
    END
  END t_out[458]
  PIN t_out[459]
    DIRECTION OUTPUT ;
    USE SIGNAL ;
    PORT
      LAYER M4 ;
        RECT  0 301.2 0.084 301.224 ;
    END
  END t_out[459]
  PIN t_out[45]
    DIRECTION OUTPUT ;
    USE SIGNAL ;
    PORT
      LAYER M4 ;
        RECT  0 220.752 0.084 220.776 ;
    END
  END t_out[45]
  PIN t_out[460]
    DIRECTION OUTPUT ;
    USE SIGNAL ;
    PORT
      LAYER M4 ;
        RECT  0 301.392 0.084 301.416 ;
    END
  END t_out[460]
  PIN t_out[461]
    DIRECTION OUTPUT ;
    USE SIGNAL ;
    PORT
      LAYER M4 ;
        RECT  0 301.584 0.084 301.608 ;
    END
  END t_out[461]
  PIN t_out[462]
    DIRECTION OUTPUT ;
    USE SIGNAL ;
    PORT
      LAYER M4 ;
        RECT  0 301.776 0.084 301.8 ;
    END
  END t_out[462]
  PIN t_out[463]
    DIRECTION OUTPUT ;
    USE SIGNAL ;
    PORT
      LAYER M4 ;
        RECT  0 301.968 0.084 301.992 ;
    END
  END t_out[463]
  PIN t_out[464]
    DIRECTION OUTPUT ;
    USE SIGNAL ;
    PORT
      LAYER M4 ;
        RECT  0 302.16 0.084 302.184 ;
    END
  END t_out[464]
  PIN t_out[465]
    DIRECTION OUTPUT ;
    USE SIGNAL ;
    PORT
      LAYER M4 ;
        RECT  0 302.352 0.084 302.376 ;
    END
  END t_out[465]
  PIN t_out[466]
    DIRECTION OUTPUT ;
    USE SIGNAL ;
    PORT
      LAYER M4 ;
        RECT  0 302.544 0.084 302.568 ;
    END
  END t_out[466]
  PIN t_out[467]
    DIRECTION OUTPUT ;
    USE SIGNAL ;
    PORT
      LAYER M4 ;
        RECT  0 302.736 0.084 302.76 ;
    END
  END t_out[467]
  PIN t_out[468]
    DIRECTION OUTPUT ;
    USE SIGNAL ;
    PORT
      LAYER M4 ;
        RECT  0 302.928 0.084 302.952 ;
    END
  END t_out[468]
  PIN t_out[469]
    DIRECTION OUTPUT ;
    USE SIGNAL ;
    PORT
      LAYER M4 ;
        RECT  0 303.12 0.084 303.144 ;
    END
  END t_out[469]
  PIN t_out[46]
    DIRECTION OUTPUT ;
    USE SIGNAL ;
    PORT
      LAYER M4 ;
        RECT  0 220.944 0.084 220.968 ;
    END
  END t_out[46]
  PIN t_out[470]
    DIRECTION OUTPUT ;
    USE SIGNAL ;
    PORT
      LAYER M4 ;
        RECT  0 303.312 0.084 303.336 ;
    END
  END t_out[470]
  PIN t_out[471]
    DIRECTION OUTPUT ;
    USE SIGNAL ;
    PORT
      LAYER M4 ;
        RECT  0 303.504 0.084 303.528 ;
    END
  END t_out[471]
  PIN t_out[472]
    DIRECTION OUTPUT ;
    USE SIGNAL ;
    PORT
      LAYER M4 ;
        RECT  0 303.696 0.084 303.72 ;
    END
  END t_out[472]
  PIN t_out[473]
    DIRECTION OUTPUT ;
    USE SIGNAL ;
    PORT
      LAYER M4 ;
        RECT  0 303.888 0.084 303.912 ;
    END
  END t_out[473]
  PIN t_out[474]
    DIRECTION OUTPUT ;
    USE SIGNAL ;
    PORT
      LAYER M4 ;
        RECT  0 304.08 0.084 304.104 ;
    END
  END t_out[474]
  PIN t_out[475]
    DIRECTION OUTPUT ;
    USE SIGNAL ;
    PORT
      LAYER M4 ;
        RECT  0 304.272 0.084 304.296 ;
    END
  END t_out[475]
  PIN t_out[476]
    DIRECTION OUTPUT ;
    USE SIGNAL ;
    PORT
      LAYER M4 ;
        RECT  0 304.512 0.084 304.536 ;
    END
  END t_out[476]
  PIN t_out[477]
    DIRECTION OUTPUT ;
    USE SIGNAL ;
    PORT
      LAYER M4 ;
        RECT  0 304.704 0.084 304.728 ;
    END
  END t_out[477]
  PIN t_out[478]
    DIRECTION OUTPUT ;
    USE SIGNAL ;
    PORT
      LAYER M4 ;
        RECT  0 304.896 0.084 304.92 ;
    END
  END t_out[478]
  PIN t_out[479]
    DIRECTION OUTPUT ;
    USE SIGNAL ;
    PORT
      LAYER M4 ;
        RECT  0 305.088 0.084 305.112 ;
    END
  END t_out[479]
  PIN t_out[47]
    DIRECTION OUTPUT ;
    USE SIGNAL ;
    PORT
      LAYER M4 ;
        RECT  0 221.136 0.084 221.16 ;
    END
  END t_out[47]
  PIN t_out[480]
    DIRECTION OUTPUT ;
    USE SIGNAL ;
    PORT
      LAYER M4 ;
        RECT  0 305.28 0.084 305.304 ;
    END
  END t_out[480]
  PIN t_out[481]
    DIRECTION OUTPUT ;
    USE SIGNAL ;
    PORT
      LAYER M4 ;
        RECT  0 305.472 0.084 305.496 ;
    END
  END t_out[481]
  PIN t_out[482]
    DIRECTION OUTPUT ;
    USE SIGNAL ;
    PORT
      LAYER M4 ;
        RECT  0 305.664 0.084 305.688 ;
    END
  END t_out[482]
  PIN t_out[483]
    DIRECTION OUTPUT ;
    USE SIGNAL ;
    PORT
      LAYER M4 ;
        RECT  0 305.856 0.084 305.88 ;
    END
  END t_out[483]
  PIN t_out[484]
    DIRECTION OUTPUT ;
    USE SIGNAL ;
    PORT
      LAYER M4 ;
        RECT  0 306.048 0.084 306.072 ;
    END
  END t_out[484]
  PIN t_out[485]
    DIRECTION OUTPUT ;
    USE SIGNAL ;
    PORT
      LAYER M4 ;
        RECT  0 306.24 0.084 306.264 ;
    END
  END t_out[485]
  PIN t_out[486]
    DIRECTION OUTPUT ;
    USE SIGNAL ;
    PORT
      LAYER M4 ;
        RECT  0 306.432 0.084 306.456 ;
    END
  END t_out[486]
  PIN t_out[487]
    DIRECTION OUTPUT ;
    USE SIGNAL ;
    PORT
      LAYER M4 ;
        RECT  0 306.624 0.084 306.648 ;
    END
  END t_out[487]
  PIN t_out[488]
    DIRECTION OUTPUT ;
    USE SIGNAL ;
    PORT
      LAYER M4 ;
        RECT  0 306.816 0.084 306.84 ;
    END
  END t_out[488]
  PIN t_out[489]
    DIRECTION OUTPUT ;
    USE SIGNAL ;
    PORT
      LAYER M4 ;
        RECT  0 307.008 0.084 307.032 ;
    END
  END t_out[489]
  PIN t_out[48]
    DIRECTION OUTPUT ;
    USE SIGNAL ;
    PORT
      LAYER M4 ;
        RECT  0 221.328 0.084 221.352 ;
    END
  END t_out[48]
  PIN t_out[490]
    DIRECTION OUTPUT ;
    USE SIGNAL ;
    PORT
      LAYER M4 ;
        RECT  0 307.2 0.084 307.224 ;
    END
  END t_out[490]
  PIN t_out[491]
    DIRECTION OUTPUT ;
    USE SIGNAL ;
    PORT
      LAYER M4 ;
        RECT  0 307.392 0.084 307.416 ;
    END
  END t_out[491]
  PIN t_out[492]
    DIRECTION OUTPUT ;
    USE SIGNAL ;
    PORT
      LAYER M4 ;
        RECT  0 307.584 0.084 307.608 ;
    END
  END t_out[492]
  PIN t_out[493]
    DIRECTION OUTPUT ;
    USE SIGNAL ;
    PORT
      LAYER M4 ;
        RECT  0 307.776 0.084 307.8 ;
    END
  END t_out[493]
  PIN t_out[494]
    DIRECTION OUTPUT ;
    USE SIGNAL ;
    PORT
      LAYER M4 ;
        RECT  0 307.968 0.084 307.992 ;
    END
  END t_out[494]
  PIN t_out[495]
    DIRECTION OUTPUT ;
    USE SIGNAL ;
    PORT
      LAYER M4 ;
        RECT  0 308.16 0.084 308.184 ;
    END
  END t_out[495]
  PIN t_out[496]
    DIRECTION OUTPUT ;
    USE SIGNAL ;
    PORT
      LAYER M4 ;
        RECT  0 308.4 0.084 308.424 ;
    END
  END t_out[496]
  PIN t_out[497]
    DIRECTION OUTPUT ;
    USE SIGNAL ;
    PORT
      LAYER M4 ;
        RECT  0 308.592 0.084 308.616 ;
    END
  END t_out[497]
  PIN t_out[498]
    DIRECTION OUTPUT ;
    USE SIGNAL ;
    PORT
      LAYER M4 ;
        RECT  0 308.784 0.084 308.808 ;
    END
  END t_out[498]
  PIN t_out[499]
    DIRECTION OUTPUT ;
    USE SIGNAL ;
    PORT
      LAYER M4 ;
        RECT  0 308.976 0.084 309 ;
    END
  END t_out[499]
  PIN t_out[49]
    DIRECTION OUTPUT ;
    USE SIGNAL ;
    PORT
      LAYER M4 ;
        RECT  0 221.52 0.084 221.544 ;
    END
  END t_out[49]
  PIN t_out[4]
    DIRECTION OUTPUT ;
    USE SIGNAL ;
    PORT
      LAYER M4 ;
        RECT  0 212.784 0.084 212.808 ;
    END
  END t_out[4]
  PIN t_out[500]
    DIRECTION OUTPUT ;
    USE SIGNAL ;
    PORT
      LAYER M4 ;
        RECT  0 309.168 0.084 309.192 ;
    END
  END t_out[500]
  PIN t_out[501]
    DIRECTION OUTPUT ;
    USE SIGNAL ;
    PORT
      LAYER M4 ;
        RECT  0 309.36 0.084 309.384 ;
    END
  END t_out[501]
  PIN t_out[502]
    DIRECTION OUTPUT ;
    USE SIGNAL ;
    PORT
      LAYER M4 ;
        RECT  0 309.552 0.084 309.576 ;
    END
  END t_out[502]
  PIN t_out[503]
    DIRECTION OUTPUT ;
    USE SIGNAL ;
    PORT
      LAYER M4 ;
        RECT  0 309.744 0.084 309.768 ;
    END
  END t_out[503]
  PIN t_out[504]
    DIRECTION OUTPUT ;
    USE SIGNAL ;
    PORT
      LAYER M4 ;
        RECT  0 309.936 0.084 309.96 ;
    END
  END t_out[504]
  PIN t_out[505]
    DIRECTION OUTPUT ;
    USE SIGNAL ;
    PORT
      LAYER M4 ;
        RECT  0 310.128 0.084 310.152 ;
    END
  END t_out[505]
  PIN t_out[506]
    DIRECTION OUTPUT ;
    USE SIGNAL ;
    PORT
      LAYER M4 ;
        RECT  0 310.32 0.084 310.344 ;
    END
  END t_out[506]
  PIN t_out[507]
    DIRECTION OUTPUT ;
    USE SIGNAL ;
    PORT
      LAYER M4 ;
        RECT  0 310.512 0.084 310.536 ;
    END
  END t_out[507]
  PIN t_out[508]
    DIRECTION OUTPUT ;
    USE SIGNAL ;
    PORT
      LAYER M4 ;
        RECT  0 310.704 0.084 310.728 ;
    END
  END t_out[508]
  PIN t_out[509]
    DIRECTION OUTPUT ;
    USE SIGNAL ;
    PORT
      LAYER M4 ;
        RECT  0 310.896 0.084 310.92 ;
    END
  END t_out[509]
  PIN t_out[50]
    DIRECTION OUTPUT ;
    USE SIGNAL ;
    PORT
      LAYER M4 ;
        RECT  0 221.712 0.084 221.736 ;
    END
  END t_out[50]
  PIN t_out[510]
    DIRECTION OUTPUT ;
    USE SIGNAL ;
    PORT
      LAYER M4 ;
        RECT  0 311.088 0.084 311.112 ;
    END
  END t_out[510]
  PIN t_out[511]
    DIRECTION OUTPUT ;
    USE SIGNAL ;
    PORT
      LAYER M4 ;
        RECT  0 311.28 0.084 311.304 ;
    END
  END t_out[511]
  PIN t_out[51]
    DIRECTION OUTPUT ;
    USE SIGNAL ;
    PORT
      LAYER M4 ;
        RECT  0 221.904 0.084 221.928 ;
    END
  END t_out[51]
  PIN t_out[52]
    DIRECTION OUTPUT ;
    USE SIGNAL ;
    PORT
      LAYER M4 ;
        RECT  0 222.096 0.084 222.12 ;
    END
  END t_out[52]
  PIN t_out[53]
    DIRECTION OUTPUT ;
    USE SIGNAL ;
    PORT
      LAYER M4 ;
        RECT  0 222.288 0.084 222.312 ;
    END
  END t_out[53]
  PIN t_out[54]
    DIRECTION OUTPUT ;
    USE SIGNAL ;
    PORT
      LAYER M4 ;
        RECT  0 222.48 0.084 222.504 ;
    END
  END t_out[54]
  PIN t_out[55]
    DIRECTION OUTPUT ;
    USE SIGNAL ;
    PORT
      LAYER M4 ;
        RECT  0 222.672 0.084 222.696 ;
    END
  END t_out[55]
  PIN t_out[56]
    DIRECTION OUTPUT ;
    USE SIGNAL ;
    PORT
      LAYER M4 ;
        RECT  0 222.864 0.084 222.888 ;
    END
  END t_out[56]
  PIN t_out[57]
    DIRECTION OUTPUT ;
    USE SIGNAL ;
    PORT
      LAYER M4 ;
        RECT  0 223.056 0.084 223.08 ;
    END
  END t_out[57]
  PIN t_out[58]
    DIRECTION OUTPUT ;
    USE SIGNAL ;
    PORT
      LAYER M4 ;
        RECT  0 223.248 0.084 223.272 ;
    END
  END t_out[58]
  PIN t_out[59]
    DIRECTION OUTPUT ;
    USE SIGNAL ;
    PORT
      LAYER M4 ;
        RECT  0 223.44 0.084 223.464 ;
    END
  END t_out[59]
  PIN t_out[5]
    DIRECTION OUTPUT ;
    USE SIGNAL ;
    PORT
      LAYER M4 ;
        RECT  0 212.976 0.084 213 ;
    END
  END t_out[5]
  PIN t_out[60]
    DIRECTION OUTPUT ;
    USE SIGNAL ;
    PORT
      LAYER M4 ;
        RECT  0 223.632 0.084 223.656 ;
    END
  END t_out[60]
  PIN t_out[61]
    DIRECTION OUTPUT ;
    USE SIGNAL ;
    PORT
      LAYER M4 ;
        RECT  0 223.824 0.084 223.848 ;
    END
  END t_out[61]
  PIN t_out[62]
    DIRECTION OUTPUT ;
    USE SIGNAL ;
    PORT
      LAYER M4 ;
        RECT  0 224.016 0.084 224.04 ;
    END
  END t_out[62]
  PIN t_out[63]
    DIRECTION OUTPUT ;
    USE SIGNAL ;
    PORT
      LAYER M4 ;
        RECT  0 224.208 0.084 224.232 ;
    END
  END t_out[63]
  PIN t_out[64]
    DIRECTION OUTPUT ;
    USE SIGNAL ;
    PORT
      LAYER M4 ;
        RECT  0 224.4 0.084 224.424 ;
    END
  END t_out[64]
  PIN t_out[65]
    DIRECTION OUTPUT ;
    USE SIGNAL ;
    PORT
      LAYER M4 ;
        RECT  0 224.64 0.084 224.664 ;
    END
  END t_out[65]
  PIN t_out[66]
    DIRECTION OUTPUT ;
    USE SIGNAL ;
    PORT
      LAYER M4 ;
        RECT  0 224.832 0.084 224.856 ;
    END
  END t_out[66]
  PIN t_out[67]
    DIRECTION OUTPUT ;
    USE SIGNAL ;
    PORT
      LAYER M4 ;
        RECT  0 225.024 0.084 225.048 ;
    END
  END t_out[67]
  PIN t_out[68]
    DIRECTION OUTPUT ;
    USE SIGNAL ;
    PORT
      LAYER M4 ;
        RECT  0 225.216 0.084 225.24 ;
    END
  END t_out[68]
  PIN t_out[69]
    DIRECTION OUTPUT ;
    USE SIGNAL ;
    PORT
      LAYER M4 ;
        RECT  0 225.408 0.084 225.432 ;
    END
  END t_out[69]
  PIN t_out[6]
    DIRECTION OUTPUT ;
    USE SIGNAL ;
    PORT
      LAYER M4 ;
        RECT  0 213.168 0.084 213.192 ;
    END
  END t_out[6]
  PIN t_out[70]
    DIRECTION OUTPUT ;
    USE SIGNAL ;
    PORT
      LAYER M4 ;
        RECT  0 225.6 0.084 225.624 ;
    END
  END t_out[70]
  PIN t_out[71]
    DIRECTION OUTPUT ;
    USE SIGNAL ;
    PORT
      LAYER M4 ;
        RECT  0 225.792 0.084 225.816 ;
    END
  END t_out[71]
  PIN t_out[72]
    DIRECTION OUTPUT ;
    USE SIGNAL ;
    PORT
      LAYER M4 ;
        RECT  0 225.984 0.084 226.008 ;
    END
  END t_out[72]
  PIN t_out[73]
    DIRECTION OUTPUT ;
    USE SIGNAL ;
    PORT
      LAYER M4 ;
        RECT  0 226.176 0.084 226.2 ;
    END
  END t_out[73]
  PIN t_out[74]
    DIRECTION OUTPUT ;
    USE SIGNAL ;
    PORT
      LAYER M4 ;
        RECT  0 226.368 0.084 226.392 ;
    END
  END t_out[74]
  PIN t_out[75]
    DIRECTION OUTPUT ;
    USE SIGNAL ;
    PORT
      LAYER M4 ;
        RECT  0 226.56 0.084 226.584 ;
    END
  END t_out[75]
  PIN t_out[76]
    DIRECTION OUTPUT ;
    USE SIGNAL ;
    PORT
      LAYER M4 ;
        RECT  0 226.752 0.084 226.776 ;
    END
  END t_out[76]
  PIN t_out[77]
    DIRECTION OUTPUT ;
    USE SIGNAL ;
    PORT
      LAYER M4 ;
        RECT  0 226.944 0.084 226.968 ;
    END
  END t_out[77]
  PIN t_out[78]
    DIRECTION OUTPUT ;
    USE SIGNAL ;
    PORT
      LAYER M4 ;
        RECT  0 227.136 0.084 227.16 ;
    END
  END t_out[78]
  PIN t_out[79]
    DIRECTION OUTPUT ;
    USE SIGNAL ;
    PORT
      LAYER M4 ;
        RECT  0 227.328 0.084 227.352 ;
    END
  END t_out[79]
  PIN t_out[7]
    DIRECTION OUTPUT ;
    USE SIGNAL ;
    PORT
      LAYER M4 ;
        RECT  0 213.36 0.084 213.384 ;
    END
  END t_out[7]
  PIN t_out[80]
    DIRECTION OUTPUT ;
    USE SIGNAL ;
    PORT
      LAYER M4 ;
        RECT  0 227.52 0.084 227.544 ;
    END
  END t_out[80]
  PIN t_out[81]
    DIRECTION OUTPUT ;
    USE SIGNAL ;
    PORT
      LAYER M4 ;
        RECT  0 227.712 0.084 227.736 ;
    END
  END t_out[81]
  PIN t_out[82]
    DIRECTION OUTPUT ;
    USE SIGNAL ;
    PORT
      LAYER M4 ;
        RECT  0 227.904 0.084 227.928 ;
    END
  END t_out[82]
  PIN t_out[83]
    DIRECTION OUTPUT ;
    USE SIGNAL ;
    PORT
      LAYER M4 ;
        RECT  0 228.096 0.084 228.12 ;
    END
  END t_out[83]
  PIN t_out[84]
    DIRECTION OUTPUT ;
    USE SIGNAL ;
    PORT
      LAYER M4 ;
        RECT  0 228.288 0.084 228.312 ;
    END
  END t_out[84]
  PIN t_out[85]
    DIRECTION OUTPUT ;
    USE SIGNAL ;
    PORT
      LAYER M4 ;
        RECT  0 228.528 0.084 228.552 ;
    END
  END t_out[85]
  PIN t_out[86]
    DIRECTION OUTPUT ;
    USE SIGNAL ;
    PORT
      LAYER M4 ;
        RECT  0 228.72 0.084 228.744 ;
    END
  END t_out[86]
  PIN t_out[87]
    DIRECTION OUTPUT ;
    USE SIGNAL ;
    PORT
      LAYER M4 ;
        RECT  0 228.912 0.084 228.936 ;
    END
  END t_out[87]
  PIN t_out[88]
    DIRECTION OUTPUT ;
    USE SIGNAL ;
    PORT
      LAYER M4 ;
        RECT  0 229.104 0.084 229.128 ;
    END
  END t_out[88]
  PIN t_out[89]
    DIRECTION OUTPUT ;
    USE SIGNAL ;
    PORT
      LAYER M4 ;
        RECT  0 229.296 0.084 229.32 ;
    END
  END t_out[89]
  PIN t_out[8]
    DIRECTION OUTPUT ;
    USE SIGNAL ;
    PORT
      LAYER M4 ;
        RECT  0 213.552 0.084 213.576 ;
    END
  END t_out[8]
  PIN t_out[90]
    DIRECTION OUTPUT ;
    USE SIGNAL ;
    PORT
      LAYER M4 ;
        RECT  0 229.488 0.084 229.512 ;
    END
  END t_out[90]
  PIN t_out[91]
    DIRECTION OUTPUT ;
    USE SIGNAL ;
    PORT
      LAYER M4 ;
        RECT  0 229.68 0.084 229.704 ;
    END
  END t_out[91]
  PIN t_out[92]
    DIRECTION OUTPUT ;
    USE SIGNAL ;
    PORT
      LAYER M4 ;
        RECT  0 229.872 0.084 229.896 ;
    END
  END t_out[92]
  PIN t_out[93]
    DIRECTION OUTPUT ;
    USE SIGNAL ;
    PORT
      LAYER M4 ;
        RECT  0 230.064 0.084 230.088 ;
    END
  END t_out[93]
  PIN t_out[94]
    DIRECTION OUTPUT ;
    USE SIGNAL ;
    PORT
      LAYER M4 ;
        RECT  0 230.256 0.084 230.28 ;
    END
  END t_out[94]
  PIN t_out[95]
    DIRECTION OUTPUT ;
    USE SIGNAL ;
    PORT
      LAYER M4 ;
        RECT  0 230.448 0.084 230.472 ;
    END
  END t_out[95]
  PIN t_out[96]
    DIRECTION OUTPUT ;
    USE SIGNAL ;
    PORT
      LAYER M4 ;
        RECT  0 230.64 0.084 230.664 ;
    END
  END t_out[96]
  PIN t_out[97]
    DIRECTION OUTPUT ;
    USE SIGNAL ;
    PORT
      LAYER M4 ;
        RECT  0 230.832 0.084 230.856 ;
    END
  END t_out[97]
  PIN t_out[98]
    DIRECTION OUTPUT ;
    USE SIGNAL ;
    PORT
      LAYER M4 ;
        RECT  0 231.024 0.084 231.048 ;
    END
  END t_out[98]
  PIN t_out[99]
    DIRECTION OUTPUT ;
    USE SIGNAL ;
    PORT
      LAYER M4 ;
        RECT  0 231.216 0.084 231.24 ;
    END
  END t_out[99]
  PIN t_out[9]
    DIRECTION OUTPUT ;
    USE SIGNAL ;
    PORT
      LAYER M4 ;
        RECT  0 213.744 0.084 213.768 ;
    END
  END t_out[9]
  PIN t_vd
    DIRECTION INPUT ;
    USE SIGNAL ;
    PORT
      LAYER M4 ;
        RECT  47.436 211.392 47.52 211.416 ;
    END
  END t_vd
  PIN t_vout
    DIRECTION OUTPUT ;
    USE SIGNAL ;
    PORT
      LAYER M4 ;
        RECT  0 211.392 0.084 211.416 ;
    END
  END t_vout
  PIN va
    DIRECTION INPUT ;
    USE SIGNAL ;
    PORT
      LAYER M4 ;
        RECT  0 195.216 0.084 195.24 ;
    END
  END va
  PIN vy
    DIRECTION OUTPUT ;
    USE SIGNAL ;
    PORT
      LAYER M4 ;
        RECT  0 311.904 0.084 311.928 ;
    END
  END vy
  PIN y[0]
    DIRECTION OUTPUT ;
    USE SIGNAL ;
    PORT
      LAYER M4 ;
        RECT  0 23.184 0.084 23.208 ;
    END
  END y[0]
  PIN y[100]
    DIRECTION OUTPUT ;
    USE SIGNAL ;
    PORT
      LAYER M4 ;
        RECT  0 79.248 0.084 79.272 ;
    END
  END y[100]
  PIN y[101]
    DIRECTION OUTPUT ;
    USE SIGNAL ;
    PORT
      LAYER M4 ;
        RECT  0 79.44 0.084 79.464 ;
    END
  END y[101]
  PIN y[102]
    DIRECTION OUTPUT ;
    USE SIGNAL ;
    PORT
      LAYER M4 ;
        RECT  0 79.632 0.084 79.656 ;
    END
  END y[102]
  PIN y[103]
    DIRECTION OUTPUT ;
    USE SIGNAL ;
    PORT
      LAYER M4 ;
        RECT  0 79.824 0.084 79.848 ;
    END
  END y[103]
  PIN y[104]
    DIRECTION OUTPUT ;
    USE SIGNAL ;
    PORT
      LAYER M4 ;
        RECT  0 80.016 0.084 80.04 ;
    END
  END y[104]
  PIN y[105]
    DIRECTION OUTPUT ;
    USE SIGNAL ;
    PORT
      LAYER M4 ;
        RECT  0 80.208 0.084 80.232 ;
    END
  END y[105]
  PIN y[106]
    DIRECTION OUTPUT ;
    USE SIGNAL ;
    PORT
      LAYER M4 ;
        RECT  0 80.4 0.084 80.424 ;
    END
  END y[106]
  PIN y[107]
    DIRECTION OUTPUT ;
    USE SIGNAL ;
    PORT
      LAYER M4 ;
        RECT  0 80.592 0.084 80.616 ;
    END
  END y[107]
  PIN y[108]
    DIRECTION OUTPUT ;
    USE SIGNAL ;
    PORT
      LAYER M4 ;
        RECT  0 80.784 0.084 80.808 ;
    END
  END y[108]
  PIN y[109]
    DIRECTION OUTPUT ;
    USE SIGNAL ;
    PORT
      LAYER M4 ;
        RECT  0 80.976 0.084 81 ;
    END
  END y[109]
  PIN y[10]
    DIRECTION OUTPUT ;
    USE SIGNAL ;
    PORT
      LAYER M4 ;
        RECT  0 25.104 0.084 25.128 ;
    END
  END y[10]
  PIN y[110]
    DIRECTION OUTPUT ;
    USE SIGNAL ;
    PORT
      LAYER M4 ;
        RECT  0 81.168 0.084 81.192 ;
    END
  END y[110]
  PIN y[111]
    DIRECTION OUTPUT ;
    USE SIGNAL ;
    PORT
      LAYER M4 ;
        RECT  0 81.36 0.084 81.384 ;
    END
  END y[111]
  PIN y[112]
    DIRECTION OUTPUT ;
    USE SIGNAL ;
    PORT
      LAYER M4 ;
        RECT  0 81.552 0.084 81.576 ;
    END
  END y[112]
  PIN y[113]
    DIRECTION OUTPUT ;
    USE SIGNAL ;
    PORT
      LAYER M4 ;
        RECT  0 81.744 0.084 81.768 ;
    END
  END y[113]
  PIN y[114]
    DIRECTION OUTPUT ;
    USE SIGNAL ;
    PORT
      LAYER M4 ;
        RECT  0 81.936 0.084 81.96 ;
    END
  END y[114]
  PIN y[115]
    DIRECTION OUTPUT ;
    USE SIGNAL ;
    PORT
      LAYER M4 ;
        RECT  0 82.128 0.084 82.152 ;
    END
  END y[115]
  PIN y[116]
    DIRECTION OUTPUT ;
    USE SIGNAL ;
    PORT
      LAYER M4 ;
        RECT  0 82.32 0.084 82.344 ;
    END
  END y[116]
  PIN y[117]
    DIRECTION OUTPUT ;
    USE SIGNAL ;
    PORT
      LAYER M4 ;
        RECT  0 82.512 0.084 82.536 ;
    END
  END y[117]
  PIN y[118]
    DIRECTION OUTPUT ;
    USE SIGNAL ;
    PORT
      LAYER M4 ;
        RECT  0 82.704 0.084 82.728 ;
    END
  END y[118]
  PIN y[119]
    DIRECTION OUTPUT ;
    USE SIGNAL ;
    PORT
      LAYER M4 ;
        RECT  0 82.896 0.084 82.92 ;
    END
  END y[119]
  PIN y[11]
    DIRECTION OUTPUT ;
    USE SIGNAL ;
    PORT
      LAYER M4 ;
        RECT  0 25.296 0.084 25.32 ;
    END
  END y[11]
  PIN y[120]
    DIRECTION OUTPUT ;
    USE SIGNAL ;
    PORT
      LAYER M4 ;
        RECT  0 83.088 0.084 83.112 ;
    END
  END y[120]
  PIN y[121]
    DIRECTION OUTPUT ;
    USE SIGNAL ;
    PORT
      LAYER M4 ;
        RECT  0 83.28 0.084 83.304 ;
    END
  END y[121]
  PIN y[122]
    DIRECTION OUTPUT ;
    USE SIGNAL ;
    PORT
      LAYER M4 ;
        RECT  0 83.472 0.084 83.496 ;
    END
  END y[122]
  PIN y[123]
    DIRECTION OUTPUT ;
    USE SIGNAL ;
    PORT
      LAYER M4 ;
        RECT  0 83.664 0.084 83.688 ;
    END
  END y[123]
  PIN y[124]
    DIRECTION OUTPUT ;
    USE SIGNAL ;
    PORT
      LAYER M4 ;
        RECT  0 83.856 0.084 83.88 ;
    END
  END y[124]
  PIN y[125]
    DIRECTION OUTPUT ;
    USE SIGNAL ;
    PORT
      LAYER M4 ;
        RECT  0 84.048 0.084 84.072 ;
    END
  END y[125]
  PIN y[126]
    DIRECTION OUTPUT ;
    USE SIGNAL ;
    PORT
      LAYER M4 ;
        RECT  0 84.24 0.084 84.264 ;
    END
  END y[126]
  PIN y[127]
    DIRECTION OUTPUT ;
    USE SIGNAL ;
    PORT
      LAYER M4 ;
        RECT  0 84.432 0.084 84.456 ;
    END
  END y[127]
  PIN y[128]
    DIRECTION OUTPUT ;
    USE SIGNAL ;
    PORT
      LAYER M4 ;
        RECT  0 96.912 0.084 96.936 ;
    END
  END y[128]
  PIN y[129]
    DIRECTION OUTPUT ;
    USE SIGNAL ;
    PORT
      LAYER M4 ;
        RECT  0 97.104 0.084 97.128 ;
    END
  END y[129]
  PIN y[12]
    DIRECTION OUTPUT ;
    USE SIGNAL ;
    PORT
      LAYER M4 ;
        RECT  0 25.488 0.084 25.512 ;
    END
  END y[12]
  PIN y[130]
    DIRECTION OUTPUT ;
    USE SIGNAL ;
    PORT
      LAYER M4 ;
        RECT  0 97.296 0.084 97.32 ;
    END
  END y[130]
  PIN y[131]
    DIRECTION OUTPUT ;
    USE SIGNAL ;
    PORT
      LAYER M4 ;
        RECT  0 97.488 0.084 97.512 ;
    END
  END y[131]
  PIN y[132]
    DIRECTION OUTPUT ;
    USE SIGNAL ;
    PORT
      LAYER M4 ;
        RECT  0 97.68 0.084 97.704 ;
    END
  END y[132]
  PIN y[133]
    DIRECTION OUTPUT ;
    USE SIGNAL ;
    PORT
      LAYER M4 ;
        RECT  0 97.872 0.084 97.896 ;
    END
  END y[133]
  PIN y[134]
    DIRECTION OUTPUT ;
    USE SIGNAL ;
    PORT
      LAYER M4 ;
        RECT  0 98.064 0.084 98.088 ;
    END
  END y[134]
  PIN y[135]
    DIRECTION OUTPUT ;
    USE SIGNAL ;
    PORT
      LAYER M4 ;
        RECT  0 98.256 0.084 98.28 ;
    END
  END y[135]
  PIN y[136]
    DIRECTION OUTPUT ;
    USE SIGNAL ;
    PORT
      LAYER M4 ;
        RECT  0 98.448 0.084 98.472 ;
    END
  END y[136]
  PIN y[137]
    DIRECTION OUTPUT ;
    USE SIGNAL ;
    PORT
      LAYER M4 ;
        RECT  0 98.64 0.084 98.664 ;
    END
  END y[137]
  PIN y[138]
    DIRECTION OUTPUT ;
    USE SIGNAL ;
    PORT
      LAYER M4 ;
        RECT  0 98.832 0.084 98.856 ;
    END
  END y[138]
  PIN y[139]
    DIRECTION OUTPUT ;
    USE SIGNAL ;
    PORT
      LAYER M4 ;
        RECT  0 99.024 0.084 99.048 ;
    END
  END y[139]
  PIN y[13]
    DIRECTION OUTPUT ;
    USE SIGNAL ;
    PORT
      LAYER M4 ;
        RECT  0 25.68 0.084 25.704 ;
    END
  END y[13]
  PIN y[140]
    DIRECTION OUTPUT ;
    USE SIGNAL ;
    PORT
      LAYER M4 ;
        RECT  0 99.216 0.084 99.24 ;
    END
  END y[140]
  PIN y[141]
    DIRECTION OUTPUT ;
    USE SIGNAL ;
    PORT
      LAYER M4 ;
        RECT  0 99.408 0.084 99.432 ;
    END
  END y[141]
  PIN y[142]
    DIRECTION OUTPUT ;
    USE SIGNAL ;
    PORT
      LAYER M4 ;
        RECT  0 99.6 0.084 99.624 ;
    END
  END y[142]
  PIN y[143]
    DIRECTION OUTPUT ;
    USE SIGNAL ;
    PORT
      LAYER M4 ;
        RECT  0 99.792 0.084 99.816 ;
    END
  END y[143]
  PIN y[144]
    DIRECTION OUTPUT ;
    USE SIGNAL ;
    PORT
      LAYER M4 ;
        RECT  0 99.984 0.084 100.008 ;
    END
  END y[144]
  PIN y[145]
    DIRECTION OUTPUT ;
    USE SIGNAL ;
    PORT
      LAYER M4 ;
        RECT  0 100.176 0.084 100.2 ;
    END
  END y[145]
  PIN y[146]
    DIRECTION OUTPUT ;
    USE SIGNAL ;
    PORT
      LAYER M4 ;
        RECT  0 100.368 0.084 100.392 ;
    END
  END y[146]
  PIN y[147]
    DIRECTION OUTPUT ;
    USE SIGNAL ;
    PORT
      LAYER M4 ;
        RECT  0 100.56 0.084 100.584 ;
    END
  END y[147]
  PIN y[148]
    DIRECTION OUTPUT ;
    USE SIGNAL ;
    PORT
      LAYER M4 ;
        RECT  0 100.752 0.084 100.776 ;
    END
  END y[148]
  PIN y[149]
    DIRECTION OUTPUT ;
    USE SIGNAL ;
    PORT
      LAYER M4 ;
        RECT  0 100.944 0.084 100.968 ;
    END
  END y[149]
  PIN y[14]
    DIRECTION OUTPUT ;
    USE SIGNAL ;
    PORT
      LAYER M4 ;
        RECT  0 25.872 0.084 25.896 ;
    END
  END y[14]
  PIN y[150]
    DIRECTION OUTPUT ;
    USE SIGNAL ;
    PORT
      LAYER M4 ;
        RECT  0 101.136 0.084 101.16 ;
    END
  END y[150]
  PIN y[151]
    DIRECTION OUTPUT ;
    USE SIGNAL ;
    PORT
      LAYER M4 ;
        RECT  0 101.328 0.084 101.352 ;
    END
  END y[151]
  PIN y[152]
    DIRECTION OUTPUT ;
    USE SIGNAL ;
    PORT
      LAYER M4 ;
        RECT  0 101.52 0.084 101.544 ;
    END
  END y[152]
  PIN y[153]
    DIRECTION OUTPUT ;
    USE SIGNAL ;
    PORT
      LAYER M4 ;
        RECT  0 101.712 0.084 101.736 ;
    END
  END y[153]
  PIN y[154]
    DIRECTION OUTPUT ;
    USE SIGNAL ;
    PORT
      LAYER M4 ;
        RECT  0 101.904 0.084 101.928 ;
    END
  END y[154]
  PIN y[155]
    DIRECTION OUTPUT ;
    USE SIGNAL ;
    PORT
      LAYER M4 ;
        RECT  0 102.096 0.084 102.12 ;
    END
  END y[155]
  PIN y[156]
    DIRECTION OUTPUT ;
    USE SIGNAL ;
    PORT
      LAYER M4 ;
        RECT  0 102.288 0.084 102.312 ;
    END
  END y[156]
  PIN y[157]
    DIRECTION OUTPUT ;
    USE SIGNAL ;
    PORT
      LAYER M4 ;
        RECT  0 102.48 0.084 102.504 ;
    END
  END y[157]
  PIN y[158]
    DIRECTION OUTPUT ;
    USE SIGNAL ;
    PORT
      LAYER M4 ;
        RECT  0 102.672 0.084 102.696 ;
    END
  END y[158]
  PIN y[159]
    DIRECTION OUTPUT ;
    USE SIGNAL ;
    PORT
      LAYER M4 ;
        RECT  0 102.864 0.084 102.888 ;
    END
  END y[159]
  PIN y[15]
    DIRECTION OUTPUT ;
    USE SIGNAL ;
    PORT
      LAYER M4 ;
        RECT  0 26.064 0.084 26.088 ;
    END
  END y[15]
  PIN y[160]
    DIRECTION OUTPUT ;
    USE SIGNAL ;
    PORT
      LAYER M4 ;
        RECT  0 115.344 0.084 115.368 ;
    END
  END y[160]
  PIN y[161]
    DIRECTION OUTPUT ;
    USE SIGNAL ;
    PORT
      LAYER M4 ;
        RECT  0 115.536 0.084 115.56 ;
    END
  END y[161]
  PIN y[162]
    DIRECTION OUTPUT ;
    USE SIGNAL ;
    PORT
      LAYER M4 ;
        RECT  0 115.728 0.084 115.752 ;
    END
  END y[162]
  PIN y[163]
    DIRECTION OUTPUT ;
    USE SIGNAL ;
    PORT
      LAYER M4 ;
        RECT  0 115.92 0.084 115.944 ;
    END
  END y[163]
  PIN y[164]
    DIRECTION OUTPUT ;
    USE SIGNAL ;
    PORT
      LAYER M4 ;
        RECT  0 116.112 0.084 116.136 ;
    END
  END y[164]
  PIN y[165]
    DIRECTION OUTPUT ;
    USE SIGNAL ;
    PORT
      LAYER M4 ;
        RECT  0 116.304 0.084 116.328 ;
    END
  END y[165]
  PIN y[166]
    DIRECTION OUTPUT ;
    USE SIGNAL ;
    PORT
      LAYER M4 ;
        RECT  0 116.496 0.084 116.52 ;
    END
  END y[166]
  PIN y[167]
    DIRECTION OUTPUT ;
    USE SIGNAL ;
    PORT
      LAYER M4 ;
        RECT  0 116.688 0.084 116.712 ;
    END
  END y[167]
  PIN y[168]
    DIRECTION OUTPUT ;
    USE SIGNAL ;
    PORT
      LAYER M4 ;
        RECT  0 116.88 0.084 116.904 ;
    END
  END y[168]
  PIN y[169]
    DIRECTION OUTPUT ;
    USE SIGNAL ;
    PORT
      LAYER M4 ;
        RECT  0 117.072 0.084 117.096 ;
    END
  END y[169]
  PIN y[16]
    DIRECTION OUTPUT ;
    USE SIGNAL ;
    PORT
      LAYER M4 ;
        RECT  0 26.256 0.084 26.28 ;
    END
  END y[16]
  PIN y[170]
    DIRECTION OUTPUT ;
    USE SIGNAL ;
    PORT
      LAYER M4 ;
        RECT  0 117.264 0.084 117.288 ;
    END
  END y[170]
  PIN y[171]
    DIRECTION OUTPUT ;
    USE SIGNAL ;
    PORT
      LAYER M4 ;
        RECT  0 117.456 0.084 117.48 ;
    END
  END y[171]
  PIN y[172]
    DIRECTION OUTPUT ;
    USE SIGNAL ;
    PORT
      LAYER M4 ;
        RECT  0 117.648 0.084 117.672 ;
    END
  END y[172]
  PIN y[173]
    DIRECTION OUTPUT ;
    USE SIGNAL ;
    PORT
      LAYER M4 ;
        RECT  0 117.84 0.084 117.864 ;
    END
  END y[173]
  PIN y[174]
    DIRECTION OUTPUT ;
    USE SIGNAL ;
    PORT
      LAYER M4 ;
        RECT  0 118.032 0.084 118.056 ;
    END
  END y[174]
  PIN y[175]
    DIRECTION OUTPUT ;
    USE SIGNAL ;
    PORT
      LAYER M4 ;
        RECT  0 118.224 0.084 118.248 ;
    END
  END y[175]
  PIN y[176]
    DIRECTION OUTPUT ;
    USE SIGNAL ;
    PORT
      LAYER M4 ;
        RECT  0 118.416 0.084 118.44 ;
    END
  END y[176]
  PIN y[177]
    DIRECTION OUTPUT ;
    USE SIGNAL ;
    PORT
      LAYER M4 ;
        RECT  0 118.608 0.084 118.632 ;
    END
  END y[177]
  PIN y[178]
    DIRECTION OUTPUT ;
    USE SIGNAL ;
    PORT
      LAYER M4 ;
        RECT  0 118.8 0.084 118.824 ;
    END
  END y[178]
  PIN y[179]
    DIRECTION OUTPUT ;
    USE SIGNAL ;
    PORT
      LAYER M4 ;
        RECT  0 118.992 0.084 119.016 ;
    END
  END y[179]
  PIN y[17]
    DIRECTION OUTPUT ;
    USE SIGNAL ;
    PORT
      LAYER M4 ;
        RECT  0 26.448 0.084 26.472 ;
    END
  END y[17]
  PIN y[180]
    DIRECTION OUTPUT ;
    USE SIGNAL ;
    PORT
      LAYER M4 ;
        RECT  0 119.184 0.084 119.208 ;
    END
  END y[180]
  PIN y[181]
    DIRECTION OUTPUT ;
    USE SIGNAL ;
    PORT
      LAYER M4 ;
        RECT  0 119.376 0.084 119.4 ;
    END
  END y[181]
  PIN y[182]
    DIRECTION OUTPUT ;
    USE SIGNAL ;
    PORT
      LAYER M4 ;
        RECT  0 119.568 0.084 119.592 ;
    END
  END y[182]
  PIN y[183]
    DIRECTION OUTPUT ;
    USE SIGNAL ;
    PORT
      LAYER M4 ;
        RECT  0 119.76 0.084 119.784 ;
    END
  END y[183]
  PIN y[184]
    DIRECTION OUTPUT ;
    USE SIGNAL ;
    PORT
      LAYER M4 ;
        RECT  0 119.952 0.084 119.976 ;
    END
  END y[184]
  PIN y[185]
    DIRECTION OUTPUT ;
    USE SIGNAL ;
    PORT
      LAYER M4 ;
        RECT  0 120.144 0.084 120.168 ;
    END
  END y[185]
  PIN y[186]
    DIRECTION OUTPUT ;
    USE SIGNAL ;
    PORT
      LAYER M4 ;
        RECT  0 120.336 0.084 120.36 ;
    END
  END y[186]
  PIN y[187]
    DIRECTION OUTPUT ;
    USE SIGNAL ;
    PORT
      LAYER M4 ;
        RECT  0 120.528 0.084 120.552 ;
    END
  END y[187]
  PIN y[188]
    DIRECTION OUTPUT ;
    USE SIGNAL ;
    PORT
      LAYER M4 ;
        RECT  0 120.72 0.084 120.744 ;
    END
  END y[188]
  PIN y[189]
    DIRECTION OUTPUT ;
    USE SIGNAL ;
    PORT
      LAYER M4 ;
        RECT  0 120.912 0.084 120.936 ;
    END
  END y[189]
  PIN y[18]
    DIRECTION OUTPUT ;
    USE SIGNAL ;
    PORT
      LAYER M4 ;
        RECT  0 26.64 0.084 26.664 ;
    END
  END y[18]
  PIN y[190]
    DIRECTION OUTPUT ;
    USE SIGNAL ;
    PORT
      LAYER M4 ;
        RECT  0 121.104 0.084 121.128 ;
    END
  END y[190]
  PIN y[191]
    DIRECTION OUTPUT ;
    USE SIGNAL ;
    PORT
      LAYER M4 ;
        RECT  0 121.296 0.084 121.32 ;
    END
  END y[191]
  PIN y[192]
    DIRECTION OUTPUT ;
    USE SIGNAL ;
    PORT
      LAYER M4 ;
        RECT  0 133.776 0.084 133.8 ;
    END
  END y[192]
  PIN y[193]
    DIRECTION OUTPUT ;
    USE SIGNAL ;
    PORT
      LAYER M4 ;
        RECT  0 133.968 0.084 133.992 ;
    END
  END y[193]
  PIN y[194]
    DIRECTION OUTPUT ;
    USE SIGNAL ;
    PORT
      LAYER M4 ;
        RECT  0 134.16 0.084 134.184 ;
    END
  END y[194]
  PIN y[195]
    DIRECTION OUTPUT ;
    USE SIGNAL ;
    PORT
      LAYER M4 ;
        RECT  0 134.352 0.084 134.376 ;
    END
  END y[195]
  PIN y[196]
    DIRECTION OUTPUT ;
    USE SIGNAL ;
    PORT
      LAYER M4 ;
        RECT  0 134.544 0.084 134.568 ;
    END
  END y[196]
  PIN y[197]
    DIRECTION OUTPUT ;
    USE SIGNAL ;
    PORT
      LAYER M4 ;
        RECT  0 134.736 0.084 134.76 ;
    END
  END y[197]
  PIN y[198]
    DIRECTION OUTPUT ;
    USE SIGNAL ;
    PORT
      LAYER M4 ;
        RECT  0 134.928 0.084 134.952 ;
    END
  END y[198]
  PIN y[199]
    DIRECTION OUTPUT ;
    USE SIGNAL ;
    PORT
      LAYER M4 ;
        RECT  0 135.12 0.084 135.144 ;
    END
  END y[199]
  PIN y[19]
    DIRECTION OUTPUT ;
    USE SIGNAL ;
    PORT
      LAYER M4 ;
        RECT  0 26.832 0.084 26.856 ;
    END
  END y[19]
  PIN y[1]
    DIRECTION OUTPUT ;
    USE SIGNAL ;
    PORT
      LAYER M4 ;
        RECT  0 23.376 0.084 23.4 ;
    END
  END y[1]
  PIN y[200]
    DIRECTION OUTPUT ;
    USE SIGNAL ;
    PORT
      LAYER M4 ;
        RECT  0 135.312 0.084 135.336 ;
    END
  END y[200]
  PIN y[201]
    DIRECTION OUTPUT ;
    USE SIGNAL ;
    PORT
      LAYER M4 ;
        RECT  0 135.504 0.084 135.528 ;
    END
  END y[201]
  PIN y[202]
    DIRECTION OUTPUT ;
    USE SIGNAL ;
    PORT
      LAYER M4 ;
        RECT  0 135.696 0.084 135.72 ;
    END
  END y[202]
  PIN y[203]
    DIRECTION OUTPUT ;
    USE SIGNAL ;
    PORT
      LAYER M4 ;
        RECT  0 135.888 0.084 135.912 ;
    END
  END y[203]
  PIN y[204]
    DIRECTION OUTPUT ;
    USE SIGNAL ;
    PORT
      LAYER M4 ;
        RECT  0 136.08 0.084 136.104 ;
    END
  END y[204]
  PIN y[205]
    DIRECTION OUTPUT ;
    USE SIGNAL ;
    PORT
      LAYER M4 ;
        RECT  0 136.272 0.084 136.296 ;
    END
  END y[205]
  PIN y[206]
    DIRECTION OUTPUT ;
    USE SIGNAL ;
    PORT
      LAYER M4 ;
        RECT  0 136.464 0.084 136.488 ;
    END
  END y[206]
  PIN y[207]
    DIRECTION OUTPUT ;
    USE SIGNAL ;
    PORT
      LAYER M4 ;
        RECT  0 136.656 0.084 136.68 ;
    END
  END y[207]
  PIN y[208]
    DIRECTION OUTPUT ;
    USE SIGNAL ;
    PORT
      LAYER M4 ;
        RECT  0 136.848 0.084 136.872 ;
    END
  END y[208]
  PIN y[209]
    DIRECTION OUTPUT ;
    USE SIGNAL ;
    PORT
      LAYER M4 ;
        RECT  0 137.04 0.084 137.064 ;
    END
  END y[209]
  PIN y[20]
    DIRECTION OUTPUT ;
    USE SIGNAL ;
    PORT
      LAYER M4 ;
        RECT  0 27.024 0.084 27.048 ;
    END
  END y[20]
  PIN y[210]
    DIRECTION OUTPUT ;
    USE SIGNAL ;
    PORT
      LAYER M4 ;
        RECT  0 137.232 0.084 137.256 ;
    END
  END y[210]
  PIN y[211]
    DIRECTION OUTPUT ;
    USE SIGNAL ;
    PORT
      LAYER M4 ;
        RECT  0 137.424 0.084 137.448 ;
    END
  END y[211]
  PIN y[212]
    DIRECTION OUTPUT ;
    USE SIGNAL ;
    PORT
      LAYER M4 ;
        RECT  0 137.616 0.084 137.64 ;
    END
  END y[212]
  PIN y[213]
    DIRECTION OUTPUT ;
    USE SIGNAL ;
    PORT
      LAYER M4 ;
        RECT  0 137.808 0.084 137.832 ;
    END
  END y[213]
  PIN y[214]
    DIRECTION OUTPUT ;
    USE SIGNAL ;
    PORT
      LAYER M4 ;
        RECT  0 138 0.084 138.024 ;
    END
  END y[214]
  PIN y[215]
    DIRECTION OUTPUT ;
    USE SIGNAL ;
    PORT
      LAYER M4 ;
        RECT  0 138.192 0.084 138.216 ;
    END
  END y[215]
  PIN y[216]
    DIRECTION OUTPUT ;
    USE SIGNAL ;
    PORT
      LAYER M4 ;
        RECT  0 138.384 0.084 138.408 ;
    END
  END y[216]
  PIN y[217]
    DIRECTION OUTPUT ;
    USE SIGNAL ;
    PORT
      LAYER M4 ;
        RECT  0 138.576 0.084 138.6 ;
    END
  END y[217]
  PIN y[218]
    DIRECTION OUTPUT ;
    USE SIGNAL ;
    PORT
      LAYER M4 ;
        RECT  0 138.768 0.084 138.792 ;
    END
  END y[218]
  PIN y[219]
    DIRECTION OUTPUT ;
    USE SIGNAL ;
    PORT
      LAYER M4 ;
        RECT  0 138.96 0.084 138.984 ;
    END
  END y[219]
  PIN y[21]
    DIRECTION OUTPUT ;
    USE SIGNAL ;
    PORT
      LAYER M4 ;
        RECT  0 27.216 0.084 27.24 ;
    END
  END y[21]
  PIN y[220]
    DIRECTION OUTPUT ;
    USE SIGNAL ;
    PORT
      LAYER M4 ;
        RECT  0 139.152 0.084 139.176 ;
    END
  END y[220]
  PIN y[221]
    DIRECTION OUTPUT ;
    USE SIGNAL ;
    PORT
      LAYER M4 ;
        RECT  0 139.344 0.084 139.368 ;
    END
  END y[221]
  PIN y[222]
    DIRECTION OUTPUT ;
    USE SIGNAL ;
    PORT
      LAYER M4 ;
        RECT  0 139.536 0.084 139.56 ;
    END
  END y[222]
  PIN y[223]
    DIRECTION OUTPUT ;
    USE SIGNAL ;
    PORT
      LAYER M4 ;
        RECT  0 139.728 0.084 139.752 ;
    END
  END y[223]
  PIN y[224]
    DIRECTION OUTPUT ;
    USE SIGNAL ;
    PORT
      LAYER M4 ;
        RECT  0 152.208 0.084 152.232 ;
    END
  END y[224]
  PIN y[225]
    DIRECTION OUTPUT ;
    USE SIGNAL ;
    PORT
      LAYER M4 ;
        RECT  0 152.4 0.084 152.424 ;
    END
  END y[225]
  PIN y[226]
    DIRECTION OUTPUT ;
    USE SIGNAL ;
    PORT
      LAYER M4 ;
        RECT  0 152.592 0.084 152.616 ;
    END
  END y[226]
  PIN y[227]
    DIRECTION OUTPUT ;
    USE SIGNAL ;
    PORT
      LAYER M4 ;
        RECT  0 152.784 0.084 152.808 ;
    END
  END y[227]
  PIN y[228]
    DIRECTION OUTPUT ;
    USE SIGNAL ;
    PORT
      LAYER M4 ;
        RECT  0 152.976 0.084 153 ;
    END
  END y[228]
  PIN y[229]
    DIRECTION OUTPUT ;
    USE SIGNAL ;
    PORT
      LAYER M4 ;
        RECT  0 153.168 0.084 153.192 ;
    END
  END y[229]
  PIN y[22]
    DIRECTION OUTPUT ;
    USE SIGNAL ;
    PORT
      LAYER M4 ;
        RECT  0 27.408 0.084 27.432 ;
    END
  END y[22]
  PIN y[230]
    DIRECTION OUTPUT ;
    USE SIGNAL ;
    PORT
      LAYER M4 ;
        RECT  0 153.36 0.084 153.384 ;
    END
  END y[230]
  PIN y[231]
    DIRECTION OUTPUT ;
    USE SIGNAL ;
    PORT
      LAYER M4 ;
        RECT  0 153.552 0.084 153.576 ;
    END
  END y[231]
  PIN y[232]
    DIRECTION OUTPUT ;
    USE SIGNAL ;
    PORT
      LAYER M4 ;
        RECT  0 153.744 0.084 153.768 ;
    END
  END y[232]
  PIN y[233]
    DIRECTION OUTPUT ;
    USE SIGNAL ;
    PORT
      LAYER M4 ;
        RECT  0 153.936 0.084 153.96 ;
    END
  END y[233]
  PIN y[234]
    DIRECTION OUTPUT ;
    USE SIGNAL ;
    PORT
      LAYER M4 ;
        RECT  0 154.128 0.084 154.152 ;
    END
  END y[234]
  PIN y[235]
    DIRECTION OUTPUT ;
    USE SIGNAL ;
    PORT
      LAYER M4 ;
        RECT  0 154.32 0.084 154.344 ;
    END
  END y[235]
  PIN y[236]
    DIRECTION OUTPUT ;
    USE SIGNAL ;
    PORT
      LAYER M4 ;
        RECT  0 154.512 0.084 154.536 ;
    END
  END y[236]
  PIN y[237]
    DIRECTION OUTPUT ;
    USE SIGNAL ;
    PORT
      LAYER M4 ;
        RECT  0 154.704 0.084 154.728 ;
    END
  END y[237]
  PIN y[238]
    DIRECTION OUTPUT ;
    USE SIGNAL ;
    PORT
      LAYER M4 ;
        RECT  0 154.896 0.084 154.92 ;
    END
  END y[238]
  PIN y[239]
    DIRECTION OUTPUT ;
    USE SIGNAL ;
    PORT
      LAYER M4 ;
        RECT  0 155.088 0.084 155.112 ;
    END
  END y[239]
  PIN y[23]
    DIRECTION OUTPUT ;
    USE SIGNAL ;
    PORT
      LAYER M4 ;
        RECT  0 27.6 0.084 27.624 ;
    END
  END y[23]
  PIN y[240]
    DIRECTION OUTPUT ;
    USE SIGNAL ;
    PORT
      LAYER M4 ;
        RECT  0 155.28 0.084 155.304 ;
    END
  END y[240]
  PIN y[241]
    DIRECTION OUTPUT ;
    USE SIGNAL ;
    PORT
      LAYER M4 ;
        RECT  0 155.472 0.084 155.496 ;
    END
  END y[241]
  PIN y[242]
    DIRECTION OUTPUT ;
    USE SIGNAL ;
    PORT
      LAYER M4 ;
        RECT  0 155.664 0.084 155.688 ;
    END
  END y[242]
  PIN y[243]
    DIRECTION OUTPUT ;
    USE SIGNAL ;
    PORT
      LAYER M4 ;
        RECT  0 155.856 0.084 155.88 ;
    END
  END y[243]
  PIN y[244]
    DIRECTION OUTPUT ;
    USE SIGNAL ;
    PORT
      LAYER M4 ;
        RECT  0 156.048 0.084 156.072 ;
    END
  END y[244]
  PIN y[245]
    DIRECTION OUTPUT ;
    USE SIGNAL ;
    PORT
      LAYER M4 ;
        RECT  0 156.24 0.084 156.264 ;
    END
  END y[245]
  PIN y[246]
    DIRECTION OUTPUT ;
    USE SIGNAL ;
    PORT
      LAYER M4 ;
        RECT  0 156.432 0.084 156.456 ;
    END
  END y[246]
  PIN y[247]
    DIRECTION OUTPUT ;
    USE SIGNAL ;
    PORT
      LAYER M4 ;
        RECT  0 156.624 0.084 156.648 ;
    END
  END y[247]
  PIN y[248]
    DIRECTION OUTPUT ;
    USE SIGNAL ;
    PORT
      LAYER M4 ;
        RECT  0 156.816 0.084 156.84 ;
    END
  END y[248]
  PIN y[249]
    DIRECTION OUTPUT ;
    USE SIGNAL ;
    PORT
      LAYER M4 ;
        RECT  0 157.008 0.084 157.032 ;
    END
  END y[249]
  PIN y[24]
    DIRECTION OUTPUT ;
    USE SIGNAL ;
    PORT
      LAYER M4 ;
        RECT  0 27.792 0.084 27.816 ;
    END
  END y[24]
  PIN y[250]
    DIRECTION OUTPUT ;
    USE SIGNAL ;
    PORT
      LAYER M4 ;
        RECT  0 157.2 0.084 157.224 ;
    END
  END y[250]
  PIN y[251]
    DIRECTION OUTPUT ;
    USE SIGNAL ;
    PORT
      LAYER M4 ;
        RECT  0 157.392 0.084 157.416 ;
    END
  END y[251]
  PIN y[252]
    DIRECTION OUTPUT ;
    USE SIGNAL ;
    PORT
      LAYER M4 ;
        RECT  0 157.584 0.084 157.608 ;
    END
  END y[252]
  PIN y[253]
    DIRECTION OUTPUT ;
    USE SIGNAL ;
    PORT
      LAYER M4 ;
        RECT  0 157.776 0.084 157.8 ;
    END
  END y[253]
  PIN y[254]
    DIRECTION OUTPUT ;
    USE SIGNAL ;
    PORT
      LAYER M4 ;
        RECT  0 157.968 0.084 157.992 ;
    END
  END y[254]
  PIN y[255]
    DIRECTION OUTPUT ;
    USE SIGNAL ;
    PORT
      LAYER M4 ;
        RECT  0 158.16 0.084 158.184 ;
    END
  END y[255]
  PIN y[256]
    DIRECTION OUTPUT ;
    USE SIGNAL ;
    PORT
      LAYER M4 ;
        RECT  0 170.64 0.084 170.664 ;
    END
  END y[256]
  PIN y[257]
    DIRECTION OUTPUT ;
    USE SIGNAL ;
    PORT
      LAYER M4 ;
        RECT  0 170.832 0.084 170.856 ;
    END
  END y[257]
  PIN y[258]
    DIRECTION OUTPUT ;
    USE SIGNAL ;
    PORT
      LAYER M4 ;
        RECT  0 171.024 0.084 171.048 ;
    END
  END y[258]
  PIN y[259]
    DIRECTION OUTPUT ;
    USE SIGNAL ;
    PORT
      LAYER M4 ;
        RECT  0 171.216 0.084 171.24 ;
    END
  END y[259]
  PIN y[25]
    DIRECTION OUTPUT ;
    USE SIGNAL ;
    PORT
      LAYER M4 ;
        RECT  0 27.984 0.084 28.008 ;
    END
  END y[25]
  PIN y[260]
    DIRECTION OUTPUT ;
    USE SIGNAL ;
    PORT
      LAYER M4 ;
        RECT  0 171.408 0.084 171.432 ;
    END
  END y[260]
  PIN y[261]
    DIRECTION OUTPUT ;
    USE SIGNAL ;
    PORT
      LAYER M4 ;
        RECT  0 171.6 0.084 171.624 ;
    END
  END y[261]
  PIN y[262]
    DIRECTION OUTPUT ;
    USE SIGNAL ;
    PORT
      LAYER M4 ;
        RECT  0 171.792 0.084 171.816 ;
    END
  END y[262]
  PIN y[263]
    DIRECTION OUTPUT ;
    USE SIGNAL ;
    PORT
      LAYER M4 ;
        RECT  0 171.984 0.084 172.008 ;
    END
  END y[263]
  PIN y[264]
    DIRECTION OUTPUT ;
    USE SIGNAL ;
    PORT
      LAYER M4 ;
        RECT  0 172.176 0.084 172.2 ;
    END
  END y[264]
  PIN y[265]
    DIRECTION OUTPUT ;
    USE SIGNAL ;
    PORT
      LAYER M4 ;
        RECT  0 172.368 0.084 172.392 ;
    END
  END y[265]
  PIN y[266]
    DIRECTION OUTPUT ;
    USE SIGNAL ;
    PORT
      LAYER M4 ;
        RECT  0 172.56 0.084 172.584 ;
    END
  END y[266]
  PIN y[267]
    DIRECTION OUTPUT ;
    USE SIGNAL ;
    PORT
      LAYER M4 ;
        RECT  0 172.752 0.084 172.776 ;
    END
  END y[267]
  PIN y[268]
    DIRECTION OUTPUT ;
    USE SIGNAL ;
    PORT
      LAYER M4 ;
        RECT  0 172.944 0.084 172.968 ;
    END
  END y[268]
  PIN y[269]
    DIRECTION OUTPUT ;
    USE SIGNAL ;
    PORT
      LAYER M4 ;
        RECT  0 173.136 0.084 173.16 ;
    END
  END y[269]
  PIN y[26]
    DIRECTION OUTPUT ;
    USE SIGNAL ;
    PORT
      LAYER M4 ;
        RECT  0 28.176 0.084 28.2 ;
    END
  END y[26]
  PIN y[270]
    DIRECTION OUTPUT ;
    USE SIGNAL ;
    PORT
      LAYER M4 ;
        RECT  0 173.328 0.084 173.352 ;
    END
  END y[270]
  PIN y[271]
    DIRECTION OUTPUT ;
    USE SIGNAL ;
    PORT
      LAYER M4 ;
        RECT  0 173.52 0.084 173.544 ;
    END
  END y[271]
  PIN y[272]
    DIRECTION OUTPUT ;
    USE SIGNAL ;
    PORT
      LAYER M4 ;
        RECT  0 173.712 0.084 173.736 ;
    END
  END y[272]
  PIN y[273]
    DIRECTION OUTPUT ;
    USE SIGNAL ;
    PORT
      LAYER M4 ;
        RECT  0 173.904 0.084 173.928 ;
    END
  END y[273]
  PIN y[274]
    DIRECTION OUTPUT ;
    USE SIGNAL ;
    PORT
      LAYER M4 ;
        RECT  0 174.096 0.084 174.12 ;
    END
  END y[274]
  PIN y[275]
    DIRECTION OUTPUT ;
    USE SIGNAL ;
    PORT
      LAYER M4 ;
        RECT  0 174.288 0.084 174.312 ;
    END
  END y[275]
  PIN y[276]
    DIRECTION OUTPUT ;
    USE SIGNAL ;
    PORT
      LAYER M4 ;
        RECT  0 174.48 0.084 174.504 ;
    END
  END y[276]
  PIN y[277]
    DIRECTION OUTPUT ;
    USE SIGNAL ;
    PORT
      LAYER M4 ;
        RECT  0 174.672 0.084 174.696 ;
    END
  END y[277]
  PIN y[278]
    DIRECTION OUTPUT ;
    USE SIGNAL ;
    PORT
      LAYER M4 ;
        RECT  0 174.864 0.084 174.888 ;
    END
  END y[278]
  PIN y[279]
    DIRECTION OUTPUT ;
    USE SIGNAL ;
    PORT
      LAYER M4 ;
        RECT  0 175.056 0.084 175.08 ;
    END
  END y[279]
  PIN y[27]
    DIRECTION OUTPUT ;
    USE SIGNAL ;
    PORT
      LAYER M4 ;
        RECT  0 28.368 0.084 28.392 ;
    END
  END y[27]
  PIN y[280]
    DIRECTION OUTPUT ;
    USE SIGNAL ;
    PORT
      LAYER M4 ;
        RECT  0 175.248 0.084 175.272 ;
    END
  END y[280]
  PIN y[281]
    DIRECTION OUTPUT ;
    USE SIGNAL ;
    PORT
      LAYER M4 ;
        RECT  0 175.44 0.084 175.464 ;
    END
  END y[281]
  PIN y[282]
    DIRECTION OUTPUT ;
    USE SIGNAL ;
    PORT
      LAYER M4 ;
        RECT  0 175.632 0.084 175.656 ;
    END
  END y[282]
  PIN y[283]
    DIRECTION OUTPUT ;
    USE SIGNAL ;
    PORT
      LAYER M4 ;
        RECT  0 175.824 0.084 175.848 ;
    END
  END y[283]
  PIN y[284]
    DIRECTION OUTPUT ;
    USE SIGNAL ;
    PORT
      LAYER M4 ;
        RECT  0 176.016 0.084 176.04 ;
    END
  END y[284]
  PIN y[285]
    DIRECTION OUTPUT ;
    USE SIGNAL ;
    PORT
      LAYER M4 ;
        RECT  0 176.208 0.084 176.232 ;
    END
  END y[285]
  PIN y[286]
    DIRECTION OUTPUT ;
    USE SIGNAL ;
    PORT
      LAYER M4 ;
        RECT  0 176.4 0.084 176.424 ;
    END
  END y[286]
  PIN y[287]
    DIRECTION OUTPUT ;
    USE SIGNAL ;
    PORT
      LAYER M4 ;
        RECT  0 176.592 0.084 176.616 ;
    END
  END y[287]
  PIN y[288]
    DIRECTION OUTPUT ;
    USE SIGNAL ;
    PORT
      LAYER M4 ;
        RECT  0 189.072 0.084 189.096 ;
    END
  END y[288]
  PIN y[289]
    DIRECTION OUTPUT ;
    USE SIGNAL ;
    PORT
      LAYER M4 ;
        RECT  0 189.264 0.084 189.288 ;
    END
  END y[289]
  PIN y[28]
    DIRECTION OUTPUT ;
    USE SIGNAL ;
    PORT
      LAYER M4 ;
        RECT  0 28.56 0.084 28.584 ;
    END
  END y[28]
  PIN y[290]
    DIRECTION OUTPUT ;
    USE SIGNAL ;
    PORT
      LAYER M4 ;
        RECT  0 189.456 0.084 189.48 ;
    END
  END y[290]
  PIN y[291]
    DIRECTION OUTPUT ;
    USE SIGNAL ;
    PORT
      LAYER M4 ;
        RECT  0 189.648 0.084 189.672 ;
    END
  END y[291]
  PIN y[292]
    DIRECTION OUTPUT ;
    USE SIGNAL ;
    PORT
      LAYER M4 ;
        RECT  0 189.84 0.084 189.864 ;
    END
  END y[292]
  PIN y[293]
    DIRECTION OUTPUT ;
    USE SIGNAL ;
    PORT
      LAYER M4 ;
        RECT  0 190.032 0.084 190.056 ;
    END
  END y[293]
  PIN y[294]
    DIRECTION OUTPUT ;
    USE SIGNAL ;
    PORT
      LAYER M4 ;
        RECT  0 190.224 0.084 190.248 ;
    END
  END y[294]
  PIN y[295]
    DIRECTION OUTPUT ;
    USE SIGNAL ;
    PORT
      LAYER M4 ;
        RECT  0 190.416 0.084 190.44 ;
    END
  END y[295]
  PIN y[296]
    DIRECTION OUTPUT ;
    USE SIGNAL ;
    PORT
      LAYER M4 ;
        RECT  0 190.608 0.084 190.632 ;
    END
  END y[296]
  PIN y[297]
    DIRECTION OUTPUT ;
    USE SIGNAL ;
    PORT
      LAYER M4 ;
        RECT  0 190.8 0.084 190.824 ;
    END
  END y[297]
  PIN y[298]
    DIRECTION OUTPUT ;
    USE SIGNAL ;
    PORT
      LAYER M4 ;
        RECT  0 190.992 0.084 191.016 ;
    END
  END y[298]
  PIN y[299]
    DIRECTION OUTPUT ;
    USE SIGNAL ;
    PORT
      LAYER M4 ;
        RECT  0 191.184 0.084 191.208 ;
    END
  END y[299]
  PIN y[29]
    DIRECTION OUTPUT ;
    USE SIGNAL ;
    PORT
      LAYER M4 ;
        RECT  0 28.752 0.084 28.776 ;
    END
  END y[29]
  PIN y[2]
    DIRECTION OUTPUT ;
    USE SIGNAL ;
    PORT
      LAYER M4 ;
        RECT  0 23.568 0.084 23.592 ;
    END
  END y[2]
  PIN y[300]
    DIRECTION OUTPUT ;
    USE SIGNAL ;
    PORT
      LAYER M4 ;
        RECT  0 191.376 0.084 191.4 ;
    END
  END y[300]
  PIN y[301]
    DIRECTION OUTPUT ;
    USE SIGNAL ;
    PORT
      LAYER M4 ;
        RECT  0 191.568 0.084 191.592 ;
    END
  END y[301]
  PIN y[302]
    DIRECTION OUTPUT ;
    USE SIGNAL ;
    PORT
      LAYER M4 ;
        RECT  0 191.76 0.084 191.784 ;
    END
  END y[302]
  PIN y[303]
    DIRECTION OUTPUT ;
    USE SIGNAL ;
    PORT
      LAYER M4 ;
        RECT  0 191.952 0.084 191.976 ;
    END
  END y[303]
  PIN y[304]
    DIRECTION OUTPUT ;
    USE SIGNAL ;
    PORT
      LAYER M4 ;
        RECT  0 192.144 0.084 192.168 ;
    END
  END y[304]
  PIN y[305]
    DIRECTION OUTPUT ;
    USE SIGNAL ;
    PORT
      LAYER M4 ;
        RECT  0 192.336 0.084 192.36 ;
    END
  END y[305]
  PIN y[306]
    DIRECTION OUTPUT ;
    USE SIGNAL ;
    PORT
      LAYER M4 ;
        RECT  0 192.528 0.084 192.552 ;
    END
  END y[306]
  PIN y[307]
    DIRECTION OUTPUT ;
    USE SIGNAL ;
    PORT
      LAYER M4 ;
        RECT  0 192.72 0.084 192.744 ;
    END
  END y[307]
  PIN y[308]
    DIRECTION OUTPUT ;
    USE SIGNAL ;
    PORT
      LAYER M4 ;
        RECT  0 192.912 0.084 192.936 ;
    END
  END y[308]
  PIN y[309]
    DIRECTION OUTPUT ;
    USE SIGNAL ;
    PORT
      LAYER M4 ;
        RECT  0 193.104 0.084 193.128 ;
    END
  END y[309]
  PIN y[30]
    DIRECTION OUTPUT ;
    USE SIGNAL ;
    PORT
      LAYER M4 ;
        RECT  0 28.944 0.084 28.968 ;
    END
  END y[30]
  PIN y[310]
    DIRECTION OUTPUT ;
    USE SIGNAL ;
    PORT
      LAYER M4 ;
        RECT  0 193.296 0.084 193.32 ;
    END
  END y[310]
  PIN y[311]
    DIRECTION OUTPUT ;
    USE SIGNAL ;
    PORT
      LAYER M4 ;
        RECT  0 193.488 0.084 193.512 ;
    END
  END y[311]
  PIN y[312]
    DIRECTION OUTPUT ;
    USE SIGNAL ;
    PORT
      LAYER M4 ;
        RECT  0 193.68 0.084 193.704 ;
    END
  END y[312]
  PIN y[313]
    DIRECTION OUTPUT ;
    USE SIGNAL ;
    PORT
      LAYER M4 ;
        RECT  0 193.872 0.084 193.896 ;
    END
  END y[313]
  PIN y[314]
    DIRECTION OUTPUT ;
    USE SIGNAL ;
    PORT
      LAYER M4 ;
        RECT  0 194.064 0.084 194.088 ;
    END
  END y[314]
  PIN y[315]
    DIRECTION OUTPUT ;
    USE SIGNAL ;
    PORT
      LAYER M4 ;
        RECT  0 194.256 0.084 194.28 ;
    END
  END y[315]
  PIN y[316]
    DIRECTION OUTPUT ;
    USE SIGNAL ;
    PORT
      LAYER M4 ;
        RECT  0 194.448 0.084 194.472 ;
    END
  END y[316]
  PIN y[317]
    DIRECTION OUTPUT ;
    USE SIGNAL ;
    PORT
      LAYER M4 ;
        RECT  0 194.64 0.084 194.664 ;
    END
  END y[317]
  PIN y[318]
    DIRECTION OUTPUT ;
    USE SIGNAL ;
    PORT
      LAYER M4 ;
        RECT  0 194.832 0.084 194.856 ;
    END
  END y[318]
  PIN y[319]
    DIRECTION OUTPUT ;
    USE SIGNAL ;
    PORT
      LAYER M4 ;
        RECT  0 195.024 0.084 195.048 ;
    END
  END y[319]
  PIN y[31]
    DIRECTION OUTPUT ;
    USE SIGNAL ;
    PORT
      LAYER M4 ;
        RECT  0 29.136 0.084 29.16 ;
    END
  END y[31]
  PIN y[320]
    DIRECTION OUTPUT ;
    USE SIGNAL ;
    PORT
      LAYER M4 ;
        RECT  0 324.768 0.084 324.792 ;
    END
  END y[320]
  PIN y[321]
    DIRECTION OUTPUT ;
    USE SIGNAL ;
    PORT
      LAYER M4 ;
        RECT  0 324.96 0.084 324.984 ;
    END
  END y[321]
  PIN y[322]
    DIRECTION OUTPUT ;
    USE SIGNAL ;
    PORT
      LAYER M4 ;
        RECT  0 325.152 0.084 325.176 ;
    END
  END y[322]
  PIN y[323]
    DIRECTION OUTPUT ;
    USE SIGNAL ;
    PORT
      LAYER M4 ;
        RECT  0 325.344 0.084 325.368 ;
    END
  END y[323]
  PIN y[324]
    DIRECTION OUTPUT ;
    USE SIGNAL ;
    PORT
      LAYER M4 ;
        RECT  0 325.536 0.084 325.56 ;
    END
  END y[324]
  PIN y[325]
    DIRECTION OUTPUT ;
    USE SIGNAL ;
    PORT
      LAYER M4 ;
        RECT  0 325.728 0.084 325.752 ;
    END
  END y[325]
  PIN y[326]
    DIRECTION OUTPUT ;
    USE SIGNAL ;
    PORT
      LAYER M4 ;
        RECT  0 325.92 0.084 325.944 ;
    END
  END y[326]
  PIN y[327]
    DIRECTION OUTPUT ;
    USE SIGNAL ;
    PORT
      LAYER M4 ;
        RECT  0 326.112 0.084 326.136 ;
    END
  END y[327]
  PIN y[328]
    DIRECTION OUTPUT ;
    USE SIGNAL ;
    PORT
      LAYER M4 ;
        RECT  0 326.304 0.084 326.328 ;
    END
  END y[328]
  PIN y[329]
    DIRECTION OUTPUT ;
    USE SIGNAL ;
    PORT
      LAYER M4 ;
        RECT  0 326.496 0.084 326.52 ;
    END
  END y[329]
  PIN y[32]
    DIRECTION OUTPUT ;
    USE SIGNAL ;
    PORT
      LAYER M4 ;
        RECT  0 41.616 0.084 41.64 ;
    END
  END y[32]
  PIN y[330]
    DIRECTION OUTPUT ;
    USE SIGNAL ;
    PORT
      LAYER M4 ;
        RECT  0 326.688 0.084 326.712 ;
    END
  END y[330]
  PIN y[331]
    DIRECTION OUTPUT ;
    USE SIGNAL ;
    PORT
      LAYER M4 ;
        RECT  0 326.88 0.084 326.904 ;
    END
  END y[331]
  PIN y[332]
    DIRECTION OUTPUT ;
    USE SIGNAL ;
    PORT
      LAYER M4 ;
        RECT  0 327.072 0.084 327.096 ;
    END
  END y[332]
  PIN y[333]
    DIRECTION OUTPUT ;
    USE SIGNAL ;
    PORT
      LAYER M4 ;
        RECT  0 327.264 0.084 327.288 ;
    END
  END y[333]
  PIN y[334]
    DIRECTION OUTPUT ;
    USE SIGNAL ;
    PORT
      LAYER M4 ;
        RECT  0 327.456 0.084 327.48 ;
    END
  END y[334]
  PIN y[335]
    DIRECTION OUTPUT ;
    USE SIGNAL ;
    PORT
      LAYER M4 ;
        RECT  0 327.648 0.084 327.672 ;
    END
  END y[335]
  PIN y[336]
    DIRECTION OUTPUT ;
    USE SIGNAL ;
    PORT
      LAYER M4 ;
        RECT  0 327.84 0.084 327.864 ;
    END
  END y[336]
  PIN y[337]
    DIRECTION OUTPUT ;
    USE SIGNAL ;
    PORT
      LAYER M4 ;
        RECT  0 328.032 0.084 328.056 ;
    END
  END y[337]
  PIN y[338]
    DIRECTION OUTPUT ;
    USE SIGNAL ;
    PORT
      LAYER M4 ;
        RECT  0 328.224 0.084 328.248 ;
    END
  END y[338]
  PIN y[339]
    DIRECTION OUTPUT ;
    USE SIGNAL ;
    PORT
      LAYER M4 ;
        RECT  0 328.416 0.084 328.44 ;
    END
  END y[339]
  PIN y[33]
    DIRECTION OUTPUT ;
    USE SIGNAL ;
    PORT
      LAYER M4 ;
        RECT  0 41.808 0.084 41.832 ;
    END
  END y[33]
  PIN y[340]
    DIRECTION OUTPUT ;
    USE SIGNAL ;
    PORT
      LAYER M4 ;
        RECT  0 328.608 0.084 328.632 ;
    END
  END y[340]
  PIN y[341]
    DIRECTION OUTPUT ;
    USE SIGNAL ;
    PORT
      LAYER M4 ;
        RECT  0 328.8 0.084 328.824 ;
    END
  END y[341]
  PIN y[342]
    DIRECTION OUTPUT ;
    USE SIGNAL ;
    PORT
      LAYER M4 ;
        RECT  0 328.992 0.084 329.016 ;
    END
  END y[342]
  PIN y[343]
    DIRECTION OUTPUT ;
    USE SIGNAL ;
    PORT
      LAYER M4 ;
        RECT  0 329.184 0.084 329.208 ;
    END
  END y[343]
  PIN y[344]
    DIRECTION OUTPUT ;
    USE SIGNAL ;
    PORT
      LAYER M4 ;
        RECT  0 329.376 0.084 329.4 ;
    END
  END y[344]
  PIN y[345]
    DIRECTION OUTPUT ;
    USE SIGNAL ;
    PORT
      LAYER M4 ;
        RECT  0 329.568 0.084 329.592 ;
    END
  END y[345]
  PIN y[346]
    DIRECTION OUTPUT ;
    USE SIGNAL ;
    PORT
      LAYER M4 ;
        RECT  0 329.76 0.084 329.784 ;
    END
  END y[346]
  PIN y[347]
    DIRECTION OUTPUT ;
    USE SIGNAL ;
    PORT
      LAYER M4 ;
        RECT  0 329.952 0.084 329.976 ;
    END
  END y[347]
  PIN y[348]
    DIRECTION OUTPUT ;
    USE SIGNAL ;
    PORT
      LAYER M4 ;
        RECT  0 330.144 0.084 330.168 ;
    END
  END y[348]
  PIN y[349]
    DIRECTION OUTPUT ;
    USE SIGNAL ;
    PORT
      LAYER M4 ;
        RECT  0 330.336 0.084 330.36 ;
    END
  END y[349]
  PIN y[34]
    DIRECTION OUTPUT ;
    USE SIGNAL ;
    PORT
      LAYER M4 ;
        RECT  0 42 0.084 42.024 ;
    END
  END y[34]
  PIN y[350]
    DIRECTION OUTPUT ;
    USE SIGNAL ;
    PORT
      LAYER M4 ;
        RECT  0 330.528 0.084 330.552 ;
    END
  END y[350]
  PIN y[351]
    DIRECTION OUTPUT ;
    USE SIGNAL ;
    PORT
      LAYER M4 ;
        RECT  0 330.72 0.084 330.744 ;
    END
  END y[351]
  PIN y[352]
    DIRECTION OUTPUT ;
    USE SIGNAL ;
    PORT
      LAYER M4 ;
        RECT  0 343.2 0.084 343.224 ;
    END
  END y[352]
  PIN y[353]
    DIRECTION OUTPUT ;
    USE SIGNAL ;
    PORT
      LAYER M4 ;
        RECT  0 343.392 0.084 343.416 ;
    END
  END y[353]
  PIN y[354]
    DIRECTION OUTPUT ;
    USE SIGNAL ;
    PORT
      LAYER M4 ;
        RECT  0 343.584 0.084 343.608 ;
    END
  END y[354]
  PIN y[355]
    DIRECTION OUTPUT ;
    USE SIGNAL ;
    PORT
      LAYER M4 ;
        RECT  0 343.776 0.084 343.8 ;
    END
  END y[355]
  PIN y[356]
    DIRECTION OUTPUT ;
    USE SIGNAL ;
    PORT
      LAYER M4 ;
        RECT  0 343.968 0.084 343.992 ;
    END
  END y[356]
  PIN y[357]
    DIRECTION OUTPUT ;
    USE SIGNAL ;
    PORT
      LAYER M4 ;
        RECT  0 344.16 0.084 344.184 ;
    END
  END y[357]
  PIN y[358]
    DIRECTION OUTPUT ;
    USE SIGNAL ;
    PORT
      LAYER M4 ;
        RECT  0 344.352 0.084 344.376 ;
    END
  END y[358]
  PIN y[359]
    DIRECTION OUTPUT ;
    USE SIGNAL ;
    PORT
      LAYER M4 ;
        RECT  0 344.544 0.084 344.568 ;
    END
  END y[359]
  PIN y[35]
    DIRECTION OUTPUT ;
    USE SIGNAL ;
    PORT
      LAYER M4 ;
        RECT  0 42.192 0.084 42.216 ;
    END
  END y[35]
  PIN y[360]
    DIRECTION OUTPUT ;
    USE SIGNAL ;
    PORT
      LAYER M4 ;
        RECT  0 344.736 0.084 344.76 ;
    END
  END y[360]
  PIN y[361]
    DIRECTION OUTPUT ;
    USE SIGNAL ;
    PORT
      LAYER M4 ;
        RECT  0 344.928 0.084 344.952 ;
    END
  END y[361]
  PIN y[362]
    DIRECTION OUTPUT ;
    USE SIGNAL ;
    PORT
      LAYER M4 ;
        RECT  0 345.12 0.084 345.144 ;
    END
  END y[362]
  PIN y[363]
    DIRECTION OUTPUT ;
    USE SIGNAL ;
    PORT
      LAYER M4 ;
        RECT  0 345.312 0.084 345.336 ;
    END
  END y[363]
  PIN y[364]
    DIRECTION OUTPUT ;
    USE SIGNAL ;
    PORT
      LAYER M4 ;
        RECT  0 345.504 0.084 345.528 ;
    END
  END y[364]
  PIN y[365]
    DIRECTION OUTPUT ;
    USE SIGNAL ;
    PORT
      LAYER M4 ;
        RECT  0 345.696 0.084 345.72 ;
    END
  END y[365]
  PIN y[366]
    DIRECTION OUTPUT ;
    USE SIGNAL ;
    PORT
      LAYER M4 ;
        RECT  0 345.888 0.084 345.912 ;
    END
  END y[366]
  PIN y[367]
    DIRECTION OUTPUT ;
    USE SIGNAL ;
    PORT
      LAYER M4 ;
        RECT  0 346.08 0.084 346.104 ;
    END
  END y[367]
  PIN y[368]
    DIRECTION OUTPUT ;
    USE SIGNAL ;
    PORT
      LAYER M4 ;
        RECT  0 346.272 0.084 346.296 ;
    END
  END y[368]
  PIN y[369]
    DIRECTION OUTPUT ;
    USE SIGNAL ;
    PORT
      LAYER M4 ;
        RECT  0 346.464 0.084 346.488 ;
    END
  END y[369]
  PIN y[36]
    DIRECTION OUTPUT ;
    USE SIGNAL ;
    PORT
      LAYER M4 ;
        RECT  0 42.384 0.084 42.408 ;
    END
  END y[36]
  PIN y[370]
    DIRECTION OUTPUT ;
    USE SIGNAL ;
    PORT
      LAYER M4 ;
        RECT  0 346.656 0.084 346.68 ;
    END
  END y[370]
  PIN y[371]
    DIRECTION OUTPUT ;
    USE SIGNAL ;
    PORT
      LAYER M4 ;
        RECT  0 346.848 0.084 346.872 ;
    END
  END y[371]
  PIN y[372]
    DIRECTION OUTPUT ;
    USE SIGNAL ;
    PORT
      LAYER M4 ;
        RECT  0 347.04 0.084 347.064 ;
    END
  END y[372]
  PIN y[373]
    DIRECTION OUTPUT ;
    USE SIGNAL ;
    PORT
      LAYER M4 ;
        RECT  0 347.232 0.084 347.256 ;
    END
  END y[373]
  PIN y[374]
    DIRECTION OUTPUT ;
    USE SIGNAL ;
    PORT
      LAYER M4 ;
        RECT  0 347.424 0.084 347.448 ;
    END
  END y[374]
  PIN y[375]
    DIRECTION OUTPUT ;
    USE SIGNAL ;
    PORT
      LAYER M4 ;
        RECT  0 347.616 0.084 347.64 ;
    END
  END y[375]
  PIN y[376]
    DIRECTION OUTPUT ;
    USE SIGNAL ;
    PORT
      LAYER M4 ;
        RECT  0 347.808 0.084 347.832 ;
    END
  END y[376]
  PIN y[377]
    DIRECTION OUTPUT ;
    USE SIGNAL ;
    PORT
      LAYER M4 ;
        RECT  0 348 0.084 348.024 ;
    END
  END y[377]
  PIN y[378]
    DIRECTION OUTPUT ;
    USE SIGNAL ;
    PORT
      LAYER M4 ;
        RECT  0 348.192 0.084 348.216 ;
    END
  END y[378]
  PIN y[379]
    DIRECTION OUTPUT ;
    USE SIGNAL ;
    PORT
      LAYER M4 ;
        RECT  0 348.384 0.084 348.408 ;
    END
  END y[379]
  PIN y[37]
    DIRECTION OUTPUT ;
    USE SIGNAL ;
    PORT
      LAYER M4 ;
        RECT  0 42.576 0.084 42.6 ;
    END
  END y[37]
  PIN y[380]
    DIRECTION OUTPUT ;
    USE SIGNAL ;
    PORT
      LAYER M4 ;
        RECT  0 348.576 0.084 348.6 ;
    END
  END y[380]
  PIN y[381]
    DIRECTION OUTPUT ;
    USE SIGNAL ;
    PORT
      LAYER M4 ;
        RECT  0 348.768 0.084 348.792 ;
    END
  END y[381]
  PIN y[382]
    DIRECTION OUTPUT ;
    USE SIGNAL ;
    PORT
      LAYER M4 ;
        RECT  0 348.96 0.084 348.984 ;
    END
  END y[382]
  PIN y[383]
    DIRECTION OUTPUT ;
    USE SIGNAL ;
    PORT
      LAYER M4 ;
        RECT  0 349.152 0.084 349.176 ;
    END
  END y[383]
  PIN y[384]
    DIRECTION OUTPUT ;
    USE SIGNAL ;
    PORT
      LAYER M4 ;
        RECT  0 361.632 0.084 361.656 ;
    END
  END y[384]
  PIN y[385]
    DIRECTION OUTPUT ;
    USE SIGNAL ;
    PORT
      LAYER M4 ;
        RECT  0 361.824 0.084 361.848 ;
    END
  END y[385]
  PIN y[386]
    DIRECTION OUTPUT ;
    USE SIGNAL ;
    PORT
      LAYER M4 ;
        RECT  0 362.016 0.084 362.04 ;
    END
  END y[386]
  PIN y[387]
    DIRECTION OUTPUT ;
    USE SIGNAL ;
    PORT
      LAYER M4 ;
        RECT  0 362.208 0.084 362.232 ;
    END
  END y[387]
  PIN y[388]
    DIRECTION OUTPUT ;
    USE SIGNAL ;
    PORT
      LAYER M4 ;
        RECT  0 362.4 0.084 362.424 ;
    END
  END y[388]
  PIN y[389]
    DIRECTION OUTPUT ;
    USE SIGNAL ;
    PORT
      LAYER M4 ;
        RECT  0 362.592 0.084 362.616 ;
    END
  END y[389]
  PIN y[38]
    DIRECTION OUTPUT ;
    USE SIGNAL ;
    PORT
      LAYER M4 ;
        RECT  0 42.768 0.084 42.792 ;
    END
  END y[38]
  PIN y[390]
    DIRECTION OUTPUT ;
    USE SIGNAL ;
    PORT
      LAYER M4 ;
        RECT  0 362.784 0.084 362.808 ;
    END
  END y[390]
  PIN y[391]
    DIRECTION OUTPUT ;
    USE SIGNAL ;
    PORT
      LAYER M4 ;
        RECT  0 362.976 0.084 363 ;
    END
  END y[391]
  PIN y[392]
    DIRECTION OUTPUT ;
    USE SIGNAL ;
    PORT
      LAYER M4 ;
        RECT  0 363.168 0.084 363.192 ;
    END
  END y[392]
  PIN y[393]
    DIRECTION OUTPUT ;
    USE SIGNAL ;
    PORT
      LAYER M4 ;
        RECT  0 363.36 0.084 363.384 ;
    END
  END y[393]
  PIN y[394]
    DIRECTION OUTPUT ;
    USE SIGNAL ;
    PORT
      LAYER M4 ;
        RECT  0 363.552 0.084 363.576 ;
    END
  END y[394]
  PIN y[395]
    DIRECTION OUTPUT ;
    USE SIGNAL ;
    PORT
      LAYER M4 ;
        RECT  0 363.744 0.084 363.768 ;
    END
  END y[395]
  PIN y[396]
    DIRECTION OUTPUT ;
    USE SIGNAL ;
    PORT
      LAYER M4 ;
        RECT  0 363.936 0.084 363.96 ;
    END
  END y[396]
  PIN y[397]
    DIRECTION OUTPUT ;
    USE SIGNAL ;
    PORT
      LAYER M4 ;
        RECT  0 364.128 0.084 364.152 ;
    END
  END y[397]
  PIN y[398]
    DIRECTION OUTPUT ;
    USE SIGNAL ;
    PORT
      LAYER M4 ;
        RECT  0 364.32 0.084 364.344 ;
    END
  END y[398]
  PIN y[399]
    DIRECTION OUTPUT ;
    USE SIGNAL ;
    PORT
      LAYER M4 ;
        RECT  0 364.512 0.084 364.536 ;
    END
  END y[399]
  PIN y[39]
    DIRECTION OUTPUT ;
    USE SIGNAL ;
    PORT
      LAYER M4 ;
        RECT  0 42.96 0.084 42.984 ;
    END
  END y[39]
  PIN y[3]
    DIRECTION OUTPUT ;
    USE SIGNAL ;
    PORT
      LAYER M4 ;
        RECT  0 23.76 0.084 23.784 ;
    END
  END y[3]
  PIN y[400]
    DIRECTION OUTPUT ;
    USE SIGNAL ;
    PORT
      LAYER M4 ;
        RECT  0 364.704 0.084 364.728 ;
    END
  END y[400]
  PIN y[401]
    DIRECTION OUTPUT ;
    USE SIGNAL ;
    PORT
      LAYER M4 ;
        RECT  0 364.896 0.084 364.92 ;
    END
  END y[401]
  PIN y[402]
    DIRECTION OUTPUT ;
    USE SIGNAL ;
    PORT
      LAYER M4 ;
        RECT  0 365.088 0.084 365.112 ;
    END
  END y[402]
  PIN y[403]
    DIRECTION OUTPUT ;
    USE SIGNAL ;
    PORT
      LAYER M4 ;
        RECT  0 365.28 0.084 365.304 ;
    END
  END y[403]
  PIN y[404]
    DIRECTION OUTPUT ;
    USE SIGNAL ;
    PORT
      LAYER M4 ;
        RECT  0 365.472 0.084 365.496 ;
    END
  END y[404]
  PIN y[405]
    DIRECTION OUTPUT ;
    USE SIGNAL ;
    PORT
      LAYER M4 ;
        RECT  0 365.664 0.084 365.688 ;
    END
  END y[405]
  PIN y[406]
    DIRECTION OUTPUT ;
    USE SIGNAL ;
    PORT
      LAYER M4 ;
        RECT  0 365.856 0.084 365.88 ;
    END
  END y[406]
  PIN y[407]
    DIRECTION OUTPUT ;
    USE SIGNAL ;
    PORT
      LAYER M4 ;
        RECT  0 366.048 0.084 366.072 ;
    END
  END y[407]
  PIN y[408]
    DIRECTION OUTPUT ;
    USE SIGNAL ;
    PORT
      LAYER M4 ;
        RECT  0 366.24 0.084 366.264 ;
    END
  END y[408]
  PIN y[409]
    DIRECTION OUTPUT ;
    USE SIGNAL ;
    PORT
      LAYER M4 ;
        RECT  0 366.432 0.084 366.456 ;
    END
  END y[409]
  PIN y[40]
    DIRECTION OUTPUT ;
    USE SIGNAL ;
    PORT
      LAYER M4 ;
        RECT  0 43.152 0.084 43.176 ;
    END
  END y[40]
  PIN y[410]
    DIRECTION OUTPUT ;
    USE SIGNAL ;
    PORT
      LAYER M4 ;
        RECT  0 366.624 0.084 366.648 ;
    END
  END y[410]
  PIN y[411]
    DIRECTION OUTPUT ;
    USE SIGNAL ;
    PORT
      LAYER M4 ;
        RECT  0 366.816 0.084 366.84 ;
    END
  END y[411]
  PIN y[412]
    DIRECTION OUTPUT ;
    USE SIGNAL ;
    PORT
      LAYER M4 ;
        RECT  0 367.008 0.084 367.032 ;
    END
  END y[412]
  PIN y[413]
    DIRECTION OUTPUT ;
    USE SIGNAL ;
    PORT
      LAYER M4 ;
        RECT  0 367.2 0.084 367.224 ;
    END
  END y[413]
  PIN y[414]
    DIRECTION OUTPUT ;
    USE SIGNAL ;
    PORT
      LAYER M4 ;
        RECT  0 367.392 0.084 367.416 ;
    END
  END y[414]
  PIN y[415]
    DIRECTION OUTPUT ;
    USE SIGNAL ;
    PORT
      LAYER M4 ;
        RECT  0 367.584 0.084 367.608 ;
    END
  END y[415]
  PIN y[416]
    DIRECTION OUTPUT ;
    USE SIGNAL ;
    PORT
      LAYER M4 ;
        RECT  0 380.064 0.084 380.088 ;
    END
  END y[416]
  PIN y[417]
    DIRECTION OUTPUT ;
    USE SIGNAL ;
    PORT
      LAYER M4 ;
        RECT  0 380.256 0.084 380.28 ;
    END
  END y[417]
  PIN y[418]
    DIRECTION OUTPUT ;
    USE SIGNAL ;
    PORT
      LAYER M4 ;
        RECT  0 380.448 0.084 380.472 ;
    END
  END y[418]
  PIN y[419]
    DIRECTION OUTPUT ;
    USE SIGNAL ;
    PORT
      LAYER M4 ;
        RECT  0 380.64 0.084 380.664 ;
    END
  END y[419]
  PIN y[41]
    DIRECTION OUTPUT ;
    USE SIGNAL ;
    PORT
      LAYER M4 ;
        RECT  0 43.344 0.084 43.368 ;
    END
  END y[41]
  PIN y[420]
    DIRECTION OUTPUT ;
    USE SIGNAL ;
    PORT
      LAYER M4 ;
        RECT  0 380.832 0.084 380.856 ;
    END
  END y[420]
  PIN y[421]
    DIRECTION OUTPUT ;
    USE SIGNAL ;
    PORT
      LAYER M4 ;
        RECT  0 381.024 0.084 381.048 ;
    END
  END y[421]
  PIN y[422]
    DIRECTION OUTPUT ;
    USE SIGNAL ;
    PORT
      LAYER M4 ;
        RECT  0 381.216 0.084 381.24 ;
    END
  END y[422]
  PIN y[423]
    DIRECTION OUTPUT ;
    USE SIGNAL ;
    PORT
      LAYER M4 ;
        RECT  0 381.408 0.084 381.432 ;
    END
  END y[423]
  PIN y[424]
    DIRECTION OUTPUT ;
    USE SIGNAL ;
    PORT
      LAYER M4 ;
        RECT  0 381.6 0.084 381.624 ;
    END
  END y[424]
  PIN y[425]
    DIRECTION OUTPUT ;
    USE SIGNAL ;
    PORT
      LAYER M4 ;
        RECT  0 381.792 0.084 381.816 ;
    END
  END y[425]
  PIN y[426]
    DIRECTION OUTPUT ;
    USE SIGNAL ;
    PORT
      LAYER M4 ;
        RECT  0 381.984 0.084 382.008 ;
    END
  END y[426]
  PIN y[427]
    DIRECTION OUTPUT ;
    USE SIGNAL ;
    PORT
      LAYER M4 ;
        RECT  0 382.176 0.084 382.2 ;
    END
  END y[427]
  PIN y[428]
    DIRECTION OUTPUT ;
    USE SIGNAL ;
    PORT
      LAYER M4 ;
        RECT  0 382.368 0.084 382.392 ;
    END
  END y[428]
  PIN y[429]
    DIRECTION OUTPUT ;
    USE SIGNAL ;
    PORT
      LAYER M4 ;
        RECT  0 382.56 0.084 382.584 ;
    END
  END y[429]
  PIN y[42]
    DIRECTION OUTPUT ;
    USE SIGNAL ;
    PORT
      LAYER M4 ;
        RECT  0 43.536 0.084 43.56 ;
    END
  END y[42]
  PIN y[430]
    DIRECTION OUTPUT ;
    USE SIGNAL ;
    PORT
      LAYER M4 ;
        RECT  0 382.752 0.084 382.776 ;
    END
  END y[430]
  PIN y[431]
    DIRECTION OUTPUT ;
    USE SIGNAL ;
    PORT
      LAYER M4 ;
        RECT  0 382.944 0.084 382.968 ;
    END
  END y[431]
  PIN y[432]
    DIRECTION OUTPUT ;
    USE SIGNAL ;
    PORT
      LAYER M4 ;
        RECT  0 383.136 0.084 383.16 ;
    END
  END y[432]
  PIN y[433]
    DIRECTION OUTPUT ;
    USE SIGNAL ;
    PORT
      LAYER M4 ;
        RECT  0 383.328 0.084 383.352 ;
    END
  END y[433]
  PIN y[434]
    DIRECTION OUTPUT ;
    USE SIGNAL ;
    PORT
      LAYER M4 ;
        RECT  0 383.52 0.084 383.544 ;
    END
  END y[434]
  PIN y[435]
    DIRECTION OUTPUT ;
    USE SIGNAL ;
    PORT
      LAYER M4 ;
        RECT  0 383.712 0.084 383.736 ;
    END
  END y[435]
  PIN y[436]
    DIRECTION OUTPUT ;
    USE SIGNAL ;
    PORT
      LAYER M4 ;
        RECT  0 383.904 0.084 383.928 ;
    END
  END y[436]
  PIN y[437]
    DIRECTION OUTPUT ;
    USE SIGNAL ;
    PORT
      LAYER M4 ;
        RECT  0 384.096 0.084 384.12 ;
    END
  END y[437]
  PIN y[438]
    DIRECTION OUTPUT ;
    USE SIGNAL ;
    PORT
      LAYER M4 ;
        RECT  0 384.288 0.084 384.312 ;
    END
  END y[438]
  PIN y[439]
    DIRECTION OUTPUT ;
    USE SIGNAL ;
    PORT
      LAYER M4 ;
        RECT  0 384.48 0.084 384.504 ;
    END
  END y[439]
  PIN y[43]
    DIRECTION OUTPUT ;
    USE SIGNAL ;
    PORT
      LAYER M4 ;
        RECT  0 43.728 0.084 43.752 ;
    END
  END y[43]
  PIN y[440]
    DIRECTION OUTPUT ;
    USE SIGNAL ;
    PORT
      LAYER M4 ;
        RECT  0 384.672 0.084 384.696 ;
    END
  END y[440]
  PIN y[441]
    DIRECTION OUTPUT ;
    USE SIGNAL ;
    PORT
      LAYER M4 ;
        RECT  0 384.864 0.084 384.888 ;
    END
  END y[441]
  PIN y[442]
    DIRECTION OUTPUT ;
    USE SIGNAL ;
    PORT
      LAYER M4 ;
        RECT  0 385.056 0.084 385.08 ;
    END
  END y[442]
  PIN y[443]
    DIRECTION OUTPUT ;
    USE SIGNAL ;
    PORT
      LAYER M4 ;
        RECT  0 385.248 0.084 385.272 ;
    END
  END y[443]
  PIN y[444]
    DIRECTION OUTPUT ;
    USE SIGNAL ;
    PORT
      LAYER M4 ;
        RECT  0 385.44 0.084 385.464 ;
    END
  END y[444]
  PIN y[445]
    DIRECTION OUTPUT ;
    USE SIGNAL ;
    PORT
      LAYER M4 ;
        RECT  0 385.632 0.084 385.656 ;
    END
  END y[445]
  PIN y[446]
    DIRECTION OUTPUT ;
    USE SIGNAL ;
    PORT
      LAYER M4 ;
        RECT  0 385.824 0.084 385.848 ;
    END
  END y[446]
  PIN y[447]
    DIRECTION OUTPUT ;
    USE SIGNAL ;
    PORT
      LAYER M4 ;
        RECT  0 386.016 0.084 386.04 ;
    END
  END y[447]
  PIN y[448]
    DIRECTION OUTPUT ;
    USE SIGNAL ;
    PORT
      LAYER M4 ;
        RECT  0 398.496 0.084 398.52 ;
    END
  END y[448]
  PIN y[449]
    DIRECTION OUTPUT ;
    USE SIGNAL ;
    PORT
      LAYER M4 ;
        RECT  0 398.688 0.084 398.712 ;
    END
  END y[449]
  PIN y[44]
    DIRECTION OUTPUT ;
    USE SIGNAL ;
    PORT
      LAYER M4 ;
        RECT  0 43.92 0.084 43.944 ;
    END
  END y[44]
  PIN y[450]
    DIRECTION OUTPUT ;
    USE SIGNAL ;
    PORT
      LAYER M4 ;
        RECT  0 398.88 0.084 398.904 ;
    END
  END y[450]
  PIN y[451]
    DIRECTION OUTPUT ;
    USE SIGNAL ;
    PORT
      LAYER M4 ;
        RECT  0 399.072 0.084 399.096 ;
    END
  END y[451]
  PIN y[452]
    DIRECTION OUTPUT ;
    USE SIGNAL ;
    PORT
      LAYER M4 ;
        RECT  0 399.264 0.084 399.288 ;
    END
  END y[452]
  PIN y[453]
    DIRECTION OUTPUT ;
    USE SIGNAL ;
    PORT
      LAYER M4 ;
        RECT  0 399.456 0.084 399.48 ;
    END
  END y[453]
  PIN y[454]
    DIRECTION OUTPUT ;
    USE SIGNAL ;
    PORT
      LAYER M4 ;
        RECT  0 399.648 0.084 399.672 ;
    END
  END y[454]
  PIN y[455]
    DIRECTION OUTPUT ;
    USE SIGNAL ;
    PORT
      LAYER M4 ;
        RECT  0 399.84 0.084 399.864 ;
    END
  END y[455]
  PIN y[456]
    DIRECTION OUTPUT ;
    USE SIGNAL ;
    PORT
      LAYER M4 ;
        RECT  0 400.032 0.084 400.056 ;
    END
  END y[456]
  PIN y[457]
    DIRECTION OUTPUT ;
    USE SIGNAL ;
    PORT
      LAYER M4 ;
        RECT  0 400.224 0.084 400.248 ;
    END
  END y[457]
  PIN y[458]
    DIRECTION OUTPUT ;
    USE SIGNAL ;
    PORT
      LAYER M4 ;
        RECT  0 400.416 0.084 400.44 ;
    END
  END y[458]
  PIN y[459]
    DIRECTION OUTPUT ;
    USE SIGNAL ;
    PORT
      LAYER M4 ;
        RECT  0 400.608 0.084 400.632 ;
    END
  END y[459]
  PIN y[45]
    DIRECTION OUTPUT ;
    USE SIGNAL ;
    PORT
      LAYER M4 ;
        RECT  0 44.112 0.084 44.136 ;
    END
  END y[45]
  PIN y[460]
    DIRECTION OUTPUT ;
    USE SIGNAL ;
    PORT
      LAYER M4 ;
        RECT  0 400.8 0.084 400.824 ;
    END
  END y[460]
  PIN y[461]
    DIRECTION OUTPUT ;
    USE SIGNAL ;
    PORT
      LAYER M4 ;
        RECT  0 400.992 0.084 401.016 ;
    END
  END y[461]
  PIN y[462]
    DIRECTION OUTPUT ;
    USE SIGNAL ;
    PORT
      LAYER M4 ;
        RECT  0 401.184 0.084 401.208 ;
    END
  END y[462]
  PIN y[463]
    DIRECTION OUTPUT ;
    USE SIGNAL ;
    PORT
      LAYER M4 ;
        RECT  0 401.376 0.084 401.4 ;
    END
  END y[463]
  PIN y[464]
    DIRECTION OUTPUT ;
    USE SIGNAL ;
    PORT
      LAYER M4 ;
        RECT  0 401.568 0.084 401.592 ;
    END
  END y[464]
  PIN y[465]
    DIRECTION OUTPUT ;
    USE SIGNAL ;
    PORT
      LAYER M4 ;
        RECT  0 401.76 0.084 401.784 ;
    END
  END y[465]
  PIN y[466]
    DIRECTION OUTPUT ;
    USE SIGNAL ;
    PORT
      LAYER M4 ;
        RECT  0 401.952 0.084 401.976 ;
    END
  END y[466]
  PIN y[467]
    DIRECTION OUTPUT ;
    USE SIGNAL ;
    PORT
      LAYER M4 ;
        RECT  0 402.144 0.084 402.168 ;
    END
  END y[467]
  PIN y[468]
    DIRECTION OUTPUT ;
    USE SIGNAL ;
    PORT
      LAYER M4 ;
        RECT  0 402.336 0.084 402.36 ;
    END
  END y[468]
  PIN y[469]
    DIRECTION OUTPUT ;
    USE SIGNAL ;
    PORT
      LAYER M4 ;
        RECT  0 402.528 0.084 402.552 ;
    END
  END y[469]
  PIN y[46]
    DIRECTION OUTPUT ;
    USE SIGNAL ;
    PORT
      LAYER M4 ;
        RECT  0 44.304 0.084 44.328 ;
    END
  END y[46]
  PIN y[470]
    DIRECTION OUTPUT ;
    USE SIGNAL ;
    PORT
      LAYER M4 ;
        RECT  0 402.72 0.084 402.744 ;
    END
  END y[470]
  PIN y[471]
    DIRECTION OUTPUT ;
    USE SIGNAL ;
    PORT
      LAYER M4 ;
        RECT  0 402.912 0.084 402.936 ;
    END
  END y[471]
  PIN y[472]
    DIRECTION OUTPUT ;
    USE SIGNAL ;
    PORT
      LAYER M4 ;
        RECT  0 403.104 0.084 403.128 ;
    END
  END y[472]
  PIN y[473]
    DIRECTION OUTPUT ;
    USE SIGNAL ;
    PORT
      LAYER M4 ;
        RECT  0 403.296 0.084 403.32 ;
    END
  END y[473]
  PIN y[474]
    DIRECTION OUTPUT ;
    USE SIGNAL ;
    PORT
      LAYER M4 ;
        RECT  0 403.488 0.084 403.512 ;
    END
  END y[474]
  PIN y[475]
    DIRECTION OUTPUT ;
    USE SIGNAL ;
    PORT
      LAYER M4 ;
        RECT  0 403.68 0.084 403.704 ;
    END
  END y[475]
  PIN y[476]
    DIRECTION OUTPUT ;
    USE SIGNAL ;
    PORT
      LAYER M4 ;
        RECT  0 403.872 0.084 403.896 ;
    END
  END y[476]
  PIN y[477]
    DIRECTION OUTPUT ;
    USE SIGNAL ;
    PORT
      LAYER M4 ;
        RECT  0 404.064 0.084 404.088 ;
    END
  END y[477]
  PIN y[478]
    DIRECTION OUTPUT ;
    USE SIGNAL ;
    PORT
      LAYER M4 ;
        RECT  0 404.256 0.084 404.28 ;
    END
  END y[478]
  PIN y[479]
    DIRECTION OUTPUT ;
    USE SIGNAL ;
    PORT
      LAYER M4 ;
        RECT  0 404.448 0.084 404.472 ;
    END
  END y[479]
  PIN y[47]
    DIRECTION OUTPUT ;
    USE SIGNAL ;
    PORT
      LAYER M4 ;
        RECT  0 44.496 0.084 44.52 ;
    END
  END y[47]
  PIN y[480]
    DIRECTION OUTPUT ;
    USE SIGNAL ;
    PORT
      LAYER M4 ;
        RECT  0 416.928 0.084 416.952 ;
    END
  END y[480]
  PIN y[481]
    DIRECTION OUTPUT ;
    USE SIGNAL ;
    PORT
      LAYER M4 ;
        RECT  0 417.12 0.084 417.144 ;
    END
  END y[481]
  PIN y[482]
    DIRECTION OUTPUT ;
    USE SIGNAL ;
    PORT
      LAYER M4 ;
        RECT  0 417.312 0.084 417.336 ;
    END
  END y[482]
  PIN y[483]
    DIRECTION OUTPUT ;
    USE SIGNAL ;
    PORT
      LAYER M4 ;
        RECT  0 417.504 0.084 417.528 ;
    END
  END y[483]
  PIN y[484]
    DIRECTION OUTPUT ;
    USE SIGNAL ;
    PORT
      LAYER M4 ;
        RECT  0 417.696 0.084 417.72 ;
    END
  END y[484]
  PIN y[485]
    DIRECTION OUTPUT ;
    USE SIGNAL ;
    PORT
      LAYER M4 ;
        RECT  0 417.888 0.084 417.912 ;
    END
  END y[485]
  PIN y[486]
    DIRECTION OUTPUT ;
    USE SIGNAL ;
    PORT
      LAYER M4 ;
        RECT  0 418.08 0.084 418.104 ;
    END
  END y[486]
  PIN y[487]
    DIRECTION OUTPUT ;
    USE SIGNAL ;
    PORT
      LAYER M4 ;
        RECT  0 418.272 0.084 418.296 ;
    END
  END y[487]
  PIN y[488]
    DIRECTION OUTPUT ;
    USE SIGNAL ;
    PORT
      LAYER M4 ;
        RECT  0 418.464 0.084 418.488 ;
    END
  END y[488]
  PIN y[489]
    DIRECTION OUTPUT ;
    USE SIGNAL ;
    PORT
      LAYER M4 ;
        RECT  0 418.656 0.084 418.68 ;
    END
  END y[489]
  PIN y[48]
    DIRECTION OUTPUT ;
    USE SIGNAL ;
    PORT
      LAYER M4 ;
        RECT  0 44.688 0.084 44.712 ;
    END
  END y[48]
  PIN y[490]
    DIRECTION OUTPUT ;
    USE SIGNAL ;
    PORT
      LAYER M4 ;
        RECT  0 418.848 0.084 418.872 ;
    END
  END y[490]
  PIN y[491]
    DIRECTION OUTPUT ;
    USE SIGNAL ;
    PORT
      LAYER M4 ;
        RECT  0 419.04 0.084 419.064 ;
    END
  END y[491]
  PIN y[492]
    DIRECTION OUTPUT ;
    USE SIGNAL ;
    PORT
      LAYER M4 ;
        RECT  0 419.232 0.084 419.256 ;
    END
  END y[492]
  PIN y[493]
    DIRECTION OUTPUT ;
    USE SIGNAL ;
    PORT
      LAYER M4 ;
        RECT  0 419.424 0.084 419.448 ;
    END
  END y[493]
  PIN y[494]
    DIRECTION OUTPUT ;
    USE SIGNAL ;
    PORT
      LAYER M4 ;
        RECT  0 419.616 0.084 419.64 ;
    END
  END y[494]
  PIN y[495]
    DIRECTION OUTPUT ;
    USE SIGNAL ;
    PORT
      LAYER M4 ;
        RECT  0 419.808 0.084 419.832 ;
    END
  END y[495]
  PIN y[496]
    DIRECTION OUTPUT ;
    USE SIGNAL ;
    PORT
      LAYER M4 ;
        RECT  0 420 0.084 420.024 ;
    END
  END y[496]
  PIN y[497]
    DIRECTION OUTPUT ;
    USE SIGNAL ;
    PORT
      LAYER M4 ;
        RECT  0 420.192 0.084 420.216 ;
    END
  END y[497]
  PIN y[498]
    DIRECTION OUTPUT ;
    USE SIGNAL ;
    PORT
      LAYER M4 ;
        RECT  0 420.384 0.084 420.408 ;
    END
  END y[498]
  PIN y[499]
    DIRECTION OUTPUT ;
    USE SIGNAL ;
    PORT
      LAYER M4 ;
        RECT  0 420.576 0.084 420.6 ;
    END
  END y[499]
  PIN y[49]
    DIRECTION OUTPUT ;
    USE SIGNAL ;
    PORT
      LAYER M4 ;
        RECT  0 44.88 0.084 44.904 ;
    END
  END y[49]
  PIN y[4]
    DIRECTION OUTPUT ;
    USE SIGNAL ;
    PORT
      LAYER M4 ;
        RECT  0 23.952 0.084 23.976 ;
    END
  END y[4]
  PIN y[500]
    DIRECTION OUTPUT ;
    USE SIGNAL ;
    PORT
      LAYER M4 ;
        RECT  0 420.768 0.084 420.792 ;
    END
  END y[500]
  PIN y[501]
    DIRECTION OUTPUT ;
    USE SIGNAL ;
    PORT
      LAYER M4 ;
        RECT  0 420.96 0.084 420.984 ;
    END
  END y[501]
  PIN y[502]
    DIRECTION OUTPUT ;
    USE SIGNAL ;
    PORT
      LAYER M4 ;
        RECT  0 421.152 0.084 421.176 ;
    END
  END y[502]
  PIN y[503]
    DIRECTION OUTPUT ;
    USE SIGNAL ;
    PORT
      LAYER M4 ;
        RECT  0 421.344 0.084 421.368 ;
    END
  END y[503]
  PIN y[504]
    DIRECTION OUTPUT ;
    USE SIGNAL ;
    PORT
      LAYER M4 ;
        RECT  0 421.536 0.084 421.56 ;
    END
  END y[504]
  PIN y[505]
    DIRECTION OUTPUT ;
    USE SIGNAL ;
    PORT
      LAYER M4 ;
        RECT  0 421.728 0.084 421.752 ;
    END
  END y[505]
  PIN y[506]
    DIRECTION OUTPUT ;
    USE SIGNAL ;
    PORT
      LAYER M4 ;
        RECT  0 421.92 0.084 421.944 ;
    END
  END y[506]
  PIN y[507]
    DIRECTION OUTPUT ;
    USE SIGNAL ;
    PORT
      LAYER M4 ;
        RECT  0 422.112 0.084 422.136 ;
    END
  END y[507]
  PIN y[508]
    DIRECTION OUTPUT ;
    USE SIGNAL ;
    PORT
      LAYER M4 ;
        RECT  0 422.304 0.084 422.328 ;
    END
  END y[508]
  PIN y[509]
    DIRECTION OUTPUT ;
    USE SIGNAL ;
    PORT
      LAYER M4 ;
        RECT  0 422.496 0.084 422.52 ;
    END
  END y[509]
  PIN y[50]
    DIRECTION OUTPUT ;
    USE SIGNAL ;
    PORT
      LAYER M4 ;
        RECT  0 45.072 0.084 45.096 ;
    END
  END y[50]
  PIN y[510]
    DIRECTION OUTPUT ;
    USE SIGNAL ;
    PORT
      LAYER M4 ;
        RECT  0 422.688 0.084 422.712 ;
    END
  END y[510]
  PIN y[511]
    DIRECTION OUTPUT ;
    USE SIGNAL ;
    PORT
      LAYER M4 ;
        RECT  0 422.88 0.084 422.904 ;
    END
  END y[511]
  PIN y[51]
    DIRECTION OUTPUT ;
    USE SIGNAL ;
    PORT
      LAYER M4 ;
        RECT  0 45.264 0.084 45.288 ;
    END
  END y[51]
  PIN y[52]
    DIRECTION OUTPUT ;
    USE SIGNAL ;
    PORT
      LAYER M4 ;
        RECT  0 45.456 0.084 45.48 ;
    END
  END y[52]
  PIN y[53]
    DIRECTION OUTPUT ;
    USE SIGNAL ;
    PORT
      LAYER M4 ;
        RECT  0 45.648 0.084 45.672 ;
    END
  END y[53]
  PIN y[54]
    DIRECTION OUTPUT ;
    USE SIGNAL ;
    PORT
      LAYER M4 ;
        RECT  0 45.84 0.084 45.864 ;
    END
  END y[54]
  PIN y[55]
    DIRECTION OUTPUT ;
    USE SIGNAL ;
    PORT
      LAYER M4 ;
        RECT  0 46.032 0.084 46.056 ;
    END
  END y[55]
  PIN y[56]
    DIRECTION OUTPUT ;
    USE SIGNAL ;
    PORT
      LAYER M4 ;
        RECT  0 46.224 0.084 46.248 ;
    END
  END y[56]
  PIN y[57]
    DIRECTION OUTPUT ;
    USE SIGNAL ;
    PORT
      LAYER M4 ;
        RECT  0 46.416 0.084 46.44 ;
    END
  END y[57]
  PIN y[58]
    DIRECTION OUTPUT ;
    USE SIGNAL ;
    PORT
      LAYER M4 ;
        RECT  0 46.608 0.084 46.632 ;
    END
  END y[58]
  PIN y[59]
    DIRECTION OUTPUT ;
    USE SIGNAL ;
    PORT
      LAYER M4 ;
        RECT  0 46.8 0.084 46.824 ;
    END
  END y[59]
  PIN y[5]
    DIRECTION OUTPUT ;
    USE SIGNAL ;
    PORT
      LAYER M4 ;
        RECT  0 24.144 0.084 24.168 ;
    END
  END y[5]
  PIN y[60]
    DIRECTION OUTPUT ;
    USE SIGNAL ;
    PORT
      LAYER M4 ;
        RECT  0 46.992 0.084 47.016 ;
    END
  END y[60]
  PIN y[61]
    DIRECTION OUTPUT ;
    USE SIGNAL ;
    PORT
      LAYER M4 ;
        RECT  0 47.184 0.084 47.208 ;
    END
  END y[61]
  PIN y[62]
    DIRECTION OUTPUT ;
    USE SIGNAL ;
    PORT
      LAYER M4 ;
        RECT  0 47.376 0.084 47.4 ;
    END
  END y[62]
  PIN y[63]
    DIRECTION OUTPUT ;
    USE SIGNAL ;
    PORT
      LAYER M4 ;
        RECT  0 47.568 0.084 47.592 ;
    END
  END y[63]
  PIN y[64]
    DIRECTION OUTPUT ;
    USE SIGNAL ;
    PORT
      LAYER M4 ;
        RECT  0 60.048 0.084 60.072 ;
    END
  END y[64]
  PIN y[65]
    DIRECTION OUTPUT ;
    USE SIGNAL ;
    PORT
      LAYER M4 ;
        RECT  0 60.24 0.084 60.264 ;
    END
  END y[65]
  PIN y[66]
    DIRECTION OUTPUT ;
    USE SIGNAL ;
    PORT
      LAYER M4 ;
        RECT  0 60.432 0.084 60.456 ;
    END
  END y[66]
  PIN y[67]
    DIRECTION OUTPUT ;
    USE SIGNAL ;
    PORT
      LAYER M4 ;
        RECT  0 60.624 0.084 60.648 ;
    END
  END y[67]
  PIN y[68]
    DIRECTION OUTPUT ;
    USE SIGNAL ;
    PORT
      LAYER M4 ;
        RECT  0 60.816 0.084 60.84 ;
    END
  END y[68]
  PIN y[69]
    DIRECTION OUTPUT ;
    USE SIGNAL ;
    PORT
      LAYER M4 ;
        RECT  0 61.008 0.084 61.032 ;
    END
  END y[69]
  PIN y[6]
    DIRECTION OUTPUT ;
    USE SIGNAL ;
    PORT
      LAYER M4 ;
        RECT  0 24.336 0.084 24.36 ;
    END
  END y[6]
  PIN y[70]
    DIRECTION OUTPUT ;
    USE SIGNAL ;
    PORT
      LAYER M4 ;
        RECT  0 61.2 0.084 61.224 ;
    END
  END y[70]
  PIN y[71]
    DIRECTION OUTPUT ;
    USE SIGNAL ;
    PORT
      LAYER M4 ;
        RECT  0 61.392 0.084 61.416 ;
    END
  END y[71]
  PIN y[72]
    DIRECTION OUTPUT ;
    USE SIGNAL ;
    PORT
      LAYER M4 ;
        RECT  0 61.584 0.084 61.608 ;
    END
  END y[72]
  PIN y[73]
    DIRECTION OUTPUT ;
    USE SIGNAL ;
    PORT
      LAYER M4 ;
        RECT  0 61.776 0.084 61.8 ;
    END
  END y[73]
  PIN y[74]
    DIRECTION OUTPUT ;
    USE SIGNAL ;
    PORT
      LAYER M4 ;
        RECT  0 61.968 0.084 61.992 ;
    END
  END y[74]
  PIN y[75]
    DIRECTION OUTPUT ;
    USE SIGNAL ;
    PORT
      LAYER M4 ;
        RECT  0 62.16 0.084 62.184 ;
    END
  END y[75]
  PIN y[76]
    DIRECTION OUTPUT ;
    USE SIGNAL ;
    PORT
      LAYER M4 ;
        RECT  0 62.352 0.084 62.376 ;
    END
  END y[76]
  PIN y[77]
    DIRECTION OUTPUT ;
    USE SIGNAL ;
    PORT
      LAYER M4 ;
        RECT  0 62.544 0.084 62.568 ;
    END
  END y[77]
  PIN y[78]
    DIRECTION OUTPUT ;
    USE SIGNAL ;
    PORT
      LAYER M4 ;
        RECT  0 62.736 0.084 62.76 ;
    END
  END y[78]
  PIN y[79]
    DIRECTION OUTPUT ;
    USE SIGNAL ;
    PORT
      LAYER M4 ;
        RECT  0 62.928 0.084 62.952 ;
    END
  END y[79]
  PIN y[7]
    DIRECTION OUTPUT ;
    USE SIGNAL ;
    PORT
      LAYER M4 ;
        RECT  0 24.528 0.084 24.552 ;
    END
  END y[7]
  PIN y[80]
    DIRECTION OUTPUT ;
    USE SIGNAL ;
    PORT
      LAYER M4 ;
        RECT  0 63.12 0.084 63.144 ;
    END
  END y[80]
  PIN y[81]
    DIRECTION OUTPUT ;
    USE SIGNAL ;
    PORT
      LAYER M4 ;
        RECT  0 63.312 0.084 63.336 ;
    END
  END y[81]
  PIN y[82]
    DIRECTION OUTPUT ;
    USE SIGNAL ;
    PORT
      LAYER M4 ;
        RECT  0 63.504 0.084 63.528 ;
    END
  END y[82]
  PIN y[83]
    DIRECTION OUTPUT ;
    USE SIGNAL ;
    PORT
      LAYER M4 ;
        RECT  0 63.696 0.084 63.72 ;
    END
  END y[83]
  PIN y[84]
    DIRECTION OUTPUT ;
    USE SIGNAL ;
    PORT
      LAYER M4 ;
        RECT  0 63.888 0.084 63.912 ;
    END
  END y[84]
  PIN y[85]
    DIRECTION OUTPUT ;
    USE SIGNAL ;
    PORT
      LAYER M4 ;
        RECT  0 64.08 0.084 64.104 ;
    END
  END y[85]
  PIN y[86]
    DIRECTION OUTPUT ;
    USE SIGNAL ;
    PORT
      LAYER M4 ;
        RECT  0 64.272 0.084 64.296 ;
    END
  END y[86]
  PIN y[87]
    DIRECTION OUTPUT ;
    USE SIGNAL ;
    PORT
      LAYER M4 ;
        RECT  0 64.464 0.084 64.488 ;
    END
  END y[87]
  PIN y[88]
    DIRECTION OUTPUT ;
    USE SIGNAL ;
    PORT
      LAYER M4 ;
        RECT  0 64.656 0.084 64.68 ;
    END
  END y[88]
  PIN y[89]
    DIRECTION OUTPUT ;
    USE SIGNAL ;
    PORT
      LAYER M4 ;
        RECT  0 64.848 0.084 64.872 ;
    END
  END y[89]
  PIN y[8]
    DIRECTION OUTPUT ;
    USE SIGNAL ;
    PORT
      LAYER M4 ;
        RECT  0 24.72 0.084 24.744 ;
    END
  END y[8]
  PIN y[90]
    DIRECTION OUTPUT ;
    USE SIGNAL ;
    PORT
      LAYER M4 ;
        RECT  0 65.04 0.084 65.064 ;
    END
  END y[90]
  PIN y[91]
    DIRECTION OUTPUT ;
    USE SIGNAL ;
    PORT
      LAYER M4 ;
        RECT  0 65.232 0.084 65.256 ;
    END
  END y[91]
  PIN y[92]
    DIRECTION OUTPUT ;
    USE SIGNAL ;
    PORT
      LAYER M4 ;
        RECT  0 65.424 0.084 65.448 ;
    END
  END y[92]
  PIN y[93]
    DIRECTION OUTPUT ;
    USE SIGNAL ;
    PORT
      LAYER M4 ;
        RECT  0 65.616 0.084 65.64 ;
    END
  END y[93]
  PIN y[94]
    DIRECTION OUTPUT ;
    USE SIGNAL ;
    PORT
      LAYER M4 ;
        RECT  0 65.808 0.084 65.832 ;
    END
  END y[94]
  PIN y[95]
    DIRECTION OUTPUT ;
    USE SIGNAL ;
    PORT
      LAYER M4 ;
        RECT  0 66 0.084 66.024 ;
    END
  END y[95]
  PIN y[96]
    DIRECTION OUTPUT ;
    USE SIGNAL ;
    PORT
      LAYER M4 ;
        RECT  0 78.48 0.084 78.504 ;
    END
  END y[96]
  PIN y[97]
    DIRECTION OUTPUT ;
    USE SIGNAL ;
    PORT
      LAYER M4 ;
        RECT  0 78.672 0.084 78.696 ;
    END
  END y[97]
  PIN y[98]
    DIRECTION OUTPUT ;
    USE SIGNAL ;
    PORT
      LAYER M4 ;
        RECT  0 78.864 0.084 78.888 ;
    END
  END y[98]
  PIN y[99]
    DIRECTION OUTPUT ;
    USE SIGNAL ;
    PORT
      LAYER M4 ;
        RECT  0 79.056 0.084 79.08 ;
    END
  END y[99]
  PIN y[9]
    DIRECTION OUTPUT ;
    USE SIGNAL ;
    PORT
      LAYER M4 ;
        RECT  0 24.912 0.084 24.936 ;
    END
  END y[9]
  PIN VDD
    DIRECTION INOUT ;
    USE POWER ;
    PORT
      LAYER M5 ;
        RECT  41.076 4.311 41.196 427.689 ;
        RECT  36.756 4.311 36.876 427.689 ;
        RECT  32.436 4.311 32.556 427.689 ;
        RECT  28.116 4.311 28.236 427.689 ;
        RECT  23.796 216.312 23.916 427.689 ;
        RECT  23.796 4.311 23.916 215.688 ;
        RECT  19.476 4.311 19.596 427.689 ;
        RECT  15.156 4.311 15.276 427.689 ;
        RECT  10.836 4.311 10.956 427.689 ;
        RECT  6.516 4.311 6.636 427.689 ;
    END
  END VDD
  PIN VSS
    DIRECTION INOUT ;
    USE GROUND ;
    PORT
      LAYER M5 ;
        RECT  40.884 4.297 41.004 427.703 ;
        RECT  36.564 4.297 36.684 427.703 ;
        RECT  32.244 4.297 32.364 427.703 ;
        RECT  27.924 4.297 28.044 427.703 ;
        RECT  23.604 216.312 23.724 427.703 ;
        RECT  23.604 4.297 23.724 215.688 ;
        RECT  19.284 4.297 19.404 427.703 ;
        RECT  14.964 4.297 15.084 427.703 ;
        RECT  10.644 4.297 10.764 427.703 ;
        RECT  6.324 4.297 6.444 427.703 ;
    END
  END VSS
  OBS
    LAYER RVTN ;
     RECT  0 4.297 47.52 427.703 ;
    LAYER RVTP ;
     RECT  0 4.297 47.52 427.703 ;
    LAYER M1 ;
     RECT  0 4.297 47.52 427.703 ;
    LAYER M2 ;
     RECT  0 4.297 47.52 427.703 ;
    LAYER M3 ;
     RECT  0 4.297 47.52 427.703 ;
    LAYER M4 ;
     RECT  0 4.297 47.52 427.703 ;
    LAYER M5 ;
     RECT  0 4.297 47.52 427.703 ;
  END
END ot_qwen_tile_node
END LIBRARY
